# Confidential Information of ARM, Inc.
# Use subject to ARM license.
# Copyright (c) 2026 ARM, Inc.

# ACI Version r0p0

# Reifier 4.0.0

VERSION 5.7 ;

BUSBITCHARS "[]" ;

#name: High Density Single Port SRAM HVT RVT Compiler | TSMC CLN65LP Process 0.525um^2 Bit Cell 256 Rows Per Bank
#version: r0p0
#comment: 
#configuration:  -activity_factor 50 -back_biasing off -bits 64 -bmux on -bus_notation on -check_instname on -diodes on -drive 6 -ema on -frequency 250 -instname s8192x64 -left_bus_delim "[" -mux 16 -mvt "" -name_case upper -power_type otc -prefix "" -pwr_gnd_rename vddpe:VDDPE,vddce:VDDCE,vsse:VSSE -rcols 2 -redundancy off -retention on -right_bus_delim "]" -rows_p_bl 256 -rrows 0 -ser none -site_def off -top_layer m5-m9 -words 8192 -wp_size 1 -write_mask off -write_thru off -corners tt_1p20v_1p20v_25c
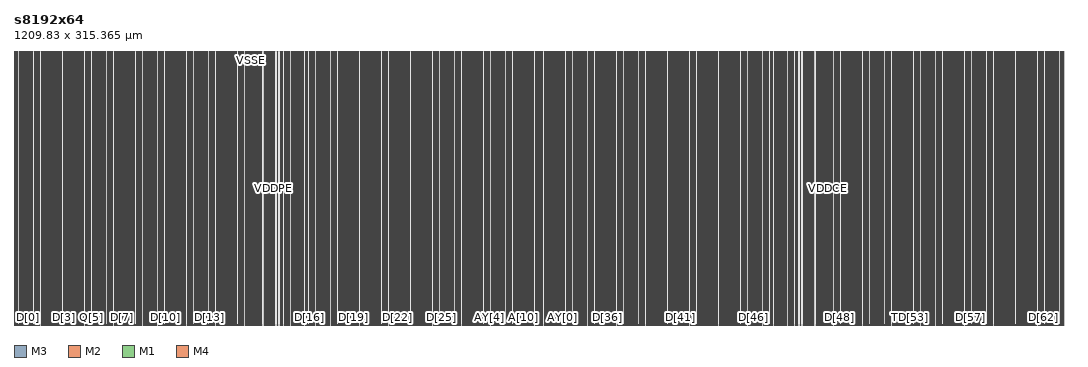
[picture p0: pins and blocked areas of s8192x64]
MACRO s8192x64
  FOREIGN s8192x64 0 0 ;
  SYMMETRY X Y R90 ;
  SIZE 1209.83 BY 315.365 ;
  CLASS BLOCK ;
  PIN TD[31]
    DIRECTION INPUT ;
    USE SIGNAL ;
    SHAPE ABUTMENT ;
    PORT
      LAYER M3 ;
      RECT 595.035 0.0 595.235 0.32 ;
      LAYER M2 ;
      RECT 595.035 0.0 595.235 0.32 ;
      LAYER M1 ;
      RECT 595.035 0.0 595.235 0.32 ;
      END
    ANTENNAGATEAREA 0.0072 ;
    ANTENNADIFFAREA 0.054 ;
    END TD[31]
  PIN AY[12]
    DIRECTION OUTPUT ;
    USE SIGNAL ;
    SHAPE ABUTMENT ;
    PORT
      LAYER M1 ;
      RECT 596.765 0.0 596.965 0.32 ;
      LAYER M2 ;
      RECT 596.765 0.0 596.965 0.32 ;
      LAYER M3 ;
      RECT 596.765 0.0 596.965 0.32 ;
      END
    ANTENNADIFFAREA 0.054 ;
    END AY[12]
  PIN A[11]
    DIRECTION INPUT ;
    USE SIGNAL ;
    SHAPE ABUTMENT ;
    PORT
      LAYER M3 ;
      RECT 593.235 0.0 593.435 0.32 ;
      LAYER M2 ;
      RECT 593.235 0.0 593.435 0.32 ;
      LAYER M1 ;
      RECT 593.235 0.0 593.435 0.32 ;
      END
    ANTENNAGATEAREA 0.0072 ;
    ANTENNADIFFAREA 0.054 ;
    END A[11]
  PIN A[12]
    DIRECTION INPUT ;
    USE SIGNAL ;
    SHAPE ABUTMENT ;
    PORT
      LAYER M1 ;
      RECT 597.57 0.0 597.77 0.32 ;
      LAYER M2 ;
      RECT 597.57 0.0 597.77 0.32 ;
      LAYER M3 ;
      RECT 597.57 0.0 597.77 0.32 ;
      END
    ANTENNAGATEAREA 0.0072 ;
    ANTENNADIFFAREA 0.054 ;
    END A[12]
  PIN D[31]
    DIRECTION INPUT ;
    USE SIGNAL ;
    SHAPE ABUTMENT ;
    PORT
      LAYER M4 ;
      RECT 592.795 0.0 592.995 0.32 ;
      LAYER M3 ;
      RECT 592.795 0.0 592.995 0.32 ;
      LAYER M2 ;
      RECT 592.795 0.0 592.995 0.32 ;
      LAYER M1 ;
      RECT 592.795 0.0 592.995 0.32 ;
      END
    ANTENNAGATEAREA 0.0072 ;
    ANTENNADIFFAREA 0.054 ;
    END D[31]
  PIN TA[12]
    DIRECTION INPUT ;
    USE SIGNAL ;
    SHAPE ABUTMENT ;
    PORT
      LAYER M1 ;
      RECT 597.95 0.0 598.15 0.32 ;
      LAYER M2 ;
      RECT 597.95 0.0 598.15 0.32 ;
      END
    ANTENNAGATEAREA 0.0072 ;
    ANTENNADIFFAREA 0.054 ;
    END TA[12]
  PIN TA[11]
    DIRECTION INPUT ;
    USE SIGNAL ;
    SHAPE ABUTMENT ;
    PORT
      LAYER M3 ;
      RECT 592.285 0.0 592.485 0.32 ;
      LAYER M2 ;
      RECT 592.285 0.0 592.485 0.32 ;
      LAYER M1 ;
      RECT 592.285 0.0 592.485 0.32 ;
      END
    ANTENNAGATEAREA 0.0072 ;
    ANTENNADIFFAREA 0.054 ;
    END TA[11]
  PIN SO[0]
    DIRECTION OUTPUT ;
    USE SIGNAL ;
    SHAPE ABUTMENT ;
    PORT
      LAYER M1 ;
      RECT 602.525 0.0 602.725 0.32 ;
      LAYER M2 ;
      RECT 602.525 0.0 602.725 0.32 ;
      LAYER M3 ;
      RECT 602.525 0.0 602.725 0.32 ;
      END
    ANTENNADIFFAREA 0.054 ;
    END SO[0]
  PIN Q[31]
    DIRECTION OUTPUT ;
    USE SIGNAL ;
    SHAPE ABUTMENT ;
    PORT
      LAYER M3 ;
      RECT 591.2 0.0 591.41 0.32 ;
      LAYER M2 ;
      RECT 591.2 0.0 591.41 0.32 ;
      LAYER M1 ;
      RECT 591.2 0.0 591.41 0.32 ;
      END
    ANTENNADIFFAREA 0.054 ;
    END Q[31]
  PIN SO[1]
    DIRECTION OUTPUT ;
    USE SIGNAL ;
    SHAPE ABUTMENT ;
    PORT
      LAYER M1 ;
      RECT 606.825 0.0 607.025 0.32 ;
      LAYER M2 ;
      RECT 606.825 0.0 607.025 0.32 ;
      LAYER M3 ;
      RECT 606.825 0.0 607.025 0.32 ;
      END
    ANTENNADIFFAREA 0.054 ;
    END SO[1]
  PIN AY[11]
    DIRECTION OUTPUT ;
    USE SIGNAL ;
    SHAPE ABUTMENT ;
    PORT
      LAYER M3 ;
      RECT 590.235 0.0 590.435 0.32 ;
      LAYER M2 ;
      RECT 590.235 0.0 590.435 0.32 ;
      LAYER M1 ;
      RECT 590.235 0.0 590.435 0.32 ;
      END
    ANTENNADIFFAREA 0.054 ;
    END AY[11]
  PIN TA[3]
    DIRECTION INPUT ;
    USE SIGNAL ;
    SHAPE ABUTMENT ;
    PORT
      LAYER M1 ;
      RECT 611.96 0.0 612.16 0.32 ;
      LAYER M2 ;
      RECT 611.96 0.0 612.16 0.32 ;
      END
    ANTENNAGATEAREA 0.0072 ;
    ANTENNADIFFAREA 0.054 ;
    END TA[3]
  PIN A[10]
    DIRECTION INPUT ;
    USE SIGNAL ;
    SHAPE ABUTMENT ;
    PORT
      LAYER M3 ;
      RECT 587.33 0.0 587.53 0.32 ;
      LAYER M2 ;
      RECT 587.33 0.0 587.53 0.32 ;
      LAYER M1 ;
      RECT 587.33 0.0 587.53 0.32 ;
      END
    ANTENNAGATEAREA 0.0072 ;
    ANTENNADIFFAREA 0.054 ;
    END A[10]
  PIN A[3]
    DIRECTION INPUT ;
    USE SIGNAL ;
    SHAPE ABUTMENT ;
    PORT
      LAYER M1 ;
      RECT 612.38 0.0 612.58 0.32 ;
      LAYER M2 ;
      RECT 612.38 0.0 612.58 0.32 ;
      LAYER M3 ;
      RECT 612.38 0.0 612.58 0.32 ;
      END
    ANTENNAGATEAREA 0.0072 ;
    ANTENNADIFFAREA 0.054 ;
    END A[3]
  PIN TA[10]
    DIRECTION INPUT ;
    USE SIGNAL ;
    SHAPE ABUTMENT ;
    PORT
      LAYER M3 ;
      RECT 586.97 0.0 587.17 0.32 ;
      LAYER M2 ;
      RECT 586.97 0.0 587.17 0.32 ;
      LAYER M1 ;
      RECT 586.97 0.0 587.17 0.32 ;
      END
    ANTENNAGATEAREA 0.0072 ;
    ANTENNADIFFAREA 0.054 ;
    END TA[10]
  PIN AY[3]
    DIRECTION OUTPUT ;
    USE SIGNAL ;
    SHAPE ABUTMENT ;
    PORT
      LAYER M1 ;
      RECT 613.075 0.0 613.275 0.32 ;
      LAYER M2 ;
      RECT 613.075 0.0 613.275 0.32 ;
      LAYER M3 ;
      RECT 613.075 0.0 613.275 0.32 ;
      END
    ANTENNADIFFAREA 0.054 ;
    END AY[3]
  PIN AY[10]
    DIRECTION OUTPUT ;
    USE SIGNAL ;
    SHAPE ABUTMENT ;
    PORT
      LAYER M3 ;
      RECT 585.545 0.0 585.745 0.32 ;
      LAYER M2 ;
      RECT 585.545 0.0 585.745 0.32 ;
      LAYER M1 ;
      RECT 585.545 0.0 585.745 0.32 ;
      END
    ANTENNADIFFAREA 0.054 ;
    END AY[10]
  PIN TD[32]
    DIRECTION INPUT ;
    USE SIGNAL ;
    SHAPE ABUTMENT ;
    PORT
      LAYER M1 ;
      RECT 614.53 0.0 614.73 0.32 ;
      LAYER M2 ;
      RECT 614.53 0.0 614.73 0.32 ;
      LAYER M3 ;
      RECT 614.53 0.0 614.73 0.32 ;
      END
    ANTENNAGATEAREA 0.0072 ;
    ANTENNADIFFAREA 0.054 ;
    END TD[32]
  PIN TA[9]
    DIRECTION INPUT ;
    USE SIGNAL ;
    SHAPE ABUTMENT ;
    PORT
      LAYER M3 ;
      RECT 580.9 0.0 581.1 0.32 ;
      LAYER M2 ;
      RECT 580.9 0.0 581.1 0.32 ;
      LAYER M1 ;
      RECT 580.9 0.0 581.1 0.32 ;
      END
    ANTENNAGATEAREA 0.0072 ;
    ANTENNADIFFAREA 0.054 ;
    END TA[9]
  PIN D[32]
    DIRECTION INPUT ;
    USE SIGNAL ;
    SHAPE ABUTMENT ;
    PORT
      LAYER M1 ;
      RECT 616.855 0.0 617.055 0.32 ;
      LAYER M2 ;
      RECT 616.855 0.0 617.055 0.32 ;
      LAYER M3 ;
      RECT 616.855 0.0 617.055 0.32 ;
      LAYER M4 ;
      RECT 616.855 0.0 617.055 0.32 ;
      END
    ANTENNAGATEAREA 0.0072 ;
    ANTENNADIFFAREA 0.054 ;
    END D[32]
  PIN A[9]
    DIRECTION INPUT ;
    USE SIGNAL ;
    SHAPE ABUTMENT ;
    PORT
      LAYER M3 ;
      RECT 580.515 0.0 580.715 0.32 ;
      LAYER M2 ;
      RECT 580.515 0.0 580.715 0.32 ;
      LAYER M1 ;
      RECT 580.515 0.0 580.715 0.32 ;
      END
    ANTENNAGATEAREA 0.0072 ;
    ANTENNADIFFAREA 0.054 ;
    END A[9]
  PIN Q[32]
    DIRECTION OUTPUT ;
    USE SIGNAL ;
    SHAPE ABUTMENT ;
    PORT
      LAYER M1 ;
      RECT 618.53 0.0 618.73 0.32 ;
      LAYER M2 ;
      RECT 618.53 0.0 618.73 0.32 ;
      LAYER M3 ;
      RECT 618.53 0.0 618.73 0.32 ;
      END
    ANTENNADIFFAREA 0.054 ;
    END Q[32]
  PIN AY[9]
    DIRECTION OUTPUT ;
    USE SIGNAL ;
    SHAPE ABUTMENT ;
    PORT
      LAYER M3 ;
      RECT 579.79 0.0 579.99 0.32 ;
      LAYER M2 ;
      RECT 579.79 0.0 579.99 0.32 ;
      LAYER M1 ;
      RECT 579.79 0.0 579.99 0.32 ;
      END
    ANTENNADIFFAREA 0.054 ;
    END AY[9]
  PIN AY[2]
    DIRECTION OUTPUT ;
    USE SIGNAL ;
    SHAPE ABUTMENT ;
    PORT
      LAYER M1 ;
      RECT 622.27 0.0 622.47 0.32 ;
      LAYER M2 ;
      RECT 622.27 0.0 622.47 0.32 ;
      LAYER M3 ;
      RECT 622.27 0.0 622.47 0.32 ;
      END
    ANTENNADIFFAREA 0.054 ;
    END AY[2]
  PIN TD[30]
    DIRECTION INPUT ;
    USE SIGNAL ;
    SHAPE ABUTMENT ;
    PORT
      LAYER M3 ;
      RECT 578.445 0.0 578.645 0.32 ;
      LAYER M1 ;
      RECT 578.445 0.0 578.645 0.32 ;
      LAYER M2 ;
      RECT 578.335 0.0 578.645 0.32 ;
      END
    ANTENNAGATEAREA 0.0072 ;
    ANTENNADIFFAREA 0.054 ;
    END TD[30]
  PIN A[2]
    DIRECTION INPUT ;
    USE SIGNAL ;
    SHAPE ABUTMENT ;
    PORT
      LAYER M1 ;
      RECT 623.505 0.0 623.705 0.32 ;
      LAYER M2 ;
      RECT 623.505 0.0 623.705 0.32 ;
      LAYER M3 ;
      RECT 623.505 0.0 623.705 0.32 ;
      END
    ANTENNAGATEAREA 0.0072 ;
    ANTENNADIFFAREA 0.054 ;
    END A[2]
  PIN D[30]
    DIRECTION INPUT ;
    USE SIGNAL ;
    SHAPE ABUTMENT ;
    PORT
      LAYER M4 ;
      RECT 575.925 0.0 576.125 0.32 ;
      LAYER M3 ;
      RECT 575.925 0.0 576.125 0.32 ;
      LAYER M2 ;
      RECT 575.925 0.0 576.125 0.32 ;
      LAYER M1 ;
      RECT 575.925 0.0 576.125 0.32 ;
      END
    ANTENNAGATEAREA 0.0072 ;
    ANTENNADIFFAREA 0.054 ;
    END D[30]
  PIN TA[2]
    DIRECTION INPUT ;
    USE SIGNAL ;
    SHAPE ABUTMENT ;
    PORT
      LAYER M1 ;
      RECT 623.975 0.0 624.175 0.32 ;
      LAYER M2 ;
      RECT 623.975 0.0 624.175 0.32 ;
      LAYER M3 ;
      RECT 623.975 0.0 624.175 0.32 ;
      END
    ANTENNAGATEAREA 0.0072 ;
    ANTENNADIFFAREA 0.054 ;
    END TA[2]
  PIN A[8]
    DIRECTION INPUT ;
    USE SIGNAL ;
    SHAPE ABUTMENT ;
    PORT
      LAYER M3 ;
      RECT 575.44 0.0 575.64 0.32 ;
      LAYER M2 ;
      RECT 575.44 0.0 575.64 0.32 ;
      LAYER M1 ;
      RECT 575.44 0.0 575.64 0.32 ;
      END
    ANTENNAGATEAREA 0.0072 ;
    ANTENNADIFFAREA 0.054 ;
    END A[8]
  PIN TA[1]
    DIRECTION INPUT ;
    USE SIGNAL ;
    SHAPE ABUTMENT ;
    PORT
      LAYER M1 ;
      RECT 624.49 0.0 624.69 0.32 ;
      LAYER M2 ;
      RECT 624.49 0.0 624.69 0.32 ;
      LAYER M3 ;
      RECT 624.49 0.0 624.69 0.32 ;
      END
    ANTENNAGATEAREA 0.0072 ;
    ANTENNADIFFAREA 0.054 ;
    END TA[1]
  PIN TA[8]
    DIRECTION INPUT ;
    USE SIGNAL ;
    SHAPE ABUTMENT ;
    PORT
      LAYER M3 ;
      RECT 574.62 0.0 574.82 0.32 ;
      LAYER M2 ;
      RECT 574.62 0.0 574.82 0.32 ;
      LAYER M1 ;
      RECT 574.62 0.0 574.82 0.32 ;
      END
    ANTENNAGATEAREA 0.0072 ;
    ANTENNADIFFAREA 0.054 ;
    END TA[8]
  PIN A[1]
    DIRECTION INPUT ;
    USE SIGNAL ;
    SHAPE ABUTMENT ;
    PORT
      LAYER M1 ;
      RECT 624.87 0.0 625.07 0.32 ;
      LAYER M2 ;
      RECT 624.87 0.0 625.07 0.32 ;
      LAYER M3 ;
      RECT 624.87 0.0 625.07 0.32 ;
      END
    ANTENNAGATEAREA 0.0072 ;
    ANTENNADIFFAREA 0.054 ;
    END A[1]
  PIN Q[30]
    DIRECTION OUTPUT ;
    USE SIGNAL ;
    SHAPE ABUTMENT ;
    PORT
      LAYER M3 ;
      RECT 574.3 0.0 574.5 0.32 ;
      LAYER M2 ;
      RECT 574.3 0.0 574.5 0.32 ;
      LAYER M1 ;
      RECT 574.3 0.0 574.5 0.32 ;
      END
    ANTENNADIFFAREA 0.054 ;
    END Q[30]
  PIN AY[1]
    DIRECTION OUTPUT ;
    USE SIGNAL ;
    SHAPE ABUTMENT ;
    PORT
      LAYER M1 ;
      RECT 625.855 0.0 626.055 0.32 ;
      LAYER M2 ;
      RECT 625.855 0.0 626.055 0.32 ;
      LAYER M3 ;
      RECT 625.855 0.0 626.055 0.32 ;
      END
    ANTENNADIFFAREA 0.054 ;
    END AY[1]
  PIN AY[8]
    DIRECTION OUTPUT ;
    USE SIGNAL ;
    SHAPE ABUTMENT ;
    PORT
      LAYER M3 ;
      RECT 573.34 0.0 573.54 0.32 ;
      LAYER M2 ;
      RECT 573.34 0.0 573.54 0.32 ;
      LAYER M1 ;
      RECT 573.34 0.0 573.54 0.32 ;
      END
    ANTENNADIFFAREA 0.054 ;
    END AY[8]
  PIN TA[0]
    DIRECTION INPUT ;
    USE SIGNAL ;
    SHAPE ABUTMENT ;
    PORT
      LAYER M1 ;
      RECT 630.445 0.0 630.645 0.32 ;
      LAYER M2 ;
      RECT 630.445 0.0 630.645 0.32 ;
      LAYER M3 ;
      RECT 630.445 0.0 630.645 0.32 ;
      END
    ANTENNAGATEAREA 0.0072 ;
    ANTENNADIFFAREA 0.054 ;
    END TA[0]
  PIN AY[7]
    DIRECTION OUTPUT ;
    USE SIGNAL ;
    SHAPE ABUTMENT ;
    PORT
      LAYER M3 ;
      RECT 566.16 0.0 566.36 0.32 ;
      LAYER M2 ;
      RECT 566.16 0.0 566.36 0.32 ;
      LAYER M1 ;
      RECT 566.16 0.0 566.36 0.32 ;
      END
    ANTENNADIFFAREA 0.054 ;
    END AY[7]
  PIN A[0]
    DIRECTION INPUT ;
    USE SIGNAL ;
    SHAPE ABUTMENT ;
    PORT
      LAYER M1 ;
      RECT 630.905 0.0 631.105 0.32 ;
      LAYER M2 ;
      RECT 630.905 0.0 631.105 0.32 ;
      LAYER M3 ;
      RECT 630.905 0.0 631.105 0.32 ;
      END
    ANTENNAGATEAREA 0.0072 ;
    ANTENNADIFFAREA 0.054 ;
    END A[0]
  PIN A[7]
    DIRECTION INPUT ;
    USE SIGNAL ;
    SHAPE ABUTMENT ;
    PORT
      LAYER M2 ;
      RECT 564.675 0.0 564.875 0.32 ;
      LAYER M1 ;
      RECT 564.675 0.0 564.875 0.32 ;
      END
    ANTENNAGATEAREA 0.0072 ;
    ANTENNADIFFAREA 0.054 ;
    END A[7]
  PIN TD[33]
    DIRECTION INPUT ;
    USE SIGNAL ;
    SHAPE ABUTMENT ;
    PORT
      LAYER M1 ;
      RECT 631.33 0.0 631.53 0.32 ;
      LAYER M2 ;
      RECT 631.33 0.0 631.53 0.32 ;
      LAYER M3 ;
      RECT 631.33 0.0 631.53 0.32 ;
      END
    ANTENNAGATEAREA 0.0072 ;
    ANTENNADIFFAREA 0.054 ;
    END TD[33]
  PIN TA[7]
    DIRECTION INPUT ;
    USE SIGNAL ;
    SHAPE ABUTMENT ;
    PORT
      LAYER M2 ;
      RECT 564.29 0.0 564.49 0.32 ;
      LAYER M1 ;
      RECT 564.29 0.0 564.49 0.32 ;
      END
    ANTENNAGATEAREA 0.0072 ;
    ANTENNADIFFAREA 0.054 ;
    END TA[7]
  PIN AY[0]
    DIRECTION OUTPUT ;
    USE SIGNAL ;
    SHAPE ABUTMENT ;
    PORT
      LAYER M1 ;
      RECT 632.34 0.0 632.54 0.32 ;
      LAYER M2 ;
      RECT 632.34 0.0 632.54 0.32 ;
      LAYER M3 ;
      RECT 632.34 0.0 632.54 0.32 ;
      END
    ANTENNADIFFAREA 0.054 ;
    END AY[0]
  PIN A[6]
    DIRECTION INPUT ;
    USE SIGNAL ;
    SHAPE ABUTMENT ;
    PORT
      LAYER M3 ;
      RECT 563.81 0.0 564.01 0.32 ;
      LAYER M2 ;
      RECT 563.81 0.0 564.01 0.32 ;
      LAYER M1 ;
      RECT 563.81 0.0 564.01 0.32 ;
      END
    ANTENNAGATEAREA 0.0072 ;
    ANTENNADIFFAREA 0.054 ;
    END A[6]
  PIN D[33]
    DIRECTION INPUT ;
    USE SIGNAL ;
    SHAPE ABUTMENT ;
    PORT
      LAYER M1 ;
      RECT 633.655 0.0 633.855 0.32 ;
      LAYER M2 ;
      RECT 633.655 0.0 633.855 0.32 ;
      LAYER M3 ;
      RECT 633.655 0.0 633.855 0.32 ;
      LAYER M4 ;
      RECT 633.655 0.0 633.855 0.32 ;
      END
    ANTENNAGATEAREA 0.0072 ;
    ANTENNADIFFAREA 0.054 ;
    END D[33]
  PIN TA[6]
    DIRECTION INPUT ;
    USE SIGNAL ;
    SHAPE ABUTMENT ;
    PORT
      LAYER M3 ;
      RECT 563.315 0.0 563.515 0.32 ;
      LAYER M2 ;
      RECT 563.315 0.0 563.515 0.32 ;
      LAYER M1 ;
      RECT 563.315 0.0 563.515 0.32 ;
      END
    ANTENNAGATEAREA 0.0072 ;
    ANTENNADIFFAREA 0.054 ;
    END TA[6]
  PIN Q[33]
    DIRECTION OUTPUT ;
    USE SIGNAL ;
    SHAPE ABUTMENT ;
    PORT
      LAYER M1 ;
      RECT 635.275 0.0 635.475 0.32 ;
      LAYER M2 ;
      RECT 635.275 0.0 635.475 0.32 ;
      LAYER M3 ;
      RECT 635.275 0.0 635.475 0.32 ;
      END
    ANTENNADIFFAREA 0.054 ;
    END Q[33]
  PIN AY[6]
    DIRECTION OUTPUT ;
    USE SIGNAL ;
    SHAPE ABUTMENT ;
    PORT
      LAYER M3 ;
      RECT 561.815 0.0 562.015 0.32 ;
      LAYER M2 ;
      RECT 561.815 0.0 562.015 0.32 ;
      LAYER M1 ;
      RECT 561.815 0.0 562.015 0.32 ;
      END
    ANTENNADIFFAREA 0.054 ;
    END AY[6]
  PIN TCEN
    DIRECTION INPUT ;
    USE SIGNAL ;
    SHAPE ABUTMENT ;
    PORT
      LAYER M1 ;
      RECT 636.225 0.0 636.425 0.32 ;
      LAYER M2 ;
      RECT 636.225 0.0 636.425 0.32 ;
      LAYER M3 ;
      RECT 636.225 0.0 636.425 0.32 ;
      END
    ANTENNAGATEAREA 0.0072 ;
    ANTENNADIFFAREA 0.054 ;
    END TCEN
  PIN TD[29]
    DIRECTION INPUT ;
    USE SIGNAL ;
    SHAPE ABUTMENT ;
    PORT
      LAYER M3 ;
      RECT 561.255 0.0 561.455 0.32 ;
      LAYER M2 ;
      RECT 561.255 0.0 561.455 0.32 ;
      LAYER M1 ;
      RECT 561.255 0.0 561.455 0.32 ;
      END
    ANTENNAGATEAREA 0.0072 ;
    ANTENNADIFFAREA 0.054 ;
    END TD[29]
  PIN CEN
    DIRECTION INPUT ;
    USE SIGNAL ;
    SHAPE ABUTMENT ;
    PORT
      LAYER M1 ;
      RECT 636.555 0.0 636.755 0.32 ;
      LAYER M2 ;
      RECT 636.555 0.0 636.755 0.32 ;
      END
    ANTENNAGATEAREA 0.0072 ;
    ANTENNADIFFAREA 0.054 ;
    END CEN
  PIN D[29]
    DIRECTION INPUT ;
    USE SIGNAL ;
    SHAPE ABUTMENT ;
    PORT
      LAYER M4 ;
      RECT 559.195 0.0 559.395 0.32 ;
      LAYER M3 ;
      RECT 559.195 0.0 559.395 0.32 ;
      LAYER M2 ;
      RECT 559.195 0.0 559.395 0.32 ;
      LAYER M1 ;
      RECT 559.195 0.0 559.395 0.32 ;
      END
    ANTENNAGATEAREA 0.0072 ;
    ANTENNADIFFAREA 0.054 ;
    END D[29]
  PIN CENY
    DIRECTION OUTPUT ;
    USE SIGNAL ;
    SHAPE ABUTMENT ;
    PORT
      LAYER M1 ;
      RECT 637.31 0.0 637.51 0.32 ;
      LAYER M2 ;
      RECT 637.31 0.0 637.51 0.32 ;
      LAYER M3 ;
      RECT 637.31 0.0 637.51 0.32 ;
      END
    ANTENNADIFFAREA 0.054 ;
    END CENY
  PIN A[5]
    DIRECTION INPUT ;
    USE SIGNAL ;
    SHAPE ABUTMENT ;
    PORT
      LAYER M3 ;
      RECT 558.88 0.0 559.08 0.32 ;
      LAYER M2 ;
      RECT 558.88 0.0 559.08 0.32 ;
      LAYER M1 ;
      RECT 558.88 0.0 559.08 0.32 ;
      END
    ANTENNAGATEAREA 0.0072 ;
    ANTENNADIFFAREA 0.054 ;
    END A[5]
  PIN SE
    DIRECTION INPUT ;
    USE SIGNAL ;
    SHAPE ABUTMENT ;
    PORT
      LAYER M1 ;
      RECT 641.055 0.0 641.255 0.32 ;
      LAYER M2 ;
      RECT 641.055 0.0 641.255 0.32 ;
      LAYER M3 ;
      RECT 641.055 0.0 641.255 0.32 ;
      END
    ANTENNAGATEAREA 0.0072 ;
    ANTENNADIFFAREA 0.054 ;
    END SE
  PIN TA[5]
    DIRECTION INPUT ;
    USE SIGNAL ;
    SHAPE ABUTMENT ;
    PORT
      LAYER M3 ;
      RECT 558.505 0.0 558.705 0.32 ;
      LAYER M2 ;
      RECT 558.505 0.0 558.705 0.32 ;
      LAYER M1 ;
      RECT 558.505 0.0 558.705 0.32 ;
      END
    ANTENNAGATEAREA 0.0072 ;
    ANTENNADIFFAREA 0.054 ;
    END TA[5]
  PIN TEN
    DIRECTION INPUT ;
    USE SIGNAL ;
    SHAPE ABUTMENT ;
    PORT
      LAYER M1 ;
      RECT 643.5 0.0 643.7 0.32 ;
      LAYER M2 ;
      RECT 643.5 0.0 643.7 0.32 ;
      END
    ANTENNAGATEAREA 0.0072 ;
    ANTENNADIFFAREA 0.054 ;
    END TEN
  PIN Q[29]
    DIRECTION OUTPUT ;
    USE SIGNAL ;
    SHAPE ABUTMENT ;
    PORT
      LAYER M3 ;
      RECT 557.725 0.0 557.925 0.32 ;
      LAYER M2 ;
      RECT 557.725 0.0 557.925 0.32 ;
      LAYER M1 ;
      RECT 557.725 0.0 557.925 0.32 ;
      END
    ANTENNADIFFAREA 0.054 ;
    END Q[29]
  PIN WENY
    DIRECTION OUTPUT ;
    USE SIGNAL ;
    SHAPE ABUTMENT ;
    PORT
      LAYER M1 ;
      RECT 646.675 0.0 646.875 0.32 ;
      LAYER M2 ;
      RECT 646.675 0.0 646.875 0.32 ;
      LAYER M3 ;
      RECT 646.675 0.0 646.875 0.32 ;
      END
    ANTENNADIFFAREA 0.054 ;
    END WENY
  PIN AY[5]
    DIRECTION OUTPUT ;
    USE SIGNAL ;
    SHAPE ABUTMENT ;
    PORT
      LAYER M3 ;
      RECT 556.44 0.0 556.64 0.32 ;
      LAYER M2 ;
      RECT 556.44 0.0 556.64 0.32 ;
      LAYER M1 ;
      RECT 556.44 0.0 556.64 0.32 ;
      END
    ANTENNADIFFAREA 0.054 ;
    END AY[5]
  PIN DFTRAMBYP
    DIRECTION INPUT ;
    USE SIGNAL ;
    SHAPE ABUTMENT ;
    PORT
      LAYER M1 ;
      RECT 647.18 0.0 647.38 0.32 ;
      LAYER M2 ;
      RECT 647.18 0.0 647.38 0.32 ;
      LAYER M3 ;
      RECT 647.18 0.0 647.38 0.32 ;
      END
    ANTENNAGATEAREA 0.0072 ;
    ANTENNADIFFAREA 0.054 ;
    END DFTRAMBYP
  PIN AY[4]
    DIRECTION OUTPUT ;
    USE SIGNAL ;
    SHAPE ABUTMENT ;
    PORT
      LAYER M3 ;
      RECT 547.975 0.0 548.175 0.32 ;
      LAYER M2 ;
      RECT 547.975 0.0 548.175 0.32 ;
      LAYER M1 ;
      RECT 547.975 0.0 548.175 0.32 ;
      END
    ANTENNADIFFAREA 0.054 ;
    END AY[4]
  PIN WEN
    DIRECTION INPUT ;
    USE SIGNAL ;
    SHAPE ABUTMENT ;
    PORT
      LAYER M1 ;
      RECT 647.63 0.0 647.83 0.32 ;
      LAYER M2 ;
      RECT 647.63 0.0 647.83 0.32 ;
      LAYER M3 ;
      RECT 647.63 0.0 647.83 0.32 ;
      END
    ANTENNAGATEAREA 0.0072 ;
    ANTENNADIFFAREA 0.054 ;
    END WEN
  PIN TA[4]
    DIRECTION INPUT ;
    USE SIGNAL ;
    SHAPE ABUTMENT ;
    PORT
      LAYER M3 ;
      RECT 547.07 0.0 547.27 0.32 ;
      LAYER M2 ;
      RECT 547.07 0.0 547.27 0.32 ;
      LAYER M1 ;
      RECT 547.07 0.0 547.27 0.32 ;
      END
    ANTENNAGATEAREA 0.0072 ;
    ANTENNADIFFAREA 0.054 ;
    END TA[4]
  PIN TWEN
    DIRECTION INPUT ;
    USE SIGNAL ;
    SHAPE ABUTMENT ;
    PORT
      LAYER M2 ;
      RECT 647.965 0.0 648.255 0.32 ;
      LAYER M1 ;
      RECT 648.055 0.0 648.255 0.32 ;
      LAYER M3 ;
      RECT 648.055 0.0 648.255 0.32 ;
      END
    ANTENNAGATEAREA 0.0072 ;
    ANTENNADIFFAREA 0.054 ;
    END TWEN
  PIN A[4]
    DIRECTION INPUT ;
    USE SIGNAL ;
    SHAPE ABUTMENT ;
    PORT
      LAYER M3 ;
      RECT 546.09 0.0 546.29 0.32 ;
      LAYER M2 ;
      RECT 546.09 0.0 546.29 0.32 ;
      LAYER M1 ;
      RECT 546.09 0.0 546.29 0.32 ;
      END
    ANTENNAGATEAREA 0.0072 ;
    ANTENNADIFFAREA 0.054 ;
    END A[4]
  PIN TD[34]
    DIRECTION INPUT ;
    USE SIGNAL ;
    SHAPE ABUTMENT ;
    PORT
      LAYER M1 ;
      RECT 648.395 0.0 648.595 0.32 ;
      LAYER M2 ;
      RECT 648.395 0.0 648.595 0.32 ;
      LAYER M3 ;
      RECT 648.395 0.0 648.595 0.32 ;
      END
    ANTENNAGATEAREA 0.0072 ;
    ANTENNADIFFAREA 0.054 ;
    END TD[34]
  PIN TD[28]
    DIRECTION INPUT ;
    USE SIGNAL ;
    SHAPE ABUTMENT ;
    PORT
      LAYER M3 ;
      RECT 544.635 0.0 544.835 0.32 ;
      LAYER M2 ;
      RECT 544.635 0.0 544.835 0.32 ;
      LAYER M1 ;
      RECT 544.635 0.0 544.835 0.32 ;
      END
    ANTENNAGATEAREA 0.0072 ;
    ANTENNADIFFAREA 0.054 ;
    END TD[28]
  PIN D[34]
    DIRECTION INPUT ;
    USE SIGNAL ;
    SHAPE ABUTMENT ;
    PORT
      LAYER M1 ;
      RECT 650.475 0.0 650.675 0.32 ;
      LAYER M2 ;
      RECT 650.475 0.0 650.675 0.32 ;
      LAYER M3 ;
      RECT 650.475 0.0 650.675 0.32 ;
      LAYER M4 ;
      RECT 650.475 0.0 650.675 0.32 ;
      END
    ANTENNAGATEAREA 0.0072 ;
    ANTENNADIFFAREA 0.054 ;
    END D[34]
  PIN EMA[1]
    DIRECTION INPUT ;
    USE SIGNAL ;
    SHAPE ABUTMENT ;
    PORT
      LAYER M3 ;
      RECT 543.535 0.0 543.735 0.32 ;
      LAYER M2 ;
      RECT 543.535 0.0 543.735 0.32 ;
      LAYER M1 ;
      RECT 543.535 0.0 543.735 0.32 ;
      END
    ANTENNAGATEAREA 0.0072 ;
    ANTENNADIFFAREA 0.054 ;
    END EMA[1]
  PIN Q[34]
    DIRECTION OUTPUT ;
    USE SIGNAL ;
    SHAPE ABUTMENT ;
    PORT
      LAYER M1 ;
      RECT 652.125 0.0 652.325 0.32 ;
      LAYER M2 ;
      RECT 652.125 0.0 652.325 0.32 ;
      LAYER M3 ;
      RECT 652.125 0.0 652.325 0.32 ;
      END
    ANTENNADIFFAREA 0.054 ;
    END Q[34]
  PIN D[28]
    DIRECTION INPUT ;
    USE SIGNAL ;
    SHAPE ABUTMENT ;
    PORT
      LAYER M4 ;
      RECT 542.395 0.0 542.595 0.32 ;
      LAYER M3 ;
      RECT 542.395 0.0 542.595 0.32 ;
      LAYER M2 ;
      RECT 542.395 0.0 542.595 0.32 ;
      LAYER M1 ;
      RECT 542.395 0.0 542.595 0.32 ;
      END
    ANTENNAGATEAREA 0.0072 ;
    ANTENNADIFFAREA 0.054 ;
    END D[28]
  PIN CLK
    DIRECTION INPUT ;
    USE SIGNAL ;
    SHAPE ABUTMENT ;
    PORT
      LAYER M1 ;
      RECT 653.31 0.0 653.51 0.32 ;
      LAYER M2 ;
      RECT 653.31 0.0 653.51 0.32 ;
      LAYER M3 ;
      RECT 653.31 0.0 653.51 0.32 ;
      END
    ANTENNAGATEAREA 0.0072 ;
    ANTENNADIFFAREA 0.054 ;
    END CLK
  PIN EMAW[1]
    DIRECTION INPUT ;
    USE SIGNAL ;
    SHAPE ABUTMENT ;
    PORT
      LAYER M3 ;
      RECT 542.045 0.0 542.245 0.32 ;
      LAYER M2 ;
      RECT 542.045 0.0 542.245 0.32 ;
      LAYER M1 ;
      RECT 542.045 0.0 542.245 0.32 ;
      END
    ANTENNAGATEAREA 0.0072 ;
    ANTENNADIFFAREA 0.054 ;
    END EMAW[1]
  PIN TD[35]
    DIRECTION INPUT ;
    USE SIGNAL ;
    SHAPE ABUTMENT ;
    PORT
      LAYER M1 ;
      RECT 664.895 0.0 665.095 0.32 ;
      LAYER M2 ;
      RECT 664.895 0.0 665.095 0.32 ;
      LAYER M3 ;
      RECT 664.895 0.0 665.095 0.32 ;
      END
    ANTENNAGATEAREA 0.0072 ;
    ANTENNADIFFAREA 0.054 ;
    END TD[35]
  PIN EMAW[0]
    DIRECTION INPUT ;
    USE SIGNAL ;
    SHAPE ABUTMENT ;
    PORT
      LAYER M3 ;
      RECT 541.665 0.0 541.865 0.32 ;
      LAYER M2 ;
      RECT 541.665 0.0 541.865 0.32 ;
      LAYER M1 ;
      RECT 541.665 0.0 541.865 0.32 ;
      END
    ANTENNAGATEAREA 0.0072 ;
    ANTENNADIFFAREA 0.054 ;
    END EMAW[0]
  PIN RET1N
    DIRECTION INPUT ;
    USE SIGNAL ;
    SHAPE ABUTMENT ;
    PORT
      LAYER M1 ;
      RECT 665.92 0.0 666.12 0.32 ;
      LAYER M2 ;
      RECT 665.92 0.0 666.12 0.32 ;
      LAYER M3 ;
      RECT 665.92 0.0 666.12 0.32 ;
      END
    ANTENNAGATEAREA 0.0072 ;
    ANTENNADIFFAREA 0.054 ;
    END RET1N
  PIN Q[28]
    DIRECTION OUTPUT ;
    USE SIGNAL ;
    SHAPE ABUTMENT ;
    PORT
      LAYER M3 ;
      RECT 540.725 0.0 540.925 0.32 ;
      LAYER M2 ;
      RECT 540.725 0.0 540.925 0.32 ;
      LAYER M1 ;
      RECT 540.725 0.0 540.925 0.32 ;
      END
    ANTENNADIFFAREA 0.054 ;
    END Q[28]
  PIN D[35]
    DIRECTION INPUT ;
    USE SIGNAL ;
    SHAPE ABUTMENT ;
    PORT
      LAYER M1 ;
      RECT 667.28 0.0 667.48 0.32 ;
      LAYER M2 ;
      RECT 667.28 0.0 667.48 0.32 ;
      LAYER M3 ;
      RECT 667.28 0.0 667.48 0.32 ;
      LAYER M4 ;
      RECT 667.28 0.0 667.48 0.32 ;
      END
    ANTENNAGATEAREA 0.0072 ;
    ANTENNADIFFAREA 0.054 ;
    END D[35]
  PIN EMA[2]
    DIRECTION INPUT ;
    USE SIGNAL ;
    SHAPE ABUTMENT ;
    PORT
      LAYER M3 ;
      RECT 539.55 0.0 539.75 0.32 ;
      LAYER M2 ;
      RECT 539.55 0.0 539.75 0.32 ;
      LAYER M1 ;
      RECT 539.55 0.0 539.75 0.32 ;
      END
    ANTENNAGATEAREA 0.0072 ;
    ANTENNADIFFAREA 0.054 ;
    END EMA[2]
  PIN Q[35]
    DIRECTION OUTPUT ;
    USE SIGNAL ;
    SHAPE ABUTMENT ;
    PORT
      LAYER M1 ;
      RECT 668.87 0.0 669.07 0.32 ;
      LAYER M2 ;
      RECT 668.87 0.0 669.07 0.32 ;
      LAYER M3 ;
      RECT 668.87 0.0 669.07 0.32 ;
      END
    ANTENNADIFFAREA 0.054 ;
    END Q[35]
  PIN EMA[0]
    DIRECTION INPUT ;
    USE SIGNAL ;
    SHAPE ABUTMENT ;
    PORT
      LAYER M3 ;
      RECT 538.795 0.0 538.995 0.32 ;
      LAYER M2 ;
      RECT 538.795 0.0 538.995 0.32 ;
      LAYER M1 ;
      RECT 538.795 0.0 538.995 0.32 ;
      END
    ANTENNAGATEAREA 0.0072 ;
    ANTENNADIFFAREA 0.054 ;
    END EMA[0]
  PIN TD[36]
    DIRECTION INPUT ;
    USE SIGNAL ;
    SHAPE ABUTMENT ;
    PORT
      LAYER M1 ;
      RECT 681.79 0.0 681.99 0.32 ;
      LAYER M2 ;
      RECT 681.79 0.0 681.99 0.32 ;
      LAYER M3 ;
      RECT 681.79 0.0 681.99 0.32 ;
      END
    ANTENNAGATEAREA 0.0072 ;
    ANTENNADIFFAREA 0.054 ;
    END TD[36]
  PIN TD[27]
    DIRECTION INPUT ;
    USE SIGNAL ;
    SHAPE ABUTMENT ;
    PORT
      LAYER M3 ;
      RECT 527.84 0.0 528.04 0.32 ;
      LAYER M2 ;
      RECT 527.84 0.0 528.04 0.32 ;
      LAYER M1 ;
      RECT 527.84 0.0 528.04 0.32 ;
      END
    ANTENNAGATEAREA 0.0072 ;
    ANTENNADIFFAREA 0.054 ;
    END TD[27]
  PIN D[36]
    DIRECTION INPUT ;
    USE SIGNAL ;
    SHAPE ABUTMENT ;
    PORT
      LAYER M1 ;
      RECT 684.09 0.0 684.29 0.32 ;
      LAYER M2 ;
      RECT 684.09 0.0 684.29 0.32 ;
      LAYER M3 ;
      RECT 684.09 0.0 684.29 0.32 ;
      LAYER M4 ;
      RECT 684.09 0.0 684.29 0.32 ;
      END
    ANTENNAGATEAREA 0.0072 ;
    ANTENNADIFFAREA 0.054 ;
    END D[36]
  PIN D[27]
    DIRECTION INPUT ;
    USE SIGNAL ;
    SHAPE ABUTMENT ;
    PORT
      LAYER M4 ;
      RECT 525.54 0.0 525.74 0.32 ;
      LAYER M3 ;
      RECT 525.54 0.0 525.74 0.32 ;
      LAYER M2 ;
      RECT 525.54 0.0 525.74 0.32 ;
      LAYER M1 ;
      RECT 525.54 0.0 525.74 0.32 ;
      END
    ANTENNAGATEAREA 0.0072 ;
    ANTENNADIFFAREA 0.054 ;
    END D[27]
  PIN Q[36]
    DIRECTION OUTPUT ;
    USE SIGNAL ;
    SHAPE ABUTMENT ;
    PORT
      LAYER M1 ;
      RECT 685.725 0.0 685.925 0.32 ;
      LAYER M2 ;
      RECT 685.725 0.0 685.925 0.32 ;
      LAYER M3 ;
      RECT 685.725 0.0 685.925 0.32 ;
      END
    ANTENNADIFFAREA 0.054 ;
    END Q[36]
  PIN Q[27]
    DIRECTION OUTPUT ;
    USE SIGNAL ;
    SHAPE ABUTMENT ;
    PORT
      LAYER M3 ;
      RECT 523.905 0.0 524.105 0.32 ;
      LAYER M2 ;
      RECT 523.905 0.0 524.105 0.32 ;
      LAYER M1 ;
      RECT 523.905 0.0 524.105 0.32 ;
      END
    ANTENNADIFFAREA 0.054 ;
    END Q[27]
  PIN TD[37]
    DIRECTION INPUT ;
    USE SIGNAL ;
    SHAPE ABUTMENT ;
    PORT
      LAYER M1 ;
      RECT 698.59 0.0 698.79 0.32 ;
      LAYER M2 ;
      RECT 698.59 0.0 698.79 0.32 ;
      LAYER M3 ;
      RECT 698.59 0.0 698.79 0.32 ;
      END
    ANTENNAGATEAREA 0.0072 ;
    ANTENNADIFFAREA 0.054 ;
    END TD[37]
  PIN TD[26]
    DIRECTION INPUT ;
    USE SIGNAL ;
    SHAPE ABUTMENT ;
    PORT
      LAYER M3 ;
      RECT 511.04 0.0 511.24 0.32 ;
      LAYER M2 ;
      RECT 511.04 0.0 511.24 0.32 ;
      LAYER M1 ;
      RECT 511.04 0.0 511.24 0.32 ;
      END
    ANTENNAGATEAREA 0.0072 ;
    ANTENNADIFFAREA 0.054 ;
    END TD[26]
  PIN D[37]
    DIRECTION INPUT ;
    USE SIGNAL ;
    SHAPE ABUTMENT ;
    PORT
      LAYER M1 ;
      RECT 700.89 0.0 701.09 0.32 ;
      LAYER M2 ;
      RECT 700.89 0.0 701.09 0.32 ;
      LAYER M3 ;
      RECT 700.89 0.0 701.09 0.32 ;
      LAYER M4 ;
      RECT 700.89 0.0 701.09 0.32 ;
      END
    ANTENNAGATEAREA 0.0072 ;
    ANTENNADIFFAREA 0.054 ;
    END D[37]
  PIN D[26]
    DIRECTION INPUT ;
    USE SIGNAL ;
    SHAPE ABUTMENT ;
    PORT
      LAYER M4 ;
      RECT 508.74 0.0 508.94 0.32 ;
      LAYER M3 ;
      RECT 508.74 0.0 508.94 0.32 ;
      LAYER M2 ;
      RECT 508.74 0.0 508.94 0.32 ;
      LAYER M1 ;
      RECT 508.74 0.0 508.94 0.32 ;
      END
    ANTENNAGATEAREA 0.0072 ;
    ANTENNADIFFAREA 0.054 ;
    END D[26]
  PIN Q[37]
    DIRECTION OUTPUT ;
    USE SIGNAL ;
    SHAPE ABUTMENT ;
    PORT
      LAYER M1 ;
      RECT 702.525 0.0 702.725 0.32 ;
      LAYER M2 ;
      RECT 702.525 0.0 702.725 0.32 ;
      LAYER M3 ;
      RECT 702.525 0.0 702.725 0.32 ;
      END
    ANTENNADIFFAREA 0.054 ;
    END Q[37]
  PIN Q[26]
    DIRECTION OUTPUT ;
    USE SIGNAL ;
    SHAPE ABUTMENT ;
    PORT
      LAYER M3 ;
      RECT 507.105 0.0 507.305 0.32 ;
      LAYER M2 ;
      RECT 507.105 0.0 507.305 0.32 ;
      LAYER M1 ;
      RECT 507.105 0.0 507.305 0.32 ;
      END
    ANTENNADIFFAREA 0.054 ;
    END Q[26]
  PIN TD[38]
    DIRECTION INPUT ;
    USE SIGNAL ;
    SHAPE ABUTMENT ;
    PORT
      LAYER M1 ;
      RECT 715.39 0.0 715.59 0.32 ;
      LAYER M2 ;
      RECT 715.39 0.0 715.59 0.32 ;
      LAYER M3 ;
      RECT 715.39 0.0 715.59 0.32 ;
      END
    ANTENNAGATEAREA 0.0072 ;
    ANTENNADIFFAREA 0.054 ;
    END TD[38]
  PIN TD[25]
    DIRECTION INPUT ;
    USE SIGNAL ;
    SHAPE ABUTMENT ;
    PORT
      LAYER M3 ;
      RECT 494.24 0.0 494.44 0.32 ;
      LAYER M2 ;
      RECT 494.24 0.0 494.44 0.32 ;
      LAYER M1 ;
      RECT 494.24 0.0 494.44 0.32 ;
      END
    ANTENNAGATEAREA 0.0072 ;
    ANTENNADIFFAREA 0.054 ;
    END TD[25]
  PIN D[38]
    DIRECTION INPUT ;
    USE SIGNAL ;
    SHAPE ABUTMENT ;
    PORT
      LAYER M1 ;
      RECT 717.69 0.0 717.89 0.32 ;
      LAYER M2 ;
      RECT 717.69 0.0 717.89 0.32 ;
      LAYER M3 ;
      RECT 717.69 0.0 717.89 0.32 ;
      LAYER M4 ;
      RECT 717.69 0.0 717.89 0.32 ;
      END
    ANTENNAGATEAREA 0.0072 ;
    ANTENNADIFFAREA 0.054 ;
    END D[38]
  PIN D[25]
    DIRECTION INPUT ;
    USE SIGNAL ;
    SHAPE ABUTMENT ;
    PORT
      LAYER M4 ;
      RECT 491.94 0.0 492.14 0.32 ;
      LAYER M3 ;
      RECT 491.94 0.0 492.14 0.32 ;
      LAYER M2 ;
      RECT 491.94 0.0 492.14 0.32 ;
      LAYER M1 ;
      RECT 491.94 0.0 492.14 0.32 ;
      END
    ANTENNAGATEAREA 0.0072 ;
    ANTENNADIFFAREA 0.054 ;
    END D[25]
  PIN Q[38]
    DIRECTION OUTPUT ;
    USE SIGNAL ;
    SHAPE ABUTMENT ;
    PORT
      LAYER M1 ;
      RECT 719.325 0.0 719.525 0.32 ;
      LAYER M2 ;
      RECT 719.325 0.0 719.525 0.32 ;
      LAYER M3 ;
      RECT 719.325 0.0 719.525 0.32 ;
      END
    ANTENNADIFFAREA 0.054 ;
    END Q[38]
  PIN Q[25]
    DIRECTION OUTPUT ;
    USE SIGNAL ;
    SHAPE ABUTMENT ;
    PORT
      LAYER M3 ;
      RECT 490.305 0.0 490.505 0.32 ;
      LAYER M2 ;
      RECT 490.305 0.0 490.505 0.32 ;
      LAYER M1 ;
      RECT 490.305 0.0 490.505 0.32 ;
      END
    ANTENNADIFFAREA 0.054 ;
    END Q[25]
  PIN TD[39]
    DIRECTION INPUT ;
    USE SIGNAL ;
    SHAPE ABUTMENT ;
    PORT
      LAYER M1 ;
      RECT 732.19 0.0 732.39 0.32 ;
      LAYER M2 ;
      RECT 732.19 0.0 732.39 0.32 ;
      LAYER M3 ;
      RECT 732.19 0.0 732.39 0.32 ;
      END
    ANTENNAGATEAREA 0.0072 ;
    ANTENNADIFFAREA 0.054 ;
    END TD[39]
  PIN TD[24]
    DIRECTION INPUT ;
    USE SIGNAL ;
    SHAPE ABUTMENT ;
    PORT
      LAYER M3 ;
      RECT 477.44 0.0 477.64 0.32 ;
      LAYER M2 ;
      RECT 477.44 0.0 477.64 0.32 ;
      LAYER M1 ;
      RECT 477.44 0.0 477.64 0.32 ;
      END
    ANTENNAGATEAREA 0.0072 ;
    ANTENNADIFFAREA 0.054 ;
    END TD[24]
  PIN D[39]
    DIRECTION INPUT ;
    USE SIGNAL ;
    SHAPE ABUTMENT ;
    PORT
      LAYER M1 ;
      RECT 734.49 0.0 734.69 0.32 ;
      LAYER M2 ;
      RECT 734.49 0.0 734.69 0.32 ;
      LAYER M3 ;
      RECT 734.49 0.0 734.69 0.32 ;
      LAYER M4 ;
      RECT 734.49 0.0 734.69 0.32 ;
      END
    ANTENNAGATEAREA 0.0072 ;
    ANTENNADIFFAREA 0.054 ;
    END D[39]
  PIN D[24]
    DIRECTION INPUT ;
    USE SIGNAL ;
    SHAPE ABUTMENT ;
    PORT
      LAYER M4 ;
      RECT 475.14 0.0 475.34 0.32 ;
      LAYER M3 ;
      RECT 475.14 0.0 475.34 0.32 ;
      LAYER M2 ;
      RECT 475.14 0.0 475.34 0.32 ;
      LAYER M1 ;
      RECT 475.14 0.0 475.34 0.32 ;
      END
    ANTENNAGATEAREA 0.0072 ;
    ANTENNADIFFAREA 0.054 ;
    END D[24]
  PIN Q[39]
    DIRECTION OUTPUT ;
    USE SIGNAL ;
    SHAPE ABUTMENT ;
    PORT
      LAYER M1 ;
      RECT 736.125 0.0 736.325 0.32 ;
      LAYER M2 ;
      RECT 736.125 0.0 736.325 0.32 ;
      LAYER M3 ;
      RECT 736.125 0.0 736.325 0.32 ;
      END
    ANTENNADIFFAREA 0.054 ;
    END Q[39]
  PIN Q[24]
    DIRECTION OUTPUT ;
    USE SIGNAL ;
    SHAPE ABUTMENT ;
    PORT
      LAYER M3 ;
      RECT 473.505 0.0 473.705 0.32 ;
      LAYER M2 ;
      RECT 473.505 0.0 473.705 0.32 ;
      LAYER M1 ;
      RECT 473.505 0.0 473.705 0.32 ;
      END
    ANTENNADIFFAREA 0.054 ;
    END Q[24]
  PIN TD[40]
    DIRECTION INPUT ;
    USE SIGNAL ;
    SHAPE ABUTMENT ;
    PORT
      LAYER M1 ;
      RECT 748.99 0.0 749.19 0.32 ;
      LAYER M2 ;
      RECT 748.99 0.0 749.19 0.32 ;
      LAYER M3 ;
      RECT 748.99 0.0 749.19 0.32 ;
      END
    ANTENNAGATEAREA 0.0072 ;
    ANTENNADIFFAREA 0.054 ;
    END TD[40]
  PIN TD[23]
    DIRECTION INPUT ;
    USE SIGNAL ;
    SHAPE ABUTMENT ;
    PORT
      LAYER M3 ;
      RECT 460.64 0.0 460.84 0.32 ;
      LAYER M2 ;
      RECT 460.64 0.0 460.84 0.32 ;
      LAYER M1 ;
      RECT 460.64 0.0 460.84 0.32 ;
      END
    ANTENNAGATEAREA 0.0072 ;
    ANTENNADIFFAREA 0.054 ;
    END TD[23]
  PIN D[40]
    DIRECTION INPUT ;
    USE SIGNAL ;
    SHAPE ABUTMENT ;
    PORT
      LAYER M1 ;
      RECT 751.29 0.0 751.49 0.32 ;
      LAYER M2 ;
      RECT 751.29 0.0 751.49 0.32 ;
      LAYER M3 ;
      RECT 751.29 0.0 751.49 0.32 ;
      LAYER M4 ;
      RECT 751.29 0.0 751.49 0.32 ;
      END
    ANTENNAGATEAREA 0.0072 ;
    ANTENNADIFFAREA 0.054 ;
    END D[40]
  PIN D[23]
    DIRECTION INPUT ;
    USE SIGNAL ;
    SHAPE ABUTMENT ;
    PORT
      LAYER M4 ;
      RECT 458.34 0.0 458.54 0.32 ;
      LAYER M3 ;
      RECT 458.34 0.0 458.54 0.32 ;
      LAYER M2 ;
      RECT 458.34 0.0 458.54 0.32 ;
      LAYER M1 ;
      RECT 458.34 0.0 458.54 0.32 ;
      END
    ANTENNAGATEAREA 0.0072 ;
    ANTENNADIFFAREA 0.054 ;
    END D[23]
  PIN Q[40]
    DIRECTION OUTPUT ;
    USE SIGNAL ;
    SHAPE ABUTMENT ;
    PORT
      LAYER M1 ;
      RECT 752.925 0.0 753.125 0.32 ;
      LAYER M2 ;
      RECT 752.925 0.0 753.125 0.32 ;
      LAYER M3 ;
      RECT 752.925 0.0 753.125 0.32 ;
      END
    ANTENNADIFFAREA 0.054 ;
    END Q[40]
  PIN Q[23]
    DIRECTION OUTPUT ;
    USE SIGNAL ;
    SHAPE ABUTMENT ;
    PORT
      LAYER M3 ;
      RECT 456.705 0.0 456.905 0.32 ;
      LAYER M2 ;
      RECT 456.705 0.0 456.905 0.32 ;
      LAYER M1 ;
      RECT 456.705 0.0 456.905 0.32 ;
      END
    ANTENNADIFFAREA 0.054 ;
    END Q[23]
  PIN TD[41]
    DIRECTION INPUT ;
    USE SIGNAL ;
    SHAPE ABUTMENT ;
    PORT
      LAYER M1 ;
      RECT 765.79 0.0 765.99 0.32 ;
      LAYER M2 ;
      RECT 765.79 0.0 765.99 0.32 ;
      LAYER M3 ;
      RECT 765.79 0.0 765.99 0.32 ;
      END
    ANTENNAGATEAREA 0.0072 ;
    ANTENNADIFFAREA 0.054 ;
    END TD[41]
  PIN TD[22]
    DIRECTION INPUT ;
    USE SIGNAL ;
    SHAPE ABUTMENT ;
    PORT
      LAYER M3 ;
      RECT 443.84 0.0 444.04 0.32 ;
      LAYER M2 ;
      RECT 443.84 0.0 444.04 0.32 ;
      LAYER M1 ;
      RECT 443.84 0.0 444.04 0.32 ;
      END
    ANTENNAGATEAREA 0.0072 ;
    ANTENNADIFFAREA 0.054 ;
    END TD[22]
  PIN D[41]
    DIRECTION INPUT ;
    USE SIGNAL ;
    SHAPE ABUTMENT ;
    PORT
      LAYER M1 ;
      RECT 768.09 0.0 768.29 0.32 ;
      LAYER M2 ;
      RECT 768.09 0.0 768.29 0.32 ;
      LAYER M3 ;
      RECT 768.09 0.0 768.29 0.32 ;
      LAYER M4 ;
      RECT 768.09 0.0 768.29 0.32 ;
      END
    ANTENNAGATEAREA 0.0072 ;
    ANTENNADIFFAREA 0.054 ;
    END D[41]
  PIN D[22]
    DIRECTION INPUT ;
    USE SIGNAL ;
    SHAPE ABUTMENT ;
    PORT
      LAYER M4 ;
      RECT 441.54 0.0 441.74 0.32 ;
      LAYER M3 ;
      RECT 441.54 0.0 441.74 0.32 ;
      LAYER M2 ;
      RECT 441.54 0.0 441.74 0.32 ;
      LAYER M1 ;
      RECT 441.54 0.0 441.74 0.32 ;
      END
    ANTENNAGATEAREA 0.0072 ;
    ANTENNADIFFAREA 0.054 ;
    END D[22]
  PIN Q[41]
    DIRECTION OUTPUT ;
    USE SIGNAL ;
    SHAPE ABUTMENT ;
    PORT
      LAYER M1 ;
      RECT 769.725 0.0 769.925 0.32 ;
      LAYER M2 ;
      RECT 769.725 0.0 769.925 0.32 ;
      LAYER M3 ;
      RECT 769.725 0.0 769.925 0.32 ;
      END
    ANTENNADIFFAREA 0.054 ;
    END Q[41]
  PIN Q[22]
    DIRECTION OUTPUT ;
    USE SIGNAL ;
    SHAPE ABUTMENT ;
    PORT
      LAYER M3 ;
      RECT 439.905 0.0 440.105 0.32 ;
      LAYER M2 ;
      RECT 439.905 0.0 440.105 0.32 ;
      LAYER M1 ;
      RECT 439.905 0.0 440.105 0.32 ;
      END
    ANTENNADIFFAREA 0.054 ;
    END Q[22]
  PIN TD[42]
    DIRECTION INPUT ;
    USE SIGNAL ;
    SHAPE ABUTMENT ;
    PORT
      LAYER M1 ;
      RECT 782.59 0.0 782.79 0.32 ;
      LAYER M2 ;
      RECT 782.59 0.0 782.79 0.32 ;
      LAYER M3 ;
      RECT 782.59 0.0 782.79 0.32 ;
      END
    ANTENNAGATEAREA 0.0072 ;
    ANTENNADIFFAREA 0.054 ;
    END TD[42]
  PIN TD[21]
    DIRECTION INPUT ;
    USE SIGNAL ;
    SHAPE ABUTMENT ;
    PORT
      LAYER M3 ;
      RECT 427.04 0.0 427.24 0.32 ;
      LAYER M2 ;
      RECT 427.04 0.0 427.24 0.32 ;
      LAYER M1 ;
      RECT 427.04 0.0 427.24 0.32 ;
      END
    ANTENNAGATEAREA 0.0072 ;
    ANTENNADIFFAREA 0.054 ;
    END TD[21]
  PIN D[42]
    DIRECTION INPUT ;
    USE SIGNAL ;
    SHAPE ABUTMENT ;
    PORT
      LAYER M1 ;
      RECT 784.89 0.0 785.09 0.32 ;
      LAYER M2 ;
      RECT 784.89 0.0 785.09 0.32 ;
      LAYER M3 ;
      RECT 784.89 0.0 785.09 0.32 ;
      LAYER M4 ;
      RECT 784.89 0.0 785.09 0.32 ;
      END
    ANTENNAGATEAREA 0.0072 ;
    ANTENNADIFFAREA 0.054 ;
    END D[42]
  PIN D[21]
    DIRECTION INPUT ;
    USE SIGNAL ;
    SHAPE ABUTMENT ;
    PORT
      LAYER M4 ;
      RECT 424.74 0.0 424.94 0.32 ;
      LAYER M3 ;
      RECT 424.74 0.0 424.94 0.32 ;
      LAYER M2 ;
      RECT 424.74 0.0 424.94 0.32 ;
      LAYER M1 ;
      RECT 424.74 0.0 424.94 0.32 ;
      END
    ANTENNAGATEAREA 0.0072 ;
    ANTENNADIFFAREA 0.054 ;
    END D[21]
  PIN Q[42]
    DIRECTION OUTPUT ;
    USE SIGNAL ;
    SHAPE ABUTMENT ;
    PORT
      LAYER M1 ;
      RECT 786.525 0.0 786.725 0.32 ;
      LAYER M2 ;
      RECT 786.525 0.0 786.725 0.32 ;
      LAYER M3 ;
      RECT 786.525 0.0 786.725 0.32 ;
      END
    ANTENNADIFFAREA 0.054 ;
    END Q[42]
  PIN Q[21]
    DIRECTION OUTPUT ;
    USE SIGNAL ;
    SHAPE ABUTMENT ;
    PORT
      LAYER M3 ;
      RECT 423.105 0.0 423.305 0.32 ;
      LAYER M2 ;
      RECT 423.105 0.0 423.305 0.32 ;
      LAYER M1 ;
      RECT 423.105 0.0 423.305 0.32 ;
      END
    ANTENNADIFFAREA 0.054 ;
    END Q[21]
  PIN TD[43]
    DIRECTION INPUT ;
    USE SIGNAL ;
    SHAPE ABUTMENT ;
    PORT
      LAYER M1 ;
      RECT 799.39 0.0 799.59 0.32 ;
      LAYER M2 ;
      RECT 799.39 0.0 799.59 0.32 ;
      LAYER M3 ;
      RECT 799.39 0.0 799.59 0.32 ;
      END
    ANTENNAGATEAREA 0.0072 ;
    ANTENNADIFFAREA 0.054 ;
    END TD[43]
  PIN TD[20]
    DIRECTION INPUT ;
    USE SIGNAL ;
    SHAPE ABUTMENT ;
    PORT
      LAYER M3 ;
      RECT 410.24 0.0 410.44 0.32 ;
      LAYER M2 ;
      RECT 410.24 0.0 410.44 0.32 ;
      LAYER M1 ;
      RECT 410.24 0.0 410.44 0.32 ;
      END
    ANTENNAGATEAREA 0.0072 ;
    ANTENNADIFFAREA 0.054 ;
    END TD[20]
  PIN D[43]
    DIRECTION INPUT ;
    USE SIGNAL ;
    SHAPE ABUTMENT ;
    PORT
      LAYER M1 ;
      RECT 801.69 0.0 801.89 0.32 ;
      LAYER M2 ;
      RECT 801.69 0.0 801.89 0.32 ;
      LAYER M3 ;
      RECT 801.69 0.0 801.89 0.32 ;
      LAYER M4 ;
      RECT 801.69 0.0 801.89 0.32 ;
      END
    ANTENNAGATEAREA 0.0072 ;
    ANTENNADIFFAREA 0.054 ;
    END D[43]
  PIN D[20]
    DIRECTION INPUT ;
    USE SIGNAL ;
    SHAPE ABUTMENT ;
    PORT
      LAYER M4 ;
      RECT 407.94 0.0 408.14 0.32 ;
      LAYER M3 ;
      RECT 407.94 0.0 408.14 0.32 ;
      LAYER M2 ;
      RECT 407.94 0.0 408.14 0.32 ;
      LAYER M1 ;
      RECT 407.94 0.0 408.14 0.32 ;
      END
    ANTENNAGATEAREA 0.0072 ;
    ANTENNADIFFAREA 0.054 ;
    END D[20]
  PIN Q[43]
    DIRECTION OUTPUT ;
    USE SIGNAL ;
    SHAPE ABUTMENT ;
    PORT
      LAYER M1 ;
      RECT 803.325 0.0 803.525 0.32 ;
      LAYER M2 ;
      RECT 803.325 0.0 803.525 0.32 ;
      LAYER M3 ;
      RECT 803.325 0.0 803.525 0.32 ;
      END
    ANTENNADIFFAREA 0.054 ;
    END Q[43]
  PIN Q[20]
    DIRECTION OUTPUT ;
    USE SIGNAL ;
    SHAPE ABUTMENT ;
    PORT
      LAYER M3 ;
      RECT 406.305 0.0 406.505 0.32 ;
      LAYER M2 ;
      RECT 406.305 0.0 406.505 0.32 ;
      LAYER M1 ;
      RECT 406.305 0.0 406.505 0.32 ;
      END
    ANTENNADIFFAREA 0.054 ;
    END Q[20]
  PIN TD[44]
    DIRECTION INPUT ;
    USE SIGNAL ;
    SHAPE ABUTMENT ;
    PORT
      LAYER M1 ;
      RECT 816.19 0.0 816.39 0.32 ;
      LAYER M2 ;
      RECT 816.19 0.0 816.39 0.32 ;
      LAYER M3 ;
      RECT 816.19 0.0 816.39 0.32 ;
      END
    ANTENNAGATEAREA 0.0072 ;
    ANTENNADIFFAREA 0.054 ;
    END TD[44]
  PIN TD[19]
    DIRECTION INPUT ;
    USE SIGNAL ;
    SHAPE ABUTMENT ;
    PORT
      LAYER M3 ;
      RECT 393.44 0.0 393.64 0.32 ;
      LAYER M2 ;
      RECT 393.44 0.0 393.64 0.32 ;
      LAYER M1 ;
      RECT 393.44 0.0 393.64 0.32 ;
      END
    ANTENNAGATEAREA 0.0072 ;
    ANTENNADIFFAREA 0.054 ;
    END TD[19]
  PIN D[44]
    DIRECTION INPUT ;
    USE SIGNAL ;
    SHAPE ABUTMENT ;
    PORT
      LAYER M1 ;
      RECT 818.49 0.0 818.69 0.32 ;
      LAYER M2 ;
      RECT 818.49 0.0 818.69 0.32 ;
      LAYER M3 ;
      RECT 818.49 0.0 818.69 0.32 ;
      LAYER M4 ;
      RECT 818.49 0.0 818.69 0.32 ;
      END
    ANTENNAGATEAREA 0.0072 ;
    ANTENNADIFFAREA 0.054 ;
    END D[44]
  PIN D[19]
    DIRECTION INPUT ;
    USE SIGNAL ;
    SHAPE ABUTMENT ;
    PORT
      LAYER M4 ;
      RECT 391.14 0.0 391.34 0.32 ;
      LAYER M3 ;
      RECT 391.14 0.0 391.34 0.32 ;
      LAYER M2 ;
      RECT 391.14 0.0 391.34 0.32 ;
      LAYER M1 ;
      RECT 391.14 0.0 391.34 0.32 ;
      END
    ANTENNAGATEAREA 0.0072 ;
    ANTENNADIFFAREA 0.054 ;
    END D[19]
  PIN Q[44]
    DIRECTION OUTPUT ;
    USE SIGNAL ;
    SHAPE ABUTMENT ;
    PORT
      LAYER M1 ;
      RECT 820.125 0.0 820.325 0.32 ;
      LAYER M2 ;
      RECT 820.125 0.0 820.325 0.32 ;
      LAYER M3 ;
      RECT 820.125 0.0 820.325 0.32 ;
      END
    ANTENNADIFFAREA 0.054 ;
    END Q[44]
  PIN Q[19]
    DIRECTION OUTPUT ;
    USE SIGNAL ;
    SHAPE ABUTMENT ;
    PORT
      LAYER M3 ;
      RECT 389.505 0.0 389.705 0.32 ;
      LAYER M2 ;
      RECT 389.505 0.0 389.705 0.32 ;
      LAYER M1 ;
      RECT 389.505 0.0 389.705 0.32 ;
      END
    ANTENNADIFFAREA 0.054 ;
    END Q[19]
  PIN TD[45]
    DIRECTION INPUT ;
    USE SIGNAL ;
    SHAPE ABUTMENT ;
    PORT
      LAYER M1 ;
      RECT 832.99 0.0 833.19 0.32 ;
      LAYER M2 ;
      RECT 832.99 0.0 833.19 0.32 ;
      LAYER M3 ;
      RECT 832.99 0.0 833.19 0.32 ;
      END
    ANTENNAGATEAREA 0.0072 ;
    ANTENNADIFFAREA 0.054 ;
    END TD[45]
  PIN TD[18]
    DIRECTION INPUT ;
    USE SIGNAL ;
    SHAPE ABUTMENT ;
    PORT
      LAYER M3 ;
      RECT 376.64 0.0 376.84 0.32 ;
      LAYER M2 ;
      RECT 376.64 0.0 376.84 0.32 ;
      LAYER M1 ;
      RECT 376.64 0.0 376.84 0.32 ;
      END
    ANTENNAGATEAREA 0.0072 ;
    ANTENNADIFFAREA 0.054 ;
    END TD[18]
  PIN D[45]
    DIRECTION INPUT ;
    USE SIGNAL ;
    SHAPE ABUTMENT ;
    PORT
      LAYER M1 ;
      RECT 835.29 0.0 835.49 0.32 ;
      LAYER M2 ;
      RECT 835.29 0.0 835.49 0.32 ;
      LAYER M3 ;
      RECT 835.29 0.0 835.49 0.32 ;
      LAYER M4 ;
      RECT 835.29 0.0 835.49 0.32 ;
      END
    ANTENNAGATEAREA 0.0072 ;
    ANTENNADIFFAREA 0.054 ;
    END D[45]
  PIN D[18]
    DIRECTION INPUT ;
    USE SIGNAL ;
    SHAPE ABUTMENT ;
    PORT
      LAYER M4 ;
      RECT 374.34 0.0 374.54 0.32 ;
      LAYER M3 ;
      RECT 374.34 0.0 374.54 0.32 ;
      LAYER M2 ;
      RECT 374.34 0.0 374.54 0.32 ;
      LAYER M1 ;
      RECT 374.34 0.0 374.54 0.32 ;
      END
    ANTENNAGATEAREA 0.0072 ;
    ANTENNADIFFAREA 0.054 ;
    END D[18]
  PIN Q[45]
    DIRECTION OUTPUT ;
    USE SIGNAL ;
    SHAPE ABUTMENT ;
    PORT
      LAYER M1 ;
      RECT 836.925 0.0 837.125 0.32 ;
      LAYER M2 ;
      RECT 836.925 0.0 837.125 0.32 ;
      LAYER M3 ;
      RECT 836.925 0.0 837.125 0.32 ;
      END
    ANTENNADIFFAREA 0.054 ;
    END Q[45]
  PIN Q[18]
    DIRECTION OUTPUT ;
    USE SIGNAL ;
    SHAPE ABUTMENT ;
    PORT
      LAYER M3 ;
      RECT 372.705 0.0 372.905 0.32 ;
      LAYER M2 ;
      RECT 372.705 0.0 372.905 0.32 ;
      LAYER M1 ;
      RECT 372.705 0.0 372.905 0.32 ;
      END
    ANTENNADIFFAREA 0.054 ;
    END Q[18]
  PIN TD[46]
    DIRECTION INPUT ;
    USE SIGNAL ;
    SHAPE ABUTMENT ;
    PORT
      LAYER M1 ;
      RECT 849.79 0.0 849.99 0.32 ;
      LAYER M2 ;
      RECT 849.79 0.0 849.99 0.32 ;
      LAYER M3 ;
      RECT 849.79 0.0 849.99 0.32 ;
      END
    ANTENNAGATEAREA 0.0072 ;
    ANTENNADIFFAREA 0.054 ;
    END TD[46]
  PIN TD[17]
    DIRECTION INPUT ;
    USE SIGNAL ;
    SHAPE ABUTMENT ;
    PORT
      LAYER M3 ;
      RECT 359.84 0.0 360.04 0.32 ;
      LAYER M2 ;
      RECT 359.84 0.0 360.04 0.32 ;
      LAYER M1 ;
      RECT 359.84 0.0 360.04 0.32 ;
      END
    ANTENNAGATEAREA 0.0072 ;
    ANTENNADIFFAREA 0.054 ;
    END TD[17]
  PIN D[46]
    DIRECTION INPUT ;
    USE SIGNAL ;
    SHAPE ABUTMENT ;
    PORT
      LAYER M1 ;
      RECT 852.09 0.0 852.29 0.32 ;
      LAYER M2 ;
      RECT 852.09 0.0 852.29 0.32 ;
      LAYER M3 ;
      RECT 852.09 0.0 852.29 0.32 ;
      LAYER M4 ;
      RECT 852.09 0.0 852.29 0.32 ;
      END
    ANTENNAGATEAREA 0.0072 ;
    ANTENNADIFFAREA 0.054 ;
    END D[46]
  PIN D[17]
    DIRECTION INPUT ;
    USE SIGNAL ;
    SHAPE ABUTMENT ;
    PORT
      LAYER M4 ;
      RECT 357.54 0.0 357.74 0.32 ;
      LAYER M3 ;
      RECT 357.54 0.0 357.74 0.32 ;
      LAYER M2 ;
      RECT 357.54 0.0 357.74 0.32 ;
      LAYER M1 ;
      RECT 357.54 0.0 357.74 0.32 ;
      END
    ANTENNAGATEAREA 0.0072 ;
    ANTENNADIFFAREA 0.054 ;
    END D[17]
  PIN Q[46]
    DIRECTION OUTPUT ;
    USE SIGNAL ;
    SHAPE ABUTMENT ;
    PORT
      LAYER M1 ;
      RECT 853.725 0.0 853.925 0.32 ;
      LAYER M2 ;
      RECT 853.725 0.0 853.925 0.32 ;
      LAYER M3 ;
      RECT 853.725 0.0 853.925 0.32 ;
      END
    ANTENNADIFFAREA 0.054 ;
    END Q[46]
  PIN Q[17]
    DIRECTION OUTPUT ;
    USE SIGNAL ;
    SHAPE ABUTMENT ;
    PORT
      LAYER M3 ;
      RECT 355.905 0.0 356.105 0.32 ;
      LAYER M2 ;
      RECT 355.905 0.0 356.105 0.32 ;
      LAYER M1 ;
      RECT 355.905 0.0 356.105 0.32 ;
      END
    ANTENNADIFFAREA 0.054 ;
    END Q[17]
  PIN TD[47]
    DIRECTION INPUT ;
    USE SIGNAL ;
    SHAPE ABUTMENT ;
    PORT
      LAYER M1 ;
      RECT 866.59 0.0 866.79 0.32 ;
      LAYER M2 ;
      RECT 866.59 0.0 866.79 0.32 ;
      LAYER M3 ;
      RECT 866.59 0.0 866.79 0.32 ;
      END
    ANTENNAGATEAREA 0.0072 ;
    ANTENNADIFFAREA 0.054 ;
    END TD[47]
  PIN TD[16]
    DIRECTION INPUT ;
    USE SIGNAL ;
    SHAPE ABUTMENT ;
    PORT
      LAYER M3 ;
      RECT 343.04 0.0 343.24 0.32 ;
      LAYER M2 ;
      RECT 343.04 0.0 343.24 0.32 ;
      LAYER M1 ;
      RECT 343.04 0.0 343.24 0.32 ;
      END
    ANTENNAGATEAREA 0.0072 ;
    ANTENNADIFFAREA 0.054 ;
    END TD[16]
  PIN D[47]
    DIRECTION INPUT ;
    USE SIGNAL ;
    SHAPE ABUTMENT ;
    PORT
      LAYER M1 ;
      RECT 868.89 0.0 869.09 0.32 ;
      LAYER M2 ;
      RECT 868.89 0.0 869.09 0.32 ;
      LAYER M3 ;
      RECT 868.89 0.0 869.09 0.32 ;
      LAYER M4 ;
      RECT 868.89 0.0 869.09 0.32 ;
      END
    ANTENNAGATEAREA 0.0072 ;
    ANTENNADIFFAREA 0.054 ;
    END D[47]
  PIN D[16]
    DIRECTION INPUT ;
    USE SIGNAL ;
    SHAPE ABUTMENT ;
    PORT
      LAYER M4 ;
      RECT 340.74 0.0 340.94 0.32 ;
      LAYER M3 ;
      RECT 340.74 0.0 340.94 0.32 ;
      LAYER M2 ;
      RECT 340.74 0.0 340.94 0.32 ;
      LAYER M1 ;
      RECT 340.74 0.0 340.94 0.32 ;
      END
    ANTENNAGATEAREA 0.0072 ;
    ANTENNADIFFAREA 0.054 ;
    END D[16]
  PIN Q[47]
    DIRECTION OUTPUT ;
    USE SIGNAL ;
    SHAPE ABUTMENT ;
    PORT
      LAYER M1 ;
      RECT 870.525 0.0 870.725 0.32 ;
      LAYER M2 ;
      RECT 870.525 0.0 870.725 0.32 ;
      LAYER M3 ;
      RECT 870.525 0.0 870.725 0.32 ;
      END
    ANTENNADIFFAREA 0.054 ;
    END Q[47]
  PIN Q[16]
    DIRECTION OUTPUT ;
    USE SIGNAL ;
    SHAPE ABUTMENT ;
    PORT
      LAYER M3 ;
      RECT 339.105 0.0 339.305 0.32 ;
      LAYER M2 ;
      RECT 339.105 0.0 339.305 0.32 ;
      LAYER M1 ;
      RECT 339.105 0.0 339.305 0.32 ;
      END
    ANTENNADIFFAREA 0.054 ;
    END Q[16]
  PIN TD[48]
    DIRECTION INPUT ;
    USE SIGNAL ;
    SHAPE ABUTMENT ;
    PORT
      LAYER M1 ;
      RECT 948.39 0.0 948.59 0.32 ;
      LAYER M2 ;
      RECT 948.39 0.0 948.59 0.32 ;
      LAYER M3 ;
      RECT 948.39 0.0 948.59 0.32 ;
      END
    ANTENNAGATEAREA 0.0072 ;
    ANTENNADIFFAREA 0.054 ;
    END TD[48]
  PIN TD[15]
    DIRECTION INPUT ;
    USE SIGNAL ;
    SHAPE ABUTMENT ;
    PORT
      LAYER M3 ;
      RECT 261.24 0.0 261.44 0.32 ;
      LAYER M2 ;
      RECT 261.24 0.0 261.44 0.32 ;
      LAYER M1 ;
      RECT 261.24 0.0 261.44 0.32 ;
      END
    ANTENNAGATEAREA 0.0072 ;
    ANTENNADIFFAREA 0.054 ;
    END TD[15]
  PIN D[48]
    DIRECTION INPUT ;
    USE SIGNAL ;
    SHAPE ABUTMENT ;
    PORT
      LAYER M1 ;
      RECT 950.69 0.0 950.89 0.32 ;
      LAYER M2 ;
      RECT 950.69 0.0 950.89 0.32 ;
      LAYER M3 ;
      RECT 950.69 0.0 950.89 0.32 ;
      LAYER M4 ;
      RECT 950.69 0.0 950.89 0.32 ;
      END
    ANTENNAGATEAREA 0.0072 ;
    ANTENNADIFFAREA 0.054 ;
    END D[48]
  PIN D[15]
    DIRECTION INPUT ;
    USE SIGNAL ;
    SHAPE ABUTMENT ;
    PORT
      LAYER M4 ;
      RECT 258.94 0.0 259.14 0.32 ;
      LAYER M3 ;
      RECT 258.94 0.0 259.14 0.32 ;
      LAYER M2 ;
      RECT 258.94 0.0 259.14 0.32 ;
      LAYER M1 ;
      RECT 258.94 0.0 259.14 0.32 ;
      END
    ANTENNAGATEAREA 0.0072 ;
    ANTENNADIFFAREA 0.054 ;
    END D[15]
  PIN Q[48]
    DIRECTION OUTPUT ;
    USE SIGNAL ;
    SHAPE ABUTMENT ;
    PORT
      LAYER M1 ;
      RECT 952.325 0.0 952.525 0.32 ;
      LAYER M2 ;
      RECT 952.325 0.0 952.525 0.32 ;
      LAYER M3 ;
      RECT 952.325 0.0 952.525 0.32 ;
      END
    ANTENNADIFFAREA 0.054 ;
    END Q[48]
  PIN Q[15]
    DIRECTION OUTPUT ;
    USE SIGNAL ;
    SHAPE ABUTMENT ;
    PORT
      LAYER M3 ;
      RECT 257.305 0.0 257.505 0.32 ;
      LAYER M2 ;
      RECT 257.305 0.0 257.505 0.32 ;
      LAYER M1 ;
      RECT 257.305 0.0 257.505 0.32 ;
      END
    ANTENNADIFFAREA 0.054 ;
    END Q[15]
  PIN TD[49]
    DIRECTION INPUT ;
    USE SIGNAL ;
    SHAPE ABUTMENT ;
    PORT
      LAYER M1 ;
      RECT 965.19 0.0 965.39 0.32 ;
      LAYER M2 ;
      RECT 965.19 0.0 965.39 0.32 ;
      LAYER M3 ;
      RECT 965.19 0.0 965.39 0.32 ;
      END
    ANTENNAGATEAREA 0.0072 ;
    ANTENNADIFFAREA 0.054 ;
    END TD[49]
  PIN TD[14]
    DIRECTION INPUT ;
    USE SIGNAL ;
    SHAPE ABUTMENT ;
    PORT
      LAYER M3 ;
      RECT 244.44 0.0 244.64 0.32 ;
      LAYER M2 ;
      RECT 244.44 0.0 244.64 0.32 ;
      LAYER M1 ;
      RECT 244.44 0.0 244.64 0.32 ;
      END
    ANTENNAGATEAREA 0.0072 ;
    ANTENNADIFFAREA 0.054 ;
    END TD[14]
  PIN D[49]
    DIRECTION INPUT ;
    USE SIGNAL ;
    SHAPE ABUTMENT ;
    PORT
      LAYER M1 ;
      RECT 967.49 0.0 967.69 0.32 ;
      LAYER M2 ;
      RECT 967.49 0.0 967.69 0.32 ;
      LAYER M3 ;
      RECT 967.49 0.0 967.69 0.32 ;
      LAYER M4 ;
      RECT 967.49 0.0 967.69 0.32 ;
      END
    ANTENNAGATEAREA 0.0072 ;
    ANTENNADIFFAREA 0.054 ;
    END D[49]
  PIN D[14]
    DIRECTION INPUT ;
    USE SIGNAL ;
    SHAPE ABUTMENT ;
    PORT
      LAYER M4 ;
      RECT 242.14 0.0 242.34 0.32 ;
      LAYER M3 ;
      RECT 242.14 0.0 242.34 0.32 ;
      LAYER M2 ;
      RECT 242.14 0.0 242.34 0.32 ;
      LAYER M1 ;
      RECT 242.14 0.0 242.34 0.32 ;
      END
    ANTENNAGATEAREA 0.0072 ;
    ANTENNADIFFAREA 0.054 ;
    END D[14]
  PIN Q[49]
    DIRECTION OUTPUT ;
    USE SIGNAL ;
    SHAPE ABUTMENT ;
    PORT
      LAYER M1 ;
      RECT 969.125 0.0 969.325 0.32 ;
      LAYER M2 ;
      RECT 969.125 0.0 969.325 0.32 ;
      LAYER M3 ;
      RECT 969.125 0.0 969.325 0.32 ;
      END
    ANTENNADIFFAREA 0.054 ;
    END Q[49]
  PIN Q[14]
    DIRECTION OUTPUT ;
    USE SIGNAL ;
    SHAPE ABUTMENT ;
    PORT
      LAYER M3 ;
      RECT 240.505 0.0 240.705 0.32 ;
      LAYER M2 ;
      RECT 240.505 0.0 240.705 0.32 ;
      LAYER M1 ;
      RECT 240.505 0.0 240.705 0.32 ;
      END
    ANTENNADIFFAREA 0.054 ;
    END Q[14]
  PIN TD[50]
    DIRECTION INPUT ;
    USE SIGNAL ;
    SHAPE ABUTMENT ;
    PORT
      LAYER M1 ;
      RECT 981.99 0.0 982.19 0.32 ;
      LAYER M2 ;
      RECT 981.99 0.0 982.19 0.32 ;
      LAYER M3 ;
      RECT 981.99 0.0 982.19 0.32 ;
      END
    ANTENNAGATEAREA 0.0072 ;
    ANTENNADIFFAREA 0.054 ;
    END TD[50]
  PIN TD[13]
    DIRECTION INPUT ;
    USE SIGNAL ;
    SHAPE ABUTMENT ;
    PORT
      LAYER M3 ;
      RECT 227.64 0.0 227.84 0.32 ;
      LAYER M2 ;
      RECT 227.64 0.0 227.84 0.32 ;
      LAYER M1 ;
      RECT 227.64 0.0 227.84 0.32 ;
      END
    ANTENNAGATEAREA 0.0072 ;
    ANTENNADIFFAREA 0.054 ;
    END TD[13]
  PIN D[50]
    DIRECTION INPUT ;
    USE SIGNAL ;
    SHAPE ABUTMENT ;
    PORT
      LAYER M1 ;
      RECT 984.29 0.0 984.49 0.32 ;
      LAYER M2 ;
      RECT 984.29 0.0 984.49 0.32 ;
      LAYER M3 ;
      RECT 984.29 0.0 984.49 0.32 ;
      LAYER M4 ;
      RECT 984.29 0.0 984.49 0.32 ;
      END
    ANTENNAGATEAREA 0.0072 ;
    ANTENNADIFFAREA 0.054 ;
    END D[50]
  PIN D[13]
    DIRECTION INPUT ;
    USE SIGNAL ;
    SHAPE ABUTMENT ;
    PORT
      LAYER M4 ;
      RECT 225.34 0.0 225.54 0.32 ;
      LAYER M3 ;
      RECT 225.34 0.0 225.54 0.32 ;
      LAYER M2 ;
      RECT 225.34 0.0 225.54 0.32 ;
      LAYER M1 ;
      RECT 225.34 0.0 225.54 0.32 ;
      END
    ANTENNAGATEAREA 0.0072 ;
    ANTENNADIFFAREA 0.054 ;
    END D[13]
  PIN Q[50]
    DIRECTION OUTPUT ;
    USE SIGNAL ;
    SHAPE ABUTMENT ;
    PORT
      LAYER M1 ;
      RECT 985.925 0.0 986.125 0.32 ;
      LAYER M2 ;
      RECT 985.925 0.0 986.125 0.32 ;
      LAYER M3 ;
      RECT 985.925 0.0 986.125 0.32 ;
      END
    ANTENNADIFFAREA 0.054 ;
    END Q[50]
  PIN Q[13]
    DIRECTION OUTPUT ;
    USE SIGNAL ;
    SHAPE ABUTMENT ;
    PORT
      LAYER M3 ;
      RECT 223.705 0.0 223.905 0.32 ;
      LAYER M2 ;
      RECT 223.705 0.0 223.905 0.32 ;
      LAYER M1 ;
      RECT 223.705 0.0 223.905 0.32 ;
      END
    ANTENNADIFFAREA 0.054 ;
    END Q[13]
  PIN TD[51]
    DIRECTION INPUT ;
    USE SIGNAL ;
    SHAPE ABUTMENT ;
    PORT
      LAYER M1 ;
      RECT 998.79 0.0 998.99 0.32 ;
      LAYER M2 ;
      RECT 998.79 0.0 998.99 0.32 ;
      LAYER M3 ;
      RECT 998.79 0.0 998.99 0.32 ;
      END
    ANTENNAGATEAREA 0.0072 ;
    ANTENNADIFFAREA 0.054 ;
    END TD[51]
  PIN TD[12]
    DIRECTION INPUT ;
    USE SIGNAL ;
    SHAPE ABUTMENT ;
    PORT
      LAYER M3 ;
      RECT 210.84 0.0 211.04 0.32 ;
      LAYER M2 ;
      RECT 210.84 0.0 211.04 0.32 ;
      LAYER M1 ;
      RECT 210.84 0.0 211.04 0.32 ;
      END
    ANTENNAGATEAREA 0.0072 ;
    ANTENNADIFFAREA 0.054 ;
    END TD[12]
  PIN D[51]
    DIRECTION INPUT ;
    USE SIGNAL ;
    SHAPE ABUTMENT ;
    PORT
      LAYER M1 ;
      RECT 1001.09 0.0 1001.29 0.32 ;
      LAYER M2 ;
      RECT 1001.09 0.0 1001.29 0.32 ;
      LAYER M3 ;
      RECT 1001.09 0.0 1001.29 0.32 ;
      LAYER M4 ;
      RECT 1001.09 0.0 1001.29 0.32 ;
      END
    ANTENNAGATEAREA 0.0072 ;
    ANTENNADIFFAREA 0.054 ;
    END D[51]
  PIN D[12]
    DIRECTION INPUT ;
    USE SIGNAL ;
    SHAPE ABUTMENT ;
    PORT
      LAYER M4 ;
      RECT 208.54 0.0 208.74 0.32 ;
      LAYER M3 ;
      RECT 208.54 0.0 208.74 0.32 ;
      LAYER M2 ;
      RECT 208.54 0.0 208.74 0.32 ;
      LAYER M1 ;
      RECT 208.54 0.0 208.74 0.32 ;
      END
    ANTENNAGATEAREA 0.0072 ;
    ANTENNADIFFAREA 0.054 ;
    END D[12]
  PIN Q[51]
    DIRECTION OUTPUT ;
    USE SIGNAL ;
    SHAPE ABUTMENT ;
    PORT
      LAYER M1 ;
      RECT 1002.725 0.0 1002.925 0.32 ;
      LAYER M2 ;
      RECT 1002.725 0.0 1002.925 0.32 ;
      LAYER M3 ;
      RECT 1002.725 0.0 1002.925 0.32 ;
      END
    ANTENNADIFFAREA 0.054 ;
    END Q[51]
  PIN Q[12]
    DIRECTION OUTPUT ;
    USE SIGNAL ;
    SHAPE ABUTMENT ;
    PORT
      LAYER M3 ;
      RECT 206.905 0.0 207.105 0.32 ;
      LAYER M2 ;
      RECT 206.905 0.0 207.105 0.32 ;
      LAYER M1 ;
      RECT 206.905 0.0 207.105 0.32 ;
      END
    ANTENNADIFFAREA 0.054 ;
    END Q[12]
  PIN TD[52]
    DIRECTION INPUT ;
    USE SIGNAL ;
    SHAPE ABUTMENT ;
    PORT
      LAYER M1 ;
      RECT 1015.59 0.0 1015.79 0.32 ;
      LAYER M2 ;
      RECT 1015.59 0.0 1015.79 0.32 ;
      LAYER M3 ;
      RECT 1015.59 0.0 1015.79 0.32 ;
      END
    ANTENNAGATEAREA 0.0072 ;
    ANTENNADIFFAREA 0.054 ;
    END TD[52]
  PIN TD[11]
    DIRECTION INPUT ;
    USE SIGNAL ;
    SHAPE ABUTMENT ;
    PORT
      LAYER M3 ;
      RECT 194.04 0.0 194.24 0.32 ;
      LAYER M2 ;
      RECT 194.04 0.0 194.24 0.32 ;
      LAYER M1 ;
      RECT 194.04 0.0 194.24 0.32 ;
      END
    ANTENNAGATEAREA 0.0072 ;
    ANTENNADIFFAREA 0.054 ;
    END TD[11]
  PIN D[52]
    DIRECTION INPUT ;
    USE SIGNAL ;
    SHAPE ABUTMENT ;
    PORT
      LAYER M1 ;
      RECT 1017.89 0.0 1018.09 0.32 ;
      LAYER M2 ;
      RECT 1017.89 0.0 1018.09 0.32 ;
      LAYER M3 ;
      RECT 1017.89 0.0 1018.09 0.32 ;
      LAYER M4 ;
      RECT 1017.89 0.0 1018.09 0.32 ;
      END
    ANTENNAGATEAREA 0.0072 ;
    ANTENNADIFFAREA 0.054 ;
    END D[52]
  PIN D[11]
    DIRECTION INPUT ;
    USE SIGNAL ;
    SHAPE ABUTMENT ;
    PORT
      LAYER M4 ;
      RECT 191.74 0.0 191.94 0.32 ;
      LAYER M3 ;
      RECT 191.74 0.0 191.94 0.32 ;
      LAYER M2 ;
      RECT 191.74 0.0 191.94 0.32 ;
      LAYER M1 ;
      RECT 191.74 0.0 191.94 0.32 ;
      END
    ANTENNAGATEAREA 0.0072 ;
    ANTENNADIFFAREA 0.054 ;
    END D[11]
  PIN Q[52]
    DIRECTION OUTPUT ;
    USE SIGNAL ;
    SHAPE ABUTMENT ;
    PORT
      LAYER M1 ;
      RECT 1019.525 0.0 1019.725 0.32 ;
      LAYER M2 ;
      RECT 1019.525 0.0 1019.725 0.32 ;
      LAYER M3 ;
      RECT 1019.525 0.0 1019.725 0.32 ;
      END
    ANTENNADIFFAREA 0.054 ;
    END Q[52]
  PIN Q[11]
    DIRECTION OUTPUT ;
    USE SIGNAL ;
    SHAPE ABUTMENT ;
    PORT
      LAYER M3 ;
      RECT 190.105 0.0 190.305 0.32 ;
      LAYER M2 ;
      RECT 190.105 0.0 190.305 0.32 ;
      LAYER M1 ;
      RECT 190.105 0.0 190.305 0.32 ;
      END
    ANTENNADIFFAREA 0.054 ;
    END Q[11]
  PIN TD[53]
    DIRECTION INPUT ;
    USE SIGNAL ;
    SHAPE ABUTMENT ;
    PORT
      LAYER M1 ;
      RECT 1032.39 0.0 1032.59 0.32 ;
      LAYER M2 ;
      RECT 1032.39 0.0 1032.59 0.32 ;
      LAYER M3 ;
      RECT 1032.39 0.0 1032.59 0.32 ;
      END
    ANTENNAGATEAREA 0.0072 ;
    ANTENNADIFFAREA 0.054 ;
    END TD[53]
  PIN TD[10]
    DIRECTION INPUT ;
    USE SIGNAL ;
    SHAPE ABUTMENT ;
    PORT
      LAYER M3 ;
      RECT 177.24 0.0 177.44 0.32 ;
      LAYER M2 ;
      RECT 177.24 0.0 177.44 0.32 ;
      LAYER M1 ;
      RECT 177.24 0.0 177.44 0.32 ;
      END
    ANTENNAGATEAREA 0.0072 ;
    ANTENNADIFFAREA 0.054 ;
    END TD[10]
  PIN D[53]
    DIRECTION INPUT ;
    USE SIGNAL ;
    SHAPE ABUTMENT ;
    PORT
      LAYER M1 ;
      RECT 1034.69 0.0 1034.89 0.32 ;
      LAYER M2 ;
      RECT 1034.69 0.0 1034.89 0.32 ;
      LAYER M3 ;
      RECT 1034.69 0.0 1034.89 0.32 ;
      LAYER M4 ;
      RECT 1034.69 0.0 1034.89 0.32 ;
      END
    ANTENNAGATEAREA 0.0072 ;
    ANTENNADIFFAREA 0.054 ;
    END D[53]
  PIN D[10]
    DIRECTION INPUT ;
    USE SIGNAL ;
    SHAPE ABUTMENT ;
    PORT
      LAYER M4 ;
      RECT 174.94 0.0 175.14 0.32 ;
      LAYER M3 ;
      RECT 174.94 0.0 175.14 0.32 ;
      LAYER M2 ;
      RECT 174.94 0.0 175.14 0.32 ;
      LAYER M1 ;
      RECT 174.94 0.0 175.14 0.32 ;
      END
    ANTENNAGATEAREA 0.0072 ;
    ANTENNADIFFAREA 0.054 ;
    END D[10]
  PIN Q[53]
    DIRECTION OUTPUT ;
    USE SIGNAL ;
    SHAPE ABUTMENT ;
    PORT
      LAYER M1 ;
      RECT 1036.325 0.0 1036.525 0.32 ;
      LAYER M2 ;
      RECT 1036.325 0.0 1036.525 0.32 ;
      LAYER M3 ;
      RECT 1036.325 0.0 1036.525 0.32 ;
      END
    ANTENNADIFFAREA 0.054 ;
    END Q[53]
  PIN Q[10]
    DIRECTION OUTPUT ;
    USE SIGNAL ;
    SHAPE ABUTMENT ;
    PORT
      LAYER M3 ;
      RECT 173.305 0.0 173.505 0.32 ;
      LAYER M2 ;
      RECT 173.305 0.0 173.505 0.32 ;
      LAYER M1 ;
      RECT 173.305 0.0 173.505 0.32 ;
      END
    ANTENNADIFFAREA 0.054 ;
    END Q[10]
  PIN TD[54]
    DIRECTION INPUT ;
    USE SIGNAL ;
    SHAPE ABUTMENT ;
    PORT
      LAYER M1 ;
      RECT 1049.19 0.0 1049.39 0.32 ;
      LAYER M2 ;
      RECT 1049.19 0.0 1049.39 0.32 ;
      LAYER M3 ;
      RECT 1049.19 0.0 1049.39 0.32 ;
      END
    ANTENNAGATEAREA 0.0072 ;
    ANTENNADIFFAREA 0.054 ;
    END TD[54]
  PIN TD[9]
    DIRECTION INPUT ;
    USE SIGNAL ;
    SHAPE ABUTMENT ;
    PORT
      LAYER M3 ;
      RECT 160.44 0.0 160.64 0.32 ;
      LAYER M2 ;
      RECT 160.44 0.0 160.64 0.32 ;
      LAYER M1 ;
      RECT 160.44 0.0 160.64 0.32 ;
      END
    ANTENNAGATEAREA 0.0072 ;
    ANTENNADIFFAREA 0.054 ;
    END TD[9]
  PIN D[54]
    DIRECTION INPUT ;
    USE SIGNAL ;
    SHAPE ABUTMENT ;
    PORT
      LAYER M1 ;
      RECT 1051.49 0.0 1051.69 0.32 ;
      LAYER M2 ;
      RECT 1051.49 0.0 1051.69 0.32 ;
      LAYER M3 ;
      RECT 1051.49 0.0 1051.69 0.32 ;
      LAYER M4 ;
      RECT 1051.49 0.0 1051.69 0.32 ;
      END
    ANTENNAGATEAREA 0.0072 ;
    ANTENNADIFFAREA 0.054 ;
    END D[54]
  PIN D[9]
    DIRECTION INPUT ;
    USE SIGNAL ;
    SHAPE ABUTMENT ;
    PORT
      LAYER M4 ;
      RECT 158.14 0.0 158.34 0.32 ;
      LAYER M3 ;
      RECT 158.14 0.0 158.34 0.32 ;
      LAYER M2 ;
      RECT 158.14 0.0 158.34 0.32 ;
      LAYER M1 ;
      RECT 158.14 0.0 158.34 0.32 ;
      END
    ANTENNAGATEAREA 0.0072 ;
    ANTENNADIFFAREA 0.054 ;
    END D[9]
  PIN Q[54]
    DIRECTION OUTPUT ;
    USE SIGNAL ;
    SHAPE ABUTMENT ;
    PORT
      LAYER M1 ;
      RECT 1053.125 0.0 1053.325 0.32 ;
      LAYER M2 ;
      RECT 1053.125 0.0 1053.325 0.32 ;
      LAYER M3 ;
      RECT 1053.125 0.0 1053.325 0.32 ;
      END
    ANTENNADIFFAREA 0.054 ;
    END Q[54]
  PIN Q[9]
    DIRECTION OUTPUT ;
    USE SIGNAL ;
    SHAPE ABUTMENT ;
    PORT
      LAYER M3 ;
      RECT 156.505 0.0 156.705 0.32 ;
      LAYER M2 ;
      RECT 156.505 0.0 156.705 0.32 ;
      LAYER M1 ;
      RECT 156.505 0.0 156.705 0.32 ;
      END
    ANTENNADIFFAREA 0.054 ;
    END Q[9]
  PIN TD[55]
    DIRECTION INPUT ;
    USE SIGNAL ;
    SHAPE ABUTMENT ;
    PORT
      LAYER M1 ;
      RECT 1065.99 0.0 1066.19 0.32 ;
      LAYER M2 ;
      RECT 1065.99 0.0 1066.19 0.32 ;
      LAYER M3 ;
      RECT 1065.99 0.0 1066.19 0.32 ;
      END
    ANTENNAGATEAREA 0.0072 ;
    ANTENNADIFFAREA 0.054 ;
    END TD[55]
  PIN TD[8]
    DIRECTION INPUT ;
    USE SIGNAL ;
    SHAPE ABUTMENT ;
    PORT
      LAYER M3 ;
      RECT 143.64 0.0 143.84 0.32 ;
      LAYER M2 ;
      RECT 143.64 0.0 143.84 0.32 ;
      LAYER M1 ;
      RECT 143.64 0.0 143.84 0.32 ;
      END
    ANTENNAGATEAREA 0.0072 ;
    ANTENNADIFFAREA 0.054 ;
    END TD[8]
  PIN D[55]
    DIRECTION INPUT ;
    USE SIGNAL ;
    SHAPE ABUTMENT ;
    PORT
      LAYER M1 ;
      RECT 1068.29 0.0 1068.49 0.32 ;
      LAYER M2 ;
      RECT 1068.29 0.0 1068.49 0.32 ;
      LAYER M3 ;
      RECT 1068.29 0.0 1068.49 0.32 ;
      LAYER M4 ;
      RECT 1068.29 0.0 1068.49 0.32 ;
      END
    ANTENNAGATEAREA 0.0072 ;
    ANTENNADIFFAREA 0.054 ;
    END D[55]
  PIN D[8]
    DIRECTION INPUT ;
    USE SIGNAL ;
    SHAPE ABUTMENT ;
    PORT
      LAYER M4 ;
      RECT 141.34 0.0 141.54 0.32 ;
      LAYER M3 ;
      RECT 141.34 0.0 141.54 0.32 ;
      LAYER M2 ;
      RECT 141.34 0.0 141.54 0.32 ;
      LAYER M1 ;
      RECT 141.34 0.0 141.54 0.32 ;
      END
    ANTENNAGATEAREA 0.0072 ;
    ANTENNADIFFAREA 0.054 ;
    END D[8]
  PIN Q[55]
    DIRECTION OUTPUT ;
    USE SIGNAL ;
    SHAPE ABUTMENT ;
    PORT
      LAYER M1 ;
      RECT 1069.925 0.0 1070.125 0.32 ;
      LAYER M2 ;
      RECT 1069.925 0.0 1070.125 0.32 ;
      LAYER M3 ;
      RECT 1069.925 0.0 1070.125 0.32 ;
      END
    ANTENNADIFFAREA 0.054 ;
    END Q[55]
  PIN Q[8]
    DIRECTION OUTPUT ;
    USE SIGNAL ;
    SHAPE ABUTMENT ;
    PORT
      LAYER M3 ;
      RECT 139.705 0.0 139.905 0.32 ;
      LAYER M2 ;
      RECT 139.705 0.0 139.905 0.32 ;
      LAYER M1 ;
      RECT 139.705 0.0 139.905 0.32 ;
      END
    ANTENNADIFFAREA 0.054 ;
    END Q[8]
  PIN TD[56]
    DIRECTION INPUT ;
    USE SIGNAL ;
    SHAPE ABUTMENT ;
    PORT
      LAYER M1 ;
      RECT 1082.79 0.0 1082.99 0.32 ;
      LAYER M2 ;
      RECT 1082.79 0.0 1082.99 0.32 ;
      LAYER M3 ;
      RECT 1082.79 0.0 1082.99 0.32 ;
      END
    ANTENNAGATEAREA 0.0072 ;
    ANTENNADIFFAREA 0.054 ;
    END TD[56]
  PIN TD[7]
    DIRECTION INPUT ;
    USE SIGNAL ;
    SHAPE ABUTMENT ;
    PORT
      LAYER M3 ;
      RECT 126.84 0.0 127.04 0.32 ;
      LAYER M2 ;
      RECT 126.84 0.0 127.04 0.32 ;
      LAYER M1 ;
      RECT 126.84 0.0 127.04 0.32 ;
      END
    ANTENNAGATEAREA 0.0072 ;
    ANTENNADIFFAREA 0.054 ;
    END TD[7]
  PIN D[56]
    DIRECTION INPUT ;
    USE SIGNAL ;
    SHAPE ABUTMENT ;
    PORT
      LAYER M1 ;
      RECT 1085.09 0.0 1085.29 0.32 ;
      LAYER M2 ;
      RECT 1085.09 0.0 1085.29 0.32 ;
      LAYER M3 ;
      RECT 1085.09 0.0 1085.29 0.32 ;
      LAYER M4 ;
      RECT 1085.09 0.0 1085.29 0.32 ;
      END
    ANTENNAGATEAREA 0.0072 ;
    ANTENNADIFFAREA 0.054 ;
    END D[56]
  PIN D[7]
    DIRECTION INPUT ;
    USE SIGNAL ;
    SHAPE ABUTMENT ;
    PORT
      LAYER M4 ;
      RECT 124.54 0.0 124.74 0.32 ;
      LAYER M3 ;
      RECT 124.54 0.0 124.74 0.32 ;
      LAYER M2 ;
      RECT 124.54 0.0 124.74 0.32 ;
      LAYER M1 ;
      RECT 124.54 0.0 124.74 0.32 ;
      END
    ANTENNAGATEAREA 0.0072 ;
    ANTENNADIFFAREA 0.054 ;
    END D[7]
  PIN Q[56]
    DIRECTION OUTPUT ;
    USE SIGNAL ;
    SHAPE ABUTMENT ;
    PORT
      LAYER M1 ;
      RECT 1086.725 0.0 1086.925 0.32 ;
      LAYER M2 ;
      RECT 1086.725 0.0 1086.925 0.32 ;
      LAYER M3 ;
      RECT 1086.725 0.0 1086.925 0.32 ;
      END
    ANTENNADIFFAREA 0.054 ;
    END Q[56]
  PIN Q[7]
    DIRECTION OUTPUT ;
    USE SIGNAL ;
    SHAPE ABUTMENT ;
    PORT
      LAYER M3 ;
      RECT 122.905 0.0 123.105 0.32 ;
      LAYER M2 ;
      RECT 122.905 0.0 123.105 0.32 ;
      LAYER M1 ;
      RECT 122.905 0.0 123.105 0.32 ;
      END
    ANTENNADIFFAREA 0.054 ;
    END Q[7]
  PIN TD[57]
    DIRECTION INPUT ;
    USE SIGNAL ;
    SHAPE ABUTMENT ;
    PORT
      LAYER M1 ;
      RECT 1099.59 0.0 1099.79 0.32 ;
      LAYER M2 ;
      RECT 1099.59 0.0 1099.79 0.32 ;
      LAYER M3 ;
      RECT 1099.59 0.0 1099.79 0.32 ;
      END
    ANTENNAGATEAREA 0.0072 ;
    ANTENNADIFFAREA 0.054 ;
    END TD[57]
  PIN TD[6]
    DIRECTION INPUT ;
    USE SIGNAL ;
    SHAPE ABUTMENT ;
    PORT
      LAYER M3 ;
      RECT 110.04 0.0 110.24 0.32 ;
      LAYER M2 ;
      RECT 110.04 0.0 110.24 0.32 ;
      LAYER M1 ;
      RECT 110.04 0.0 110.24 0.32 ;
      END
    ANTENNAGATEAREA 0.0072 ;
    ANTENNADIFFAREA 0.054 ;
    END TD[6]
  PIN D[57]
    DIRECTION INPUT ;
    USE SIGNAL ;
    SHAPE ABUTMENT ;
    PORT
      LAYER M1 ;
      RECT 1101.89 0.0 1102.09 0.32 ;
      LAYER M2 ;
      RECT 1101.89 0.0 1102.09 0.32 ;
      LAYER M3 ;
      RECT 1101.89 0.0 1102.09 0.32 ;
      LAYER M4 ;
      RECT 1101.89 0.0 1102.09 0.32 ;
      END
    ANTENNAGATEAREA 0.0072 ;
    ANTENNADIFFAREA 0.054 ;
    END D[57]
  PIN D[6]
    DIRECTION INPUT ;
    USE SIGNAL ;
    SHAPE ABUTMENT ;
    PORT
      LAYER M4 ;
      RECT 107.74 0.0 107.94 0.32 ;
      LAYER M3 ;
      RECT 107.74 0.0 107.94 0.32 ;
      LAYER M2 ;
      RECT 107.74 0.0 107.94 0.32 ;
      LAYER M1 ;
      RECT 107.74 0.0 107.94 0.32 ;
      END
    ANTENNAGATEAREA 0.0072 ;
    ANTENNADIFFAREA 0.054 ;
    END D[6]
  PIN Q[57]
    DIRECTION OUTPUT ;
    USE SIGNAL ;
    SHAPE ABUTMENT ;
    PORT
      LAYER M1 ;
      RECT 1103.525 0.0 1103.725 0.32 ;
      LAYER M2 ;
      RECT 1103.525 0.0 1103.725 0.32 ;
      LAYER M3 ;
      RECT 1103.525 0.0 1103.725 0.32 ;
      END
    ANTENNADIFFAREA 0.054 ;
    END Q[57]
  PIN Q[6]
    DIRECTION OUTPUT ;
    USE SIGNAL ;
    SHAPE ABUTMENT ;
    PORT
      LAYER M3 ;
      RECT 106.105 0.0 106.305 0.32 ;
      LAYER M2 ;
      RECT 106.105 0.0 106.305 0.32 ;
      LAYER M1 ;
      RECT 106.105 0.0 106.305 0.32 ;
      END
    ANTENNADIFFAREA 0.054 ;
    END Q[6]
  PIN TD[58]
    DIRECTION INPUT ;
    USE SIGNAL ;
    SHAPE ABUTMENT ;
    PORT
      LAYER M1 ;
      RECT 1116.39 0.0 1116.59 0.32 ;
      LAYER M2 ;
      RECT 1116.39 0.0 1116.59 0.32 ;
      LAYER M3 ;
      RECT 1116.39 0.0 1116.59 0.32 ;
      END
    ANTENNAGATEAREA 0.0072 ;
    ANTENNADIFFAREA 0.054 ;
    END TD[58]
  PIN TD[5]
    DIRECTION INPUT ;
    USE SIGNAL ;
    SHAPE ABUTMENT ;
    PORT
      LAYER M3 ;
      RECT 93.24 0.0 93.44 0.32 ;
      LAYER M2 ;
      RECT 93.24 0.0 93.44 0.32 ;
      LAYER M1 ;
      RECT 93.24 0.0 93.44 0.32 ;
      END
    ANTENNAGATEAREA 0.0072 ;
    ANTENNADIFFAREA 0.054 ;
    END TD[5]
  PIN D[58]
    DIRECTION INPUT ;
    USE SIGNAL ;
    SHAPE ABUTMENT ;
    PORT
      LAYER M1 ;
      RECT 1118.69 0.0 1118.89 0.32 ;
      LAYER M2 ;
      RECT 1118.69 0.0 1118.89 0.32 ;
      LAYER M3 ;
      RECT 1118.69 0.0 1118.89 0.32 ;
      LAYER M4 ;
      RECT 1118.69 0.0 1118.89 0.32 ;
      END
    ANTENNAGATEAREA 0.0072 ;
    ANTENNADIFFAREA 0.054 ;
    END D[58]
  PIN D[5]
    DIRECTION INPUT ;
    USE SIGNAL ;
    SHAPE ABUTMENT ;
    PORT
      LAYER M4 ;
      RECT 90.94 0.0 91.14 0.32 ;
      LAYER M3 ;
      RECT 90.94 0.0 91.14 0.32 ;
      LAYER M2 ;
      RECT 90.94 0.0 91.14 0.32 ;
      LAYER M1 ;
      RECT 90.94 0.0 91.14 0.32 ;
      END
    ANTENNAGATEAREA 0.0072 ;
    ANTENNADIFFAREA 0.054 ;
    END D[5]
  PIN Q[58]
    DIRECTION OUTPUT ;
    USE SIGNAL ;
    SHAPE ABUTMENT ;
    PORT
      LAYER M1 ;
      RECT 1120.325 0.0 1120.525 0.32 ;
      LAYER M2 ;
      RECT 1120.325 0.0 1120.525 0.32 ;
      LAYER M3 ;
      RECT 1120.325 0.0 1120.525 0.32 ;
      END
    ANTENNADIFFAREA 0.054 ;
    END Q[58]
  PIN Q[5]
    DIRECTION OUTPUT ;
    USE SIGNAL ;
    SHAPE ABUTMENT ;
    PORT
      LAYER M3 ;
      RECT 89.305 0.0 89.505 0.32 ;
      LAYER M2 ;
      RECT 89.305 0.0 89.505 0.32 ;
      LAYER M1 ;
      RECT 89.305 0.0 89.505 0.32 ;
      END
    ANTENNADIFFAREA 0.054 ;
    END Q[5]
  PIN TD[59]
    DIRECTION INPUT ;
    USE SIGNAL ;
    SHAPE ABUTMENT ;
    PORT
      LAYER M1 ;
      RECT 1133.19 0.0 1133.39 0.32 ;
      LAYER M2 ;
      RECT 1133.19 0.0 1133.39 0.32 ;
      LAYER M3 ;
      RECT 1133.19 0.0 1133.39 0.32 ;
      END
    ANTENNAGATEAREA 0.0072 ;
    ANTENNADIFFAREA 0.054 ;
    END TD[59]
  PIN TD[4]
    DIRECTION INPUT ;
    USE SIGNAL ;
    SHAPE ABUTMENT ;
    PORT
      LAYER M3 ;
      RECT 76.44 0.0 76.64 0.32 ;
      LAYER M2 ;
      RECT 76.44 0.0 76.64 0.32 ;
      LAYER M1 ;
      RECT 76.44 0.0 76.64 0.32 ;
      END
    ANTENNAGATEAREA 0.0072 ;
    ANTENNADIFFAREA 0.054 ;
    END TD[4]
  PIN D[59]
    DIRECTION INPUT ;
    USE SIGNAL ;
    SHAPE ABUTMENT ;
    PORT
      LAYER M1 ;
      RECT 1135.49 0.0 1135.69 0.32 ;
      LAYER M2 ;
      RECT 1135.49 0.0 1135.69 0.32 ;
      LAYER M3 ;
      RECT 1135.49 0.0 1135.69 0.32 ;
      LAYER M4 ;
      RECT 1135.49 0.0 1135.69 0.32 ;
      END
    ANTENNAGATEAREA 0.0072 ;
    ANTENNADIFFAREA 0.054 ;
    END D[59]
  PIN D[4]
    DIRECTION INPUT ;
    USE SIGNAL ;
    SHAPE ABUTMENT ;
    PORT
      LAYER M4 ;
      RECT 74.14 0.0 74.34 0.32 ;
      LAYER M3 ;
      RECT 74.14 0.0 74.34 0.32 ;
      LAYER M2 ;
      RECT 74.14 0.0 74.34 0.32 ;
      LAYER M1 ;
      RECT 74.14 0.0 74.34 0.32 ;
      END
    ANTENNAGATEAREA 0.0072 ;
    ANTENNADIFFAREA 0.054 ;
    END D[4]
  PIN Q[59]
    DIRECTION OUTPUT ;
    USE SIGNAL ;
    SHAPE ABUTMENT ;
    PORT
      LAYER M1 ;
      RECT 1137.125 0.0 1137.325 0.32 ;
      LAYER M2 ;
      RECT 1137.125 0.0 1137.325 0.32 ;
      LAYER M3 ;
      RECT 1137.125 0.0 1137.325 0.32 ;
      END
    ANTENNADIFFAREA 0.054 ;
    END Q[59]
  PIN Q[4]
    DIRECTION OUTPUT ;
    USE SIGNAL ;
    SHAPE ABUTMENT ;
    PORT
      LAYER M3 ;
      RECT 72.505 0.0 72.705 0.32 ;
      LAYER M2 ;
      RECT 72.505 0.0 72.705 0.32 ;
      LAYER M1 ;
      RECT 72.505 0.0 72.705 0.32 ;
      END
    ANTENNADIFFAREA 0.054 ;
    END Q[4]
  PIN TD[60]
    DIRECTION INPUT ;
    USE SIGNAL ;
    SHAPE ABUTMENT ;
    PORT
      LAYER M1 ;
      RECT 1149.99 0.0 1150.19 0.32 ;
      LAYER M2 ;
      RECT 1149.99 0.0 1150.19 0.32 ;
      LAYER M3 ;
      RECT 1149.99 0.0 1150.19 0.32 ;
      END
    ANTENNAGATEAREA 0.0072 ;
    ANTENNADIFFAREA 0.054 ;
    END TD[60]
  PIN TD[3]
    DIRECTION INPUT ;
    USE SIGNAL ;
    SHAPE ABUTMENT ;
    PORT
      LAYER M3 ;
      RECT 59.64 0.0 59.84 0.32 ;
      LAYER M2 ;
      RECT 59.64 0.0 59.84 0.32 ;
      LAYER M1 ;
      RECT 59.64 0.0 59.84 0.32 ;
      END
    ANTENNAGATEAREA 0.0072 ;
    ANTENNADIFFAREA 0.054 ;
    END TD[3]
  PIN D[60]
    DIRECTION INPUT ;
    USE SIGNAL ;
    SHAPE ABUTMENT ;
    PORT
      LAYER M1 ;
      RECT 1152.29 0.0 1152.49 0.32 ;
      LAYER M2 ;
      RECT 1152.29 0.0 1152.49 0.32 ;
      LAYER M3 ;
      RECT 1152.29 0.0 1152.49 0.32 ;
      LAYER M4 ;
      RECT 1152.29 0.0 1152.49 0.32 ;
      END
    ANTENNAGATEAREA 0.0072 ;
    ANTENNADIFFAREA 0.054 ;
    END D[60]
  PIN D[3]
    DIRECTION INPUT ;
    USE SIGNAL ;
    SHAPE ABUTMENT ;
    PORT
      LAYER M4 ;
      RECT 57.34 0.0 57.54 0.32 ;
      LAYER M3 ;
      RECT 57.34 0.0 57.54 0.32 ;
      LAYER M2 ;
      RECT 57.34 0.0 57.54 0.32 ;
      LAYER M1 ;
      RECT 57.34 0.0 57.54 0.32 ;
      END
    ANTENNAGATEAREA 0.0072 ;
    ANTENNADIFFAREA 0.054 ;
    END D[3]
  PIN Q[60]
    DIRECTION OUTPUT ;
    USE SIGNAL ;
    SHAPE ABUTMENT ;
    PORT
      LAYER M1 ;
      RECT 1153.925 0.0 1154.125 0.32 ;
      LAYER M2 ;
      RECT 1153.925 0.0 1154.125 0.32 ;
      LAYER M3 ;
      RECT 1153.925 0.0 1154.125 0.32 ;
      END
    ANTENNADIFFAREA 0.054 ;
    END Q[60]
  PIN Q[3]
    DIRECTION OUTPUT ;
    USE SIGNAL ;
    SHAPE ABUTMENT ;
    PORT
      LAYER M3 ;
      RECT 55.705 0.0 55.905 0.32 ;
      LAYER M2 ;
      RECT 55.705 0.0 55.905 0.32 ;
      LAYER M1 ;
      RECT 55.705 0.0 55.905 0.32 ;
      END
    ANTENNADIFFAREA 0.054 ;
    END Q[3]
  PIN TD[61]
    DIRECTION INPUT ;
    USE SIGNAL ;
    SHAPE ABUTMENT ;
    PORT
      LAYER M1 ;
      RECT 1166.79 0.0 1166.99 0.32 ;
      LAYER M2 ;
      RECT 1166.79 0.0 1166.99 0.32 ;
      LAYER M3 ;
      RECT 1166.79 0.0 1166.99 0.32 ;
      END
    ANTENNAGATEAREA 0.0072 ;
    ANTENNADIFFAREA 0.054 ;
    END TD[61]
  PIN TD[2]
    DIRECTION INPUT ;
    USE SIGNAL ;
    SHAPE ABUTMENT ;
    PORT
      LAYER M3 ;
      RECT 42.84 0.0 43.04 0.32 ;
      LAYER M2 ;
      RECT 42.84 0.0 43.04 0.32 ;
      LAYER M1 ;
      RECT 42.84 0.0 43.04 0.32 ;
      END
    ANTENNAGATEAREA 0.0072 ;
    ANTENNADIFFAREA 0.054 ;
    END TD[2]
  PIN D[61]
    DIRECTION INPUT ;
    USE SIGNAL ;
    SHAPE ABUTMENT ;
    PORT
      LAYER M1 ;
      RECT 1169.09 0.0 1169.29 0.32 ;
      LAYER M2 ;
      RECT 1169.09 0.0 1169.29 0.32 ;
      LAYER M3 ;
      RECT 1169.09 0.0 1169.29 0.32 ;
      LAYER M4 ;
      RECT 1169.09 0.0 1169.29 0.32 ;
      END
    ANTENNAGATEAREA 0.0072 ;
    ANTENNADIFFAREA 0.054 ;
    END D[61]
  PIN D[2]
    DIRECTION INPUT ;
    USE SIGNAL ;
    SHAPE ABUTMENT ;
    PORT
      LAYER M4 ;
      RECT 40.54 0.0 40.74 0.32 ;
      LAYER M3 ;
      RECT 40.54 0.0 40.74 0.32 ;
      LAYER M2 ;
      RECT 40.54 0.0 40.74 0.32 ;
      LAYER M1 ;
      RECT 40.54 0.0 40.74 0.32 ;
      END
    ANTENNAGATEAREA 0.0072 ;
    ANTENNADIFFAREA 0.054 ;
    END D[2]
  PIN Q[61]
    DIRECTION OUTPUT ;
    USE SIGNAL ;
    SHAPE ABUTMENT ;
    PORT
      LAYER M1 ;
      RECT 1170.725 0.0 1170.925 0.32 ;
      LAYER M2 ;
      RECT 1170.725 0.0 1170.925 0.32 ;
      LAYER M3 ;
      RECT 1170.725 0.0 1170.925 0.32 ;
      END
    ANTENNADIFFAREA 0.054 ;
    END Q[61]
  PIN Q[2]
    DIRECTION OUTPUT ;
    USE SIGNAL ;
    SHAPE ABUTMENT ;
    PORT
      LAYER M3 ;
      RECT 38.905 0.0 39.105 0.32 ;
      LAYER M2 ;
      RECT 38.905 0.0 39.105 0.32 ;
      LAYER M1 ;
      RECT 38.905 0.0 39.105 0.32 ;
      END
    ANTENNADIFFAREA 0.054 ;
    END Q[2]
  PIN TD[62]
    DIRECTION INPUT ;
    USE SIGNAL ;
    SHAPE ABUTMENT ;
    PORT
      LAYER M1 ;
      RECT 1183.59 0.0 1183.79 0.32 ;
      LAYER M2 ;
      RECT 1183.59 0.0 1183.79 0.32 ;
      LAYER M3 ;
      RECT 1183.59 0.0 1183.79 0.32 ;
      END
    ANTENNAGATEAREA 0.0072 ;
    ANTENNADIFFAREA 0.054 ;
    END TD[62]
  PIN TD[1]
    DIRECTION INPUT ;
    USE SIGNAL ;
    SHAPE ABUTMENT ;
    PORT
      LAYER M3 ;
      RECT 26.04 0.0 26.24 0.32 ;
      LAYER M2 ;
      RECT 26.04 0.0 26.24 0.32 ;
      LAYER M1 ;
      RECT 26.04 0.0 26.24 0.32 ;
      END
    ANTENNAGATEAREA 0.0072 ;
    ANTENNADIFFAREA 0.054 ;
    END TD[1]
  PIN D[62]
    DIRECTION INPUT ;
    USE SIGNAL ;
    SHAPE ABUTMENT ;
    PORT
      LAYER M1 ;
      RECT 1185.89 0.0 1186.09 0.32 ;
      LAYER M2 ;
      RECT 1185.89 0.0 1186.09 0.32 ;
      LAYER M3 ;
      RECT 1185.89 0.0 1186.09 0.32 ;
      LAYER M4 ;
      RECT 1185.89 0.0 1186.09 0.32 ;
      END
    ANTENNAGATEAREA 0.0072 ;
    ANTENNADIFFAREA 0.054 ;
    END D[62]
  PIN D[1]
    DIRECTION INPUT ;
    USE SIGNAL ;
    SHAPE ABUTMENT ;
    PORT
      LAYER M4 ;
      RECT 23.74 0.0 23.94 0.32 ;
      LAYER M3 ;
      RECT 23.74 0.0 23.94 0.32 ;
      LAYER M2 ;
      RECT 23.74 0.0 23.94 0.32 ;
      LAYER M1 ;
      RECT 23.74 0.0 23.94 0.32 ;
      END
    ANTENNAGATEAREA 0.0072 ;
    ANTENNADIFFAREA 0.054 ;
    END D[1]
  PIN Q[62]
    DIRECTION OUTPUT ;
    USE SIGNAL ;
    SHAPE ABUTMENT ;
    PORT
      LAYER M1 ;
      RECT 1187.525 0.0 1187.725 0.32 ;
      LAYER M2 ;
      RECT 1187.525 0.0 1187.725 0.32 ;
      LAYER M3 ;
      RECT 1187.525 0.0 1187.725 0.32 ;
      END
    ANTENNADIFFAREA 0.054 ;
    END Q[62]
  PIN Q[1]
    DIRECTION OUTPUT ;
    USE SIGNAL ;
    SHAPE ABUTMENT ;
    PORT
      LAYER M3 ;
      RECT 22.105 0.0 22.305 0.32 ;
      LAYER M2 ;
      RECT 22.105 0.0 22.305 0.32 ;
      LAYER M1 ;
      RECT 22.105 0.0 22.305 0.32 ;
      END
    ANTENNADIFFAREA 0.054 ;
    END Q[1]
  PIN TD[63]
    DIRECTION INPUT ;
    USE SIGNAL ;
    SHAPE ABUTMENT ;
    PORT
      LAYER M1 ;
      RECT 1200.39 0.0 1200.59 0.32 ;
      LAYER M2 ;
      RECT 1200.39 0.0 1200.59 0.32 ;
      LAYER M3 ;
      RECT 1200.39 0.0 1200.59 0.32 ;
      END
    ANTENNAGATEAREA 0.0072 ;
    ANTENNADIFFAREA 0.054 ;
    END TD[63]
  PIN TD[0]
    DIRECTION INPUT ;
    USE SIGNAL ;
    SHAPE ABUTMENT ;
    PORT
      LAYER M3 ;
      RECT 9.24 0.0 9.44 0.32 ;
      LAYER M2 ;
      RECT 9.24 0.0 9.44 0.32 ;
      LAYER M1 ;
      RECT 9.24 0.0 9.44 0.32 ;
      END
    ANTENNAGATEAREA 0.0072 ;
    ANTENNADIFFAREA 0.054 ;
    END TD[0]
  PIN D[63]
    DIRECTION INPUT ;
    USE SIGNAL ;
    SHAPE ABUTMENT ;
    PORT
      LAYER M1 ;
      RECT 1202.69 0.0 1202.89 0.32 ;
      LAYER M2 ;
      RECT 1202.69 0.0 1202.89 0.32 ;
      LAYER M3 ;
      RECT 1202.69 0.0 1202.89 0.32 ;
      LAYER M4 ;
      RECT 1202.69 0.0 1202.89 0.32 ;
      END
    ANTENNAGATEAREA 0.0072 ;
    ANTENNADIFFAREA 0.054 ;
    END D[63]
  PIN D[0]
    DIRECTION INPUT ;
    USE SIGNAL ;
    SHAPE ABUTMENT ;
    PORT
      LAYER M4 ;
      RECT 6.94 0.0 7.14 0.32 ;
      LAYER M3 ;
      RECT 6.94 0.0 7.14 0.32 ;
      LAYER M2 ;
      RECT 6.94 0.0 7.14 0.32 ;
      LAYER M1 ;
      RECT 6.94 0.0 7.14 0.32 ;
      END
    ANTENNAGATEAREA 0.0072 ;
    ANTENNADIFFAREA 0.054 ;
    END D[0]
  PIN Q[63]
    DIRECTION OUTPUT ;
    USE SIGNAL ;
    SHAPE ABUTMENT ;
    PORT
      LAYER M1 ;
      RECT 1204.325 0.0 1204.525 0.32 ;
      LAYER M2 ;
      RECT 1204.325 0.0 1204.525 0.32 ;
      LAYER M3 ;
      RECT 1204.325 0.0 1204.525 0.32 ;
      END
    ANTENNADIFFAREA 0.054 ;
    END Q[63]
  PIN Q[0]
    DIRECTION OUTPUT ;
    USE SIGNAL ;
    SHAPE ABUTMENT ;
    PORT
      LAYER M3 ;
      RECT 5.305 0.0 5.505 0.32 ;
      LAYER M2 ;
      RECT 5.305 0.0 5.505 0.32 ;
      LAYER M1 ;
      RECT 5.305 0.0 5.505 0.32 ;
      END
    ANTENNADIFFAREA 0.054 ;
    END Q[0]
  PIN SI[1]
    DIRECTION INPUT ;
    USE SIGNAL ;
    SHAPE ABUTMENT ;
    PORT
      LAYER M1 ;
      RECT 1208.85 0.0 1209.05 0.32 ;
      LAYER M2 ;
      RECT 1208.85 0.0 1209.05 0.32 ;
      LAYER M3 ;
      RECT 1208.85 0.0 1209.05 0.32 ;
      END
    ANTENNAGATEAREA 0.0072 ;
    ANTENNADIFFAREA 0.054 ;
    END SI[1]
  PIN SI[0]
    DIRECTION INPUT ;
    USE SIGNAL ;
    SHAPE ABUTMENT ;
    PORT
      LAYER M3 ;
      RECT 0.78 0.0 0.98 0.32 ;
      LAYER M2 ;
      RECT 0.78 0.0 0.98 0.32 ;
      LAYER M1 ;
      RECT 0.78 0.0 0.98 0.32 ;
      END
    ANTENNAGATEAREA 0.0072 ;
    ANTENNADIFFAREA 0.054 ;
    END SI[0]
  PIN VDDCE
    DIRECTION INOUT ;
    USE POWER ;
    PORT
      LAYER M4 ;
      RECT 0.695 0.0 0.845 315.365 ;
      END
    PORT
      LAYER M4 ;
      RECT 4.255 0.0 4.595 315.365 ;
      END
    PORT
      LAYER M4 ;
      RECT 6.365 0.0 6.705 315.365 ;
      END
    PORT
      LAYER M4 ;
      RECT 12.655 0.0 12.995 315.365 ;
      END
    PORT
      LAYER M4 ;
      RECT 14.765 0.0 15.105 315.365 ;
      END
    PORT
      LAYER M4 ;
      RECT 21.055 0.0 21.395 315.365 ;
      END
    PORT
      LAYER M4 ;
      RECT 23.165 0.0 23.505 315.365 ;
      END
    PORT
      LAYER M4 ;
      RECT 29.455 0.0 29.795 315.365 ;
      END
    PORT
      LAYER M4 ;
      RECT 31.565 0.0 31.905 315.365 ;
      END
    PORT
      LAYER M4 ;
      RECT 37.855 0.0 38.195 315.365 ;
      END
    PORT
      LAYER M4 ;
      RECT 39.965 0.0 40.305 315.365 ;
      END
    PORT
      LAYER M4 ;
      RECT 46.255 0.0 46.595 315.365 ;
      END
    PORT
      LAYER M4 ;
      RECT 48.365 0.0 48.705 315.365 ;
      END
    PORT
      LAYER M4 ;
      RECT 54.655 0.0 54.995 315.365 ;
      END
    PORT
      LAYER M4 ;
      RECT 56.765 0.0 57.105 315.365 ;
      END
    PORT
      LAYER M4 ;
      RECT 63.055 0.0 63.395 315.365 ;
      END
    PORT
      LAYER M4 ;
      RECT 65.165 0.0 65.505 315.365 ;
      END
    PORT
      LAYER M4 ;
      RECT 71.455 0.0 71.795 315.365 ;
      END
    PORT
      LAYER M4 ;
      RECT 73.565 0.0 73.905 315.365 ;
      END
    PORT
      LAYER M4 ;
      RECT 79.855 0.0 80.195 315.365 ;
      END
    PORT
      LAYER M4 ;
      RECT 81.965 0.0 82.305 315.365 ;
      END
    PORT
      LAYER M4 ;
      RECT 88.255 0.0 88.595 315.365 ;
      END
    PORT
      LAYER M4 ;
      RECT 90.365 0.0 90.705 315.365 ;
      END
    PORT
      LAYER M4 ;
      RECT 96.655 0.0 96.995 315.365 ;
      END
    PORT
      LAYER M4 ;
      RECT 98.765 0.0 99.105 315.365 ;
      END
    PORT
      LAYER M4 ;
      RECT 105.055 0.0 105.395 315.365 ;
      END
    PORT
      LAYER M4 ;
      RECT 107.165 0.0 107.505 315.365 ;
      END
    PORT
      LAYER M4 ;
      RECT 113.455 0.0 113.795 315.365 ;
      END
    PORT
      LAYER M4 ;
      RECT 115.565 0.0 115.905 315.365 ;
      END
    PORT
      LAYER M4 ;
      RECT 121.855 0.0 122.195 315.365 ;
      END
    PORT
      LAYER M4 ;
      RECT 123.965 0.0 124.305 315.365 ;
      END
    PORT
      LAYER M4 ;
      RECT 130.255 0.0 130.595 315.365 ;
      END
    PORT
      LAYER M4 ;
      RECT 132.365 0.0 132.705 315.365 ;
      END
    PORT
      LAYER M4 ;
      RECT 138.655 0.0 138.995 315.365 ;
      END
    PORT
      LAYER M4 ;
      RECT 140.765 0.0 141.105 315.365 ;
      END
    PORT
      LAYER M4 ;
      RECT 147.055 0.0 147.395 315.365 ;
      END
    PORT
      LAYER M4 ;
      RECT 149.165 0.0 149.505 315.365 ;
      END
    PORT
      LAYER M4 ;
      RECT 155.455 0.0 155.795 315.365 ;
      END
    PORT
      LAYER M4 ;
      RECT 157.565 0.0 157.905 315.365 ;
      END
    PORT
      LAYER M4 ;
      RECT 163.855 0.0 164.195 315.365 ;
      END
    PORT
      LAYER M4 ;
      RECT 165.965 0.0 166.305 315.365 ;
      END
    PORT
      LAYER M4 ;
      RECT 172.255 0.0 172.595 315.365 ;
      END
    PORT
      LAYER M4 ;
      RECT 174.365 0.0 174.705 315.365 ;
      END
    PORT
      LAYER M4 ;
      RECT 180.655 0.0 180.995 315.365 ;
      END
    PORT
      LAYER M4 ;
      RECT 182.765 0.0 183.105 315.365 ;
      END
    PORT
      LAYER M4 ;
      RECT 189.055 0.0 189.395 315.365 ;
      END
    PORT
      LAYER M4 ;
      RECT 191.165 0.0 191.505 315.365 ;
      END
    PORT
      LAYER M4 ;
      RECT 197.455 0.0 197.795 315.365 ;
      END
    PORT
      LAYER M4 ;
      RECT 199.565 0.0 199.905 315.365 ;
      END
    PORT
      LAYER M4 ;
      RECT 205.855 0.0 206.195 315.365 ;
      END
    PORT
      LAYER M4 ;
      RECT 207.965 0.0 208.305 315.365 ;
      END
    PORT
      LAYER M4 ;
      RECT 214.255 0.0 214.595 315.365 ;
      END
    PORT
      LAYER M4 ;
      RECT 216.365 0.0 216.705 315.365 ;
      END
    PORT
      LAYER M4 ;
      RECT 222.655 0.0 222.995 315.365 ;
      END
    PORT
      LAYER M4 ;
      RECT 224.765 0.0 225.105 315.365 ;
      END
    PORT
      LAYER M4 ;
      RECT 231.055 0.0 231.395 315.365 ;
      END
    PORT
      LAYER M4 ;
      RECT 233.165 0.0 233.505 315.365 ;
      END
    PORT
      LAYER M4 ;
      RECT 239.455 0.0 239.795 315.365 ;
      END
    PORT
      LAYER M4 ;
      RECT 241.565 0.0 241.905 315.365 ;
      END
    PORT
      LAYER M4 ;
      RECT 247.855 0.0 248.195 315.365 ;
      END
    PORT
      LAYER M4 ;
      RECT 249.965 0.0 250.305 315.365 ;
      END
    PORT
      LAYER M4 ;
      RECT 256.255 0.0 256.595 315.365 ;
      END
    PORT
      LAYER M4 ;
      RECT 258.365 0.0 258.705 315.365 ;
      END
    PORT
      LAYER M4 ;
      RECT 264.655 0.0 264.995 315.365 ;
      END
    PORT
      LAYER M4 ;
      RECT 266.765 0.0 267.105 315.365 ;
      END
    PORT
      LAYER M4 ;
      RECT 271.495 0.0 271.925 315.365 ;
      END
    PORT
      LAYER M4 ;
      RECT 276.165 0.0 276.495 315.365 ;
      END
    PORT
      LAYER M4 ;
      RECT 279.44 0.0 279.86 315.365 ;
      END
    PORT
      LAYER M4 ;
      RECT 282.09 0.0 282.51 315.365 ;
      END
    PORT
      LAYER M4 ;
      RECT 289.48 0.0 289.9 315.365 ;
      END
    PORT
      LAYER M4 ;
      RECT 294.69 0.0 295.11 315.365 ;
      END
    PORT
      LAYER M4 ;
      RECT 307.125 0.0 307.545 315.365 ;
      END
    PORT
      LAYER M4 ;
      RECT 320.55 0.0 320.97 315.365 ;
      END
    PORT
      LAYER M4 ;
      RECT 325.26 0.0 325.68 315.365 ;
      END
    PORT
      LAYER M4 ;
      RECT 328.64 0.0 328.97 315.365 ;
      END
    PORT
      LAYER M4 ;
      RECT 333.21 0.0 333.63 315.365 ;
      END
    PORT
      LAYER M4 ;
      RECT 338.055 0.0 338.395 315.365 ;
      END
    PORT
      LAYER M4 ;
      RECT 340.165 0.0 340.505 315.365 ;
      END
    PORT
      LAYER M4 ;
      RECT 346.455 0.0 346.795 315.365 ;
      END
    PORT
      LAYER M4 ;
      RECT 348.565 0.0 348.905 315.365 ;
      END
    PORT
      LAYER M4 ;
      RECT 354.855 0.0 355.195 315.365 ;
      END
    PORT
      LAYER M4 ;
      RECT 356.965 0.0 357.305 315.365 ;
      END
    PORT
      LAYER M4 ;
      RECT 363.255 0.0 363.595 315.365 ;
      END
    PORT
      LAYER M4 ;
      RECT 365.365 0.0 365.705 315.365 ;
      END
    PORT
      LAYER M4 ;
      RECT 371.655 0.0 371.995 315.365 ;
      END
    PORT
      LAYER M4 ;
      RECT 373.765 0.0 374.105 315.365 ;
      END
    PORT
      LAYER M4 ;
      RECT 380.055 0.0 380.395 315.365 ;
      END
    PORT
      LAYER M4 ;
      RECT 382.165 0.0 382.505 315.365 ;
      END
    PORT
      LAYER M4 ;
      RECT 388.455 0.0 388.795 315.365 ;
      END
    PORT
      LAYER M4 ;
      RECT 390.565 0.0 390.905 315.365 ;
      END
    PORT
      LAYER M4 ;
      RECT 396.855 0.0 397.195 315.365 ;
      END
    PORT
      LAYER M4 ;
      RECT 398.965 0.0 399.305 315.365 ;
      END
    PORT
      LAYER M4 ;
      RECT 405.255 0.0 405.595 315.365 ;
      END
    PORT
      LAYER M4 ;
      RECT 407.365 0.0 407.705 315.365 ;
      END
    PORT
      LAYER M4 ;
      RECT 413.655 0.0 413.995 315.365 ;
      END
    PORT
      LAYER M4 ;
      RECT 415.765 0.0 416.105 315.365 ;
      END
    PORT
      LAYER M4 ;
      RECT 422.055 0.0 422.395 315.365 ;
      END
    PORT
      LAYER M4 ;
      RECT 424.165 0.0 424.505 315.365 ;
      END
    PORT
      LAYER M4 ;
      RECT 430.455 0.0 430.795 315.365 ;
      END
    PORT
      LAYER M4 ;
      RECT 432.565 0.0 432.905 315.365 ;
      END
    PORT
      LAYER M4 ;
      RECT 438.855 0.0 439.195 315.365 ;
      END
    PORT
      LAYER M4 ;
      RECT 440.965 0.0 441.305 315.365 ;
      END
    PORT
      LAYER M4 ;
      RECT 447.255 0.0 447.595 315.365 ;
      END
    PORT
      LAYER M4 ;
      RECT 449.365 0.0 449.705 315.365 ;
      END
    PORT
      LAYER M4 ;
      RECT 455.655 0.0 455.995 315.365 ;
      END
    PORT
      LAYER M4 ;
      RECT 457.765 0.0 458.105 315.365 ;
      END
    PORT
      LAYER M4 ;
      RECT 464.055 0.0 464.395 315.365 ;
      END
    PORT
      LAYER M4 ;
      RECT 466.165 0.0 466.505 315.365 ;
      END
    PORT
      LAYER M4 ;
      RECT 472.455 0.0 472.795 315.365 ;
      END
    PORT
      LAYER M4 ;
      RECT 474.565 0.0 474.905 315.365 ;
      END
    PORT
      LAYER M4 ;
      RECT 480.855 0.0 481.195 315.365 ;
      END
    PORT
      LAYER M4 ;
      RECT 482.965 0.0 483.305 315.365 ;
      END
    PORT
      LAYER M4 ;
      RECT 489.255 0.0 489.595 315.365 ;
      END
    PORT
      LAYER M4 ;
      RECT 491.365 0.0 491.705 315.365 ;
      END
    PORT
      LAYER M4 ;
      RECT 497.655 0.0 497.995 315.365 ;
      END
    PORT
      LAYER M4 ;
      RECT 499.765 0.0 500.105 315.365 ;
      END
    PORT
      LAYER M4 ;
      RECT 506.055 0.0 506.395 315.365 ;
      END
    PORT
      LAYER M4 ;
      RECT 508.165 0.0 508.505 315.365 ;
      END
    PORT
      LAYER M4 ;
      RECT 514.455 0.0 514.795 315.365 ;
      END
    PORT
      LAYER M4 ;
      RECT 516.565 0.0 516.905 315.365 ;
      END
    PORT
      LAYER M4 ;
      RECT 522.855 0.0 523.195 315.365 ;
      END
    PORT
      LAYER M4 ;
      RECT 524.965 0.0 525.305 315.365 ;
      END
    PORT
      LAYER M4 ;
      RECT 531.255 0.0 531.595 315.365 ;
      END
    PORT
      LAYER M4 ;
      RECT 533.365 0.0 533.705 315.365 ;
      END
    PORT
      LAYER M4 ;
      RECT 539.655 0.0 539.995 315.365 ;
      END
    PORT
      LAYER M4 ;
      RECT 541.765 0.0 542.105 315.365 ;
      END
    PORT
      LAYER M4 ;
      RECT 548.055 0.0 548.395 315.365 ;
      END
    PORT
      LAYER M4 ;
      RECT 550.165 0.0 550.505 315.365 ;
      END
    PORT
      LAYER M4 ;
      RECT 556.455 0.0 556.795 315.365 ;
      END
    PORT
      LAYER M4 ;
      RECT 558.565 0.0 558.905 315.365 ;
      END
    PORT
      LAYER M4 ;
      RECT 564.855 0.0 565.195 315.365 ;
      END
    PORT
      LAYER M4 ;
      RECT 566.965 0.0 567.305 315.365 ;
      END
    PORT
      LAYER M4 ;
      RECT 573.255 0.0 573.595 315.365 ;
      END
    PORT
      LAYER M4 ;
      RECT 575.365 0.0 575.705 315.365 ;
      END
    PORT
      LAYER M4 ;
      RECT 581.655 0.0 581.995 315.365 ;
      END
    PORT
      LAYER M4 ;
      RECT 583.765 0.0 584.105 315.365 ;
      END
    PORT
      LAYER M4 ;
      RECT 590.055 0.0 590.395 315.365 ;
      END
    PORT
      LAYER M4 ;
      RECT 592.165 0.0 592.505 315.365 ;
      END
    PORT
      LAYER M4 ;
      RECT 598.455 0.0 598.795 315.365 ;
      END
    PORT
      LAYER M4 ;
      RECT 600.565 0.0 600.905 315.365 ;
      END
    PORT
      LAYER M4 ;
      RECT 604.595 0.0 604.745 315.365 ;
      END
    PORT
      LAYER M4 ;
      RECT 605.085 0.0 605.235 315.365 ;
      END
    PORT
      LAYER M4 ;
      RECT 608.925 0.0 609.265 315.365 ;
      END
    PORT
      LAYER M4 ;
      RECT 611.035 0.0 611.375 315.365 ;
      END
    PORT
      LAYER M4 ;
      RECT 617.325 0.0 617.665 315.365 ;
      END
    PORT
      LAYER M4 ;
      RECT 619.435 0.0 619.775 315.365 ;
      END
    PORT
      LAYER M4 ;
      RECT 625.725 0.0 626.065 315.365 ;
      END
    PORT
      LAYER M4 ;
      RECT 627.835 0.0 628.175 315.365 ;
      END
    PORT
      LAYER M4 ;
      RECT 634.125 0.0 634.465 315.365 ;
      END
    PORT
      LAYER M4 ;
      RECT 636.235 0.0 636.575 315.365 ;
      END
    PORT
      LAYER M4 ;
      RECT 642.525 0.0 642.865 315.365 ;
      END
    PORT
      LAYER M4 ;
      RECT 644.635 0.0 644.975 315.365 ;
      END
    PORT
      LAYER M4 ;
      RECT 650.925 0.0 651.265 315.365 ;
      END
    PORT
      LAYER M4 ;
      RECT 653.035 0.0 653.375 315.365 ;
      END
    PORT
      LAYER M4 ;
      RECT 659.325 0.0 659.665 315.365 ;
      END
    PORT
      LAYER M4 ;
      RECT 661.435 0.0 661.775 315.365 ;
      END
    PORT
      LAYER M4 ;
      RECT 667.725 0.0 668.065 315.365 ;
      END
    PORT
      LAYER M4 ;
      RECT 669.835 0.0 670.175 315.365 ;
      END
    PORT
      LAYER M4 ;
      RECT 676.125 0.0 676.465 315.365 ;
      END
    PORT
      LAYER M4 ;
      RECT 678.235 0.0 678.575 315.365 ;
      END
    PORT
      LAYER M4 ;
      RECT 684.525 0.0 684.865 315.365 ;
      END
    PORT
      LAYER M4 ;
      RECT 686.635 0.0 686.975 315.365 ;
      END
    PORT
      LAYER M4 ;
      RECT 692.925 0.0 693.265 315.365 ;
      END
    PORT
      LAYER M4 ;
      RECT 695.035 0.0 695.375 315.365 ;
      END
    PORT
      LAYER M4 ;
      RECT 701.325 0.0 701.665 315.365 ;
      END
    PORT
      LAYER M4 ;
      RECT 703.435 0.0 703.775 315.365 ;
      END
    PORT
      LAYER M4 ;
      RECT 709.725 0.0 710.065 315.365 ;
      END
    PORT
      LAYER M4 ;
      RECT 711.835 0.0 712.175 315.365 ;
      END
    PORT
      LAYER M4 ;
      RECT 718.125 0.0 718.465 315.365 ;
      END
    PORT
      LAYER M4 ;
      RECT 720.235 0.0 720.575 315.365 ;
      END
    PORT
      LAYER M4 ;
      RECT 726.525 0.0 726.865 315.365 ;
      END
    PORT
      LAYER M4 ;
      RECT 728.635 0.0 728.975 315.365 ;
      END
    PORT
      LAYER M4 ;
      RECT 734.925 0.0 735.265 315.365 ;
      END
    PORT
      LAYER M4 ;
      RECT 737.035 0.0 737.375 315.365 ;
      END
    PORT
      LAYER M4 ;
      RECT 743.325 0.0 743.665 315.365 ;
      END
    PORT
      LAYER M4 ;
      RECT 745.435 0.0 745.775 315.365 ;
      END
    PORT
      LAYER M4 ;
      RECT 751.725 0.0 752.065 315.365 ;
      END
    PORT
      LAYER M4 ;
      RECT 753.835 0.0 754.175 315.365 ;
      END
    PORT
      LAYER M4 ;
      RECT 760.125 0.0 760.465 315.365 ;
      END
    PORT
      LAYER M4 ;
      RECT 762.235 0.0 762.575 315.365 ;
      END
    PORT
      LAYER M4 ;
      RECT 768.525 0.0 768.865 315.365 ;
      END
    PORT
      LAYER M4 ;
      RECT 770.635 0.0 770.975 315.365 ;
      END
    PORT
      LAYER M4 ;
      RECT 776.925 0.0 777.265 315.365 ;
      END
    PORT
      LAYER M4 ;
      RECT 779.035 0.0 779.375 315.365 ;
      END
    PORT
      LAYER M4 ;
      RECT 785.325 0.0 785.665 315.365 ;
      END
    PORT
      LAYER M4 ;
      RECT 787.435 0.0 787.775 315.365 ;
      END
    PORT
      LAYER M4 ;
      RECT 793.725 0.0 794.065 315.365 ;
      END
    PORT
      LAYER M4 ;
      RECT 795.835 0.0 796.175 315.365 ;
      END
    PORT
      LAYER M4 ;
      RECT 802.125 0.0 802.465 315.365 ;
      END
    PORT
      LAYER M4 ;
      RECT 804.235 0.0 804.575 315.365 ;
      END
    PORT
      LAYER M4 ;
      RECT 810.525 0.0 810.865 315.365 ;
      END
    PORT
      LAYER M4 ;
      RECT 812.635 0.0 812.975 315.365 ;
      END
    PORT
      LAYER M4 ;
      RECT 818.925 0.0 819.265 315.365 ;
      END
    PORT
      LAYER M4 ;
      RECT 821.035 0.0 821.375 315.365 ;
      END
    PORT
      LAYER M4 ;
      RECT 827.325 0.0 827.665 315.365 ;
      END
    PORT
      LAYER M4 ;
      RECT 829.435 0.0 829.775 315.365 ;
      END
    PORT
      LAYER M4 ;
      RECT 835.725 0.0 836.065 315.365 ;
      END
    PORT
      LAYER M4 ;
      RECT 837.835 0.0 838.175 315.365 ;
      END
    PORT
      LAYER M4 ;
      RECT 844.125 0.0 844.465 315.365 ;
      END
    PORT
      LAYER M4 ;
      RECT 846.235 0.0 846.575 315.365 ;
      END
    PORT
      LAYER M4 ;
      RECT 852.525 0.0 852.865 315.365 ;
      END
    PORT
      LAYER M4 ;
      RECT 854.635 0.0 854.975 315.365 ;
      END
    PORT
      LAYER M4 ;
      RECT 860.925 0.0 861.265 315.365 ;
      END
    PORT
      LAYER M4 ;
      RECT 863.035 0.0 863.375 315.365 ;
      END
    PORT
      LAYER M4 ;
      RECT 869.325 0.0 869.665 315.365 ;
      END
    PORT
      LAYER M4 ;
      RECT 871.435 0.0 871.775 315.365 ;
      END
    PORT
      LAYER M4 ;
      RECT 876.2 0.0 876.62 315.365 ;
      END
    PORT
      LAYER M4 ;
      RECT 880.86 0.0 881.19 315.365 ;
      END
    PORT
      LAYER M4 ;
      RECT 884.15 0.0 884.57 315.365 ;
      END
    PORT
      LAYER M4 ;
      RECT 888.86 0.0 889.28 315.365 ;
      END
    PORT
      LAYER M4 ;
      RECT 902.285 0.0 902.705 315.365 ;
      END
    PORT
      LAYER M4 ;
      RECT 914.72 0.0 915.14 315.365 ;
      END
    PORT
      LAYER M4 ;
      RECT 919.93 0.0 920.35 315.365 ;
      END
    PORT
      LAYER M4 ;
      RECT 927.32 0.0 927.74 315.365 ;
      END
    PORT
      LAYER M4 ;
      RECT 929.97 0.0 930.39 315.365 ;
      END
    PORT
      LAYER M4 ;
      RECT 933.335 0.0 933.665 315.365 ;
      END
    PORT
      LAYER M4 ;
      RECT 937.905 0.0 938.335 315.365 ;
      END
    PORT
      LAYER M4 ;
      RECT 942.725 0.0 943.065 315.365 ;
      END
    PORT
      LAYER M4 ;
      RECT 944.835 0.0 945.175 315.365 ;
      END
    PORT
      LAYER M4 ;
      RECT 951.125 0.0 951.465 315.365 ;
      END
    PORT
      LAYER M4 ;
      RECT 953.235 0.0 953.575 315.365 ;
      END
    PORT
      LAYER M4 ;
      RECT 959.525 0.0 959.865 315.365 ;
      END
    PORT
      LAYER M4 ;
      RECT 961.635 0.0 961.975 315.365 ;
      END
    PORT
      LAYER M4 ;
      RECT 967.925 0.0 968.265 315.365 ;
      END
    PORT
      LAYER M4 ;
      RECT 970.035 0.0 970.375 315.365 ;
      END
    PORT
      LAYER M4 ;
      RECT 976.325 0.0 976.665 315.365 ;
      END
    PORT
      LAYER M4 ;
      RECT 978.435 0.0 978.775 315.365 ;
      END
    PORT
      LAYER M4 ;
      RECT 984.725 0.0 985.065 315.365 ;
      END
    PORT
      LAYER M4 ;
      RECT 986.835 0.0 987.175 315.365 ;
      END
    PORT
      LAYER M4 ;
      RECT 993.125 0.0 993.465 315.365 ;
      END
    PORT
      LAYER M4 ;
      RECT 995.235 0.0 995.575 315.365 ;
      END
    PORT
      LAYER M4 ;
      RECT 1001.525 0.0 1001.865 315.365 ;
      END
    PORT
      LAYER M4 ;
      RECT 1003.635 0.0 1003.975 315.365 ;
      END
    PORT
      LAYER M4 ;
      RECT 1009.925 0.0 1010.265 315.365 ;
      END
    PORT
      LAYER M4 ;
      RECT 1012.035 0.0 1012.375 315.365 ;
      END
    PORT
      LAYER M4 ;
      RECT 1018.325 0.0 1018.665 315.365 ;
      END
    PORT
      LAYER M4 ;
      RECT 1020.435 0.0 1020.775 315.365 ;
      END
    PORT
      LAYER M4 ;
      RECT 1026.725 0.0 1027.065 315.365 ;
      END
    PORT
      LAYER M4 ;
      RECT 1028.835 0.0 1029.175 315.365 ;
      END
    PORT
      LAYER M4 ;
      RECT 1035.125 0.0 1035.465 315.365 ;
      END
    PORT
      LAYER M4 ;
      RECT 1037.235 0.0 1037.575 315.365 ;
      END
    PORT
      LAYER M4 ;
      RECT 1043.525 0.0 1043.865 315.365 ;
      END
    PORT
      LAYER M4 ;
      RECT 1045.635 0.0 1045.975 315.365 ;
      END
    PORT
      LAYER M4 ;
      RECT 1051.925 0.0 1052.265 315.365 ;
      END
    PORT
      LAYER M4 ;
      RECT 1054.035 0.0 1054.375 315.365 ;
      END
    PORT
      LAYER M4 ;
      RECT 1060.325 0.0 1060.665 315.365 ;
      END
    PORT
      LAYER M4 ;
      RECT 1062.435 0.0 1062.775 315.365 ;
      END
    PORT
      LAYER M4 ;
      RECT 1068.725 0.0 1069.065 315.365 ;
      END
    PORT
      LAYER M4 ;
      RECT 1070.835 0.0 1071.175 315.365 ;
      END
    PORT
      LAYER M4 ;
      RECT 1077.125 0.0 1077.465 315.365 ;
      END
    PORT
      LAYER M4 ;
      RECT 1079.235 0.0 1079.575 315.365 ;
      END
    PORT
      LAYER M4 ;
      RECT 1085.525 0.0 1085.865 315.365 ;
      END
    PORT
      LAYER M4 ;
      RECT 1087.635 0.0 1087.975 315.365 ;
      END
    PORT
      LAYER M4 ;
      RECT 1093.925 0.0 1094.265 315.365 ;
      END
    PORT
      LAYER M4 ;
      RECT 1096.035 0.0 1096.375 315.365 ;
      END
    PORT
      LAYER M4 ;
      RECT 1102.325 0.0 1102.665 315.365 ;
      END
    PORT
      LAYER M4 ;
      RECT 1104.435 0.0 1104.775 315.365 ;
      END
    PORT
      LAYER M4 ;
      RECT 1110.725 0.0 1111.065 315.365 ;
      END
    PORT
      LAYER M4 ;
      RECT 1112.835 0.0 1113.175 315.365 ;
      END
    PORT
      LAYER M4 ;
      RECT 1119.125 0.0 1119.465 315.365 ;
      END
    PORT
      LAYER M4 ;
      RECT 1121.235 0.0 1121.575 315.365 ;
      END
    PORT
      LAYER M4 ;
      RECT 1127.525 0.0 1127.865 315.365 ;
      END
    PORT
      LAYER M4 ;
      RECT 1129.635 0.0 1129.975 315.365 ;
      END
    PORT
      LAYER M4 ;
      RECT 1135.925 0.0 1136.265 315.365 ;
      END
    PORT
      LAYER M4 ;
      RECT 1138.035 0.0 1138.375 315.365 ;
      END
    PORT
      LAYER M4 ;
      RECT 1144.325 0.0 1144.665 315.365 ;
      END
    PORT
      LAYER M4 ;
      RECT 1146.435 0.0 1146.775 315.365 ;
      END
    PORT
      LAYER M4 ;
      RECT 1152.725 0.0 1153.065 315.365 ;
      END
    PORT
      LAYER M4 ;
      RECT 1154.835 0.0 1155.175 315.365 ;
      END
    PORT
      LAYER M4 ;
      RECT 1161.125 0.0 1161.465 315.365 ;
      END
    PORT
      LAYER M4 ;
      RECT 1163.235 0.0 1163.575 315.365 ;
      END
    PORT
      LAYER M4 ;
      RECT 1169.525 0.0 1169.865 315.365 ;
      END
    PORT
      LAYER M4 ;
      RECT 1171.635 0.0 1171.975 315.365 ;
      END
    PORT
      LAYER M4 ;
      RECT 1177.925 0.0 1178.265 315.365 ;
      END
    PORT
      LAYER M4 ;
      RECT 1180.035 0.0 1180.375 315.365 ;
      END
    PORT
      LAYER M4 ;
      RECT 1186.325 0.0 1186.665 315.365 ;
      END
    PORT
      LAYER M4 ;
      RECT 1188.435 0.0 1188.775 315.365 ;
      END
    PORT
      LAYER M4 ;
      RECT 1194.725 0.0 1195.065 315.365 ;
      END
    PORT
      LAYER M4 ;
      RECT 1196.835 0.0 1197.175 315.365 ;
      END
    PORT
      LAYER M4 ;
      RECT 1203.125 0.0 1203.465 315.365 ;
      END
    PORT
      LAYER M4 ;
      RECT 1205.235 0.0 1205.575 315.365 ;
      END
    PORT
      LAYER M4 ;
      RECT 1208.985 0.0 1209.135 315.365 ;
      END
    END VDDCE
  PIN VDDPE
    DIRECTION INOUT ;
    USE POWER ;
    PORT
      LAYER M4 ;
      RECT 0.09 0.0 0.24 315.365 ;
      END
    PORT
      LAYER M4 ;
      RECT 2.45 0.0 2.79 315.365 ;
      END
    PORT
      LAYER M4 ;
      RECT 8.17 0.0 8.51 315.365 ;
      END
    PORT
      LAYER M4 ;
      RECT 10.85 0.0 11.19 315.365 ;
      END
    PORT
      LAYER M4 ;
      RECT 16.57 0.0 16.91 315.365 ;
      END
    PORT
      LAYER M4 ;
      RECT 19.25 0.0 19.59 315.365 ;
      END
    PORT
      LAYER M4 ;
      RECT 24.97 0.0 25.31 315.365 ;
      END
    PORT
      LAYER M4 ;
      RECT 27.65 0.0 27.99 315.365 ;
      END
    PORT
      LAYER M4 ;
      RECT 33.37 0.0 33.71 315.365 ;
      END
    PORT
      LAYER M4 ;
      RECT 36.05 0.0 36.39 315.365 ;
      END
    PORT
      LAYER M4 ;
      RECT 41.77 0.0 42.11 315.365 ;
      END
    PORT
      LAYER M4 ;
      RECT 44.45 0.0 44.79 315.365 ;
      END
    PORT
      LAYER M4 ;
      RECT 50.17 0.0 50.51 315.365 ;
      END
    PORT
      LAYER M4 ;
      RECT 52.85 0.0 53.19 315.365 ;
      END
    PORT
      LAYER M4 ;
      RECT 58.57 0.0 58.91 315.365 ;
      END
    PORT
      LAYER M4 ;
      RECT 61.25 0.0 61.59 315.365 ;
      END
    PORT
      LAYER M4 ;
      RECT 66.97 0.0 67.31 315.365 ;
      END
    PORT
      LAYER M4 ;
      RECT 69.65 0.0 69.99 315.365 ;
      END
    PORT
      LAYER M4 ;
      RECT 75.37 0.0 75.71 315.365 ;
      END
    PORT
      LAYER M4 ;
      RECT 78.05 0.0 78.39 315.365 ;
      END
    PORT
      LAYER M4 ;
      RECT 83.77 0.0 84.11 315.365 ;
      END
    PORT
      LAYER M4 ;
      RECT 86.45 0.0 86.79 315.365 ;
      END
    PORT
      LAYER M4 ;
      RECT 92.17 0.0 92.51 315.365 ;
      END
    PORT
      LAYER M4 ;
      RECT 94.85 0.0 95.19 315.365 ;
      END
    PORT
      LAYER M4 ;
      RECT 100.57 0.0 100.91 315.365 ;
      END
    PORT
      LAYER M4 ;
      RECT 103.25 0.0 103.59 315.365 ;
      END
    PORT
      LAYER M4 ;
      RECT 108.97 0.0 109.31 315.365 ;
      END
    PORT
      LAYER M4 ;
      RECT 111.65 0.0 111.99 315.365 ;
      END
    PORT
      LAYER M4 ;
      RECT 117.37 0.0 117.71 315.365 ;
      END
    PORT
      LAYER M4 ;
      RECT 120.05 0.0 120.39 315.365 ;
      END
    PORT
      LAYER M4 ;
      RECT 125.77 0.0 126.11 315.365 ;
      END
    PORT
      LAYER M4 ;
      RECT 128.45 0.0 128.79 315.365 ;
      END
    PORT
      LAYER M4 ;
      RECT 134.17 0.0 134.51 315.365 ;
      END
    PORT
      LAYER M4 ;
      RECT 136.85 0.0 137.19 315.365 ;
      END
    PORT
      LAYER M4 ;
      RECT 142.57 0.0 142.91 315.365 ;
      END
    PORT
      LAYER M4 ;
      RECT 145.25 0.0 145.59 315.365 ;
      END
    PORT
      LAYER M4 ;
      RECT 150.97 0.0 151.31 315.365 ;
      END
    PORT
      LAYER M4 ;
      RECT 153.65 0.0 153.99 315.365 ;
      END
    PORT
      LAYER M4 ;
      RECT 159.37 0.0 159.71 315.365 ;
      END
    PORT
      LAYER M4 ;
      RECT 162.05 0.0 162.39 315.365 ;
      END
    PORT
      LAYER M4 ;
      RECT 167.77 0.0 168.11 315.365 ;
      END
    PORT
      LAYER M4 ;
      RECT 170.45 0.0 170.79 315.365 ;
      END
    PORT
      LAYER M4 ;
      RECT 176.17 0.0 176.51 315.365 ;
      END
    PORT
      LAYER M4 ;
      RECT 178.85 0.0 179.19 315.365 ;
      END
    PORT
      LAYER M4 ;
      RECT 184.57 0.0 184.91 315.365 ;
      END
    PORT
      LAYER M4 ;
      RECT 187.25 0.0 187.59 315.365 ;
      END
    PORT
      LAYER M4 ;
      RECT 192.97 0.0 193.31 315.365 ;
      END
    PORT
      LAYER M4 ;
      RECT 195.65 0.0 195.99 315.365 ;
      END
    PORT
      LAYER M4 ;
      RECT 201.37 0.0 201.71 315.365 ;
      END
    PORT
      LAYER M4 ;
      RECT 204.05 0.0 204.39 315.365 ;
      END
    PORT
      LAYER M4 ;
      RECT 209.77 0.0 210.11 315.365 ;
      END
    PORT
      LAYER M4 ;
      RECT 212.45 0.0 212.79 315.365 ;
      END
    PORT
      LAYER M4 ;
      RECT 218.17 0.0 218.51 315.365 ;
      END
    PORT
      LAYER M4 ;
      RECT 220.85 0.0 221.19 315.365 ;
      END
    PORT
      LAYER M4 ;
      RECT 226.57 0.0 226.91 315.365 ;
      END
    PORT
      LAYER M4 ;
      RECT 229.25 0.0 229.59 315.365 ;
      END
    PORT
      LAYER M4 ;
      RECT 234.97 0.0 235.31 315.365 ;
      END
    PORT
      LAYER M4 ;
      RECT 237.65 0.0 237.99 315.365 ;
      END
    PORT
      LAYER M4 ;
      RECT 243.37 0.0 243.71 315.365 ;
      END
    PORT
      LAYER M4 ;
      RECT 246.05 0.0 246.39 315.365 ;
      END
    PORT
      LAYER M4 ;
      RECT 251.77 0.0 252.11 315.365 ;
      END
    PORT
      LAYER M4 ;
      RECT 254.45 0.0 254.79 315.365 ;
      END
    PORT
      LAYER M4 ;
      RECT 260.17 0.0 260.51 315.365 ;
      END
    PORT
      LAYER M4 ;
      RECT 262.85 0.0 263.19 315.365 ;
      END
    PORT
      LAYER M4 ;
      RECT 268.57 0.0 268.91 315.365 ;
      END
    PORT
      LAYER M4 ;
      RECT 274.15 0.0 274.57 315.365 ;
      END
    PORT
      LAYER M4 ;
      RECT 276.795 0.0 277.215 315.365 ;
      END
    PORT
      LAYER M4 ;
      RECT 284.36 0.0 284.69 315.365 ;
      END
    PORT
      LAYER M4 ;
      RECT 297.29 0.0 297.71 315.365 ;
      END
    PORT
      LAYER M4 ;
      RECT 298.665 0.0 299.095 315.365 ;
      END
    PORT
      LAYER M4 ;
      RECT 299.78 0.0 300.2 315.365 ;
      END
    PORT
      LAYER M4 ;
      RECT 312.6 0.0 313.02 315.365 ;
      END
    PORT
      LAYER M4 ;
      RECT 313.92 0.0 314.34 315.365 ;
      END
    PORT
      LAYER M4 ;
      RECT 315.245 0.0 315.665 315.365 ;
      END
    PORT
      LAYER M4 ;
      RECT 322.9 0.0 323.32 315.365 ;
      END
    PORT
      LAYER M4 ;
      RECT 323.945 0.0 324.365 315.365 ;
      END
    PORT
      LAYER M4 ;
      RECT 327.91 0.0 328.33 315.365 ;
      END
    PORT
      LAYER M4 ;
      RECT 330.565 0.0 330.985 315.365 ;
      END
    PORT
      LAYER M4 ;
      RECT 336.25 0.0 336.59 315.365 ;
      END
    PORT
      LAYER M4 ;
      RECT 341.97 0.0 342.31 315.365 ;
      END
    PORT
      LAYER M4 ;
      RECT 344.65 0.0 344.99 315.365 ;
      END
    PORT
      LAYER M4 ;
      RECT 350.37 0.0 350.71 315.365 ;
      END
    PORT
      LAYER M4 ;
      RECT 353.05 0.0 353.39 315.365 ;
      END
    PORT
      LAYER M4 ;
      RECT 358.77 0.0 359.11 315.365 ;
      END
    PORT
      LAYER M4 ;
      RECT 361.45 0.0 361.79 315.365 ;
      END
    PORT
      LAYER M4 ;
      RECT 367.17 0.0 367.51 315.365 ;
      END
    PORT
      LAYER M4 ;
      RECT 369.85 0.0 370.19 315.365 ;
      END
    PORT
      LAYER M4 ;
      RECT 375.57 0.0 375.91 315.365 ;
      END
    PORT
      LAYER M4 ;
      RECT 378.25 0.0 378.59 315.365 ;
      END
    PORT
      LAYER M4 ;
      RECT 383.97 0.0 384.31 315.365 ;
      END
    PORT
      LAYER M4 ;
      RECT 386.65 0.0 386.99 315.365 ;
      END
    PORT
      LAYER M4 ;
      RECT 392.37 0.0 392.71 315.365 ;
      END
    PORT
      LAYER M4 ;
      RECT 395.05 0.0 395.39 315.365 ;
      END
    PORT
      LAYER M4 ;
      RECT 400.77 0.0 401.11 315.365 ;
      END
    PORT
      LAYER M4 ;
      RECT 403.45 0.0 403.79 315.365 ;
      END
    PORT
      LAYER M4 ;
      RECT 409.17 0.0 409.51 315.365 ;
      END
    PORT
      LAYER M4 ;
      RECT 411.85 0.0 412.19 315.365 ;
      END
    PORT
      LAYER M4 ;
      RECT 417.57 0.0 417.91 315.365 ;
      END
    PORT
      LAYER M4 ;
      RECT 420.25 0.0 420.59 315.365 ;
      END
    PORT
      LAYER M4 ;
      RECT 425.97 0.0 426.31 315.365 ;
      END
    PORT
      LAYER M4 ;
      RECT 428.65 0.0 428.99 315.365 ;
      END
    PORT
      LAYER M4 ;
      RECT 434.37 0.0 434.71 315.365 ;
      END
    PORT
      LAYER M4 ;
      RECT 437.05 0.0 437.39 315.365 ;
      END
    PORT
      LAYER M4 ;
      RECT 442.77 0.0 443.11 315.365 ;
      END
    PORT
      LAYER M4 ;
      RECT 445.45 0.0 445.79 315.365 ;
      END
    PORT
      LAYER M4 ;
      RECT 451.17 0.0 451.51 315.365 ;
      END
    PORT
      LAYER M4 ;
      RECT 453.85 0.0 454.19 315.365 ;
      END
    PORT
      LAYER M4 ;
      RECT 459.57 0.0 459.91 315.365 ;
      END
    PORT
      LAYER M4 ;
      RECT 462.25 0.0 462.59 315.365 ;
      END
    PORT
      LAYER M4 ;
      RECT 467.97 0.0 468.31 315.365 ;
      END
    PORT
      LAYER M4 ;
      RECT 470.65 0.0 470.99 315.365 ;
      END
    PORT
      LAYER M4 ;
      RECT 476.37 0.0 476.71 315.365 ;
      END
    PORT
      LAYER M4 ;
      RECT 479.05 0.0 479.39 315.365 ;
      END
    PORT
      LAYER M4 ;
      RECT 484.77 0.0 485.11 315.365 ;
      END
    PORT
      LAYER M4 ;
      RECT 487.45 0.0 487.79 315.365 ;
      END
    PORT
      LAYER M4 ;
      RECT 493.17 0.0 493.51 315.365 ;
      END
    PORT
      LAYER M4 ;
      RECT 495.85 0.0 496.19 315.365 ;
      END
    PORT
      LAYER M4 ;
      RECT 501.57 0.0 501.91 315.365 ;
      END
    PORT
      LAYER M4 ;
      RECT 504.25 0.0 504.59 315.365 ;
      END
    PORT
      LAYER M4 ;
      RECT 509.97 0.0 510.31 315.365 ;
      END
    PORT
      LAYER M4 ;
      RECT 512.65 0.0 512.99 315.365 ;
      END
    PORT
      LAYER M4 ;
      RECT 518.37 0.0 518.71 315.365 ;
      END
    PORT
      LAYER M4 ;
      RECT 521.05 0.0 521.39 315.365 ;
      END
    PORT
      LAYER M4 ;
      RECT 526.77 0.0 527.11 315.365 ;
      END
    PORT
      LAYER M4 ;
      RECT 529.45 0.0 529.79 315.365 ;
      END
    PORT
      LAYER M4 ;
      RECT 535.17 0.0 535.51 315.365 ;
      END
    PORT
      LAYER M4 ;
      RECT 537.85 0.0 538.19 315.365 ;
      END
    PORT
      LAYER M4 ;
      RECT 543.57 0.0 543.91 315.365 ;
      END
    PORT
      LAYER M4 ;
      RECT 546.25 0.0 546.59 315.365 ;
      END
    PORT
      LAYER M4 ;
      RECT 551.97 0.0 552.31 315.365 ;
      END
    PORT
      LAYER M4 ;
      RECT 554.65 0.0 554.99 315.365 ;
      END
    PORT
      LAYER M4 ;
      RECT 560.37 0.0 560.71 315.365 ;
      END
    PORT
      LAYER M4 ;
      RECT 563.05 0.0 563.39 315.365 ;
      END
    PORT
      LAYER M4 ;
      RECT 568.77 0.0 569.11 315.365 ;
      END
    PORT
      LAYER M4 ;
      RECT 571.45 0.0 571.79 315.365 ;
      END
    PORT
      LAYER M4 ;
      RECT 577.17 0.0 577.51 315.365 ;
      END
    PORT
      LAYER M4 ;
      RECT 579.85 0.0 580.19 315.365 ;
      END
    PORT
      LAYER M4 ;
      RECT 585.57 0.0 585.91 315.365 ;
      END
    PORT
      LAYER M4 ;
      RECT 588.25 0.0 588.59 315.365 ;
      END
    PORT
      LAYER M4 ;
      RECT 593.97 0.0 594.31 315.365 ;
      END
    PORT
      LAYER M4 ;
      RECT 596.65 0.0 596.99 315.365 ;
      END
    PORT
      LAYER M4 ;
      RECT 602.37 0.0 602.71 315.365 ;
      END
    PORT
      LAYER M4 ;
      RECT 603.98 0.0 604.13 315.365 ;
      END
    PORT
      LAYER M4 ;
      RECT 605.7 0.0 605.85 315.365 ;
      END
    PORT
      LAYER M4 ;
      RECT 607.12 0.0 607.46 315.365 ;
      END
    PORT
      LAYER M4 ;
      RECT 612.84 0.0 613.18 315.365 ;
      END
    PORT
      LAYER M4 ;
      RECT 615.52 0.0 615.86 315.365 ;
      END
    PORT
      LAYER M4 ;
      RECT 621.24 0.0 621.58 315.365 ;
      END
    PORT
      LAYER M4 ;
      RECT 623.92 0.0 624.26 315.365 ;
      END
    PORT
      LAYER M4 ;
      RECT 629.64 0.0 629.98 315.365 ;
      END
    PORT
      LAYER M4 ;
      RECT 632.32 0.0 632.66 315.365 ;
      END
    PORT
      LAYER M4 ;
      RECT 638.04 0.0 638.38 315.365 ;
      END
    PORT
      LAYER M4 ;
      RECT 640.72 0.0 641.06 315.365 ;
      END
    PORT
      LAYER M4 ;
      RECT 646.44 0.0 646.78 315.365 ;
      END
    PORT
      LAYER M4 ;
      RECT 649.12 0.0 649.46 315.365 ;
      END
    PORT
      LAYER M4 ;
      RECT 654.84 0.0 655.18 315.365 ;
      END
    PORT
      LAYER M4 ;
      RECT 657.52 0.0 657.86 315.365 ;
      END
    PORT
      LAYER M4 ;
      RECT 663.24 0.0 663.58 315.365 ;
      END
    PORT
      LAYER M4 ;
      RECT 665.92 0.0 666.26 315.365 ;
      END
    PORT
      LAYER M4 ;
      RECT 671.64 0.0 671.98 315.365 ;
      END
    PORT
      LAYER M4 ;
      RECT 674.32 0.0 674.66 315.365 ;
      END
    PORT
      LAYER M4 ;
      RECT 680.04 0.0 680.38 315.365 ;
      END
    PORT
      LAYER M4 ;
      RECT 682.72 0.0 683.06 315.365 ;
      END
    PORT
      LAYER M4 ;
      RECT 688.44 0.0 688.78 315.365 ;
      END
    PORT
      LAYER M4 ;
      RECT 691.12 0.0 691.46 315.365 ;
      END
    PORT
      LAYER M4 ;
      RECT 696.84 0.0 697.18 315.365 ;
      END
    PORT
      LAYER M4 ;
      RECT 699.52 0.0 699.86 315.365 ;
      END
    PORT
      LAYER M4 ;
      RECT 705.24 0.0 705.58 315.365 ;
      END
    PORT
      LAYER M4 ;
      RECT 707.92 0.0 708.26 315.365 ;
      END
    PORT
      LAYER M4 ;
      RECT 713.64 0.0 713.98 315.365 ;
      END
    PORT
      LAYER M4 ;
      RECT 716.32 0.0 716.66 315.365 ;
      END
    PORT
      LAYER M4 ;
      RECT 722.04 0.0 722.38 315.365 ;
      END
    PORT
      LAYER M4 ;
      RECT 724.72 0.0 725.06 315.365 ;
      END
    PORT
      LAYER M4 ;
      RECT 730.44 0.0 730.78 315.365 ;
      END
    PORT
      LAYER M4 ;
      RECT 733.12 0.0 733.46 315.365 ;
      END
    PORT
      LAYER M4 ;
      RECT 738.84 0.0 739.18 315.365 ;
      END
    PORT
      LAYER M4 ;
      RECT 741.52 0.0 741.86 315.365 ;
      END
    PORT
      LAYER M4 ;
      RECT 747.24 0.0 747.58 315.365 ;
      END
    PORT
      LAYER M4 ;
      RECT 749.92 0.0 750.26 315.365 ;
      END
    PORT
      LAYER M4 ;
      RECT 755.64 0.0 755.98 315.365 ;
      END
    PORT
      LAYER M4 ;
      RECT 758.32 0.0 758.66 315.365 ;
      END
    PORT
      LAYER M4 ;
      RECT 764.04 0.0 764.38 315.365 ;
      END
    PORT
      LAYER M4 ;
      RECT 766.72 0.0 767.06 315.365 ;
      END
    PORT
      LAYER M4 ;
      RECT 772.44 0.0 772.78 315.365 ;
      END
    PORT
      LAYER M4 ;
      RECT 775.12 0.0 775.46 315.365 ;
      END
    PORT
      LAYER M4 ;
      RECT 780.84 0.0 781.18 315.365 ;
      END
    PORT
      LAYER M4 ;
      RECT 783.52 0.0 783.86 315.365 ;
      END
    PORT
      LAYER M4 ;
      RECT 789.24 0.0 789.58 315.365 ;
      END
    PORT
      LAYER M4 ;
      RECT 791.92 0.0 792.26 315.365 ;
      END
    PORT
      LAYER M4 ;
      RECT 797.64 0.0 797.98 315.365 ;
      END
    PORT
      LAYER M4 ;
      RECT 800.32 0.0 800.66 315.365 ;
      END
    PORT
      LAYER M4 ;
      RECT 806.04 0.0 806.38 315.365 ;
      END
    PORT
      LAYER M4 ;
      RECT 808.72 0.0 809.06 315.365 ;
      END
    PORT
      LAYER M4 ;
      RECT 814.44 0.0 814.78 315.365 ;
      END
    PORT
      LAYER M4 ;
      RECT 817.12 0.0 817.46 315.365 ;
      END
    PORT
      LAYER M4 ;
      RECT 822.84 0.0 823.18 315.365 ;
      END
    PORT
      LAYER M4 ;
      RECT 825.52 0.0 825.86 315.365 ;
      END
    PORT
      LAYER M4 ;
      RECT 831.24 0.0 831.58 315.365 ;
      END
    PORT
      LAYER M4 ;
      RECT 833.92 0.0 834.26 315.365 ;
      END
    PORT
      LAYER M4 ;
      RECT 839.64 0.0 839.98 315.365 ;
      END
    PORT
      LAYER M4 ;
      RECT 842.32 0.0 842.66 315.365 ;
      END
    PORT
      LAYER M4 ;
      RECT 848.04 0.0 848.38 315.365 ;
      END
    PORT
      LAYER M4 ;
      RECT 850.72 0.0 851.06 315.365 ;
      END
    PORT
      LAYER M4 ;
      RECT 856.44 0.0 856.78 315.365 ;
      END
    PORT
      LAYER M4 ;
      RECT 859.12 0.0 859.46 315.365 ;
      END
    PORT
      LAYER M4 ;
      RECT 864.84 0.0 865.18 315.365 ;
      END
    PORT
      LAYER M4 ;
      RECT 867.52 0.0 867.86 315.365 ;
      END
    PORT
      LAYER M4 ;
      RECT 873.24 0.0 873.58 315.365 ;
      END
    PORT
      LAYER M4 ;
      RECT 878.845 0.0 879.265 315.365 ;
      END
    PORT
      LAYER M4 ;
      RECT 881.5 0.0 881.92 315.365 ;
      END
    PORT
      LAYER M4 ;
      RECT 885.465 0.0 885.885 315.365 ;
      END
    PORT
      LAYER M4 ;
      RECT 886.51 0.0 886.93 315.365 ;
      END
    PORT
      LAYER M4 ;
      RECT 894.165 0.0 894.585 315.365 ;
      END
    PORT
      LAYER M4 ;
      RECT 895.49 0.0 895.91 315.365 ;
      END
    PORT
      LAYER M4 ;
      RECT 896.81 0.0 897.23 315.365 ;
      END
    PORT
      LAYER M4 ;
      RECT 909.63 0.0 910.05 315.365 ;
      END
    PORT
      LAYER M4 ;
      RECT 910.735 0.0 911.165 315.365 ;
      END
    PORT
      LAYER M4 ;
      RECT 912.12 0.0 912.54 315.365 ;
      END
    PORT
      LAYER M4 ;
      RECT 925.14 0.0 925.47 315.365 ;
      END
    PORT
      LAYER M4 ;
      RECT 932.615 0.0 933.035 315.365 ;
      END
    PORT
      LAYER M4 ;
      RECT 935.26 0.0 935.68 315.365 ;
      END
    PORT
      LAYER M4 ;
      RECT 940.92 0.0 941.26 315.365 ;
      END
    PORT
      LAYER M4 ;
      RECT 946.64 0.0 946.98 315.365 ;
      END
    PORT
      LAYER M4 ;
      RECT 949.32 0.0 949.66 315.365 ;
      END
    PORT
      LAYER M4 ;
      RECT 955.04 0.0 955.38 315.365 ;
      END
    PORT
      LAYER M4 ;
      RECT 957.72 0.0 958.06 315.365 ;
      END
    PORT
      LAYER M4 ;
      RECT 963.44 0.0 963.78 315.365 ;
      END
    PORT
      LAYER M4 ;
      RECT 966.12 0.0 966.46 315.365 ;
      END
    PORT
      LAYER M4 ;
      RECT 971.84 0.0 972.18 315.365 ;
      END
    PORT
      LAYER M4 ;
      RECT 974.52 0.0 974.86 315.365 ;
      END
    PORT
      LAYER M4 ;
      RECT 980.24 0.0 980.58 315.365 ;
      END
    PORT
      LAYER M4 ;
      RECT 982.92 0.0 983.26 315.365 ;
      END
    PORT
      LAYER M4 ;
      RECT 988.64 0.0 988.98 315.365 ;
      END
    PORT
      LAYER M4 ;
      RECT 991.32 0.0 991.66 315.365 ;
      END
    PORT
      LAYER M4 ;
      RECT 997.04 0.0 997.38 315.365 ;
      END
    PORT
      LAYER M4 ;
      RECT 999.72 0.0 1000.06 315.365 ;
      END
    PORT
      LAYER M4 ;
      RECT 1005.44 0.0 1005.78 315.365 ;
      END
    PORT
      LAYER M4 ;
      RECT 1008.12 0.0 1008.46 315.365 ;
      END
    PORT
      LAYER M4 ;
      RECT 1013.84 0.0 1014.18 315.365 ;
      END
    PORT
      LAYER M4 ;
      RECT 1016.52 0.0 1016.86 315.365 ;
      END
    PORT
      LAYER M4 ;
      RECT 1022.24 0.0 1022.58 315.365 ;
      END
    PORT
      LAYER M4 ;
      RECT 1024.92 0.0 1025.26 315.365 ;
      END
    PORT
      LAYER M4 ;
      RECT 1030.64 0.0 1030.98 315.365 ;
      END
    PORT
      LAYER M4 ;
      RECT 1033.32 0.0 1033.66 315.365 ;
      END
    PORT
      LAYER M4 ;
      RECT 1039.04 0.0 1039.38 315.365 ;
      END
    PORT
      LAYER M4 ;
      RECT 1041.72 0.0 1042.06 315.365 ;
      END
    PORT
      LAYER M4 ;
      RECT 1047.44 0.0 1047.78 315.365 ;
      END
    PORT
      LAYER M4 ;
      RECT 1050.12 0.0 1050.46 315.365 ;
      END
    PORT
      LAYER M4 ;
      RECT 1055.84 0.0 1056.18 315.365 ;
      END
    PORT
      LAYER M4 ;
      RECT 1058.52 0.0 1058.86 315.365 ;
      END
    PORT
      LAYER M4 ;
      RECT 1064.24 0.0 1064.58 315.365 ;
      END
    PORT
      LAYER M4 ;
      RECT 1066.92 0.0 1067.26 315.365 ;
      END
    PORT
      LAYER M4 ;
      RECT 1072.64 0.0 1072.98 315.365 ;
      END
    PORT
      LAYER M4 ;
      RECT 1075.32 0.0 1075.66 315.365 ;
      END
    PORT
      LAYER M4 ;
      RECT 1081.04 0.0 1081.38 315.365 ;
      END
    PORT
      LAYER M4 ;
      RECT 1083.72 0.0 1084.06 315.365 ;
      END
    PORT
      LAYER M4 ;
      RECT 1089.44 0.0 1089.78 315.365 ;
      END
    PORT
      LAYER M4 ;
      RECT 1092.12 0.0 1092.46 315.365 ;
      END
    PORT
      LAYER M4 ;
      RECT 1097.84 0.0 1098.18 315.365 ;
      END
    PORT
      LAYER M4 ;
      RECT 1100.52 0.0 1100.86 315.365 ;
      END
    PORT
      LAYER M4 ;
      RECT 1106.24 0.0 1106.58 315.365 ;
      END
    PORT
      LAYER M4 ;
      RECT 1108.92 0.0 1109.26 315.365 ;
      END
    PORT
      LAYER M4 ;
      RECT 1114.64 0.0 1114.98 315.365 ;
      END
    PORT
      LAYER M4 ;
      RECT 1117.32 0.0 1117.66 315.365 ;
      END
    PORT
      LAYER M4 ;
      RECT 1123.04 0.0 1123.38 315.365 ;
      END
    PORT
      LAYER M4 ;
      RECT 1125.72 0.0 1126.06 315.365 ;
      END
    PORT
      LAYER M4 ;
      RECT 1131.44 0.0 1131.78 315.365 ;
      END
    PORT
      LAYER M4 ;
      RECT 1134.12 0.0 1134.46 315.365 ;
      END
    PORT
      LAYER M4 ;
      RECT 1139.84 0.0 1140.18 315.365 ;
      END
    PORT
      LAYER M4 ;
      RECT 1142.52 0.0 1142.86 315.365 ;
      END
    PORT
      LAYER M4 ;
      RECT 1148.24 0.0 1148.58 315.365 ;
      END
    PORT
      LAYER M4 ;
      RECT 1150.92 0.0 1151.26 315.365 ;
      END
    PORT
      LAYER M4 ;
      RECT 1156.64 0.0 1156.98 315.365 ;
      END
    PORT
      LAYER M4 ;
      RECT 1159.32 0.0 1159.66 315.365 ;
      END
    PORT
      LAYER M4 ;
      RECT 1165.04 0.0 1165.38 315.365 ;
      END
    PORT
      LAYER M4 ;
      RECT 1167.72 0.0 1168.06 315.365 ;
      END
    PORT
      LAYER M4 ;
      RECT 1173.44 0.0 1173.78 315.365 ;
      END
    PORT
      LAYER M4 ;
      RECT 1176.12 0.0 1176.46 315.365 ;
      END
    PORT
      LAYER M4 ;
      RECT 1181.84 0.0 1182.18 315.365 ;
      END
    PORT
      LAYER M4 ;
      RECT 1184.52 0.0 1184.86 315.365 ;
      END
    PORT
      LAYER M4 ;
      RECT 1190.24 0.0 1190.58 315.365 ;
      END
    PORT
      LAYER M4 ;
      RECT 1192.92 0.0 1193.26 315.365 ;
      END
    PORT
      LAYER M4 ;
      RECT 1198.64 0.0 1198.98 315.365 ;
      END
    PORT
      LAYER M4 ;
      RECT 1201.32 0.0 1201.66 315.365 ;
      END
    PORT
      LAYER M4 ;
      RECT 1207.04 0.0 1207.38 315.365 ;
      END
    PORT
      LAYER M4 ;
      RECT 1209.59 0.0 1209.74 315.365 ;
      END
    END VDDPE
  PIN VSSE
    DIRECTION INOUT ;
    USE GROUND ;
    PORT
      LAYER M4 ;
      RECT 0.38 0.0 0.53 315.365 ;
      END
    PORT
      LAYER M4 ;
      RECT 1.0 0.0 1.15 315.365 ;
      END
    PORT
      LAYER M4 ;
      RECT 1.675 0.0 2.015 315.365 ;
      END
    PORT
      LAYER M4 ;
      RECT 3.2 0.0 3.54 315.365 ;
      END
    PORT
      LAYER M4 ;
      RECT 7.415 0.0 7.755 315.365 ;
      END
    PORT
      LAYER M4 ;
      RECT 8.92 0.0 9.26 315.365 ;
      END
    PORT
      LAYER M4 ;
      RECT 10.075 0.0 10.415 315.365 ;
      END
    PORT
      LAYER M4 ;
      RECT 11.6 0.0 11.94 315.365 ;
      END
    PORT
      LAYER M4 ;
      RECT 15.815 0.0 16.155 315.365 ;
      END
    PORT
      LAYER M4 ;
      RECT 17.32 0.0 17.66 315.365 ;
      END
    PORT
      LAYER M4 ;
      RECT 18.475 0.0 18.815 315.365 ;
      END
    PORT
      LAYER M4 ;
      RECT 20.0 0.0 20.34 315.365 ;
      END
    PORT
      LAYER M4 ;
      RECT 24.215 0.0 24.555 315.365 ;
      END
    PORT
      LAYER M4 ;
      RECT 25.72 0.0 26.06 315.365 ;
      END
    PORT
      LAYER M4 ;
      RECT 26.875 0.0 27.215 315.365 ;
      END
    PORT
      LAYER M4 ;
      RECT 28.4 0.0 28.74 315.365 ;
      END
    PORT
      LAYER M4 ;
      RECT 32.615 0.0 32.955 315.365 ;
      END
    PORT
      LAYER M4 ;
      RECT 34.12 0.0 34.46 315.365 ;
      END
    PORT
      LAYER M4 ;
      RECT 35.275 0.0 35.615 315.365 ;
      END
    PORT
      LAYER M4 ;
      RECT 36.8 0.0 37.14 315.365 ;
      END
    PORT
      LAYER M4 ;
      RECT 41.015 0.0 41.355 315.365 ;
      END
    PORT
      LAYER M4 ;
      RECT 42.52 0.0 42.86 315.365 ;
      END
    PORT
      LAYER M4 ;
      RECT 43.675 0.0 44.015 315.365 ;
      END
    PORT
      LAYER M4 ;
      RECT 45.2 0.0 45.54 315.365 ;
      END
    PORT
      LAYER M4 ;
      RECT 49.415 0.0 49.755 315.365 ;
      END
    PORT
      LAYER M4 ;
      RECT 50.92 0.0 51.26 315.365 ;
      END
    PORT
      LAYER M4 ;
      RECT 52.075 0.0 52.415 315.365 ;
      END
    PORT
      LAYER M4 ;
      RECT 53.6 0.0 53.94 315.365 ;
      END
    PORT
      LAYER M4 ;
      RECT 57.815 0.0 58.155 315.365 ;
      END
    PORT
      LAYER M4 ;
      RECT 59.32 0.0 59.66 315.365 ;
      END
    PORT
      LAYER M4 ;
      RECT 60.475 0.0 60.815 315.365 ;
      END
    PORT
      LAYER M4 ;
      RECT 62.0 0.0 62.34 315.365 ;
      END
    PORT
      LAYER M4 ;
      RECT 66.215 0.0 66.555 315.365 ;
      END
    PORT
      LAYER M4 ;
      RECT 67.72 0.0 68.06 315.365 ;
      END
    PORT
      LAYER M4 ;
      RECT 68.875 0.0 69.215 315.365 ;
      END
    PORT
      LAYER M4 ;
      RECT 70.4 0.0 70.74 315.365 ;
      END
    PORT
      LAYER M4 ;
      RECT 74.615 0.0 74.955 315.365 ;
      END
    PORT
      LAYER M4 ;
      RECT 76.12 0.0 76.46 315.365 ;
      END
    PORT
      LAYER M4 ;
      RECT 77.275 0.0 77.615 315.365 ;
      END
    PORT
      LAYER M4 ;
      RECT 78.8 0.0 79.14 315.365 ;
      END
    PORT
      LAYER M4 ;
      RECT 83.015 0.0 83.355 315.365 ;
      END
    PORT
      LAYER M4 ;
      RECT 84.52 0.0 84.86 315.365 ;
      END
    PORT
      LAYER M4 ;
      RECT 85.675 0.0 86.015 315.365 ;
      END
    PORT
      LAYER M4 ;
      RECT 87.2 0.0 87.54 315.365 ;
      END
    PORT
      LAYER M4 ;
      RECT 91.415 0.0 91.755 315.365 ;
      END
    PORT
      LAYER M4 ;
      RECT 92.92 0.0 93.26 315.365 ;
      END
    PORT
      LAYER M4 ;
      RECT 94.075 0.0 94.415 315.365 ;
      END
    PORT
      LAYER M4 ;
      RECT 95.6 0.0 95.94 315.365 ;
      END
    PORT
      LAYER M4 ;
      RECT 99.815 0.0 100.155 315.365 ;
      END
    PORT
      LAYER M4 ;
      RECT 101.32 0.0 101.66 315.365 ;
      END
    PORT
      LAYER M4 ;
      RECT 102.475 0.0 102.815 315.365 ;
      END
    PORT
      LAYER M4 ;
      RECT 104.0 0.0 104.34 315.365 ;
      END
    PORT
      LAYER M4 ;
      RECT 108.215 0.0 108.555 315.365 ;
      END
    PORT
      LAYER M4 ;
      RECT 109.72 0.0 110.06 315.365 ;
      END
    PORT
      LAYER M4 ;
      RECT 110.875 0.0 111.215 315.365 ;
      END
    PORT
      LAYER M4 ;
      RECT 112.4 0.0 112.74 315.365 ;
      END
    PORT
      LAYER M4 ;
      RECT 116.615 0.0 116.955 315.365 ;
      END
    PORT
      LAYER M4 ;
      RECT 118.12 0.0 118.46 315.365 ;
      END
    PORT
      LAYER M4 ;
      RECT 119.275 0.0 119.615 315.365 ;
      END
    PORT
      LAYER M4 ;
      RECT 120.8 0.0 121.14 315.365 ;
      END
    PORT
      LAYER M4 ;
      RECT 125.015 0.0 125.355 315.365 ;
      END
    PORT
      LAYER M4 ;
      RECT 126.52 0.0 126.86 315.365 ;
      END
    PORT
      LAYER M4 ;
      RECT 127.675 0.0 128.015 315.365 ;
      END
    PORT
      LAYER M4 ;
      RECT 129.2 0.0 129.54 315.365 ;
      END
    PORT
      LAYER M4 ;
      RECT 133.415 0.0 133.755 315.365 ;
      END
    PORT
      LAYER M4 ;
      RECT 134.92 0.0 135.26 315.365 ;
      END
    PORT
      LAYER M4 ;
      RECT 136.075 0.0 136.415 315.365 ;
      END
    PORT
      LAYER M4 ;
      RECT 137.6 0.0 137.94 315.365 ;
      END
    PORT
      LAYER M4 ;
      RECT 141.815 0.0 142.155 315.365 ;
      END
    PORT
      LAYER M4 ;
      RECT 143.32 0.0 143.66 315.365 ;
      END
    PORT
      LAYER M4 ;
      RECT 144.475 0.0 144.815 315.365 ;
      END
    PORT
      LAYER M4 ;
      RECT 146.0 0.0 146.34 315.365 ;
      END
    PORT
      LAYER M4 ;
      RECT 150.215 0.0 150.555 315.365 ;
      END
    PORT
      LAYER M4 ;
      RECT 151.72 0.0 152.06 315.365 ;
      END
    PORT
      LAYER M4 ;
      RECT 152.875 0.0 153.215 315.365 ;
      END
    PORT
      LAYER M4 ;
      RECT 154.4 0.0 154.74 315.365 ;
      END
    PORT
      LAYER M4 ;
      RECT 158.615 0.0 158.955 315.365 ;
      END
    PORT
      LAYER M4 ;
      RECT 160.12 0.0 160.46 315.365 ;
      END
    PORT
      LAYER M4 ;
      RECT 161.275 0.0 161.615 315.365 ;
      END
    PORT
      LAYER M4 ;
      RECT 162.8 0.0 163.14 315.365 ;
      END
    PORT
      LAYER M4 ;
      RECT 167.015 0.0 167.355 315.365 ;
      END
    PORT
      LAYER M4 ;
      RECT 168.52 0.0 168.86 315.365 ;
      END
    PORT
      LAYER M4 ;
      RECT 169.675 0.0 170.015 315.365 ;
      END
    PORT
      LAYER M4 ;
      RECT 171.2 0.0 171.54 315.365 ;
      END
    PORT
      LAYER M4 ;
      RECT 175.415 0.0 175.755 315.365 ;
      END
    PORT
      LAYER M4 ;
      RECT 176.92 0.0 177.26 315.365 ;
      END
    PORT
      LAYER M4 ;
      RECT 178.075 0.0 178.415 315.365 ;
      END
    PORT
      LAYER M4 ;
      RECT 179.6 0.0 179.94 315.365 ;
      END
    PORT
      LAYER M4 ;
      RECT 183.815 0.0 184.155 315.365 ;
      END
    PORT
      LAYER M4 ;
      RECT 185.32 0.0 185.66 315.365 ;
      END
    PORT
      LAYER M4 ;
      RECT 186.475 0.0 186.815 315.365 ;
      END
    PORT
      LAYER M4 ;
      RECT 188.0 0.0 188.34 315.365 ;
      END
    PORT
      LAYER M4 ;
      RECT 192.215 0.0 192.555 315.365 ;
      END
    PORT
      LAYER M4 ;
      RECT 193.72 0.0 194.06 315.365 ;
      END
    PORT
      LAYER M4 ;
      RECT 194.875 0.0 195.215 315.365 ;
      END
    PORT
      LAYER M4 ;
      RECT 196.4 0.0 196.74 315.365 ;
      END
    PORT
      LAYER M4 ;
      RECT 200.615 0.0 200.955 315.365 ;
      END
    PORT
      LAYER M4 ;
      RECT 202.12 0.0 202.46 315.365 ;
      END
    PORT
      LAYER M4 ;
      RECT 203.275 0.0 203.615 315.365 ;
      END
    PORT
      LAYER M4 ;
      RECT 204.8 0.0 205.14 315.365 ;
      END
    PORT
      LAYER M4 ;
      RECT 209.015 0.0 209.355 315.365 ;
      END
    PORT
      LAYER M4 ;
      RECT 210.52 0.0 210.86 315.365 ;
      END
    PORT
      LAYER M4 ;
      RECT 211.675 0.0 212.015 315.365 ;
      END
    PORT
      LAYER M4 ;
      RECT 213.2 0.0 213.54 315.365 ;
      END
    PORT
      LAYER M4 ;
      RECT 217.415 0.0 217.755 315.365 ;
      END
    PORT
      LAYER M4 ;
      RECT 218.92 0.0 219.26 315.365 ;
      END
    PORT
      LAYER M4 ;
      RECT 220.075 0.0 220.415 315.365 ;
      END
    PORT
      LAYER M4 ;
      RECT 221.6 0.0 221.94 315.365 ;
      END
    PORT
      LAYER M4 ;
      RECT 225.815 0.0 226.155 315.365 ;
      END
    PORT
      LAYER M4 ;
      RECT 227.32 0.0 227.66 315.365 ;
      END
    PORT
      LAYER M4 ;
      RECT 228.475 0.0 228.815 315.365 ;
      END
    PORT
      LAYER M4 ;
      RECT 230.0 0.0 230.34 315.365 ;
      END
    PORT
      LAYER M4 ;
      RECT 234.215 0.0 234.555 315.365 ;
      END
    PORT
      LAYER M4 ;
      RECT 235.72 0.0 236.06 315.365 ;
      END
    PORT
      LAYER M4 ;
      RECT 236.875 0.0 237.215 315.365 ;
      END
    PORT
      LAYER M4 ;
      RECT 238.4 0.0 238.74 315.365 ;
      END
    PORT
      LAYER M4 ;
      RECT 242.615 0.0 242.955 315.365 ;
      END
    PORT
      LAYER M4 ;
      RECT 244.12 0.0 244.46 315.365 ;
      END
    PORT
      LAYER M4 ;
      RECT 245.275 0.0 245.615 315.365 ;
      END
    PORT
      LAYER M4 ;
      RECT 246.8 0.0 247.14 315.365 ;
      END
    PORT
      LAYER M4 ;
      RECT 251.015 0.0 251.355 315.365 ;
      END
    PORT
      LAYER M4 ;
      RECT 252.52 0.0 252.86 315.365 ;
      END
    PORT
      LAYER M4 ;
      RECT 253.675 0.0 254.015 315.365 ;
      END
    PORT
      LAYER M4 ;
      RECT 255.2 0.0 255.54 315.365 ;
      END
    PORT
      LAYER M4 ;
      RECT 259.415 0.0 259.755 315.365 ;
      END
    PORT
      LAYER M4 ;
      RECT 260.92 0.0 261.26 315.365 ;
      END
    PORT
      LAYER M4 ;
      RECT 262.075 0.0 262.415 315.365 ;
      END
    PORT
      LAYER M4 ;
      RECT 263.6 0.0 263.94 315.365 ;
      END
    PORT
      LAYER M4 ;
      RECT 267.815 0.0 268.155 315.365 ;
      END
    PORT
      LAYER M4 ;
      RECT 269.32 0.0 269.66 315.365 ;
      END
    PORT
      LAYER M4 ;
      RECT 272.825 0.0 273.255 315.365 ;
      END
    PORT
      LAYER M4 ;
      RECT 275.47 0.0 275.89 315.365 ;
      END
    PORT
      LAYER M4 ;
      RECT 278.115 0.0 278.535 315.365 ;
      END
    PORT
      LAYER M4 ;
      RECT 280.83 0.0 281.16 315.365 ;
      END
    PORT
      LAYER M4 ;
      RECT 288.185 0.0 288.605 315.365 ;
      END
    PORT
      LAYER M4 ;
      RECT 290.785 0.0 291.205 315.365 ;
      END
    PORT
      LAYER M4 ;
      RECT 291.46 0.0 291.79 315.365 ;
      END
    PORT
      LAYER M4 ;
      RECT 293.385 0.0 293.805 315.365 ;
      END
    PORT
      LAYER M4 ;
      RECT 295.995 0.0 296.415 315.365 ;
      END
    PORT
      LAYER M4 ;
      RECT 297.985 0.0 298.405 315.365 ;
      END
    PORT
      LAYER M4 ;
      RECT 303.525 0.0 303.855 315.365 ;
      END
    PORT
      LAYER M4 ;
      RECT 308.63 0.0 309.05 315.365 ;
      END
    PORT
      LAYER M4 ;
      RECT 311.275 0.0 311.695 315.365 ;
      END
    PORT
      LAYER M4 ;
      RECT 316.57 0.0 316.99 315.365 ;
      END
    PORT
      LAYER M4 ;
      RECT 317.29 0.0 317.62 315.365 ;
      END
    PORT
      LAYER M4 ;
      RECT 319.215 0.0 319.635 315.365 ;
      END
    PORT
      LAYER M4 ;
      RECT 321.87 0.0 322.29 315.365 ;
      END
    PORT
      LAYER M4 ;
      RECT 326.585 0.0 327.005 315.365 ;
      END
    PORT
      LAYER M4 ;
      RECT 329.24 0.0 329.66 315.365 ;
      END
    PORT
      LAYER M4 ;
      RECT 331.885 0.0 332.305 315.365 ;
      END
    PORT
      LAYER M4 ;
      RECT 335.475 0.0 335.815 315.365 ;
      END
    PORT
      LAYER M4 ;
      RECT 337.0 0.0 337.34 315.365 ;
      END
    PORT
      LAYER M4 ;
      RECT 341.215 0.0 341.555 315.365 ;
      END
    PORT
      LAYER M4 ;
      RECT 342.72 0.0 343.06 315.365 ;
      END
    PORT
      LAYER M4 ;
      RECT 343.875 0.0 344.215 315.365 ;
      END
    PORT
      LAYER M4 ;
      RECT 345.4 0.0 345.74 315.365 ;
      END
    PORT
      LAYER M4 ;
      RECT 349.615 0.0 349.955 315.365 ;
      END
    PORT
      LAYER M4 ;
      RECT 351.12 0.0 351.46 315.365 ;
      END
    PORT
      LAYER M4 ;
      RECT 352.275 0.0 352.615 315.365 ;
      END
    PORT
      LAYER M4 ;
      RECT 353.8 0.0 354.14 315.365 ;
      END
    PORT
      LAYER M4 ;
      RECT 358.015 0.0 358.355 315.365 ;
      END
    PORT
      LAYER M4 ;
      RECT 359.52 0.0 359.86 315.365 ;
      END
    PORT
      LAYER M4 ;
      RECT 360.675 0.0 361.015 315.365 ;
      END
    PORT
      LAYER M4 ;
      RECT 362.2 0.0 362.54 315.365 ;
      END
    PORT
      LAYER M4 ;
      RECT 366.415 0.0 366.755 315.365 ;
      END
    PORT
      LAYER M4 ;
      RECT 367.92 0.0 368.26 315.365 ;
      END
    PORT
      LAYER M4 ;
      RECT 369.075 0.0 369.415 315.365 ;
      END
    PORT
      LAYER M4 ;
      RECT 370.6 0.0 370.94 315.365 ;
      END
    PORT
      LAYER M4 ;
      RECT 374.815 0.0 375.155 315.365 ;
      END
    PORT
      LAYER M4 ;
      RECT 376.32 0.0 376.66 315.365 ;
      END
    PORT
      LAYER M4 ;
      RECT 377.475 0.0 377.815 315.365 ;
      END
    PORT
      LAYER M4 ;
      RECT 379.0 0.0 379.34 315.365 ;
      END
    PORT
      LAYER M4 ;
      RECT 383.215 0.0 383.555 315.365 ;
      END
    PORT
      LAYER M4 ;
      RECT 384.72 0.0 385.06 315.365 ;
      END
    PORT
      LAYER M4 ;
      RECT 385.875 0.0 386.215 315.365 ;
      END
    PORT
      LAYER M4 ;
      RECT 387.4 0.0 387.74 315.365 ;
      END
    PORT
      LAYER M4 ;
      RECT 391.615 0.0 391.955 315.365 ;
      END
    PORT
      LAYER M4 ;
      RECT 393.12 0.0 393.46 315.365 ;
      END
    PORT
      LAYER M4 ;
      RECT 394.275 0.0 394.615 315.365 ;
      END
    PORT
      LAYER M4 ;
      RECT 395.8 0.0 396.14 315.365 ;
      END
    PORT
      LAYER M4 ;
      RECT 400.015 0.0 400.355 315.365 ;
      END
    PORT
      LAYER M4 ;
      RECT 401.52 0.0 401.86 315.365 ;
      END
    PORT
      LAYER M4 ;
      RECT 402.675 0.0 403.015 315.365 ;
      END
    PORT
      LAYER M4 ;
      RECT 404.2 0.0 404.54 315.365 ;
      END
    PORT
      LAYER M4 ;
      RECT 408.415 0.0 408.755 315.365 ;
      END
    PORT
      LAYER M4 ;
      RECT 409.92 0.0 410.26 315.365 ;
      END
    PORT
      LAYER M4 ;
      RECT 411.075 0.0 411.415 315.365 ;
      END
    PORT
      LAYER M4 ;
      RECT 412.6 0.0 412.94 315.365 ;
      END
    PORT
      LAYER M4 ;
      RECT 416.815 0.0 417.155 315.365 ;
      END
    PORT
      LAYER M4 ;
      RECT 418.32 0.0 418.66 315.365 ;
      END
    PORT
      LAYER M4 ;
      RECT 419.475 0.0 419.815 315.365 ;
      END
    PORT
      LAYER M4 ;
      RECT 421.0 0.0 421.34 315.365 ;
      END
    PORT
      LAYER M4 ;
      RECT 425.215 0.0 425.555 315.365 ;
      END
    PORT
      LAYER M4 ;
      RECT 426.72 0.0 427.06 315.365 ;
      END
    PORT
      LAYER M4 ;
      RECT 427.875 0.0 428.215 315.365 ;
      END
    PORT
      LAYER M4 ;
      RECT 429.4 0.0 429.74 315.365 ;
      END
    PORT
      LAYER M4 ;
      RECT 433.615 0.0 433.955 315.365 ;
      END
    PORT
      LAYER M4 ;
      RECT 435.12 0.0 435.46 315.365 ;
      END
    PORT
      LAYER M4 ;
      RECT 436.275 0.0 436.615 315.365 ;
      END
    PORT
      LAYER M4 ;
      RECT 437.8 0.0 438.14 315.365 ;
      END
    PORT
      LAYER M4 ;
      RECT 442.015 0.0 442.355 315.365 ;
      END
    PORT
      LAYER M4 ;
      RECT 443.52 0.0 443.86 315.365 ;
      END
    PORT
      LAYER M4 ;
      RECT 444.675 0.0 445.015 315.365 ;
      END
    PORT
      LAYER M4 ;
      RECT 446.2 0.0 446.54 315.365 ;
      END
    PORT
      LAYER M4 ;
      RECT 450.415 0.0 450.755 315.365 ;
      END
    PORT
      LAYER M4 ;
      RECT 451.92 0.0 452.26 315.365 ;
      END
    PORT
      LAYER M4 ;
      RECT 453.075 0.0 453.415 315.365 ;
      END
    PORT
      LAYER M4 ;
      RECT 454.6 0.0 454.94 315.365 ;
      END
    PORT
      LAYER M4 ;
      RECT 458.815 0.0 459.155 315.365 ;
      END
    PORT
      LAYER M4 ;
      RECT 460.32 0.0 460.66 315.365 ;
      END
    PORT
      LAYER M4 ;
      RECT 461.475 0.0 461.815 315.365 ;
      END
    PORT
      LAYER M4 ;
      RECT 463.0 0.0 463.34 315.365 ;
      END
    PORT
      LAYER M4 ;
      RECT 467.215 0.0 467.555 315.365 ;
      END
    PORT
      LAYER M4 ;
      RECT 468.72 0.0 469.06 315.365 ;
      END
    PORT
      LAYER M4 ;
      RECT 469.875 0.0 470.215 315.365 ;
      END
    PORT
      LAYER M4 ;
      RECT 471.4 0.0 471.74 315.365 ;
      END
    PORT
      LAYER M4 ;
      RECT 475.615 0.0 475.955 315.365 ;
      END
    PORT
      LAYER M4 ;
      RECT 477.12 0.0 477.46 315.365 ;
      END
    PORT
      LAYER M4 ;
      RECT 478.275 0.0 478.615 315.365 ;
      END
    PORT
      LAYER M4 ;
      RECT 479.8 0.0 480.14 315.365 ;
      END
    PORT
      LAYER M4 ;
      RECT 484.015 0.0 484.355 315.365 ;
      END
    PORT
      LAYER M4 ;
      RECT 485.52 0.0 485.86 315.365 ;
      END
    PORT
      LAYER M4 ;
      RECT 486.675 0.0 487.015 315.365 ;
      END
    PORT
      LAYER M4 ;
      RECT 488.2 0.0 488.54 315.365 ;
      END
    PORT
      LAYER M4 ;
      RECT 492.415 0.0 492.755 315.365 ;
      END
    PORT
      LAYER M4 ;
      RECT 493.92 0.0 494.26 315.365 ;
      END
    PORT
      LAYER M4 ;
      RECT 495.075 0.0 495.415 315.365 ;
      END
    PORT
      LAYER M4 ;
      RECT 496.6 0.0 496.94 315.365 ;
      END
    PORT
      LAYER M4 ;
      RECT 500.815 0.0 501.155 315.365 ;
      END
    PORT
      LAYER M4 ;
      RECT 502.32 0.0 502.66 315.365 ;
      END
    PORT
      LAYER M4 ;
      RECT 503.475 0.0 503.815 315.365 ;
      END
    PORT
      LAYER M4 ;
      RECT 505.0 0.0 505.34 315.365 ;
      END
    PORT
      LAYER M4 ;
      RECT 509.215 0.0 509.555 315.365 ;
      END
    PORT
      LAYER M4 ;
      RECT 510.72 0.0 511.06 315.365 ;
      END
    PORT
      LAYER M4 ;
      RECT 511.875 0.0 512.215 315.365 ;
      END
    PORT
      LAYER M4 ;
      RECT 513.4 0.0 513.74 315.365 ;
      END
    PORT
      LAYER M4 ;
      RECT 517.615 0.0 517.955 315.365 ;
      END
    PORT
      LAYER M4 ;
      RECT 519.12 0.0 519.46 315.365 ;
      END
    PORT
      LAYER M4 ;
      RECT 520.275 0.0 520.615 315.365 ;
      END
    PORT
      LAYER M4 ;
      RECT 521.8 0.0 522.14 315.365 ;
      END
    PORT
      LAYER M4 ;
      RECT 526.015 0.0 526.355 315.365 ;
      END
    PORT
      LAYER M4 ;
      RECT 527.52 0.0 527.86 315.365 ;
      END
    PORT
      LAYER M4 ;
      RECT 528.675 0.0 529.015 315.365 ;
      END
    PORT
      LAYER M4 ;
      RECT 530.2 0.0 530.54 315.365 ;
      END
    PORT
      LAYER M4 ;
      RECT 534.415 0.0 534.755 315.365 ;
      END
    PORT
      LAYER M4 ;
      RECT 535.92 0.0 536.26 315.365 ;
      END
    PORT
      LAYER M4 ;
      RECT 537.075 0.0 537.415 315.365 ;
      END
    PORT
      LAYER M4 ;
      RECT 538.6 0.0 538.94 315.365 ;
      END
    PORT
      LAYER M4 ;
      RECT 542.815 0.0 543.155 315.365 ;
      END
    PORT
      LAYER M4 ;
      RECT 544.32 0.0 544.66 315.365 ;
      END
    PORT
      LAYER M4 ;
      RECT 545.475 0.0 545.815 315.365 ;
      END
    PORT
      LAYER M4 ;
      RECT 547.0 0.0 547.34 315.365 ;
      END
    PORT
      LAYER M4 ;
      RECT 551.215 0.0 551.555 315.365 ;
      END
    PORT
      LAYER M4 ;
      RECT 552.72 0.0 553.06 315.365 ;
      END
    PORT
      LAYER M4 ;
      RECT 553.875 0.0 554.215 315.365 ;
      END
    PORT
      LAYER M4 ;
      RECT 555.4 0.0 555.74 315.365 ;
      END
    PORT
      LAYER M4 ;
      RECT 559.615 0.0 559.955 315.365 ;
      END
    PORT
      LAYER M4 ;
      RECT 561.12 0.0 561.46 315.365 ;
      END
    PORT
      LAYER M4 ;
      RECT 562.275 0.0 562.615 315.365 ;
      END
    PORT
      LAYER M4 ;
      RECT 563.8 0.0 564.14 315.365 ;
      END
    PORT
      LAYER M4 ;
      RECT 568.015 0.0 568.355 315.365 ;
      END
    PORT
      LAYER M4 ;
      RECT 569.52 0.0 569.86 315.365 ;
      END
    PORT
      LAYER M4 ;
      RECT 570.675 0.0 571.015 315.365 ;
      END
    PORT
      LAYER M4 ;
      RECT 572.2 0.0 572.54 315.365 ;
      END
    PORT
      LAYER M4 ;
      RECT 576.415 0.0 576.755 315.365 ;
      END
    PORT
      LAYER M4 ;
      RECT 577.92 0.0 578.26 315.365 ;
      END
    PORT
      LAYER M4 ;
      RECT 579.075 0.0 579.415 315.365 ;
      END
    PORT
      LAYER M4 ;
      RECT 580.6 0.0 580.94 315.365 ;
      END
    PORT
      LAYER M4 ;
      RECT 584.815 0.0 585.155 315.365 ;
      END
    PORT
      LAYER M4 ;
      RECT 586.32 0.0 586.66 315.365 ;
      END
    PORT
      LAYER M4 ;
      RECT 587.475 0.0 587.815 315.365 ;
      END
    PORT
      LAYER M4 ;
      RECT 589.0 0.0 589.34 315.365 ;
      END
    PORT
      LAYER M4 ;
      RECT 593.215 0.0 593.555 315.365 ;
      END
    PORT
      LAYER M4 ;
      RECT 594.72 0.0 595.06 315.365 ;
      END
    PORT
      LAYER M4 ;
      RECT 595.875 0.0 596.215 315.365 ;
      END
    PORT
      LAYER M4 ;
      RECT 597.4 0.0 597.74 315.365 ;
      END
    PORT
      LAYER M4 ;
      RECT 601.615 0.0 601.955 315.365 ;
      END
    PORT
      LAYER M4 ;
      RECT 603.12 0.0 603.46 315.365 ;
      END
    PORT
      LAYER M4 ;
      RECT 604.28 0.0 604.43 315.365 ;
      END
    PORT
      LAYER M4 ;
      RECT 605.4 0.0 605.55 315.365 ;
      END
    PORT
      LAYER M4 ;
      RECT 606.37 0.0 606.71 315.365 ;
      END
    PORT
      LAYER M4 ;
      RECT 607.875 0.0 608.215 315.365 ;
      END
    PORT
      LAYER M4 ;
      RECT 612.09 0.0 612.43 315.365 ;
      END
    PORT
      LAYER M4 ;
      RECT 613.615 0.0 613.955 315.365 ;
      END
    PORT
      LAYER M4 ;
      RECT 614.77 0.0 615.11 315.365 ;
      END
    PORT
      LAYER M4 ;
      RECT 616.275 0.0 616.615 315.365 ;
      END
    PORT
      LAYER M4 ;
      RECT 620.49 0.0 620.83 315.365 ;
      END
    PORT
      LAYER M4 ;
      RECT 622.015 0.0 622.355 315.365 ;
      END
    PORT
      LAYER M4 ;
      RECT 623.17 0.0 623.51 315.365 ;
      END
    PORT
      LAYER M4 ;
      RECT 624.675 0.0 625.015 315.365 ;
      END
    PORT
      LAYER M4 ;
      RECT 628.89 0.0 629.23 315.365 ;
      END
    PORT
      LAYER M4 ;
      RECT 630.415 0.0 630.755 315.365 ;
      END
    PORT
      LAYER M4 ;
      RECT 631.57 0.0 631.91 315.365 ;
      END
    PORT
      LAYER M4 ;
      RECT 633.075 0.0 633.415 315.365 ;
      END
    PORT
      LAYER M4 ;
      RECT 637.29 0.0 637.63 315.365 ;
      END
    PORT
      LAYER M4 ;
      RECT 638.815 0.0 639.155 315.365 ;
      END
    PORT
      LAYER M4 ;
      RECT 639.97 0.0 640.31 315.365 ;
      END
    PORT
      LAYER M4 ;
      RECT 641.475 0.0 641.815 315.365 ;
      END
    PORT
      LAYER M4 ;
      RECT 645.69 0.0 646.03 315.365 ;
      END
    PORT
      LAYER M4 ;
      RECT 647.215 0.0 647.555 315.365 ;
      END
    PORT
      LAYER M4 ;
      RECT 648.37 0.0 648.71 315.365 ;
      END
    PORT
      LAYER M4 ;
      RECT 649.875 0.0 650.215 315.365 ;
      END
    PORT
      LAYER M4 ;
      RECT 654.09 0.0 654.43 315.365 ;
      END
    PORT
      LAYER M4 ;
      RECT 655.615 0.0 655.955 315.365 ;
      END
    PORT
      LAYER M4 ;
      RECT 656.77 0.0 657.11 315.365 ;
      END
    PORT
      LAYER M4 ;
      RECT 658.275 0.0 658.615 315.365 ;
      END
    PORT
      LAYER M4 ;
      RECT 662.49 0.0 662.83 315.365 ;
      END
    PORT
      LAYER M4 ;
      RECT 664.015 0.0 664.355 315.365 ;
      END
    PORT
      LAYER M4 ;
      RECT 665.17 0.0 665.51 315.365 ;
      END
    PORT
      LAYER M4 ;
      RECT 666.675 0.0 667.015 315.365 ;
      END
    PORT
      LAYER M4 ;
      RECT 670.89 0.0 671.23 315.365 ;
      END
    PORT
      LAYER M4 ;
      RECT 672.415 0.0 672.755 315.365 ;
      END
    PORT
      LAYER M4 ;
      RECT 673.57 0.0 673.91 315.365 ;
      END
    PORT
      LAYER M4 ;
      RECT 675.075 0.0 675.415 315.365 ;
      END
    PORT
      LAYER M4 ;
      RECT 679.29 0.0 679.63 315.365 ;
      END
    PORT
      LAYER M4 ;
      RECT 680.815 0.0 681.155 315.365 ;
      END
    PORT
      LAYER M4 ;
      RECT 681.97 0.0 682.31 315.365 ;
      END
    PORT
      LAYER M4 ;
      RECT 683.475 0.0 683.815 315.365 ;
      END
    PORT
      LAYER M4 ;
      RECT 687.69 0.0 688.03 315.365 ;
      END
    PORT
      LAYER M4 ;
      RECT 689.215 0.0 689.555 315.365 ;
      END
    PORT
      LAYER M4 ;
      RECT 690.37 0.0 690.71 315.365 ;
      END
    PORT
      LAYER M4 ;
      RECT 691.875 0.0 692.215 315.365 ;
      END
    PORT
      LAYER M4 ;
      RECT 696.09 0.0 696.43 315.365 ;
      END
    PORT
      LAYER M4 ;
      RECT 697.615 0.0 697.955 315.365 ;
      END
    PORT
      LAYER M4 ;
      RECT 698.77 0.0 699.11 315.365 ;
      END
    PORT
      LAYER M4 ;
      RECT 700.275 0.0 700.615 315.365 ;
      END
    PORT
      LAYER M4 ;
      RECT 704.49 0.0 704.83 315.365 ;
      END
    PORT
      LAYER M4 ;
      RECT 706.015 0.0 706.355 315.365 ;
      END
    PORT
      LAYER M4 ;
      RECT 707.17 0.0 707.51 315.365 ;
      END
    PORT
      LAYER M4 ;
      RECT 708.675 0.0 709.015 315.365 ;
      END
    PORT
      LAYER M4 ;
      RECT 712.89 0.0 713.23 315.365 ;
      END
    PORT
      LAYER M4 ;
      RECT 714.415 0.0 714.755 315.365 ;
      END
    PORT
      LAYER M4 ;
      RECT 715.57 0.0 715.91 315.365 ;
      END
    PORT
      LAYER M4 ;
      RECT 717.075 0.0 717.415 315.365 ;
      END
    PORT
      LAYER M4 ;
      RECT 721.29 0.0 721.63 315.365 ;
      END
    PORT
      LAYER M4 ;
      RECT 722.815 0.0 723.155 315.365 ;
      END
    PORT
      LAYER M4 ;
      RECT 723.97 0.0 724.31 315.365 ;
      END
    PORT
      LAYER M4 ;
      RECT 725.475 0.0 725.815 315.365 ;
      END
    PORT
      LAYER M4 ;
      RECT 729.69 0.0 730.03 315.365 ;
      END
    PORT
      LAYER M4 ;
      RECT 731.215 0.0 731.555 315.365 ;
      END
    PORT
      LAYER M4 ;
      RECT 732.37 0.0 732.71 315.365 ;
      END
    PORT
      LAYER M4 ;
      RECT 733.875 0.0 734.215 315.365 ;
      END
    PORT
      LAYER M4 ;
      RECT 738.09 0.0 738.43 315.365 ;
      END
    PORT
      LAYER M4 ;
      RECT 739.615 0.0 739.955 315.365 ;
      END
    PORT
      LAYER M4 ;
      RECT 740.77 0.0 741.11 315.365 ;
      END
    PORT
      LAYER M4 ;
      RECT 742.275 0.0 742.615 315.365 ;
      END
    PORT
      LAYER M4 ;
      RECT 746.49 0.0 746.83 315.365 ;
      END
    PORT
      LAYER M4 ;
      RECT 748.015 0.0 748.355 315.365 ;
      END
    PORT
      LAYER M4 ;
      RECT 749.17 0.0 749.51 315.365 ;
      END
    PORT
      LAYER M4 ;
      RECT 750.675 0.0 751.015 315.365 ;
      END
    PORT
      LAYER M4 ;
      RECT 754.89 0.0 755.23 315.365 ;
      END
    PORT
      LAYER M4 ;
      RECT 756.415 0.0 756.755 315.365 ;
      END
    PORT
      LAYER M4 ;
      RECT 757.57 0.0 757.91 315.365 ;
      END
    PORT
      LAYER M4 ;
      RECT 759.075 0.0 759.415 315.365 ;
      END
    PORT
      LAYER M4 ;
      RECT 763.29 0.0 763.63 315.365 ;
      END
    PORT
      LAYER M4 ;
      RECT 764.815 0.0 765.155 315.365 ;
      END
    PORT
      LAYER M4 ;
      RECT 765.97 0.0 766.31 315.365 ;
      END
    PORT
      LAYER M4 ;
      RECT 767.475 0.0 767.815 315.365 ;
      END
    PORT
      LAYER M4 ;
      RECT 771.69 0.0 772.03 315.365 ;
      END
    PORT
      LAYER M4 ;
      RECT 773.215 0.0 773.555 315.365 ;
      END
    PORT
      LAYER M4 ;
      RECT 774.37 0.0 774.71 315.365 ;
      END
    PORT
      LAYER M4 ;
      RECT 775.875 0.0 776.215 315.365 ;
      END
    PORT
      LAYER M4 ;
      RECT 780.09 0.0 780.43 315.365 ;
      END
    PORT
      LAYER M4 ;
      RECT 781.615 0.0 781.955 315.365 ;
      END
    PORT
      LAYER M4 ;
      RECT 782.77 0.0 783.11 315.365 ;
      END
    PORT
      LAYER M4 ;
      RECT 784.275 0.0 784.615 315.365 ;
      END
    PORT
      LAYER M4 ;
      RECT 788.49 0.0 788.83 315.365 ;
      END
    PORT
      LAYER M4 ;
      RECT 790.015 0.0 790.355 315.365 ;
      END
    PORT
      LAYER M4 ;
      RECT 791.17 0.0 791.51 315.365 ;
      END
    PORT
      LAYER M4 ;
      RECT 792.675 0.0 793.015 315.365 ;
      END
    PORT
      LAYER M4 ;
      RECT 796.89 0.0 797.23 315.365 ;
      END
    PORT
      LAYER M4 ;
      RECT 798.415 0.0 798.755 315.365 ;
      END
    PORT
      LAYER M4 ;
      RECT 799.57 0.0 799.91 315.365 ;
      END
    PORT
      LAYER M4 ;
      RECT 801.075 0.0 801.415 315.365 ;
      END
    PORT
      LAYER M4 ;
      RECT 805.29 0.0 805.63 315.365 ;
      END
    PORT
      LAYER M4 ;
      RECT 806.815 0.0 807.155 315.365 ;
      END
    PORT
      LAYER M4 ;
      RECT 807.97 0.0 808.31 315.365 ;
      END
    PORT
      LAYER M4 ;
      RECT 809.475 0.0 809.815 315.365 ;
      END
    PORT
      LAYER M4 ;
      RECT 813.69 0.0 814.03 315.365 ;
      END
    PORT
      LAYER M4 ;
      RECT 815.215 0.0 815.555 315.365 ;
      END
    PORT
      LAYER M4 ;
      RECT 816.37 0.0 816.71 315.365 ;
      END
    PORT
      LAYER M4 ;
      RECT 817.875 0.0 818.215 315.365 ;
      END
    PORT
      LAYER M4 ;
      RECT 822.09 0.0 822.43 315.365 ;
      END
    PORT
      LAYER M4 ;
      RECT 823.615 0.0 823.955 315.365 ;
      END
    PORT
      LAYER M4 ;
      RECT 824.77 0.0 825.11 315.365 ;
      END
    PORT
      LAYER M4 ;
      RECT 826.275 0.0 826.615 315.365 ;
      END
    PORT
      LAYER M4 ;
      RECT 830.49 0.0 830.83 315.365 ;
      END
    PORT
      LAYER M4 ;
      RECT 832.015 0.0 832.355 315.365 ;
      END
    PORT
      LAYER M4 ;
      RECT 833.17 0.0 833.51 315.365 ;
      END
    PORT
      LAYER M4 ;
      RECT 834.675 0.0 835.015 315.365 ;
      END
    PORT
      LAYER M4 ;
      RECT 838.89 0.0 839.23 315.365 ;
      END
    PORT
      LAYER M4 ;
      RECT 840.415 0.0 840.755 315.365 ;
      END
    PORT
      LAYER M4 ;
      RECT 841.57 0.0 841.91 315.365 ;
      END
    PORT
      LAYER M4 ;
      RECT 843.075 0.0 843.415 315.365 ;
      END
    PORT
      LAYER M4 ;
      RECT 847.29 0.0 847.63 315.365 ;
      END
    PORT
      LAYER M4 ;
      RECT 848.815 0.0 849.155 315.365 ;
      END
    PORT
      LAYER M4 ;
      RECT 849.97 0.0 850.31 315.365 ;
      END
    PORT
      LAYER M4 ;
      RECT 851.475 0.0 851.815 315.365 ;
      END
    PORT
      LAYER M4 ;
      RECT 855.69 0.0 856.03 315.365 ;
      END
    PORT
      LAYER M4 ;
      RECT 857.215 0.0 857.555 315.365 ;
      END
    PORT
      LAYER M4 ;
      RECT 858.37 0.0 858.71 315.365 ;
      END
    PORT
      LAYER M4 ;
      RECT 859.875 0.0 860.215 315.365 ;
      END
    PORT
      LAYER M4 ;
      RECT 864.09 0.0 864.43 315.365 ;
      END
    PORT
      LAYER M4 ;
      RECT 865.615 0.0 865.955 315.365 ;
      END
    PORT
      LAYER M4 ;
      RECT 866.77 0.0 867.11 315.365 ;
      END
    PORT
      LAYER M4 ;
      RECT 868.275 0.0 868.615 315.365 ;
      END
    PORT
      LAYER M4 ;
      RECT 872.49 0.0 872.83 315.365 ;
      END
    PORT
      LAYER M4 ;
      RECT 874.015 0.0 874.355 315.365 ;
      END
    PORT
      LAYER M4 ;
      RECT 877.525 0.0 877.945 315.365 ;
      END
    PORT
      LAYER M4 ;
      RECT 880.17 0.0 880.59 315.365 ;
      END
    PORT
      LAYER M4 ;
      RECT 882.825 0.0 883.245 315.365 ;
      END
    PORT
      LAYER M4 ;
      RECT 887.54 0.0 887.96 315.365 ;
      END
    PORT
      LAYER M4 ;
      RECT 890.195 0.0 890.615 315.365 ;
      END
    PORT
      LAYER M4 ;
      RECT 892.21 0.0 892.54 315.365 ;
      END
    PORT
      LAYER M4 ;
      RECT 892.84 0.0 893.26 315.365 ;
      END
    PORT
      LAYER M4 ;
      RECT 898.135 0.0 898.555 315.365 ;
      END
    PORT
      LAYER M4 ;
      RECT 900.78 0.0 901.2 315.365 ;
      END
    PORT
      LAYER M4 ;
      RECT 905.975 0.0 906.305 315.365 ;
      END
    PORT
      LAYER M4 ;
      RECT 911.425 0.0 911.845 315.365 ;
      END
    PORT
      LAYER M4 ;
      RECT 913.415 0.0 913.835 315.365 ;
      END
    PORT
      LAYER M4 ;
      RECT 916.025 0.0 916.445 315.365 ;
      END
    PORT
      LAYER M4 ;
      RECT 918.04 0.0 918.37 315.365 ;
      END
    PORT
      LAYER M4 ;
      RECT 918.625 0.0 919.045 315.365 ;
      END
    PORT
      LAYER M4 ;
      RECT 921.225 0.0 921.645 315.365 ;
      END
    PORT
      LAYER M4 ;
      RECT 928.67 0.0 929.0 315.365 ;
      END
    PORT
      LAYER M4 ;
      RECT 931.295 0.0 931.715 315.365 ;
      END
    PORT
      LAYER M4 ;
      RECT 933.94 0.0 934.36 315.365 ;
      END
    PORT
      LAYER M4 ;
      RECT 936.575 0.0 937.005 315.365 ;
      END
    PORT
      LAYER M4 ;
      RECT 940.17 0.0 940.51 315.365 ;
      END
    PORT
      LAYER M4 ;
      RECT 941.675 0.0 942.015 315.365 ;
      END
    PORT
      LAYER M4 ;
      RECT 945.89 0.0 946.23 315.365 ;
      END
    PORT
      LAYER M4 ;
      RECT 947.415 0.0 947.755 315.365 ;
      END
    PORT
      LAYER M4 ;
      RECT 948.57 0.0 948.91 315.365 ;
      END
    PORT
      LAYER M4 ;
      RECT 950.075 0.0 950.415 315.365 ;
      END
    PORT
      LAYER M4 ;
      RECT 954.29 0.0 954.63 315.365 ;
      END
    PORT
      LAYER M4 ;
      RECT 955.815 0.0 956.155 315.365 ;
      END
    PORT
      LAYER M4 ;
      RECT 956.97 0.0 957.31 315.365 ;
      END
    PORT
      LAYER M4 ;
      RECT 958.475 0.0 958.815 315.365 ;
      END
    PORT
      LAYER M4 ;
      RECT 962.69 0.0 963.03 315.365 ;
      END
    PORT
      LAYER M4 ;
      RECT 964.215 0.0 964.555 315.365 ;
      END
    PORT
      LAYER M4 ;
      RECT 965.37 0.0 965.71 315.365 ;
      END
    PORT
      LAYER M4 ;
      RECT 966.875 0.0 967.215 315.365 ;
      END
    PORT
      LAYER M4 ;
      RECT 971.09 0.0 971.43 315.365 ;
      END
    PORT
      LAYER M4 ;
      RECT 972.615 0.0 972.955 315.365 ;
      END
    PORT
      LAYER M4 ;
      RECT 973.77 0.0 974.11 315.365 ;
      END
    PORT
      LAYER M4 ;
      RECT 975.275 0.0 975.615 315.365 ;
      END
    PORT
      LAYER M4 ;
      RECT 979.49 0.0 979.83 315.365 ;
      END
    PORT
      LAYER M4 ;
      RECT 981.015 0.0 981.355 315.365 ;
      END
    PORT
      LAYER M4 ;
      RECT 982.17 0.0 982.51 315.365 ;
      END
    PORT
      LAYER M4 ;
      RECT 983.675 0.0 984.015 315.365 ;
      END
    PORT
      LAYER M4 ;
      RECT 987.89 0.0 988.23 315.365 ;
      END
    PORT
      LAYER M4 ;
      RECT 989.415 0.0 989.755 315.365 ;
      END
    PORT
      LAYER M4 ;
      RECT 990.57 0.0 990.91 315.365 ;
      END
    PORT
      LAYER M4 ;
      RECT 992.075 0.0 992.415 315.365 ;
      END
    PORT
      LAYER M4 ;
      RECT 996.29 0.0 996.63 315.365 ;
      END
    PORT
      LAYER M4 ;
      RECT 997.815 0.0 998.155 315.365 ;
      END
    PORT
      LAYER M4 ;
      RECT 998.97 0.0 999.31 315.365 ;
      END
    PORT
      LAYER M4 ;
      RECT 1000.475 0.0 1000.815 315.365 ;
      END
    PORT
      LAYER M4 ;
      RECT 1004.69 0.0 1005.03 315.365 ;
      END
    PORT
      LAYER M4 ;
      RECT 1006.215 0.0 1006.555 315.365 ;
      END
    PORT
      LAYER M4 ;
      RECT 1007.37 0.0 1007.71 315.365 ;
      END
    PORT
      LAYER M4 ;
      RECT 1008.875 0.0 1009.215 315.365 ;
      END
    PORT
      LAYER M4 ;
      RECT 1013.09 0.0 1013.43 315.365 ;
      END
    PORT
      LAYER M4 ;
      RECT 1014.615 0.0 1014.955 315.365 ;
      END
    PORT
      LAYER M4 ;
      RECT 1015.77 0.0 1016.11 315.365 ;
      END
    PORT
      LAYER M4 ;
      RECT 1017.275 0.0 1017.615 315.365 ;
      END
    PORT
      LAYER M4 ;
      RECT 1021.49 0.0 1021.83 315.365 ;
      END
    PORT
      LAYER M4 ;
      RECT 1023.015 0.0 1023.355 315.365 ;
      END
    PORT
      LAYER M4 ;
      RECT 1024.17 0.0 1024.51 315.365 ;
      END
    PORT
      LAYER M4 ;
      RECT 1025.675 0.0 1026.015 315.365 ;
      END
    PORT
      LAYER M4 ;
      RECT 1029.89 0.0 1030.23 315.365 ;
      END
    PORT
      LAYER M4 ;
      RECT 1031.415 0.0 1031.755 315.365 ;
      END
    PORT
      LAYER M4 ;
      RECT 1032.57 0.0 1032.91 315.365 ;
      END
    PORT
      LAYER M4 ;
      RECT 1034.075 0.0 1034.415 315.365 ;
      END
    PORT
      LAYER M4 ;
      RECT 1038.29 0.0 1038.63 315.365 ;
      END
    PORT
      LAYER M4 ;
      RECT 1039.815 0.0 1040.155 315.365 ;
      END
    PORT
      LAYER M4 ;
      RECT 1040.97 0.0 1041.31 315.365 ;
      END
    PORT
      LAYER M4 ;
      RECT 1042.475 0.0 1042.815 315.365 ;
      END
    PORT
      LAYER M4 ;
      RECT 1046.69 0.0 1047.03 315.365 ;
      END
    PORT
      LAYER M4 ;
      RECT 1048.215 0.0 1048.555 315.365 ;
      END
    PORT
      LAYER M4 ;
      RECT 1049.37 0.0 1049.71 315.365 ;
      END
    PORT
      LAYER M4 ;
      RECT 1050.875 0.0 1051.215 315.365 ;
      END
    PORT
      LAYER M4 ;
      RECT 1055.09 0.0 1055.43 315.365 ;
      END
    PORT
      LAYER M4 ;
      RECT 1056.615 0.0 1056.955 315.365 ;
      END
    PORT
      LAYER M4 ;
      RECT 1057.77 0.0 1058.11 315.365 ;
      END
    PORT
      LAYER M4 ;
      RECT 1059.275 0.0 1059.615 315.365 ;
      END
    PORT
      LAYER M4 ;
      RECT 1063.49 0.0 1063.83 315.365 ;
      END
    PORT
      LAYER M4 ;
      RECT 1065.015 0.0 1065.355 315.365 ;
      END
    PORT
      LAYER M4 ;
      RECT 1066.17 0.0 1066.51 315.365 ;
      END
    PORT
      LAYER M4 ;
      RECT 1067.675 0.0 1068.015 315.365 ;
      END
    PORT
      LAYER M4 ;
      RECT 1071.89 0.0 1072.23 315.365 ;
      END
    PORT
      LAYER M4 ;
      RECT 1073.415 0.0 1073.755 315.365 ;
      END
    PORT
      LAYER M4 ;
      RECT 1074.57 0.0 1074.91 315.365 ;
      END
    PORT
      LAYER M4 ;
      RECT 1076.075 0.0 1076.415 315.365 ;
      END
    PORT
      LAYER M4 ;
      RECT 1080.29 0.0 1080.63 315.365 ;
      END
    PORT
      LAYER M4 ;
      RECT 1081.815 0.0 1082.155 315.365 ;
      END
    PORT
      LAYER M4 ;
      RECT 1082.97 0.0 1083.31 315.365 ;
      END
    PORT
      LAYER M4 ;
      RECT 1084.475 0.0 1084.815 315.365 ;
      END
    PORT
      LAYER M4 ;
      RECT 1088.69 0.0 1089.03 315.365 ;
      END
    PORT
      LAYER M4 ;
      RECT 1090.215 0.0 1090.555 315.365 ;
      END
    PORT
      LAYER M4 ;
      RECT 1091.37 0.0 1091.71 315.365 ;
      END
    PORT
      LAYER M4 ;
      RECT 1092.875 0.0 1093.215 315.365 ;
      END
    PORT
      LAYER M4 ;
      RECT 1097.09 0.0 1097.43 315.365 ;
      END
    PORT
      LAYER M4 ;
      RECT 1098.615 0.0 1098.955 315.365 ;
      END
    PORT
      LAYER M4 ;
      RECT 1099.77 0.0 1100.11 315.365 ;
      END
    PORT
      LAYER M4 ;
      RECT 1101.275 0.0 1101.615 315.365 ;
      END
    PORT
      LAYER M4 ;
      RECT 1105.49 0.0 1105.83 315.365 ;
      END
    PORT
      LAYER M4 ;
      RECT 1107.015 0.0 1107.355 315.365 ;
      END
    PORT
      LAYER M4 ;
      RECT 1108.17 0.0 1108.51 315.365 ;
      END
    PORT
      LAYER M4 ;
      RECT 1109.675 0.0 1110.015 315.365 ;
      END
    PORT
      LAYER M4 ;
      RECT 1113.89 0.0 1114.23 315.365 ;
      END
    PORT
      LAYER M4 ;
      RECT 1115.415 0.0 1115.755 315.365 ;
      END
    PORT
      LAYER M4 ;
      RECT 1116.57 0.0 1116.91 315.365 ;
      END
    PORT
      LAYER M4 ;
      RECT 1118.075 0.0 1118.415 315.365 ;
      END
    PORT
      LAYER M4 ;
      RECT 1122.29 0.0 1122.63 315.365 ;
      END
    PORT
      LAYER M4 ;
      RECT 1123.815 0.0 1124.155 315.365 ;
      END
    PORT
      LAYER M4 ;
      RECT 1124.97 0.0 1125.31 315.365 ;
      END
    PORT
      LAYER M4 ;
      RECT 1126.475 0.0 1126.815 315.365 ;
      END
    PORT
      LAYER M4 ;
      RECT 1130.69 0.0 1131.03 315.365 ;
      END
    PORT
      LAYER M4 ;
      RECT 1132.215 0.0 1132.555 315.365 ;
      END
    PORT
      LAYER M4 ;
      RECT 1133.37 0.0 1133.71 315.365 ;
      END
    PORT
      LAYER M4 ;
      RECT 1134.875 0.0 1135.215 315.365 ;
      END
    PORT
      LAYER M4 ;
      RECT 1139.09 0.0 1139.43 315.365 ;
      END
    PORT
      LAYER M4 ;
      RECT 1140.615 0.0 1140.955 315.365 ;
      END
    PORT
      LAYER M4 ;
      RECT 1141.77 0.0 1142.11 315.365 ;
      END
    PORT
      LAYER M4 ;
      RECT 1143.275 0.0 1143.615 315.365 ;
      END
    PORT
      LAYER M4 ;
      RECT 1147.49 0.0 1147.83 315.365 ;
      END
    PORT
      LAYER M4 ;
      RECT 1149.015 0.0 1149.355 315.365 ;
      END
    PORT
      LAYER M4 ;
      RECT 1150.17 0.0 1150.51 315.365 ;
      END
    PORT
      LAYER M4 ;
      RECT 1151.675 0.0 1152.015 315.365 ;
      END
    PORT
      LAYER M4 ;
      RECT 1155.89 0.0 1156.23 315.365 ;
      END
    PORT
      LAYER M4 ;
      RECT 1157.415 0.0 1157.755 315.365 ;
      END
    PORT
      LAYER M4 ;
      RECT 1158.57 0.0 1158.91 315.365 ;
      END
    PORT
      LAYER M4 ;
      RECT 1160.075 0.0 1160.415 315.365 ;
      END
    PORT
      LAYER M4 ;
      RECT 1164.29 0.0 1164.63 315.365 ;
      END
    PORT
      LAYER M4 ;
      RECT 1165.815 0.0 1166.155 315.365 ;
      END
    PORT
      LAYER M4 ;
      RECT 1166.97 0.0 1167.31 315.365 ;
      END
    PORT
      LAYER M4 ;
      RECT 1168.475 0.0 1168.815 315.365 ;
      END
    PORT
      LAYER M4 ;
      RECT 1172.69 0.0 1173.03 315.365 ;
      END
    PORT
      LAYER M4 ;
      RECT 1174.215 0.0 1174.555 315.365 ;
      END
    PORT
      LAYER M4 ;
      RECT 1175.37 0.0 1175.71 315.365 ;
      END
    PORT
      LAYER M4 ;
      RECT 1176.875 0.0 1177.215 315.365 ;
      END
    PORT
      LAYER M4 ;
      RECT 1181.09 0.0 1181.43 315.365 ;
      END
    PORT
      LAYER M4 ;
      RECT 1182.615 0.0 1182.955 315.365 ;
      END
    PORT
      LAYER M4 ;
      RECT 1183.77 0.0 1184.11 315.365 ;
      END
    PORT
      LAYER M4 ;
      RECT 1185.275 0.0 1185.615 315.365 ;
      END
    PORT
      LAYER M4 ;
      RECT 1189.49 0.0 1189.83 315.365 ;
      END
    PORT
      LAYER M4 ;
      RECT 1191.015 0.0 1191.355 315.365 ;
      END
    PORT
      LAYER M4 ;
      RECT 1192.17 0.0 1192.51 315.365 ;
      END
    PORT
      LAYER M4 ;
      RECT 1193.675 0.0 1194.015 315.365 ;
      END
    PORT
      LAYER M4 ;
      RECT 1197.89 0.0 1198.23 315.365 ;
      END
    PORT
      LAYER M4 ;
      RECT 1199.415 0.0 1199.755 315.365 ;
      END
    PORT
      LAYER M4 ;
      RECT 1200.57 0.0 1200.91 315.365 ;
      END
    PORT
      LAYER M4 ;
      RECT 1202.075 0.0 1202.415 315.365 ;
      END
    PORT
      LAYER M4 ;
      RECT 1206.29 0.0 1206.63 315.365 ;
      END
    PORT
      LAYER M4 ;
      RECT 1207.815 0.0 1208.155 315.365 ;
      END
    PORT
      LAYER M4 ;
      RECT 1208.68 0.0 1208.83 315.365 ;
      END
    PORT
      LAYER M4 ;
      RECT 1209.3 0.0 1209.45 315.365 ;
      END
    END VSSE
  OBS
    #otc obstructions
    LAYER M1 DESIGNRULEWIDTH 0.1 ;
    RECT 1209.16 0.0 1209.83 0.42 ;
    RECT 1204.635 0.0 1208.74 0.42 ;
    RECT 1203.0 0.0 1204.215 0.42 ;
    RECT 1200.7 0.0 1202.58 0.42 ;
    RECT 1187.835 0.0 1200.28 0.42 ;
    RECT 1186.2 0.0 1187.415 0.42 ;
    RECT 1183.9 0.0 1185.78 0.42 ;
    RECT 1171.035 0.0 1183.48 0.42 ;
    RECT 1169.4 0.0 1170.615 0.42 ;
    RECT 1167.1 0.0 1168.98 0.42 ;
    RECT 1154.235 0.0 1166.68 0.42 ;
    RECT 1152.6 0.0 1153.815 0.42 ;
    RECT 1150.3 0.0 1152.18 0.42 ;
    RECT 1137.435 0.0 1149.88 0.42 ;
    RECT 1135.8 0.0 1137.015 0.42 ;
    RECT 1133.5 0.0 1135.38 0.42 ;
    RECT 1120.635 0.0 1133.08 0.42 ;
    RECT 1119.0 0.0 1120.215 0.42 ;
    RECT 1116.7 0.0 1118.58 0.42 ;
    RECT 1103.835 0.0 1116.28 0.42 ;
    RECT 1102.2 0.0 1103.415 0.42 ;
    RECT 1099.9 0.0 1101.78 0.42 ;
    RECT 1087.035 0.0 1099.48 0.42 ;
    RECT 1085.4 0.0 1086.615 0.42 ;
    RECT 1083.1 0.0 1084.98 0.42 ;
    RECT 1070.235 0.0 1082.68 0.42 ;
    RECT 1068.6 0.0 1069.815 0.42 ;
    RECT 1066.3 0.0 1068.18 0.42 ;
    RECT 1053.435 0.0 1065.88 0.42 ;
    RECT 1051.8 0.0 1053.015 0.42 ;
    RECT 1049.5 0.0 1051.38 0.42 ;
    RECT 1036.635 0.0 1049.08 0.42 ;
    RECT 1035.0 0.0 1036.215 0.42 ;
    RECT 1032.7 0.0 1034.58 0.42 ;
    RECT 1019.835 0.0 1032.28 0.42 ;
    RECT 1018.2 0.0 1019.415 0.42 ;
    RECT 1015.9 0.0 1017.78 0.42 ;
    RECT 1003.035 0.0 1015.48 0.42 ;
    RECT 1001.4 0.0 1002.615 0.42 ;
    RECT 999.1 0.0 1000.98 0.42 ;
    RECT 986.235 0.0 998.68 0.42 ;
    RECT 984.6 0.0 985.815 0.42 ;
    RECT 982.3 0.0 984.18 0.42 ;
    RECT 969.435 0.0 981.88 0.42 ;
    RECT 967.8 0.0 969.015 0.42 ;
    RECT 965.5 0.0 967.38 0.42 ;
    RECT 952.635 0.0 965.08 0.42 ;
    RECT 951.0 0.0 952.215 0.42 ;
    RECT 948.7 0.0 950.58 0.42 ;
    RECT 870.835 0.0 948.28 0.42 ;
    RECT 869.2 0.0 870.415 0.42 ;
    RECT 866.9 0.0 868.78 0.42 ;
    RECT 854.035 0.0 866.48 0.42 ;
    RECT 852.4 0.0 853.615 0.42 ;
    RECT 850.1 0.0 851.98 0.42 ;
    RECT 837.235 0.0 849.68 0.42 ;
    RECT 835.6 0.0 836.815 0.42 ;
    RECT 833.3 0.0 835.18 0.42 ;
    RECT 820.435 0.0 832.88 0.42 ;
    RECT 818.8 0.0 820.015 0.42 ;
    RECT 816.5 0.0 818.38 0.42 ;
    RECT 803.635 0.0 816.08 0.42 ;
    RECT 802.0 0.0 803.215 0.42 ;
    RECT 799.7 0.0 801.58 0.42 ;
    RECT 786.835 0.0 799.28 0.42 ;
    RECT 785.2 0.0 786.415 0.42 ;
    RECT 782.9 0.0 784.78 0.42 ;
    RECT 770.035 0.0 782.48 0.42 ;
    RECT 768.4 0.0 769.615 0.42 ;
    RECT 766.1 0.0 767.98 0.42 ;
    RECT 753.235 0.0 765.68 0.42 ;
    RECT 751.6 0.0 752.815 0.42 ;
    RECT 749.3 0.0 751.18 0.42 ;
    RECT 736.435 0.0 748.88 0.42 ;
    RECT 734.8 0.0 736.015 0.42 ;
    RECT 732.5 0.0 734.38 0.42 ;
    RECT 719.635 0.0 732.08 0.42 ;
    RECT 718.0 0.0 719.215 0.42 ;
    RECT 715.7 0.0 717.58 0.42 ;
    RECT 702.835 0.0 715.28 0.42 ;
    RECT 701.2 0.0 702.415 0.42 ;
    RECT 698.9 0.0 700.78 0.42 ;
    RECT 686.035 0.0 698.48 0.42 ;
    RECT 684.4 0.0 685.615 0.42 ;
    RECT 682.1 0.0 683.98 0.42 ;
    RECT 669.18 0.0 681.68 0.42 ;
    RECT 667.59 0.0 668.76 0.42 ;
    RECT 666.23 0.0 667.17 0.42 ;
    RECT 665.205 0.0 665.81 0.42 ;
    RECT 653.62 0.0 664.785 0.42 ;
    RECT 652.435 0.0 653.2 0.42 ;
    RECT 650.785 0.0 652.015 0.42 ;
    RECT 648.705 0.0 650.365 0.42 ;
    RECT 643.81 0.0 646.565 0.42 ;
    RECT 641.365 0.0 643.39 0.42 ;
    RECT 637.62 0.0 640.945 0.42 ;
    RECT 636.865 0.0 637.2 0.42 ;
    RECT 635.585 0.0 636.115 0.42 ;
    RECT 633.965 0.0 635.165 0.42 ;
    RECT 632.65 0.0 633.545 0.42 ;
    RECT 631.64 0.0 632.23 0.42 ;
    RECT 626.165 0.0 630.335 0.42 ;
    RECT 625.18 0.0 625.745 0.42 ;
    RECT 622.58 0.0 623.395 0.42 ;
    RECT 618.84 0.0 622.16 0.42 ;
    RECT 617.165 0.0 618.42 0.42 ;
    RECT 614.84 0.0 616.745 0.42 ;
    RECT 613.385 0.0 614.42 0.42 ;
    RECT 612.69 0.0 612.965 0.42 ;
    RECT 607.135 0.0 611.85 0.42 ;
    RECT 602.835 0.0 606.715 0.42 ;
    RECT 598.26 0.0 602.415 0.42 ;
    RECT 597.075 0.0 597.46 0.42 ;
    RECT 595.345 0.0 596.655 0.42 ;
    RECT 593.545 0.0 594.925 0.42 ;
    RECT 591.52 0.0 592.175 0.42 ;
    RECT 590.545 0.0 591.09 0.42 ;
    RECT 587.64 0.0 590.125 0.42 ;
    RECT 585.855 0.0 586.86 0.42 ;
    RECT 581.21 0.0 585.435 0.42 ;
    RECT 580.1 0.0 580.405 0.42 ;
    RECT 578.755 0.0 579.68 0.42 ;
    RECT 576.235 0.0 578.335 0.42 ;
    RECT 574.93 0.0 575.33 0.42 ;
    RECT 573.65 0.0 574.19 0.42 ;
    RECT 566.47 0.0 573.23 0.42 ;
    RECT 564.985 0.0 566.05 0.42 ;
    RECT 562.125 0.0 563.205 0.42 ;
    RECT 561.565 0.0 561.705 0.42 ;
    RECT 559.505 0.0 561.145 0.42 ;
    RECT 558.035 0.0 558.395 0.42 ;
    RECT 556.75 0.0 557.615 0.42 ;
    RECT 548.285 0.0 556.33 0.42 ;
    RECT 547.38 0.0 547.865 0.42 ;
    RECT 546.4 0.0 546.96 0.42 ;
    RECT 544.945 0.0 545.98 0.42 ;
    RECT 543.845 0.0 544.525 0.42 ;
    RECT 542.705 0.0 543.425 0.42 ;
    RECT 541.035 0.0 541.555 0.42 ;
    RECT 539.86 0.0 540.615 0.42 ;
    RECT 539.105 0.0 539.44 0.42 ;
    RECT 528.15 0.0 538.685 0.42 ;
    RECT 525.85 0.0 527.73 0.42 ;
    RECT 524.215 0.0 525.43 0.42 ;
    RECT 511.35 0.0 523.795 0.42 ;
    RECT 509.05 0.0 510.93 0.42 ;
    RECT 507.415 0.0 508.63 0.42 ;
    RECT 494.55 0.0 506.995 0.42 ;
    RECT 492.25 0.0 494.13 0.42 ;
    RECT 490.615 0.0 491.83 0.42 ;
    RECT 477.75 0.0 490.195 0.42 ;
    RECT 475.45 0.0 477.33 0.42 ;
    RECT 473.815 0.0 475.03 0.42 ;
    RECT 460.95 0.0 473.395 0.42 ;
    RECT 458.65 0.0 460.53 0.42 ;
    RECT 457.015 0.0 458.23 0.42 ;
    RECT 444.15 0.0 456.595 0.42 ;
    RECT 441.85 0.0 443.73 0.42 ;
    RECT 440.215 0.0 441.43 0.42 ;
    RECT 427.35 0.0 439.795 0.42 ;
    RECT 425.05 0.0 426.93 0.42 ;
    RECT 423.415 0.0 424.63 0.42 ;
    RECT 410.55 0.0 422.995 0.42 ;
    RECT 408.25 0.0 410.13 0.42 ;
    RECT 406.615 0.0 407.83 0.42 ;
    RECT 393.75 0.0 406.195 0.42 ;
    RECT 391.45 0.0 393.33 0.42 ;
    RECT 389.815 0.0 391.03 0.42 ;
    RECT 376.95 0.0 389.395 0.42 ;
    RECT 374.65 0.0 376.53 0.42 ;
    RECT 373.015 0.0 374.23 0.42 ;
    RECT 360.15 0.0 372.595 0.42 ;
    RECT 357.85 0.0 359.73 0.42 ;
    RECT 356.215 0.0 357.43 0.42 ;
    RECT 343.35 0.0 355.795 0.42 ;
    RECT 341.05 0.0 342.93 0.42 ;
    RECT 339.415 0.0 340.63 0.42 ;
    RECT 261.55 0.0 338.995 0.42 ;
    RECT 259.25 0.0 261.13 0.42 ;
    RECT 257.615 0.0 258.83 0.42 ;
    RECT 244.75 0.0 257.195 0.42 ;
    RECT 242.45 0.0 244.33 0.42 ;
    RECT 240.815 0.0 242.03 0.42 ;
    RECT 227.95 0.0 240.395 0.42 ;
    RECT 225.65 0.0 227.53 0.42 ;
    RECT 224.015 0.0 225.23 0.42 ;
    RECT 211.15 0.0 223.595 0.42 ;
    RECT 208.85 0.0 210.73 0.42 ;
    RECT 207.215 0.0 208.43 0.42 ;
    RECT 194.35 0.0 206.795 0.42 ;
    RECT 192.05 0.0 193.93 0.42 ;
    RECT 190.415 0.0 191.63 0.42 ;
    RECT 177.55 0.0 189.995 0.42 ;
    RECT 175.25 0.0 177.13 0.42 ;
    RECT 173.615 0.0 174.83 0.42 ;
    RECT 160.75 0.0 173.195 0.42 ;
    RECT 158.45 0.0 160.33 0.42 ;
    RECT 156.815 0.0 158.03 0.42 ;
    RECT 143.95 0.0 156.395 0.42 ;
    RECT 141.65 0.0 143.53 0.42 ;
    RECT 140.015 0.0 141.23 0.42 ;
    RECT 127.15 0.0 139.595 0.42 ;
    RECT 124.85 0.0 126.73 0.42 ;
    RECT 123.215 0.0 124.43 0.42 ;
    RECT 110.35 0.0 122.795 0.42 ;
    RECT 108.05 0.0 109.93 0.42 ;
    RECT 106.415 0.0 107.63 0.42 ;
    RECT 93.55 0.0 105.995 0.42 ;
    RECT 91.25 0.0 93.13 0.42 ;
    RECT 89.615 0.0 90.83 0.42 ;
    RECT 76.75 0.0 89.195 0.42 ;
    RECT 74.45 0.0 76.33 0.42 ;
    RECT 72.815 0.0 74.03 0.42 ;
    RECT 59.95 0.0 72.395 0.42 ;
    RECT 57.65 0.0 59.53 0.42 ;
    RECT 56.015 0.0 57.23 0.42 ;
    RECT 43.15 0.0 55.595 0.42 ;
    RECT 40.85 0.0 42.73 0.42 ;
    RECT 39.215 0.0 40.43 0.42 ;
    RECT 26.35 0.0 38.795 0.42 ;
    RECT 24.05 0.0 25.93 0.42 ;
    RECT 22.415 0.0 23.63 0.42 ;
    RECT 9.55 0.0 21.995 0.42 ;
    RECT 7.25 0.0 9.13 0.42 ;
    RECT 5.615 0.0 6.83 0.42 ;
    RECT 1.09 0.0 5.195 0.42 ;
    RECT 0.0 0.0 0.67 0.42 ;
    RECT 0.0 0.42 1209.83 315.365 ;
    LAYER VIA1 ;
    RECT 0.0 0.0 1209.83 315.365 ;
    LAYER M2 DESIGNRULEWIDTH 0.1 ;
    RECT 1209.16 0.0 1209.83 0.42 ;
    RECT 1204.635 0.0 1208.74 0.42 ;
    RECT 1203.0 0.0 1204.215 0.42 ;
    RECT 1200.7 0.0 1202.58 0.42 ;
    RECT 1187.835 0.0 1200.28 0.42 ;
    RECT 1186.2 0.0 1187.415 0.42 ;
    RECT 1183.9 0.0 1185.78 0.42 ;
    RECT 1171.035 0.0 1183.48 0.42 ;
    RECT 1169.4 0.0 1170.615 0.42 ;
    RECT 1167.1 0.0 1168.98 0.42 ;
    RECT 1154.235 0.0 1166.68 0.42 ;
    RECT 1152.6 0.0 1153.815 0.42 ;
    RECT 1150.3 0.0 1152.18 0.42 ;
    RECT 1137.435 0.0 1149.88 0.42 ;
    RECT 1135.8 0.0 1137.015 0.42 ;
    RECT 1133.5 0.0 1135.38 0.42 ;
    RECT 1120.635 0.0 1133.08 0.42 ;
    RECT 1119.0 0.0 1120.215 0.42 ;
    RECT 1116.7 0.0 1118.58 0.42 ;
    RECT 1103.835 0.0 1116.28 0.42 ;
    RECT 1102.2 0.0 1103.415 0.42 ;
    RECT 1099.9 0.0 1101.78 0.42 ;
    RECT 1087.035 0.0 1099.48 0.42 ;
    RECT 1085.4 0.0 1086.615 0.42 ;
    RECT 1083.1 0.0 1084.98 0.42 ;
    RECT 1070.235 0.0 1082.68 0.42 ;
    RECT 1068.6 0.0 1069.815 0.42 ;
    RECT 1066.3 0.0 1068.18 0.42 ;
    RECT 1053.435 0.0 1065.88 0.42 ;
    RECT 1051.8 0.0 1053.015 0.42 ;
    RECT 1049.5 0.0 1051.38 0.42 ;
    RECT 1036.635 0.0 1049.08 0.42 ;
    RECT 1035.0 0.0 1036.215 0.42 ;
    RECT 1032.7 0.0 1034.58 0.42 ;
    RECT 1019.835 0.0 1032.28 0.42 ;
    RECT 1018.2 0.0 1019.415 0.42 ;
    RECT 1015.9 0.0 1017.78 0.42 ;
    RECT 1003.035 0.0 1015.48 0.42 ;
    RECT 1001.4 0.0 1002.615 0.42 ;
    RECT 999.1 0.0 1000.98 0.42 ;
    RECT 986.235 0.0 998.68 0.42 ;
    RECT 984.6 0.0 985.815 0.42 ;
    RECT 982.3 0.0 984.18 0.42 ;
    RECT 969.435 0.0 981.88 0.42 ;
    RECT 967.8 0.0 969.015 0.42 ;
    RECT 965.5 0.0 967.38 0.42 ;
    RECT 952.635 0.0 965.08 0.42 ;
    RECT 951.0 0.0 952.215 0.42 ;
    RECT 948.7 0.0 950.58 0.42 ;
    RECT 870.835 0.0 948.28 0.42 ;
    RECT 869.2 0.0 870.415 0.42 ;
    RECT 866.9 0.0 868.78 0.42 ;
    RECT 854.035 0.0 866.48 0.42 ;
    RECT 852.4 0.0 853.615 0.42 ;
    RECT 850.1 0.0 851.98 0.42 ;
    RECT 837.235 0.0 849.68 0.42 ;
    RECT 835.6 0.0 836.815 0.42 ;
    RECT 833.3 0.0 835.18 0.42 ;
    RECT 820.435 0.0 832.88 0.42 ;
    RECT 818.8 0.0 820.015 0.42 ;
    RECT 816.5 0.0 818.38 0.42 ;
    RECT 803.635 0.0 816.08 0.42 ;
    RECT 802.0 0.0 803.215 0.42 ;
    RECT 799.7 0.0 801.58 0.42 ;
    RECT 786.835 0.0 799.28 0.42 ;
    RECT 785.2 0.0 786.415 0.42 ;
    RECT 782.9 0.0 784.78 0.42 ;
    RECT 770.035 0.0 782.48 0.42 ;
    RECT 768.4 0.0 769.615 0.42 ;
    RECT 766.1 0.0 767.98 0.42 ;
    RECT 753.235 0.0 765.68 0.42 ;
    RECT 751.6 0.0 752.815 0.42 ;
    RECT 749.3 0.0 751.18 0.42 ;
    RECT 736.435 0.0 748.88 0.42 ;
    RECT 734.8 0.0 736.015 0.42 ;
    RECT 732.5 0.0 734.38 0.42 ;
    RECT 719.635 0.0 732.08 0.42 ;
    RECT 718.0 0.0 719.215 0.42 ;
    RECT 715.7 0.0 717.58 0.42 ;
    RECT 702.835 0.0 715.28 0.42 ;
    RECT 701.2 0.0 702.415 0.42 ;
    RECT 698.9 0.0 700.78 0.42 ;
    RECT 686.035 0.0 698.48 0.42 ;
    RECT 684.4 0.0 685.615 0.42 ;
    RECT 682.1 0.0 683.98 0.42 ;
    RECT 669.18 0.0 681.68 0.42 ;
    RECT 667.59 0.0 668.76 0.42 ;
    RECT 666.23 0.0 667.17 0.42 ;
    RECT 665.205 0.0 665.81 0.42 ;
    RECT 653.62 0.0 664.785 0.42 ;
    RECT 652.435 0.0 653.2 0.42 ;
    RECT 650.785 0.0 652.015 0.42 ;
    RECT 648.705 0.0 650.365 0.42 ;
    RECT 643.81 0.0 646.565 0.42 ;
    RECT 641.365 0.0 643.39 0.42 ;
    RECT 637.62 0.0 640.945 0.42 ;
    RECT 636.865 0.0 637.2 0.42 ;
    RECT 635.585 0.0 636.115 0.42 ;
    RECT 633.965 0.0 635.165 0.42 ;
    RECT 632.65 0.0 633.545 0.42 ;
    RECT 631.64 0.0 632.23 0.42 ;
    RECT 626.165 0.0 630.335 0.42 ;
    RECT 625.18 0.0 625.745 0.42 ;
    RECT 622.58 0.0 623.395 0.42 ;
    RECT 618.84 0.0 622.16 0.42 ;
    RECT 617.165 0.0 618.42 0.42 ;
    RECT 614.84 0.0 616.745 0.42 ;
    RECT 613.385 0.0 614.42 0.42 ;
    RECT 612.69 0.0 612.965 0.42 ;
    RECT 607.135 0.0 611.85 0.42 ;
    RECT 602.835 0.0 606.715 0.42 ;
    RECT 598.26 0.0 602.415 0.42 ;
    RECT 597.075 0.0 597.46 0.42 ;
    RECT 595.345 0.0 596.655 0.42 ;
    RECT 593.545 0.0 594.925 0.42 ;
    RECT 591.52 0.0 592.175 0.42 ;
    RECT 590.545 0.0 591.09 0.42 ;
    RECT 587.64 0.0 590.125 0.42 ;
    RECT 585.855 0.0 586.86 0.42 ;
    RECT 581.21 0.0 585.435 0.42 ;
    RECT 580.1 0.0 580.405 0.42 ;
    RECT 578.755 0.0 579.68 0.42 ;
    RECT 576.235 0.0 578.225 0.42 ;
    RECT 574.93 0.0 575.33 0.42 ;
    RECT 573.65 0.0 574.19 0.42 ;
    RECT 566.47 0.0 573.23 0.42 ;
    RECT 564.985 0.0 566.05 0.42 ;
    RECT 562.125 0.0 563.205 0.42 ;
    RECT 561.565 0.0 561.705 0.42 ;
    RECT 559.505 0.0 561.145 0.42 ;
    RECT 558.035 0.0 558.395 0.42 ;
    RECT 556.75 0.0 557.615 0.42 ;
    RECT 548.285 0.0 556.33 0.42 ;
    RECT 547.38 0.0 547.865 0.42 ;
    RECT 546.4 0.0 546.96 0.42 ;
    RECT 544.945 0.0 545.98 0.42 ;
    RECT 543.845 0.0 544.525 0.42 ;
    RECT 542.705 0.0 543.425 0.42 ;
    RECT 541.035 0.0 541.555 0.42 ;
    RECT 539.86 0.0 540.615 0.42 ;
    RECT 539.105 0.0 539.44 0.42 ;
    RECT 528.15 0.0 538.685 0.42 ;
    RECT 525.85 0.0 527.73 0.42 ;
    RECT 524.215 0.0 525.43 0.42 ;
    RECT 511.35 0.0 523.795 0.42 ;
    RECT 509.05 0.0 510.93 0.42 ;
    RECT 507.415 0.0 508.63 0.42 ;
    RECT 494.55 0.0 506.995 0.42 ;
    RECT 492.25 0.0 494.13 0.42 ;
    RECT 490.615 0.0 491.83 0.42 ;
    RECT 477.75 0.0 490.195 0.42 ;
    RECT 475.45 0.0 477.33 0.42 ;
    RECT 473.815 0.0 475.03 0.42 ;
    RECT 460.95 0.0 473.395 0.42 ;
    RECT 458.65 0.0 460.53 0.42 ;
    RECT 457.015 0.0 458.23 0.42 ;
    RECT 444.15 0.0 456.595 0.42 ;
    RECT 441.85 0.0 443.73 0.42 ;
    RECT 440.215 0.0 441.43 0.42 ;
    RECT 427.35 0.0 439.795 0.42 ;
    RECT 425.05 0.0 426.93 0.42 ;
    RECT 423.415 0.0 424.63 0.42 ;
    RECT 410.55 0.0 422.995 0.42 ;
    RECT 408.25 0.0 410.13 0.42 ;
    RECT 406.615 0.0 407.83 0.42 ;
    RECT 393.75 0.0 406.195 0.42 ;
    RECT 391.45 0.0 393.33 0.42 ;
    RECT 389.815 0.0 391.03 0.42 ;
    RECT 376.95 0.0 389.395 0.42 ;
    RECT 374.65 0.0 376.53 0.42 ;
    RECT 373.015 0.0 374.23 0.42 ;
    RECT 360.15 0.0 372.595 0.42 ;
    RECT 357.85 0.0 359.73 0.42 ;
    RECT 356.215 0.0 357.43 0.42 ;
    RECT 343.35 0.0 355.795 0.42 ;
    RECT 341.05 0.0 342.93 0.42 ;
    RECT 339.415 0.0 340.63 0.42 ;
    RECT 261.55 0.0 338.995 0.42 ;
    RECT 259.25 0.0 261.13 0.42 ;
    RECT 257.615 0.0 258.83 0.42 ;
    RECT 244.75 0.0 257.195 0.42 ;
    RECT 242.45 0.0 244.33 0.42 ;
    RECT 240.815 0.0 242.03 0.42 ;
    RECT 227.95 0.0 240.395 0.42 ;
    RECT 225.65 0.0 227.53 0.42 ;
    RECT 224.015 0.0 225.23 0.42 ;
    RECT 211.15 0.0 223.595 0.42 ;
    RECT 208.85 0.0 210.73 0.42 ;
    RECT 207.215 0.0 208.43 0.42 ;
    RECT 194.35 0.0 206.795 0.42 ;
    RECT 192.05 0.0 193.93 0.42 ;
    RECT 190.415 0.0 191.63 0.42 ;
    RECT 177.55 0.0 189.995 0.42 ;
    RECT 175.25 0.0 177.13 0.42 ;
    RECT 173.615 0.0 174.83 0.42 ;
    RECT 160.75 0.0 173.195 0.42 ;
    RECT 158.45 0.0 160.33 0.42 ;
    RECT 156.815 0.0 158.03 0.42 ;
    RECT 143.95 0.0 156.395 0.42 ;
    RECT 141.65 0.0 143.53 0.42 ;
    RECT 140.015 0.0 141.23 0.42 ;
    RECT 127.15 0.0 139.595 0.42 ;
    RECT 124.85 0.0 126.73 0.42 ;
    RECT 123.215 0.0 124.43 0.42 ;
    RECT 110.35 0.0 122.795 0.42 ;
    RECT 108.05 0.0 109.93 0.42 ;
    RECT 106.415 0.0 107.63 0.42 ;
    RECT 93.55 0.0 105.995 0.42 ;
    RECT 91.25 0.0 93.13 0.42 ;
    RECT 89.615 0.0 90.83 0.42 ;
    RECT 76.75 0.0 89.195 0.42 ;
    RECT 74.45 0.0 76.33 0.42 ;
    RECT 72.815 0.0 74.03 0.42 ;
    RECT 59.95 0.0 72.395 0.42 ;
    RECT 57.65 0.0 59.53 0.42 ;
    RECT 56.015 0.0 57.23 0.42 ;
    RECT 43.15 0.0 55.595 0.42 ;
    RECT 40.85 0.0 42.73 0.42 ;
    RECT 39.215 0.0 40.43 0.42 ;
    RECT 26.35 0.0 38.795 0.42 ;
    RECT 24.05 0.0 25.93 0.42 ;
    RECT 22.415 0.0 23.63 0.42 ;
    RECT 9.55 0.0 21.995 0.42 ;
    RECT 7.25 0.0 9.13 0.42 ;
    RECT 5.615 0.0 6.83 0.42 ;
    RECT 1.09 0.0 5.195 0.42 ;
    RECT 0.0 0.0 0.67 0.42 ;
    RECT 0.0 0.42 1209.83 315.365 ;
    LAYER VIA2 ;
    RECT 0.0 0.0 1209.83 315.365 ;
    LAYER M3 DESIGNRULEWIDTH 0.1 ;
    RECT 1209.16 0.0 1209.83 0.42 ;
    RECT 1204.635 0.0 1208.74 0.42 ;
    RECT 1203.0 0.0 1204.215 0.42 ;
    RECT 1200.7 0.0 1202.58 0.42 ;
    RECT 1187.835 0.0 1200.28 0.42 ;
    RECT 1186.2 0.0 1187.415 0.42 ;
    RECT 1183.9 0.0 1185.78 0.42 ;
    RECT 1171.035 0.0 1183.48 0.42 ;
    RECT 1169.4 0.0 1170.615 0.42 ;
    RECT 1167.1 0.0 1168.98 0.42 ;
    RECT 1154.235 0.0 1166.68 0.42 ;
    RECT 1152.6 0.0 1153.815 0.42 ;
    RECT 1150.3 0.0 1152.18 0.42 ;
    RECT 1137.435 0.0 1149.88 0.42 ;
    RECT 1135.8 0.0 1137.015 0.42 ;
    RECT 1133.5 0.0 1135.38 0.42 ;
    RECT 1120.635 0.0 1133.08 0.42 ;
    RECT 1119.0 0.0 1120.215 0.42 ;
    RECT 1116.7 0.0 1118.58 0.42 ;
    RECT 1103.835 0.0 1116.28 0.42 ;
    RECT 1102.2 0.0 1103.415 0.42 ;
    RECT 1099.9 0.0 1101.78 0.42 ;
    RECT 1087.035 0.0 1099.48 0.42 ;
    RECT 1085.4 0.0 1086.615 0.42 ;
    RECT 1083.1 0.0 1084.98 0.42 ;
    RECT 1070.235 0.0 1082.68 0.42 ;
    RECT 1068.6 0.0 1069.815 0.42 ;
    RECT 1066.3 0.0 1068.18 0.42 ;
    RECT 1053.435 0.0 1065.88 0.42 ;
    RECT 1051.8 0.0 1053.015 0.42 ;
    RECT 1049.5 0.0 1051.38 0.42 ;
    RECT 1036.635 0.0 1049.08 0.42 ;
    RECT 1035.0 0.0 1036.215 0.42 ;
    RECT 1032.7 0.0 1034.58 0.42 ;
    RECT 1019.835 0.0 1032.28 0.42 ;
    RECT 1018.2 0.0 1019.415 0.42 ;
    RECT 1015.9 0.0 1017.78 0.42 ;
    RECT 1003.035 0.0 1015.48 0.42 ;
    RECT 1001.4 0.0 1002.615 0.42 ;
    RECT 999.1 0.0 1000.98 0.42 ;
    RECT 986.235 0.0 998.68 0.42 ;
    RECT 984.6 0.0 985.815 0.42 ;
    RECT 982.3 0.0 984.18 0.42 ;
    RECT 969.435 0.0 981.88 0.42 ;
    RECT 967.8 0.0 969.015 0.42 ;
    RECT 965.5 0.0 967.38 0.42 ;
    RECT 952.635 0.0 965.08 0.42 ;
    RECT 951.0 0.0 952.215 0.42 ;
    RECT 948.7 0.0 950.58 0.42 ;
    RECT 870.835 0.0 948.28 0.42 ;
    RECT 869.2 0.0 870.415 0.42 ;
    RECT 866.9 0.0 868.78 0.42 ;
    RECT 854.035 0.0 866.48 0.42 ;
    RECT 852.4 0.0 853.615 0.42 ;
    RECT 850.1 0.0 851.98 0.42 ;
    RECT 837.235 0.0 849.68 0.42 ;
    RECT 835.6 0.0 836.815 0.42 ;
    RECT 833.3 0.0 835.18 0.42 ;
    RECT 820.435 0.0 832.88 0.42 ;
    RECT 818.8 0.0 820.015 0.42 ;
    RECT 816.5 0.0 818.38 0.42 ;
    RECT 803.635 0.0 816.08 0.42 ;
    RECT 802.0 0.0 803.215 0.42 ;
    RECT 799.7 0.0 801.58 0.42 ;
    RECT 786.835 0.0 799.28 0.42 ;
    RECT 785.2 0.0 786.415 0.42 ;
    RECT 782.9 0.0 784.78 0.42 ;
    RECT 770.035 0.0 782.48 0.42 ;
    RECT 768.4 0.0 769.615 0.42 ;
    RECT 766.1 0.0 767.98 0.42 ;
    RECT 753.235 0.0 765.68 0.42 ;
    RECT 751.6 0.0 752.815 0.42 ;
    RECT 749.3 0.0 751.18 0.42 ;
    RECT 736.435 0.0 748.88 0.42 ;
    RECT 734.8 0.0 736.015 0.42 ;
    RECT 732.5 0.0 734.38 0.42 ;
    RECT 719.635 0.0 732.08 0.42 ;
    RECT 718.0 0.0 719.215 0.42 ;
    RECT 715.7 0.0 717.58 0.42 ;
    RECT 702.835 0.0 715.28 0.42 ;
    RECT 701.2 0.0 702.415 0.42 ;
    RECT 698.9 0.0 700.78 0.42 ;
    RECT 686.035 0.0 698.48 0.42 ;
    RECT 684.4 0.0 685.615 0.42 ;
    RECT 682.1 0.0 683.98 0.42 ;
    RECT 669.18 0.0 681.68 0.42 ;
    RECT 667.59 0.0 668.76 0.42 ;
    RECT 666.23 0.0 667.17 0.42 ;
    RECT 665.205 0.0 665.81 0.42 ;
    RECT 653.62 0.0 664.785 0.42 ;
    RECT 652.435 0.0 653.2 0.42 ;
    RECT 650.785 0.0 652.015 0.42 ;
    RECT 648.705 0.0 650.365 0.42 ;
    RECT 641.365 0.0 646.565 0.42 ;
    RECT 637.62 0.0 640.945 0.42 ;
    RECT 636.535 0.0 637.2 0.42 ;
    RECT 635.585 0.0 636.115 0.42 ;
    RECT 633.965 0.0 635.165 0.42 ;
    RECT 632.65 0.0 633.545 0.42 ;
    RECT 631.64 0.0 632.23 0.42 ;
    RECT 626.165 0.0 630.335 0.42 ;
    RECT 625.18 0.0 625.745 0.42 ;
    RECT 622.58 0.0 623.395 0.42 ;
    RECT 618.84 0.0 622.16 0.42 ;
    RECT 617.165 0.0 618.42 0.42 ;
    RECT 614.84 0.0 616.745 0.42 ;
    RECT 613.385 0.0 614.42 0.42 ;
    RECT 612.69 0.0 612.965 0.42 ;
    RECT 607.135 0.0 612.27 0.42 ;
    RECT 602.835 0.0 606.715 0.42 ;
    RECT 597.88 0.0 602.415 0.42 ;
    RECT 597.075 0.0 597.46 0.42 ;
    RECT 595.345 0.0 596.655 0.42 ;
    RECT 593.545 0.0 594.925 0.42 ;
    RECT 591.52 0.0 592.175 0.42 ;
    RECT 590.545 0.0 591.09 0.42 ;
    RECT 587.64 0.0 590.125 0.42 ;
    RECT 585.855 0.0 586.86 0.42 ;
    RECT 581.21 0.0 585.435 0.42 ;
    RECT 580.1 0.0 580.405 0.42 ;
    RECT 578.755 0.0 579.68 0.42 ;
    RECT 576.235 0.0 578.335 0.42 ;
    RECT 574.93 0.0 575.33 0.42 ;
    RECT 573.65 0.0 574.19 0.42 ;
    RECT 566.47 0.0 573.23 0.42 ;
    RECT 564.12 0.0 566.05 0.42 ;
    RECT 562.125 0.0 563.205 0.42 ;
    RECT 561.565 0.0 561.705 0.42 ;
    RECT 559.505 0.0 561.145 0.42 ;
    RECT 558.035 0.0 558.395 0.42 ;
    RECT 556.75 0.0 557.615 0.42 ;
    RECT 548.285 0.0 556.33 0.42 ;
    RECT 547.38 0.0 547.865 0.42 ;
    RECT 546.4 0.0 546.96 0.42 ;
    RECT 544.945 0.0 545.98 0.42 ;
    RECT 543.845 0.0 544.525 0.42 ;
    RECT 542.705 0.0 543.425 0.42 ;
    RECT 541.035 0.0 541.555 0.42 ;
    RECT 539.86 0.0 540.615 0.42 ;
    RECT 539.105 0.0 539.44 0.42 ;
    RECT 528.15 0.0 538.685 0.42 ;
    RECT 525.85 0.0 527.73 0.42 ;
    RECT 524.215 0.0 525.43 0.42 ;
    RECT 511.35 0.0 523.795 0.42 ;
    RECT 509.05 0.0 510.93 0.42 ;
    RECT 507.415 0.0 508.63 0.42 ;
    RECT 494.55 0.0 506.995 0.42 ;
    RECT 492.25 0.0 494.13 0.42 ;
    RECT 490.615 0.0 491.83 0.42 ;
    RECT 477.75 0.0 490.195 0.42 ;
    RECT 475.45 0.0 477.33 0.42 ;
    RECT 473.815 0.0 475.03 0.42 ;
    RECT 460.95 0.0 473.395 0.42 ;
    RECT 458.65 0.0 460.53 0.42 ;
    RECT 457.015 0.0 458.23 0.42 ;
    RECT 444.15 0.0 456.595 0.42 ;
    RECT 441.85 0.0 443.73 0.42 ;
    RECT 440.215 0.0 441.43 0.42 ;
    RECT 427.35 0.0 439.795 0.42 ;
    RECT 425.05 0.0 426.93 0.42 ;
    RECT 423.415 0.0 424.63 0.42 ;
    RECT 410.55 0.0 422.995 0.42 ;
    RECT 408.25 0.0 410.13 0.42 ;
    RECT 406.615 0.0 407.83 0.42 ;
    RECT 393.75 0.0 406.195 0.42 ;
    RECT 391.45 0.0 393.33 0.42 ;
    RECT 389.815 0.0 391.03 0.42 ;
    RECT 376.95 0.0 389.395 0.42 ;
    RECT 374.65 0.0 376.53 0.42 ;
    RECT 373.015 0.0 374.23 0.42 ;
    RECT 360.15 0.0 372.595 0.42 ;
    RECT 357.85 0.0 359.73 0.42 ;
    RECT 356.215 0.0 357.43 0.42 ;
    RECT 343.35 0.0 355.795 0.42 ;
    RECT 341.05 0.0 342.93 0.42 ;
    RECT 339.415 0.0 340.63 0.42 ;
    RECT 261.55 0.0 338.995 0.42 ;
    RECT 259.25 0.0 261.13 0.42 ;
    RECT 257.615 0.0 258.83 0.42 ;
    RECT 244.75 0.0 257.195 0.42 ;
    RECT 242.45 0.0 244.33 0.42 ;
    RECT 240.815 0.0 242.03 0.42 ;
    RECT 227.95 0.0 240.395 0.42 ;
    RECT 225.65 0.0 227.53 0.42 ;
    RECT 224.015 0.0 225.23 0.42 ;
    RECT 211.15 0.0 223.595 0.42 ;
    RECT 208.85 0.0 210.73 0.42 ;
    RECT 207.215 0.0 208.43 0.42 ;
    RECT 194.35 0.0 206.795 0.42 ;
    RECT 192.05 0.0 193.93 0.42 ;
    RECT 190.415 0.0 191.63 0.42 ;
    RECT 177.55 0.0 189.995 0.42 ;
    RECT 175.25 0.0 177.13 0.42 ;
    RECT 173.615 0.0 174.83 0.42 ;
    RECT 160.75 0.0 173.195 0.42 ;
    RECT 158.45 0.0 160.33 0.42 ;
    RECT 156.815 0.0 158.03 0.42 ;
    RECT 143.95 0.0 156.395 0.42 ;
    RECT 141.65 0.0 143.53 0.42 ;
    RECT 140.015 0.0 141.23 0.42 ;
    RECT 127.15 0.0 139.595 0.42 ;
    RECT 124.85 0.0 126.73 0.42 ;
    RECT 123.215 0.0 124.43 0.42 ;
    RECT 110.35 0.0 122.795 0.42 ;
    RECT 108.05 0.0 109.93 0.42 ;
    RECT 106.415 0.0 107.63 0.42 ;
    RECT 93.55 0.0 105.995 0.42 ;
    RECT 91.25 0.0 93.13 0.42 ;
    RECT 89.615 0.0 90.83 0.42 ;
    RECT 76.75 0.0 89.195 0.42 ;
    RECT 74.45 0.0 76.33 0.42 ;
    RECT 72.815 0.0 74.03 0.42 ;
    RECT 59.95 0.0 72.395 0.42 ;
    RECT 57.65 0.0 59.53 0.42 ;
    RECT 56.015 0.0 57.23 0.42 ;
    RECT 43.15 0.0 55.595 0.42 ;
    RECT 40.85 0.0 42.73 0.42 ;
    RECT 39.215 0.0 40.43 0.42 ;
    RECT 26.35 0.0 38.795 0.42 ;
    RECT 24.05 0.0 25.93 0.42 ;
    RECT 22.415 0.0 23.63 0.42 ;
    RECT 9.55 0.0 21.995 0.42 ;
    RECT 7.25 0.0 9.13 0.42 ;
    RECT 5.615 0.0 6.83 0.42 ;
    RECT 1.09 0.0 5.195 0.42 ;
    RECT 0.0 0.0 0.67 0.42 ;
    RECT 0.0 0.42 1209.83 315.365 ;
    LAYER VIA3 ;
    RECT 0.0 0.0 1209.83 315.365 ;
    LAYER M4 DESIGNRULEWIDTH 0.1 ;
    RECT 1208.275 0.0 1208.58 0.42 ;
    RECT 1207.5 0.0 1207.695 0.42 ;
    RECT 1206.75 0.0 1206.92 0.42 ;
    RECT 1205.695 0.0 1206.17 0.42 ;
    RECT 1203.585 0.0 1205.115 0.42 ;
    RECT 1201.78 0.0 1201.955 0.42 ;
    RECT 1201.03 0.0 1201.2 0.42 ;
    RECT 1199.875 0.0 1200.45 0.42 ;
    RECT 1199.1 0.0 1199.295 0.42 ;
    RECT 1198.35 0.0 1198.52 0.42 ;
    RECT 1197.295 0.0 1197.77 0.42 ;
    RECT 1195.185 0.0 1196.715 0.42 ;
    RECT 1194.135 0.0 1194.605 0.42 ;
    RECT 1193.38 0.0 1193.555 0.42 ;
    RECT 1192.63 0.0 1192.8 0.42 ;
    RECT 1191.475 0.0 1192.05 0.42 ;
    RECT 1190.7 0.0 1190.895 0.42 ;
    RECT 1189.95 0.0 1190.12 0.42 ;
    RECT 1188.895 0.0 1189.37 0.42 ;
    RECT 1186.785 0.0 1188.315 0.42 ;
    RECT 1184.98 0.0 1185.155 0.42 ;
    RECT 1184.23 0.0 1184.4 0.42 ;
    RECT 1183.075 0.0 1183.65 0.42 ;
    RECT 1182.3 0.0 1182.495 0.42 ;
    RECT 1181.55 0.0 1181.72 0.42 ;
    RECT 1180.495 0.0 1180.97 0.42 ;
    RECT 1178.385 0.0 1179.915 0.42 ;
    RECT 1177.335 0.0 1177.805 0.42 ;
    RECT 1176.58 0.0 1176.755 0.42 ;
    RECT 1175.83 0.0 1176.0 0.42 ;
    RECT 1174.675 0.0 1175.25 0.42 ;
    RECT 1173.9 0.0 1174.095 0.42 ;
    RECT 1173.15 0.0 1173.32 0.42 ;
    RECT 1172.095 0.0 1172.57 0.42 ;
    RECT 1169.985 0.0 1171.515 0.42 ;
    RECT 1168.18 0.0 1168.355 0.42 ;
    RECT 1167.43 0.0 1167.6 0.42 ;
    RECT 1166.275 0.0 1166.85 0.42 ;
    RECT 1165.5 0.0 1165.695 0.42 ;
    RECT 1164.75 0.0 1164.92 0.42 ;
    RECT 1163.695 0.0 1164.17 0.42 ;
    RECT 1161.585 0.0 1163.115 0.42 ;
    RECT 1160.535 0.0 1161.005 0.42 ;
    RECT 1159.78 0.0 1159.955 0.42 ;
    RECT 1159.03 0.0 1159.2 0.42 ;
    RECT 1157.875 0.0 1158.45 0.42 ;
    RECT 1157.1 0.0 1157.295 0.42 ;
    RECT 1156.35 0.0 1156.52 0.42 ;
    RECT 1155.295 0.0 1155.77 0.42 ;
    RECT 1153.185 0.0 1154.715 0.42 ;
    RECT 1151.38 0.0 1151.555 0.42 ;
    RECT 1150.63 0.0 1150.8 0.42 ;
    RECT 1149.475 0.0 1150.05 0.42 ;
    RECT 1148.7 0.0 1148.895 0.42 ;
    RECT 1147.95 0.0 1148.12 0.42 ;
    RECT 1146.895 0.0 1147.37 0.42 ;
    RECT 1144.785 0.0 1146.315 0.42 ;
    RECT 1143.735 0.0 1144.205 0.42 ;
    RECT 1142.98 0.0 1143.155 0.42 ;
    RECT 1142.23 0.0 1142.4 0.42 ;
    RECT 1141.075 0.0 1141.65 0.42 ;
    RECT 1140.3 0.0 1140.495 0.42 ;
    RECT 1139.55 0.0 1139.72 0.42 ;
    RECT 1138.495 0.0 1138.97 0.42 ;
    RECT 1136.385 0.0 1137.915 0.42 ;
    RECT 1134.58 0.0 1134.755 0.42 ;
    RECT 1133.83 0.0 1134.0 0.42 ;
    RECT 1132.675 0.0 1133.25 0.42 ;
    RECT 1131.9 0.0 1132.095 0.42 ;
    RECT 1131.15 0.0 1131.32 0.42 ;
    RECT 1130.095 0.0 1130.57 0.42 ;
    RECT 1127.985 0.0 1129.515 0.42 ;
    RECT 1126.935 0.0 1127.405 0.42 ;
    RECT 1126.18 0.0 1126.355 0.42 ;
    RECT 1125.43 0.0 1125.6 0.42 ;
    RECT 1124.275 0.0 1124.85 0.42 ;
    RECT 1123.5 0.0 1123.695 0.42 ;
    RECT 1122.75 0.0 1122.92 0.42 ;
    RECT 1121.695 0.0 1122.17 0.42 ;
    RECT 1119.585 0.0 1121.115 0.42 ;
    RECT 1117.78 0.0 1117.955 0.42 ;
    RECT 1117.03 0.0 1117.2 0.42 ;
    RECT 1115.875 0.0 1116.45 0.42 ;
    RECT 1115.1 0.0 1115.295 0.42 ;
    RECT 1114.35 0.0 1114.52 0.42 ;
    RECT 1113.295 0.0 1113.77 0.42 ;
    RECT 1111.185 0.0 1112.715 0.42 ;
    RECT 1110.135 0.0 1110.605 0.42 ;
    RECT 1109.38 0.0 1109.555 0.42 ;
    RECT 1108.63 0.0 1108.8 0.42 ;
    RECT 1107.475 0.0 1108.05 0.42 ;
    RECT 1106.7 0.0 1106.895 0.42 ;
    RECT 1105.95 0.0 1106.12 0.42 ;
    RECT 1104.895 0.0 1105.37 0.42 ;
    RECT 1102.785 0.0 1104.315 0.42 ;
    RECT 1100.98 0.0 1101.155 0.42 ;
    RECT 1100.23 0.0 1100.4 0.42 ;
    RECT 1099.075 0.0 1099.65 0.42 ;
    RECT 1098.3 0.0 1098.495 0.42 ;
    RECT 1097.55 0.0 1097.72 0.42 ;
    RECT 1096.495 0.0 1096.97 0.42 ;
    RECT 1094.385 0.0 1095.915 0.42 ;
    RECT 1093.335 0.0 1093.805 0.42 ;
    RECT 1092.58 0.0 1092.755 0.42 ;
    RECT 1091.83 0.0 1092.0 0.42 ;
    RECT 1090.675 0.0 1091.25 0.42 ;
    RECT 1089.9 0.0 1090.095 0.42 ;
    RECT 1089.15 0.0 1089.32 0.42 ;
    RECT 1088.095 0.0 1088.57 0.42 ;
    RECT 1085.985 0.0 1087.515 0.42 ;
    RECT 1084.18 0.0 1084.355 0.42 ;
    RECT 1083.43 0.0 1083.6 0.42 ;
    RECT 1082.275 0.0 1082.85 0.42 ;
    RECT 1081.5 0.0 1081.695 0.42 ;
    RECT 1080.75 0.0 1080.92 0.42 ;
    RECT 1079.695 0.0 1080.17 0.42 ;
    RECT 1077.585 0.0 1079.115 0.42 ;
    RECT 1076.535 0.0 1077.005 0.42 ;
    RECT 1075.78 0.0 1075.955 0.42 ;
    RECT 1075.03 0.0 1075.2 0.42 ;
    RECT 1073.875 0.0 1074.45 0.42 ;
    RECT 1073.1 0.0 1073.295 0.42 ;
    RECT 1072.35 0.0 1072.52 0.42 ;
    RECT 1071.295 0.0 1071.77 0.42 ;
    RECT 1069.185 0.0 1070.715 0.42 ;
    RECT 1067.38 0.0 1067.555 0.42 ;
    RECT 1066.63 0.0 1066.8 0.42 ;
    RECT 1065.475 0.0 1066.05 0.42 ;
    RECT 1064.7 0.0 1064.895 0.42 ;
    RECT 1063.95 0.0 1064.12 0.42 ;
    RECT 1062.895 0.0 1063.37 0.42 ;
    RECT 1060.785 0.0 1062.315 0.42 ;
    RECT 1059.735 0.0 1060.205 0.42 ;
    RECT 1058.98 0.0 1059.155 0.42 ;
    RECT 1058.23 0.0 1058.4 0.42 ;
    RECT 1057.075 0.0 1057.65 0.42 ;
    RECT 1056.3 0.0 1056.495 0.42 ;
    RECT 1055.55 0.0 1055.72 0.42 ;
    RECT 1054.495 0.0 1054.97 0.42 ;
    RECT 1052.385 0.0 1053.915 0.42 ;
    RECT 1050.58 0.0 1050.755 0.42 ;
    RECT 1049.83 0.0 1050.0 0.42 ;
    RECT 1048.675 0.0 1049.25 0.42 ;
    RECT 1047.9 0.0 1048.095 0.42 ;
    RECT 1047.15 0.0 1047.32 0.42 ;
    RECT 1046.095 0.0 1046.57 0.42 ;
    RECT 1043.985 0.0 1045.515 0.42 ;
    RECT 1042.935 0.0 1043.405 0.42 ;
    RECT 1042.18 0.0 1042.355 0.42 ;
    RECT 1041.43 0.0 1041.6 0.42 ;
    RECT 1040.275 0.0 1040.85 0.42 ;
    RECT 1039.5 0.0 1039.695 0.42 ;
    RECT 1038.75 0.0 1038.92 0.42 ;
    RECT 1037.695 0.0 1038.17 0.42 ;
    RECT 1035.585 0.0 1037.115 0.42 ;
    RECT 1033.78 0.0 1033.955 0.42 ;
    RECT 1033.03 0.0 1033.2 0.42 ;
    RECT 1031.875 0.0 1032.45 0.42 ;
    RECT 1031.1 0.0 1031.295 0.42 ;
    RECT 1030.35 0.0 1030.52 0.42 ;
    RECT 1029.295 0.0 1029.77 0.42 ;
    RECT 1027.185 0.0 1028.715 0.42 ;
    RECT 1026.135 0.0 1026.605 0.42 ;
    RECT 1025.38 0.0 1025.555 0.42 ;
    RECT 1024.63 0.0 1024.8 0.42 ;
    RECT 1023.475 0.0 1024.05 0.42 ;
    RECT 1022.7 0.0 1022.895 0.42 ;
    RECT 1021.95 0.0 1022.12 0.42 ;
    RECT 1020.895 0.0 1021.37 0.42 ;
    RECT 1018.785 0.0 1020.315 0.42 ;
    RECT 1016.98 0.0 1017.155 0.42 ;
    RECT 1016.23 0.0 1016.4 0.42 ;
    RECT 1015.075 0.0 1015.65 0.42 ;
    RECT 1014.3 0.0 1014.495 0.42 ;
    RECT 1013.55 0.0 1013.72 0.42 ;
    RECT 1012.495 0.0 1012.97 0.42 ;
    RECT 1010.385 0.0 1011.915 0.42 ;
    RECT 1009.335 0.0 1009.805 0.42 ;
    RECT 1008.58 0.0 1008.755 0.42 ;
    RECT 1007.83 0.0 1008.0 0.42 ;
    RECT 1006.675 0.0 1007.25 0.42 ;
    RECT 1005.9 0.0 1006.095 0.42 ;
    RECT 1005.15 0.0 1005.32 0.42 ;
    RECT 1004.095 0.0 1004.57 0.42 ;
    RECT 1001.985 0.0 1003.515 0.42 ;
    RECT 1000.18 0.0 1000.355 0.42 ;
    RECT 999.43 0.0 999.6 0.42 ;
    RECT 998.275 0.0 998.85 0.42 ;
    RECT 997.5 0.0 997.695 0.42 ;
    RECT 996.75 0.0 996.92 0.42 ;
    RECT 995.695 0.0 996.17 0.42 ;
    RECT 993.585 0.0 995.115 0.42 ;
    RECT 992.535 0.0 993.005 0.42 ;
    RECT 991.78 0.0 991.955 0.42 ;
    RECT 991.03 0.0 991.2 0.42 ;
    RECT 989.875 0.0 990.45 0.42 ;
    RECT 989.1 0.0 989.295 0.42 ;
    RECT 988.35 0.0 988.52 0.42 ;
    RECT 987.295 0.0 987.77 0.42 ;
    RECT 985.185 0.0 986.715 0.42 ;
    RECT 983.38 0.0 983.555 0.42 ;
    RECT 982.63 0.0 982.8 0.42 ;
    RECT 981.475 0.0 982.05 0.42 ;
    RECT 980.7 0.0 980.895 0.42 ;
    RECT 979.95 0.0 980.12 0.42 ;
    RECT 978.895 0.0 979.37 0.42 ;
    RECT 976.785 0.0 978.315 0.42 ;
    RECT 975.735 0.0 976.205 0.42 ;
    RECT 974.98 0.0 975.155 0.42 ;
    RECT 974.23 0.0 974.4 0.42 ;
    RECT 973.075 0.0 973.65 0.42 ;
    RECT 972.3 0.0 972.495 0.42 ;
    RECT 971.55 0.0 971.72 0.42 ;
    RECT 970.495 0.0 970.97 0.42 ;
    RECT 968.385 0.0 969.915 0.42 ;
    RECT 966.58 0.0 966.755 0.42 ;
    RECT 965.83 0.0 966.0 0.42 ;
    RECT 964.675 0.0 965.25 0.42 ;
    RECT 963.9 0.0 964.095 0.42 ;
    RECT 963.15 0.0 963.32 0.42 ;
    RECT 962.095 0.0 962.57 0.42 ;
    RECT 959.985 0.0 961.515 0.42 ;
    RECT 958.935 0.0 959.405 0.42 ;
    RECT 958.18 0.0 958.355 0.42 ;
    RECT 957.43 0.0 957.6 0.42 ;
    RECT 956.275 0.0 956.85 0.42 ;
    RECT 955.5 0.0 955.695 0.42 ;
    RECT 954.75 0.0 954.92 0.42 ;
    RECT 953.695 0.0 954.17 0.42 ;
    RECT 951.585 0.0 953.115 0.42 ;
    RECT 949.78 0.0 949.955 0.42 ;
    RECT 949.03 0.0 949.2 0.42 ;
    RECT 947.875 0.0 948.45 0.42 ;
    RECT 947.1 0.0 947.295 0.42 ;
    RECT 946.35 0.0 946.52 0.42 ;
    RECT 945.295 0.0 945.77 0.42 ;
    RECT 943.185 0.0 944.715 0.42 ;
    RECT 942.135 0.0 942.605 0.42 ;
    RECT 941.38 0.0 941.555 0.42 ;
    RECT 940.63 0.0 940.8 0.42 ;
    RECT 938.495 0.0 940.05 0.42 ;
    RECT 937.165 0.0 937.745 0.42 ;
    RECT 935.84 0.0 936.415 0.42 ;
    RECT 934.52 0.0 935.1 0.42 ;
    RECT 931.875 0.0 932.455 0.42 ;
    RECT 930.55 0.0 931.135 0.42 ;
    RECT 929.12 0.0 929.81 0.42 ;
    RECT 927.9 0.0 928.55 0.42 ;
    RECT 925.59 0.0 927.16 0.42 ;
    RECT 921.805 0.0 925.02 0.42 ;
    RECT 920.51 0.0 921.065 0.42 ;
    RECT 919.205 0.0 919.77 0.42 ;
    RECT 916.605 0.0 917.92 0.42 ;
    RECT 915.3 0.0 915.865 0.42 ;
    RECT 913.995 0.0 914.56 0.42 ;
    RECT 912.7 0.0 913.255 0.42 ;
    RECT 910.21 0.0 910.575 0.42 ;
    RECT 906.425 0.0 909.47 0.42 ;
    RECT 902.865 0.0 905.855 0.42 ;
    RECT 901.36 0.0 902.125 0.42 ;
    RECT 898.715 0.0 900.62 0.42 ;
    RECT 897.39 0.0 897.975 0.42 ;
    RECT 896.07 0.0 896.65 0.42 ;
    RECT 894.745 0.0 895.33 0.42 ;
    RECT 893.42 0.0 894.005 0.42 ;
    RECT 890.775 0.0 892.09 0.42 ;
    RECT 889.44 0.0 890.035 0.42 ;
    RECT 888.12 0.0 888.7 0.42 ;
    RECT 887.09 0.0 887.38 0.42 ;
    RECT 886.045 0.0 886.35 0.42 ;
    RECT 884.73 0.0 885.305 0.42 ;
    RECT 883.405 0.0 883.99 0.42 ;
    RECT 882.08 0.0 882.665 0.42 ;
    RECT 879.425 0.0 880.01 0.42 ;
    RECT 878.105 0.0 878.685 0.42 ;
    RECT 876.78 0.0 877.365 0.42 ;
    RECT 874.475 0.0 876.04 0.42 ;
    RECT 873.7 0.0 873.895 0.42 ;
    RECT 872.95 0.0 873.12 0.42 ;
    RECT 871.895 0.0 872.37 0.42 ;
    RECT 869.785 0.0 871.315 0.42 ;
    RECT 867.98 0.0 868.155 0.42 ;
    RECT 867.23 0.0 867.4 0.42 ;
    RECT 866.075 0.0 866.65 0.42 ;
    RECT 865.3 0.0 865.495 0.42 ;
    RECT 864.55 0.0 864.72 0.42 ;
    RECT 863.495 0.0 863.97 0.42 ;
    RECT 861.385 0.0 862.915 0.42 ;
    RECT 860.335 0.0 860.805 0.42 ;
    RECT 859.58 0.0 859.755 0.42 ;
    RECT 858.83 0.0 859.0 0.42 ;
    RECT 857.675 0.0 858.25 0.42 ;
    RECT 856.9 0.0 857.095 0.42 ;
    RECT 856.15 0.0 856.32 0.42 ;
    RECT 855.095 0.0 855.57 0.42 ;
    RECT 852.985 0.0 854.515 0.42 ;
    RECT 851.18 0.0 851.355 0.42 ;
    RECT 850.43 0.0 850.6 0.42 ;
    RECT 849.275 0.0 849.85 0.42 ;
    RECT 848.5 0.0 848.695 0.42 ;
    RECT 847.75 0.0 847.92 0.42 ;
    RECT 846.695 0.0 847.17 0.42 ;
    RECT 844.585 0.0 846.115 0.42 ;
    RECT 843.535 0.0 844.005 0.42 ;
    RECT 842.78 0.0 842.955 0.42 ;
    RECT 842.03 0.0 842.2 0.42 ;
    RECT 840.875 0.0 841.45 0.42 ;
    RECT 840.1 0.0 840.295 0.42 ;
    RECT 839.35 0.0 839.52 0.42 ;
    RECT 838.295 0.0 838.77 0.42 ;
    RECT 836.185 0.0 837.715 0.42 ;
    RECT 834.38 0.0 834.555 0.42 ;
    RECT 833.63 0.0 833.8 0.42 ;
    RECT 832.475 0.0 833.05 0.42 ;
    RECT 831.7 0.0 831.895 0.42 ;
    RECT 830.95 0.0 831.12 0.42 ;
    RECT 829.895 0.0 830.37 0.42 ;
    RECT 827.785 0.0 829.315 0.42 ;
    RECT 826.735 0.0 827.205 0.42 ;
    RECT 825.98 0.0 826.155 0.42 ;
    RECT 825.23 0.0 825.4 0.42 ;
    RECT 824.075 0.0 824.65 0.42 ;
    RECT 823.3 0.0 823.495 0.42 ;
    RECT 822.55 0.0 822.72 0.42 ;
    RECT 821.495 0.0 821.97 0.42 ;
    RECT 819.385 0.0 820.915 0.42 ;
    RECT 817.58 0.0 817.755 0.42 ;
    RECT 816.83 0.0 817.0 0.42 ;
    RECT 815.675 0.0 816.25 0.42 ;
    RECT 814.9 0.0 815.095 0.42 ;
    RECT 814.15 0.0 814.32 0.42 ;
    RECT 813.095 0.0 813.57 0.42 ;
    RECT 810.985 0.0 812.515 0.42 ;
    RECT 809.935 0.0 810.405 0.42 ;
    RECT 809.18 0.0 809.355 0.42 ;
    RECT 808.43 0.0 808.6 0.42 ;
    RECT 807.275 0.0 807.85 0.42 ;
    RECT 806.5 0.0 806.695 0.42 ;
    RECT 805.75 0.0 805.92 0.42 ;
    RECT 804.695 0.0 805.17 0.42 ;
    RECT 802.585 0.0 804.115 0.42 ;
    RECT 800.78 0.0 800.955 0.42 ;
    RECT 800.03 0.0 800.2 0.42 ;
    RECT 798.875 0.0 799.45 0.42 ;
    RECT 798.1 0.0 798.295 0.42 ;
    RECT 797.35 0.0 797.52 0.42 ;
    RECT 796.295 0.0 796.77 0.42 ;
    RECT 794.185 0.0 795.715 0.42 ;
    RECT 793.135 0.0 793.605 0.42 ;
    RECT 792.38 0.0 792.555 0.42 ;
    RECT 791.63 0.0 791.8 0.42 ;
    RECT 790.475 0.0 791.05 0.42 ;
    RECT 789.7 0.0 789.895 0.42 ;
    RECT 788.95 0.0 789.12 0.42 ;
    RECT 787.895 0.0 788.37 0.42 ;
    RECT 785.785 0.0 787.315 0.42 ;
    RECT 783.98 0.0 784.155 0.42 ;
    RECT 783.23 0.0 783.4 0.42 ;
    RECT 782.075 0.0 782.65 0.42 ;
    RECT 781.3 0.0 781.495 0.42 ;
    RECT 780.55 0.0 780.72 0.42 ;
    RECT 779.495 0.0 779.97 0.42 ;
    RECT 777.385 0.0 778.915 0.42 ;
    RECT 776.335 0.0 776.805 0.42 ;
    RECT 775.58 0.0 775.755 0.42 ;
    RECT 774.83 0.0 775.0 0.42 ;
    RECT 773.675 0.0 774.25 0.42 ;
    RECT 772.9 0.0 773.095 0.42 ;
    RECT 772.15 0.0 772.32 0.42 ;
    RECT 771.095 0.0 771.57 0.42 ;
    RECT 768.985 0.0 770.515 0.42 ;
    RECT 767.18 0.0 767.355 0.42 ;
    RECT 766.43 0.0 766.6 0.42 ;
    RECT 765.275 0.0 765.85 0.42 ;
    RECT 764.5 0.0 764.695 0.42 ;
    RECT 763.75 0.0 763.92 0.42 ;
    RECT 762.695 0.0 763.17 0.42 ;
    RECT 760.585 0.0 762.115 0.42 ;
    RECT 759.535 0.0 760.005 0.42 ;
    RECT 758.78 0.0 758.955 0.42 ;
    RECT 758.03 0.0 758.2 0.42 ;
    RECT 756.875 0.0 757.45 0.42 ;
    RECT 756.1 0.0 756.295 0.42 ;
    RECT 755.35 0.0 755.52 0.42 ;
    RECT 754.295 0.0 754.77 0.42 ;
    RECT 752.185 0.0 753.715 0.42 ;
    RECT 750.38 0.0 750.555 0.42 ;
    RECT 749.63 0.0 749.8 0.42 ;
    RECT 748.475 0.0 749.05 0.42 ;
    RECT 747.7 0.0 747.895 0.42 ;
    RECT 746.95 0.0 747.12 0.42 ;
    RECT 745.895 0.0 746.37 0.42 ;
    RECT 743.785 0.0 745.315 0.42 ;
    RECT 742.735 0.0 743.205 0.42 ;
    RECT 741.98 0.0 742.155 0.42 ;
    RECT 741.23 0.0 741.4 0.42 ;
    RECT 740.075 0.0 740.65 0.42 ;
    RECT 739.3 0.0 739.495 0.42 ;
    RECT 738.55 0.0 738.72 0.42 ;
    RECT 737.495 0.0 737.97 0.42 ;
    RECT 735.385 0.0 736.915 0.42 ;
    RECT 733.58 0.0 733.755 0.42 ;
    RECT 732.83 0.0 733.0 0.42 ;
    RECT 731.675 0.0 732.25 0.42 ;
    RECT 730.9 0.0 731.095 0.42 ;
    RECT 730.15 0.0 730.32 0.42 ;
    RECT 729.095 0.0 729.57 0.42 ;
    RECT 726.985 0.0 728.515 0.42 ;
    RECT 725.935 0.0 726.405 0.42 ;
    RECT 725.18 0.0 725.355 0.42 ;
    RECT 724.43 0.0 724.6 0.42 ;
    RECT 723.275 0.0 723.85 0.42 ;
    RECT 722.5 0.0 722.695 0.42 ;
    RECT 721.75 0.0 721.92 0.42 ;
    RECT 720.695 0.0 721.17 0.42 ;
    RECT 718.585 0.0 720.115 0.42 ;
    RECT 716.78 0.0 716.955 0.42 ;
    RECT 716.03 0.0 716.2 0.42 ;
    RECT 714.875 0.0 715.45 0.42 ;
    RECT 714.1 0.0 714.295 0.42 ;
    RECT 713.35 0.0 713.52 0.42 ;
    RECT 712.295 0.0 712.77 0.42 ;
    RECT 710.185 0.0 711.715 0.42 ;
    RECT 709.135 0.0 709.605 0.42 ;
    RECT 708.38 0.0 708.555 0.42 ;
    RECT 707.63 0.0 707.8 0.42 ;
    RECT 706.475 0.0 707.05 0.42 ;
    RECT 705.7 0.0 705.895 0.42 ;
    RECT 704.95 0.0 705.12 0.42 ;
    RECT 703.895 0.0 704.37 0.42 ;
    RECT 701.785 0.0 703.315 0.42 ;
    RECT 699.98 0.0 700.155 0.42 ;
    RECT 699.23 0.0 699.4 0.42 ;
    RECT 698.075 0.0 698.65 0.42 ;
    RECT 697.3 0.0 697.495 0.42 ;
    RECT 696.55 0.0 696.72 0.42 ;
    RECT 695.495 0.0 695.97 0.42 ;
    RECT 693.385 0.0 694.915 0.42 ;
    RECT 692.335 0.0 692.805 0.42 ;
    RECT 691.58 0.0 691.755 0.42 ;
    RECT 690.83 0.0 691.0 0.42 ;
    RECT 689.675 0.0 690.25 0.42 ;
    RECT 688.9 0.0 689.095 0.42 ;
    RECT 688.15 0.0 688.32 0.42 ;
    RECT 687.095 0.0 687.57 0.42 ;
    RECT 684.985 0.0 686.515 0.42 ;
    RECT 683.18 0.0 683.355 0.42 ;
    RECT 682.43 0.0 682.6 0.42 ;
    RECT 681.275 0.0 681.85 0.42 ;
    RECT 680.5 0.0 680.695 0.42 ;
    RECT 679.75 0.0 679.92 0.42 ;
    RECT 678.695 0.0 679.17 0.42 ;
    RECT 676.585 0.0 678.115 0.42 ;
    RECT 675.535 0.0 676.005 0.42 ;
    RECT 674.78 0.0 674.955 0.42 ;
    RECT 674.03 0.0 674.2 0.42 ;
    RECT 672.875 0.0 673.45 0.42 ;
    RECT 672.1 0.0 672.295 0.42 ;
    RECT 671.35 0.0 671.52 0.42 ;
    RECT 670.295 0.0 670.77 0.42 ;
    RECT 668.185 0.0 669.715 0.42 ;
    RECT 666.38 0.0 666.555 0.42 ;
    RECT 665.63 0.0 665.8 0.42 ;
    RECT 664.475 0.0 665.05 0.42 ;
    RECT 663.7 0.0 663.895 0.42 ;
    RECT 662.95 0.0 663.12 0.42 ;
    RECT 661.895 0.0 662.37 0.42 ;
    RECT 659.785 0.0 661.315 0.42 ;
    RECT 658.735 0.0 659.205 0.42 ;
    RECT 657.98 0.0 658.155 0.42 ;
    RECT 657.23 0.0 657.4 0.42 ;
    RECT 656.075 0.0 656.65 0.42 ;
    RECT 655.3 0.0 655.495 0.42 ;
    RECT 654.55 0.0 654.72 0.42 ;
    RECT 653.495 0.0 653.97 0.42 ;
    RECT 651.385 0.0 652.915 0.42 ;
    RECT 649.58 0.0 649.755 0.42 ;
    RECT 648.83 0.0 649.0 0.42 ;
    RECT 647.675 0.0 648.25 0.42 ;
    RECT 646.9 0.0 647.095 0.42 ;
    RECT 646.15 0.0 646.32 0.42 ;
    RECT 645.095 0.0 645.57 0.42 ;
    RECT 642.985 0.0 644.515 0.42 ;
    RECT 641.935 0.0 642.405 0.42 ;
    RECT 641.18 0.0 641.355 0.42 ;
    RECT 640.43 0.0 640.6 0.42 ;
    RECT 639.275 0.0 639.85 0.42 ;
    RECT 638.5 0.0 638.695 0.42 ;
    RECT 637.75 0.0 637.92 0.42 ;
    RECT 636.695 0.0 637.17 0.42 ;
    RECT 634.585 0.0 636.115 0.42 ;
    RECT 632.78 0.0 632.955 0.42 ;
    RECT 632.03 0.0 632.2 0.42 ;
    RECT 630.875 0.0 631.45 0.42 ;
    RECT 630.1 0.0 630.295 0.42 ;
    RECT 629.35 0.0 629.52 0.42 ;
    RECT 628.295 0.0 628.77 0.42 ;
    RECT 626.185 0.0 627.715 0.42 ;
    RECT 625.135 0.0 625.605 0.42 ;
    RECT 624.38 0.0 624.555 0.42 ;
    RECT 623.63 0.0 623.8 0.42 ;
    RECT 622.475 0.0 623.05 0.42 ;
    RECT 621.7 0.0 621.895 0.42 ;
    RECT 620.95 0.0 621.12 0.42 ;
    RECT 619.895 0.0 620.37 0.42 ;
    RECT 617.785 0.0 619.315 0.42 ;
    RECT 615.98 0.0 616.155 0.42 ;
    RECT 615.23 0.0 615.4 0.42 ;
    RECT 614.075 0.0 614.65 0.42 ;
    RECT 613.3 0.0 613.495 0.42 ;
    RECT 612.55 0.0 612.72 0.42 ;
    RECT 611.495 0.0 611.97 0.42 ;
    RECT 609.385 0.0 610.915 0.42 ;
    RECT 608.335 0.0 608.805 0.42 ;
    RECT 607.58 0.0 607.755 0.42 ;
    RECT 606.83 0.0 607.0 0.42 ;
    RECT 605.95 0.0 606.25 0.42 ;
    RECT 604.845 0.0 604.985 0.42 ;
    RECT 603.58 0.0 603.88 0.42 ;
    RECT 602.83 0.0 603.0 0.42 ;
    RECT 602.075 0.0 602.25 0.42 ;
    RECT 601.025 0.0 601.495 0.42 ;
    RECT 598.915 0.0 600.445 0.42 ;
    RECT 597.86 0.0 598.335 0.42 ;
    RECT 597.11 0.0 597.28 0.42 ;
    RECT 596.335 0.0 596.53 0.42 ;
    RECT 595.18 0.0 595.755 0.42 ;
    RECT 594.43 0.0 594.6 0.42 ;
    RECT 593.675 0.0 593.85 0.42 ;
    RECT 590.515 0.0 592.045 0.42 ;
    RECT 589.46 0.0 589.935 0.42 ;
    RECT 588.71 0.0 588.88 0.42 ;
    RECT 587.935 0.0 588.13 0.42 ;
    RECT 586.78 0.0 587.355 0.42 ;
    RECT 586.03 0.0 586.2 0.42 ;
    RECT 585.275 0.0 585.45 0.42 ;
    RECT 584.225 0.0 584.695 0.42 ;
    RECT 582.115 0.0 583.645 0.42 ;
    RECT 581.06 0.0 581.535 0.42 ;
    RECT 580.31 0.0 580.48 0.42 ;
    RECT 579.535 0.0 579.73 0.42 ;
    RECT 578.38 0.0 578.955 0.42 ;
    RECT 577.63 0.0 577.8 0.42 ;
    RECT 576.875 0.0 577.05 0.42 ;
    RECT 573.715 0.0 575.245 0.42 ;
    RECT 572.66 0.0 573.135 0.42 ;
    RECT 571.91 0.0 572.08 0.42 ;
    RECT 571.135 0.0 571.33 0.42 ;
    RECT 569.98 0.0 570.555 0.42 ;
    RECT 569.23 0.0 569.4 0.42 ;
    RECT 568.475 0.0 568.65 0.42 ;
    RECT 567.425 0.0 567.895 0.42 ;
    RECT 565.315 0.0 566.845 0.42 ;
    RECT 564.26 0.0 564.735 0.42 ;
    RECT 563.51 0.0 563.68 0.42 ;
    RECT 562.735 0.0 562.93 0.42 ;
    RECT 561.58 0.0 562.155 0.42 ;
    RECT 560.83 0.0 561.0 0.42 ;
    RECT 560.075 0.0 560.25 0.42 ;
    RECT 556.915 0.0 558.445 0.42 ;
    RECT 555.86 0.0 556.335 0.42 ;
    RECT 555.11 0.0 555.28 0.42 ;
    RECT 554.335 0.0 554.53 0.42 ;
    RECT 553.18 0.0 553.755 0.42 ;
    RECT 552.43 0.0 552.6 0.42 ;
    RECT 551.675 0.0 551.85 0.42 ;
    RECT 550.625 0.0 551.095 0.42 ;
    RECT 548.515 0.0 550.045 0.42 ;
    RECT 547.46 0.0 547.935 0.42 ;
    RECT 546.71 0.0 546.88 0.42 ;
    RECT 545.935 0.0 546.13 0.42 ;
    RECT 544.78 0.0 545.355 0.42 ;
    RECT 544.03 0.0 544.2 0.42 ;
    RECT 543.275 0.0 543.45 0.42 ;
    RECT 540.115 0.0 541.645 0.42 ;
    RECT 539.06 0.0 539.535 0.42 ;
    RECT 538.31 0.0 538.48 0.42 ;
    RECT 537.535 0.0 537.73 0.42 ;
    RECT 536.38 0.0 536.955 0.42 ;
    RECT 535.63 0.0 535.8 0.42 ;
    RECT 534.875 0.0 535.05 0.42 ;
    RECT 533.825 0.0 534.295 0.42 ;
    RECT 531.715 0.0 533.245 0.42 ;
    RECT 530.66 0.0 531.135 0.42 ;
    RECT 529.91 0.0 530.08 0.42 ;
    RECT 529.135 0.0 529.33 0.42 ;
    RECT 527.98 0.0 528.555 0.42 ;
    RECT 527.23 0.0 527.4 0.42 ;
    RECT 526.475 0.0 526.65 0.42 ;
    RECT 523.315 0.0 524.845 0.42 ;
    RECT 522.26 0.0 522.735 0.42 ;
    RECT 521.51 0.0 521.68 0.42 ;
    RECT 520.735 0.0 520.93 0.42 ;
    RECT 519.58 0.0 520.155 0.42 ;
    RECT 518.83 0.0 519.0 0.42 ;
    RECT 518.075 0.0 518.25 0.42 ;
    RECT 517.025 0.0 517.495 0.42 ;
    RECT 514.915 0.0 516.445 0.42 ;
    RECT 513.86 0.0 514.335 0.42 ;
    RECT 513.11 0.0 513.28 0.42 ;
    RECT 512.335 0.0 512.53 0.42 ;
    RECT 511.18 0.0 511.755 0.42 ;
    RECT 510.43 0.0 510.6 0.42 ;
    RECT 509.675 0.0 509.85 0.42 ;
    RECT 506.515 0.0 508.045 0.42 ;
    RECT 505.46 0.0 505.935 0.42 ;
    RECT 504.71 0.0 504.88 0.42 ;
    RECT 503.935 0.0 504.13 0.42 ;
    RECT 502.78 0.0 503.355 0.42 ;
    RECT 502.03 0.0 502.2 0.42 ;
    RECT 501.275 0.0 501.45 0.42 ;
    RECT 500.225 0.0 500.695 0.42 ;
    RECT 498.115 0.0 499.645 0.42 ;
    RECT 497.06 0.0 497.535 0.42 ;
    RECT 496.31 0.0 496.48 0.42 ;
    RECT 495.535 0.0 495.73 0.42 ;
    RECT 494.38 0.0 494.955 0.42 ;
    RECT 493.63 0.0 493.8 0.42 ;
    RECT 492.875 0.0 493.05 0.42 ;
    RECT 489.715 0.0 491.245 0.42 ;
    RECT 488.66 0.0 489.135 0.42 ;
    RECT 487.91 0.0 488.08 0.42 ;
    RECT 487.135 0.0 487.33 0.42 ;
    RECT 485.98 0.0 486.555 0.42 ;
    RECT 485.23 0.0 485.4 0.42 ;
    RECT 484.475 0.0 484.65 0.42 ;
    RECT 483.425 0.0 483.895 0.42 ;
    RECT 481.315 0.0 482.845 0.42 ;
    RECT 480.26 0.0 480.735 0.42 ;
    RECT 479.51 0.0 479.68 0.42 ;
    RECT 478.735 0.0 478.93 0.42 ;
    RECT 477.58 0.0 478.155 0.42 ;
    RECT 476.83 0.0 477.0 0.42 ;
    RECT 476.075 0.0 476.25 0.42 ;
    RECT 472.915 0.0 474.445 0.42 ;
    RECT 471.86 0.0 472.335 0.42 ;
    RECT 471.11 0.0 471.28 0.42 ;
    RECT 470.335 0.0 470.53 0.42 ;
    RECT 469.18 0.0 469.755 0.42 ;
    RECT 468.43 0.0 468.6 0.42 ;
    RECT 467.675 0.0 467.85 0.42 ;
    RECT 466.625 0.0 467.095 0.42 ;
    RECT 464.515 0.0 466.045 0.42 ;
    RECT 463.46 0.0 463.935 0.42 ;
    RECT 462.71 0.0 462.88 0.42 ;
    RECT 461.935 0.0 462.13 0.42 ;
    RECT 460.78 0.0 461.355 0.42 ;
    RECT 460.03 0.0 460.2 0.42 ;
    RECT 459.275 0.0 459.45 0.42 ;
    RECT 456.115 0.0 457.645 0.42 ;
    RECT 455.06 0.0 455.535 0.42 ;
    RECT 454.31 0.0 454.48 0.42 ;
    RECT 453.535 0.0 453.73 0.42 ;
    RECT 452.38 0.0 452.955 0.42 ;
    RECT 451.63 0.0 451.8 0.42 ;
    RECT 450.875 0.0 451.05 0.42 ;
    RECT 449.825 0.0 450.295 0.42 ;
    RECT 447.715 0.0 449.245 0.42 ;
    RECT 446.66 0.0 447.135 0.42 ;
    RECT 445.91 0.0 446.08 0.42 ;
    RECT 445.135 0.0 445.33 0.42 ;
    RECT 443.98 0.0 444.555 0.42 ;
    RECT 443.23 0.0 443.4 0.42 ;
    RECT 442.475 0.0 442.65 0.42 ;
    RECT 439.315 0.0 440.845 0.42 ;
    RECT 438.26 0.0 438.735 0.42 ;
    RECT 437.51 0.0 437.68 0.42 ;
    RECT 436.735 0.0 436.93 0.42 ;
    RECT 435.58 0.0 436.155 0.42 ;
    RECT 434.83 0.0 435.0 0.42 ;
    RECT 434.075 0.0 434.25 0.42 ;
    RECT 433.025 0.0 433.495 0.42 ;
    RECT 430.915 0.0 432.445 0.42 ;
    RECT 429.86 0.0 430.335 0.42 ;
    RECT 429.11 0.0 429.28 0.42 ;
    RECT 428.335 0.0 428.53 0.42 ;
    RECT 427.18 0.0 427.755 0.42 ;
    RECT 426.43 0.0 426.6 0.42 ;
    RECT 425.675 0.0 425.85 0.42 ;
    RECT 422.515 0.0 424.045 0.42 ;
    RECT 421.46 0.0 421.935 0.42 ;
    RECT 420.71 0.0 420.88 0.42 ;
    RECT 419.935 0.0 420.13 0.42 ;
    RECT 418.78 0.0 419.355 0.42 ;
    RECT 418.03 0.0 418.2 0.42 ;
    RECT 417.275 0.0 417.45 0.42 ;
    RECT 416.225 0.0 416.695 0.42 ;
    RECT 414.115 0.0 415.645 0.42 ;
    RECT 413.06 0.0 413.535 0.42 ;
    RECT 412.31 0.0 412.48 0.42 ;
    RECT 411.535 0.0 411.73 0.42 ;
    RECT 410.38 0.0 410.955 0.42 ;
    RECT 409.63 0.0 409.8 0.42 ;
    RECT 408.875 0.0 409.05 0.42 ;
    RECT 405.715 0.0 407.245 0.42 ;
    RECT 404.66 0.0 405.135 0.42 ;
    RECT 403.91 0.0 404.08 0.42 ;
    RECT 403.135 0.0 403.33 0.42 ;
    RECT 401.98 0.0 402.555 0.42 ;
    RECT 401.23 0.0 401.4 0.42 ;
    RECT 400.475 0.0 400.65 0.42 ;
    RECT 399.425 0.0 399.895 0.42 ;
    RECT 397.315 0.0 398.845 0.42 ;
    RECT 396.26 0.0 396.735 0.42 ;
    RECT 395.51 0.0 395.68 0.42 ;
    RECT 394.735 0.0 394.93 0.42 ;
    RECT 393.58 0.0 394.155 0.42 ;
    RECT 392.83 0.0 393.0 0.42 ;
    RECT 392.075 0.0 392.25 0.42 ;
    RECT 388.915 0.0 390.445 0.42 ;
    RECT 387.86 0.0 388.335 0.42 ;
    RECT 387.11 0.0 387.28 0.42 ;
    RECT 386.335 0.0 386.53 0.42 ;
    RECT 385.18 0.0 385.755 0.42 ;
    RECT 384.43 0.0 384.6 0.42 ;
    RECT 383.675 0.0 383.85 0.42 ;
    RECT 382.625 0.0 383.095 0.42 ;
    RECT 380.515 0.0 382.045 0.42 ;
    RECT 379.46 0.0 379.935 0.42 ;
    RECT 378.71 0.0 378.88 0.42 ;
    RECT 377.935 0.0 378.13 0.42 ;
    RECT 376.78 0.0 377.355 0.42 ;
    RECT 376.03 0.0 376.2 0.42 ;
    RECT 375.275 0.0 375.45 0.42 ;
    RECT 372.115 0.0 373.645 0.42 ;
    RECT 371.06 0.0 371.535 0.42 ;
    RECT 370.31 0.0 370.48 0.42 ;
    RECT 369.535 0.0 369.73 0.42 ;
    RECT 368.38 0.0 368.955 0.42 ;
    RECT 367.63 0.0 367.8 0.42 ;
    RECT 366.875 0.0 367.05 0.42 ;
    RECT 365.825 0.0 366.295 0.42 ;
    RECT 363.715 0.0 365.245 0.42 ;
    RECT 362.66 0.0 363.135 0.42 ;
    RECT 361.91 0.0 362.08 0.42 ;
    RECT 361.135 0.0 361.33 0.42 ;
    RECT 359.98 0.0 360.555 0.42 ;
    RECT 359.23 0.0 359.4 0.42 ;
    RECT 358.475 0.0 358.65 0.42 ;
    RECT 355.315 0.0 356.845 0.42 ;
    RECT 354.26 0.0 354.735 0.42 ;
    RECT 353.51 0.0 353.68 0.42 ;
    RECT 352.735 0.0 352.93 0.42 ;
    RECT 351.58 0.0 352.155 0.42 ;
    RECT 350.83 0.0 351.0 0.42 ;
    RECT 350.075 0.0 350.25 0.42 ;
    RECT 349.025 0.0 349.495 0.42 ;
    RECT 346.915 0.0 348.445 0.42 ;
    RECT 345.86 0.0 346.335 0.42 ;
    RECT 345.11 0.0 345.28 0.42 ;
    RECT 344.335 0.0 344.53 0.42 ;
    RECT 343.18 0.0 343.755 0.42 ;
    RECT 342.43 0.0 342.6 0.42 ;
    RECT 341.675 0.0 341.85 0.42 ;
    RECT 338.515 0.0 340.045 0.42 ;
    RECT 337.46 0.0 337.935 0.42 ;
    RECT 336.71 0.0 336.88 0.42 ;
    RECT 335.935 0.0 336.13 0.42 ;
    RECT 333.79 0.0 335.355 0.42 ;
    RECT 332.465 0.0 333.05 0.42 ;
    RECT 331.145 0.0 331.725 0.42 ;
    RECT 329.82 0.0 330.405 0.42 ;
    RECT 327.165 0.0 327.75 0.42 ;
    RECT 325.84 0.0 326.425 0.42 ;
    RECT 324.525 0.0 325.1 0.42 ;
    RECT 323.48 0.0 323.785 0.42 ;
    RECT 322.45 0.0 322.74 0.42 ;
    RECT 321.13 0.0 321.71 0.42 ;
    RECT 319.795 0.0 320.39 0.42 ;
    RECT 317.74 0.0 319.055 0.42 ;
    RECT 315.825 0.0 316.41 0.42 ;
    RECT 314.5 0.0 315.085 0.42 ;
    RECT 313.18 0.0 313.76 0.42 ;
    RECT 311.855 0.0 312.44 0.42 ;
    RECT 309.21 0.0 311.115 0.42 ;
    RECT 307.705 0.0 308.47 0.42 ;
    RECT 303.975 0.0 306.965 0.42 ;
    RECT 300.36 0.0 303.405 0.42 ;
    RECT 299.255 0.0 299.62 0.42 ;
    RECT 296.575 0.0 297.13 0.42 ;
    RECT 295.27 0.0 295.835 0.42 ;
    RECT 293.965 0.0 294.53 0.42 ;
    RECT 291.91 0.0 293.225 0.42 ;
    RECT 290.06 0.0 290.625 0.42 ;
    RECT 288.765 0.0 289.32 0.42 ;
    RECT 284.81 0.0 288.025 0.42 ;
    RECT 282.67 0.0 284.24 0.42 ;
    RECT 281.28 0.0 281.93 0.42 ;
    RECT 280.02 0.0 280.71 0.42 ;
    RECT 278.695 0.0 279.28 0.42 ;
    RECT 277.375 0.0 277.955 0.42 ;
    RECT 274.73 0.0 275.31 0.42 ;
    RECT 273.415 0.0 273.99 0.42 ;
    RECT 272.085 0.0 272.665 0.42 ;
    RECT 269.78 0.0 271.335 0.42 ;
    RECT 269.03 0.0 269.2 0.42 ;
    RECT 268.275 0.0 268.45 0.42 ;
    RECT 267.225 0.0 267.695 0.42 ;
    RECT 265.115 0.0 266.645 0.42 ;
    RECT 264.06 0.0 264.535 0.42 ;
    RECT 263.31 0.0 263.48 0.42 ;
    RECT 262.535 0.0 262.73 0.42 ;
    RECT 261.38 0.0 261.955 0.42 ;
    RECT 260.63 0.0 260.8 0.42 ;
    RECT 259.875 0.0 260.05 0.42 ;
    RECT 256.715 0.0 258.245 0.42 ;
    RECT 255.66 0.0 256.135 0.42 ;
    RECT 254.91 0.0 255.08 0.42 ;
    RECT 254.135 0.0 254.33 0.42 ;
    RECT 252.98 0.0 253.555 0.42 ;
    RECT 252.23 0.0 252.4 0.42 ;
    RECT 251.475 0.0 251.65 0.42 ;
    RECT 250.425 0.0 250.895 0.42 ;
    RECT 248.315 0.0 249.845 0.42 ;
    RECT 247.26 0.0 247.735 0.42 ;
    RECT 246.51 0.0 246.68 0.42 ;
    RECT 245.735 0.0 245.93 0.42 ;
    RECT 244.58 0.0 245.155 0.42 ;
    RECT 243.83 0.0 244.0 0.42 ;
    RECT 243.075 0.0 243.25 0.42 ;
    RECT 239.915 0.0 241.445 0.42 ;
    RECT 238.86 0.0 239.335 0.42 ;
    RECT 238.11 0.0 238.28 0.42 ;
    RECT 237.335 0.0 237.53 0.42 ;
    RECT 236.18 0.0 236.755 0.42 ;
    RECT 235.43 0.0 235.6 0.42 ;
    RECT 234.675 0.0 234.85 0.42 ;
    RECT 233.625 0.0 234.095 0.42 ;
    RECT 231.515 0.0 233.045 0.42 ;
    RECT 230.46 0.0 230.935 0.42 ;
    RECT 229.71 0.0 229.88 0.42 ;
    RECT 228.935 0.0 229.13 0.42 ;
    RECT 227.78 0.0 228.355 0.42 ;
    RECT 227.03 0.0 227.2 0.42 ;
    RECT 226.275 0.0 226.45 0.42 ;
    RECT 223.115 0.0 224.645 0.42 ;
    RECT 222.06 0.0 222.535 0.42 ;
    RECT 221.31 0.0 221.48 0.42 ;
    RECT 220.535 0.0 220.73 0.42 ;
    RECT 219.38 0.0 219.955 0.42 ;
    RECT 218.63 0.0 218.8 0.42 ;
    RECT 217.875 0.0 218.05 0.42 ;
    RECT 216.825 0.0 217.295 0.42 ;
    RECT 214.715 0.0 216.245 0.42 ;
    RECT 213.66 0.0 214.135 0.42 ;
    RECT 212.91 0.0 213.08 0.42 ;
    RECT 212.135 0.0 212.33 0.42 ;
    RECT 210.98 0.0 211.555 0.42 ;
    RECT 210.23 0.0 210.4 0.42 ;
    RECT 209.475 0.0 209.65 0.42 ;
    RECT 206.315 0.0 207.845 0.42 ;
    RECT 205.26 0.0 205.735 0.42 ;
    RECT 204.51 0.0 204.68 0.42 ;
    RECT 203.735 0.0 203.93 0.42 ;
    RECT 202.58 0.0 203.155 0.42 ;
    RECT 201.83 0.0 202.0 0.42 ;
    RECT 201.075 0.0 201.25 0.42 ;
    RECT 200.025 0.0 200.495 0.42 ;
    RECT 197.915 0.0 199.445 0.42 ;
    RECT 196.86 0.0 197.335 0.42 ;
    RECT 196.11 0.0 196.28 0.42 ;
    RECT 195.335 0.0 195.53 0.42 ;
    RECT 194.18 0.0 194.755 0.42 ;
    RECT 193.43 0.0 193.6 0.42 ;
    RECT 192.675 0.0 192.85 0.42 ;
    RECT 189.515 0.0 191.045 0.42 ;
    RECT 188.46 0.0 188.935 0.42 ;
    RECT 187.71 0.0 187.88 0.42 ;
    RECT 186.935 0.0 187.13 0.42 ;
    RECT 185.78 0.0 186.355 0.42 ;
    RECT 185.03 0.0 185.2 0.42 ;
    RECT 184.275 0.0 184.45 0.42 ;
    RECT 183.225 0.0 183.695 0.42 ;
    RECT 181.115 0.0 182.645 0.42 ;
    RECT 180.06 0.0 180.535 0.42 ;
    RECT 179.31 0.0 179.48 0.42 ;
    RECT 178.535 0.0 178.73 0.42 ;
    RECT 177.38 0.0 177.955 0.42 ;
    RECT 176.63 0.0 176.8 0.42 ;
    RECT 175.875 0.0 176.05 0.42 ;
    RECT 172.715 0.0 174.245 0.42 ;
    RECT 171.66 0.0 172.135 0.42 ;
    RECT 170.91 0.0 171.08 0.42 ;
    RECT 170.135 0.0 170.33 0.42 ;
    RECT 168.98 0.0 169.555 0.42 ;
    RECT 168.23 0.0 168.4 0.42 ;
    RECT 167.475 0.0 167.65 0.42 ;
    RECT 166.425 0.0 166.895 0.42 ;
    RECT 164.315 0.0 165.845 0.42 ;
    RECT 163.26 0.0 163.735 0.42 ;
    RECT 162.51 0.0 162.68 0.42 ;
    RECT 161.735 0.0 161.93 0.42 ;
    RECT 160.58 0.0 161.155 0.42 ;
    RECT 159.83 0.0 160.0 0.42 ;
    RECT 159.075 0.0 159.25 0.42 ;
    RECT 155.915 0.0 157.445 0.42 ;
    RECT 154.86 0.0 155.335 0.42 ;
    RECT 154.11 0.0 154.28 0.42 ;
    RECT 153.335 0.0 153.53 0.42 ;
    RECT 152.18 0.0 152.755 0.42 ;
    RECT 151.43 0.0 151.6 0.42 ;
    RECT 150.675 0.0 150.85 0.42 ;
    RECT 149.625 0.0 150.095 0.42 ;
    RECT 147.515 0.0 149.045 0.42 ;
    RECT 146.46 0.0 146.935 0.42 ;
    RECT 145.71 0.0 145.88 0.42 ;
    RECT 144.935 0.0 145.13 0.42 ;
    RECT 143.78 0.0 144.355 0.42 ;
    RECT 143.03 0.0 143.2 0.42 ;
    RECT 142.275 0.0 142.45 0.42 ;
    RECT 139.115 0.0 140.645 0.42 ;
    RECT 138.06 0.0 138.535 0.42 ;
    RECT 137.31 0.0 137.48 0.42 ;
    RECT 136.535 0.0 136.73 0.42 ;
    RECT 135.38 0.0 135.955 0.42 ;
    RECT 134.63 0.0 134.8 0.42 ;
    RECT 133.875 0.0 134.05 0.42 ;
    RECT 132.825 0.0 133.295 0.42 ;
    RECT 130.715 0.0 132.245 0.42 ;
    RECT 129.66 0.0 130.135 0.42 ;
    RECT 128.91 0.0 129.08 0.42 ;
    RECT 128.135 0.0 128.33 0.42 ;
    RECT 126.98 0.0 127.555 0.42 ;
    RECT 126.23 0.0 126.4 0.42 ;
    RECT 125.475 0.0 125.65 0.42 ;
    RECT 122.315 0.0 123.845 0.42 ;
    RECT 121.26 0.0 121.735 0.42 ;
    RECT 120.51 0.0 120.68 0.42 ;
    RECT 119.735 0.0 119.93 0.42 ;
    RECT 118.58 0.0 119.155 0.42 ;
    RECT 117.83 0.0 118.0 0.42 ;
    RECT 117.075 0.0 117.25 0.42 ;
    RECT 116.025 0.0 116.495 0.42 ;
    RECT 113.915 0.0 115.445 0.42 ;
    RECT 112.86 0.0 113.335 0.42 ;
    RECT 112.11 0.0 112.28 0.42 ;
    RECT 111.335 0.0 111.53 0.42 ;
    RECT 110.18 0.0 110.755 0.42 ;
    RECT 109.43 0.0 109.6 0.42 ;
    RECT 108.675 0.0 108.85 0.42 ;
    RECT 105.515 0.0 107.045 0.42 ;
    RECT 104.46 0.0 104.935 0.42 ;
    RECT 103.71 0.0 103.88 0.42 ;
    RECT 102.935 0.0 103.13 0.42 ;
    RECT 101.78 0.0 102.355 0.42 ;
    RECT 101.03 0.0 101.2 0.42 ;
    RECT 100.275 0.0 100.45 0.42 ;
    RECT 99.225 0.0 99.695 0.42 ;
    RECT 97.115 0.0 98.645 0.42 ;
    RECT 96.06 0.0 96.535 0.42 ;
    RECT 95.31 0.0 95.48 0.42 ;
    RECT 94.535 0.0 94.73 0.42 ;
    RECT 93.38 0.0 93.955 0.42 ;
    RECT 92.63 0.0 92.8 0.42 ;
    RECT 91.875 0.0 92.05 0.42 ;
    RECT 88.715 0.0 90.245 0.42 ;
    RECT 87.66 0.0 88.135 0.42 ;
    RECT 86.91 0.0 87.08 0.42 ;
    RECT 86.135 0.0 86.33 0.42 ;
    RECT 84.98 0.0 85.555 0.42 ;
    RECT 84.23 0.0 84.4 0.42 ;
    RECT 83.475 0.0 83.65 0.42 ;
    RECT 82.425 0.0 82.895 0.42 ;
    RECT 80.315 0.0 81.845 0.42 ;
    RECT 79.26 0.0 79.735 0.42 ;
    RECT 78.51 0.0 78.68 0.42 ;
    RECT 77.735 0.0 77.93 0.42 ;
    RECT 76.58 0.0 77.155 0.42 ;
    RECT 75.83 0.0 76.0 0.42 ;
    RECT 75.075 0.0 75.25 0.42 ;
    RECT 71.915 0.0 73.445 0.42 ;
    RECT 70.86 0.0 71.335 0.42 ;
    RECT 70.11 0.0 70.28 0.42 ;
    RECT 69.335 0.0 69.53 0.42 ;
    RECT 68.18 0.0 68.755 0.42 ;
    RECT 67.43 0.0 67.6 0.42 ;
    RECT 66.675 0.0 66.85 0.42 ;
    RECT 65.625 0.0 66.095 0.42 ;
    RECT 63.515 0.0 65.045 0.42 ;
    RECT 62.46 0.0 62.935 0.42 ;
    RECT 61.71 0.0 61.88 0.42 ;
    RECT 60.935 0.0 61.13 0.42 ;
    RECT 59.78 0.0 60.355 0.42 ;
    RECT 59.03 0.0 59.2 0.42 ;
    RECT 58.275 0.0 58.45 0.42 ;
    RECT 55.115 0.0 56.645 0.42 ;
    RECT 54.06 0.0 54.535 0.42 ;
    RECT 53.31 0.0 53.48 0.42 ;
    RECT 52.535 0.0 52.73 0.42 ;
    RECT 51.38 0.0 51.955 0.42 ;
    RECT 50.63 0.0 50.8 0.42 ;
    RECT 49.875 0.0 50.05 0.42 ;
    RECT 48.825 0.0 49.295 0.42 ;
    RECT 46.715 0.0 48.245 0.42 ;
    RECT 45.66 0.0 46.135 0.42 ;
    RECT 44.91 0.0 45.08 0.42 ;
    RECT 44.135 0.0 44.33 0.42 ;
    RECT 42.98 0.0 43.555 0.42 ;
    RECT 42.23 0.0 42.4 0.42 ;
    RECT 41.475 0.0 41.65 0.42 ;
    RECT 38.315 0.0 39.845 0.42 ;
    RECT 37.26 0.0 37.735 0.42 ;
    RECT 36.51 0.0 36.68 0.42 ;
    RECT 35.735 0.0 35.93 0.42 ;
    RECT 34.58 0.0 35.155 0.42 ;
    RECT 33.83 0.0 34.0 0.42 ;
    RECT 33.075 0.0 33.25 0.42 ;
    RECT 32.025 0.0 32.495 0.42 ;
    RECT 29.915 0.0 31.445 0.42 ;
    RECT 28.86 0.0 29.335 0.42 ;
    RECT 28.11 0.0 28.28 0.42 ;
    RECT 27.335 0.0 27.53 0.42 ;
    RECT 26.18 0.0 26.755 0.42 ;
    RECT 25.43 0.0 25.6 0.42 ;
    RECT 24.675 0.0 24.85 0.42 ;
    RECT 21.515 0.0 23.045 0.42 ;
    RECT 20.46 0.0 20.935 0.42 ;
    RECT 19.71 0.0 19.88 0.42 ;
    RECT 18.935 0.0 19.13 0.42 ;
    RECT 17.78 0.0 18.355 0.42 ;
    RECT 17.03 0.0 17.2 0.42 ;
    RECT 16.275 0.0 16.45 0.42 ;
    RECT 15.225 0.0 15.695 0.42 ;
    RECT 13.115 0.0 14.645 0.42 ;
    RECT 12.06 0.0 12.535 0.42 ;
    RECT 11.31 0.0 11.48 0.42 ;
    RECT 10.535 0.0 10.73 0.42 ;
    RECT 9.38 0.0 9.955 0.42 ;
    RECT 8.63 0.0 8.8 0.42 ;
    RECT 7.875 0.0 8.05 0.42 ;
    RECT 4.715 0.0 6.245 0.42 ;
    RECT 3.66 0.0 4.135 0.42 ;
    RECT 2.91 0.0 3.08 0.42 ;
    RECT 2.135 0.0 2.33 0.42 ;
    RECT 1.25 0.0 1.555 0.42 ;
    RECT 1208.275 0.42 1208.58 315.365 ;
    RECT 1207.5 0.42 1207.695 315.365 ;
    RECT 1206.75 0.42 1206.92 315.365 ;
    RECT 1205.695 0.42 1206.17 315.365 ;
    RECT 1203.585 0.42 1205.115 315.365 ;
    RECT 1202.535 0.42 1203.005 315.365 ;
    RECT 1201.78 0.42 1201.955 315.365 ;
    RECT 1201.03 0.42 1201.2 315.365 ;
    RECT 1199.875 0.42 1200.45 315.365 ;
    RECT 1199.1 0.42 1199.295 315.365 ;
    RECT 1198.35 0.42 1198.52 315.365 ;
    RECT 1197.295 0.42 1197.77 315.365 ;
    RECT 1195.185 0.42 1196.715 315.365 ;
    RECT 1194.135 0.42 1194.605 315.365 ;
    RECT 1193.38 0.42 1193.555 315.365 ;
    RECT 1192.63 0.42 1192.8 315.365 ;
    RECT 1191.475 0.42 1192.05 315.365 ;
    RECT 1190.7 0.42 1190.895 315.365 ;
    RECT 1189.95 0.42 1190.12 315.365 ;
    RECT 1188.895 0.42 1189.37 315.365 ;
    RECT 1186.785 0.42 1188.315 315.365 ;
    RECT 1185.735 0.42 1186.205 315.365 ;
    RECT 1184.98 0.42 1185.155 315.365 ;
    RECT 1184.23 0.42 1184.4 315.365 ;
    RECT 1183.075 0.42 1183.65 315.365 ;
    RECT 1182.3 0.42 1182.495 315.365 ;
    RECT 1181.55 0.42 1181.72 315.365 ;
    RECT 1180.495 0.42 1180.97 315.365 ;
    RECT 1178.385 0.42 1179.915 315.365 ;
    RECT 1177.335 0.42 1177.805 315.365 ;
    RECT 1176.58 0.42 1176.755 315.365 ;
    RECT 1175.83 0.42 1176.0 315.365 ;
    RECT 1174.675 0.42 1175.25 315.365 ;
    RECT 1173.9 0.42 1174.095 315.365 ;
    RECT 1173.15 0.42 1173.32 315.365 ;
    RECT 1172.095 0.42 1172.57 315.365 ;
    RECT 1169.985 0.42 1171.515 315.365 ;
    RECT 1168.935 0.42 1169.405 315.365 ;
    RECT 1168.18 0.42 1168.355 315.365 ;
    RECT 1167.43 0.42 1167.6 315.365 ;
    RECT 1166.275 0.42 1166.85 315.365 ;
    RECT 1165.5 0.42 1165.695 315.365 ;
    RECT 1164.75 0.42 1164.92 315.365 ;
    RECT 1163.695 0.42 1164.17 315.365 ;
    RECT 1161.585 0.42 1163.115 315.365 ;
    RECT 1160.535 0.42 1161.005 315.365 ;
    RECT 1159.78 0.42 1159.955 315.365 ;
    RECT 1159.03 0.42 1159.2 315.365 ;
    RECT 1157.875 0.42 1158.45 315.365 ;
    RECT 1157.1 0.42 1157.295 315.365 ;
    RECT 1156.35 0.42 1156.52 315.365 ;
    RECT 1155.295 0.42 1155.77 315.365 ;
    RECT 1153.185 0.42 1154.715 315.365 ;
    RECT 1152.135 0.42 1152.605 315.365 ;
    RECT 1151.38 0.42 1151.555 315.365 ;
    RECT 1150.63 0.42 1150.8 315.365 ;
    RECT 1149.475 0.42 1150.05 315.365 ;
    RECT 1148.7 0.42 1148.895 315.365 ;
    RECT 1147.95 0.42 1148.12 315.365 ;
    RECT 1146.895 0.42 1147.37 315.365 ;
    RECT 1144.785 0.42 1146.315 315.365 ;
    RECT 1143.735 0.42 1144.205 315.365 ;
    RECT 1142.98 0.42 1143.155 315.365 ;
    RECT 1142.23 0.42 1142.4 315.365 ;
    RECT 1141.075 0.42 1141.65 315.365 ;
    RECT 1140.3 0.42 1140.495 315.365 ;
    RECT 1139.55 0.42 1139.72 315.365 ;
    RECT 1138.495 0.42 1138.97 315.365 ;
    RECT 1136.385 0.42 1137.915 315.365 ;
    RECT 1135.335 0.42 1135.805 315.365 ;
    RECT 1134.58 0.42 1134.755 315.365 ;
    RECT 1133.83 0.42 1134.0 315.365 ;
    RECT 1132.675 0.42 1133.25 315.365 ;
    RECT 1131.9 0.42 1132.095 315.365 ;
    RECT 1131.15 0.42 1131.32 315.365 ;
    RECT 1130.095 0.42 1130.57 315.365 ;
    RECT 1127.985 0.42 1129.515 315.365 ;
    RECT 1126.935 0.42 1127.405 315.365 ;
    RECT 1126.18 0.42 1126.355 315.365 ;
    RECT 1125.43 0.42 1125.6 315.365 ;
    RECT 1124.275 0.42 1124.85 315.365 ;
    RECT 1123.5 0.42 1123.695 315.365 ;
    RECT 1122.75 0.42 1122.92 315.365 ;
    RECT 1121.695 0.42 1122.17 315.365 ;
    RECT 1119.585 0.42 1121.115 315.365 ;
    RECT 1118.535 0.42 1119.005 315.365 ;
    RECT 1117.78 0.42 1117.955 315.365 ;
    RECT 1117.03 0.42 1117.2 315.365 ;
    RECT 1115.875 0.42 1116.45 315.365 ;
    RECT 1115.1 0.42 1115.295 315.365 ;
    RECT 1114.35 0.42 1114.52 315.365 ;
    RECT 1113.295 0.42 1113.77 315.365 ;
    RECT 1111.185 0.42 1112.715 315.365 ;
    RECT 1110.135 0.42 1110.605 315.365 ;
    RECT 1109.38 0.42 1109.555 315.365 ;
    RECT 1108.63 0.42 1108.8 315.365 ;
    RECT 1107.475 0.42 1108.05 315.365 ;
    RECT 1106.7 0.42 1106.895 315.365 ;
    RECT 1105.95 0.42 1106.12 315.365 ;
    RECT 1104.895 0.42 1105.37 315.365 ;
    RECT 1102.785 0.42 1104.315 315.365 ;
    RECT 1101.735 0.42 1102.205 315.365 ;
    RECT 1100.98 0.42 1101.155 315.365 ;
    RECT 1100.23 0.42 1100.4 315.365 ;
    RECT 1099.075 0.42 1099.65 315.365 ;
    RECT 1098.3 0.42 1098.495 315.365 ;
    RECT 1097.55 0.42 1097.72 315.365 ;
    RECT 1096.495 0.42 1096.97 315.365 ;
    RECT 1094.385 0.42 1095.915 315.365 ;
    RECT 1093.335 0.42 1093.805 315.365 ;
    RECT 1092.58 0.42 1092.755 315.365 ;
    RECT 1091.83 0.42 1092.0 315.365 ;
    RECT 1090.675 0.42 1091.25 315.365 ;
    RECT 1089.9 0.42 1090.095 315.365 ;
    RECT 1089.15 0.42 1089.32 315.365 ;
    RECT 1088.095 0.42 1088.57 315.365 ;
    RECT 1085.985 0.42 1087.515 315.365 ;
    RECT 1084.935 0.42 1085.405 315.365 ;
    RECT 1084.18 0.42 1084.355 315.365 ;
    RECT 1083.43 0.42 1083.6 315.365 ;
    RECT 1082.275 0.42 1082.85 315.365 ;
    RECT 1081.5 0.42 1081.695 315.365 ;
    RECT 1080.75 0.42 1080.92 315.365 ;
    RECT 1079.695 0.42 1080.17 315.365 ;
    RECT 1077.585 0.42 1079.115 315.365 ;
    RECT 1076.535 0.42 1077.005 315.365 ;
    RECT 1075.78 0.42 1075.955 315.365 ;
    RECT 1075.03 0.42 1075.2 315.365 ;
    RECT 1073.875 0.42 1074.45 315.365 ;
    RECT 1073.1 0.42 1073.295 315.365 ;
    RECT 1072.35 0.42 1072.52 315.365 ;
    RECT 1071.295 0.42 1071.77 315.365 ;
    RECT 1069.185 0.42 1070.715 315.365 ;
    RECT 1068.135 0.42 1068.605 315.365 ;
    RECT 1067.38 0.42 1067.555 315.365 ;
    RECT 1066.63 0.42 1066.8 315.365 ;
    RECT 1065.475 0.42 1066.05 315.365 ;
    RECT 1064.7 0.42 1064.895 315.365 ;
    RECT 1063.95 0.42 1064.12 315.365 ;
    RECT 1062.895 0.42 1063.37 315.365 ;
    RECT 1060.785 0.42 1062.315 315.365 ;
    RECT 1059.735 0.42 1060.205 315.365 ;
    RECT 1058.98 0.42 1059.155 315.365 ;
    RECT 1058.23 0.42 1058.4 315.365 ;
    RECT 1057.075 0.42 1057.65 315.365 ;
    RECT 1056.3 0.42 1056.495 315.365 ;
    RECT 1055.55 0.42 1055.72 315.365 ;
    RECT 1054.495 0.42 1054.97 315.365 ;
    RECT 1052.385 0.42 1053.915 315.365 ;
    RECT 1051.335 0.42 1051.805 315.365 ;
    RECT 1050.58 0.42 1050.755 315.365 ;
    RECT 1049.83 0.42 1050.0 315.365 ;
    RECT 1048.675 0.42 1049.25 315.365 ;
    RECT 1047.9 0.42 1048.095 315.365 ;
    RECT 1047.15 0.42 1047.32 315.365 ;
    RECT 1046.095 0.42 1046.57 315.365 ;
    RECT 1043.985 0.42 1045.515 315.365 ;
    RECT 1042.935 0.42 1043.405 315.365 ;
    RECT 1042.18 0.42 1042.355 315.365 ;
    RECT 1041.43 0.42 1041.6 315.365 ;
    RECT 1040.275 0.42 1040.85 315.365 ;
    RECT 1039.5 0.42 1039.695 315.365 ;
    RECT 1038.75 0.42 1038.92 315.365 ;
    RECT 1037.695 0.42 1038.17 315.365 ;
    RECT 1035.585 0.42 1037.115 315.365 ;
    RECT 1034.535 0.42 1035.005 315.365 ;
    RECT 1033.78 0.42 1033.955 315.365 ;
    RECT 1033.03 0.42 1033.2 315.365 ;
    RECT 1031.875 0.42 1032.45 315.365 ;
    RECT 1031.1 0.42 1031.295 315.365 ;
    RECT 1030.35 0.42 1030.52 315.365 ;
    RECT 1029.295 0.42 1029.77 315.365 ;
    RECT 1027.185 0.42 1028.715 315.365 ;
    RECT 1026.135 0.42 1026.605 315.365 ;
    RECT 1025.38 0.42 1025.555 315.365 ;
    RECT 1024.63 0.42 1024.8 315.365 ;
    RECT 1023.475 0.42 1024.05 315.365 ;
    RECT 1022.7 0.42 1022.895 315.365 ;
    RECT 1021.95 0.42 1022.12 315.365 ;
    RECT 1020.895 0.42 1021.37 315.365 ;
    RECT 1018.785 0.42 1020.315 315.365 ;
    RECT 1017.735 0.42 1018.205 315.365 ;
    RECT 1016.98 0.42 1017.155 315.365 ;
    RECT 1016.23 0.42 1016.4 315.365 ;
    RECT 1015.075 0.42 1015.65 315.365 ;
    RECT 1014.3 0.42 1014.495 315.365 ;
    RECT 1013.55 0.42 1013.72 315.365 ;
    RECT 1012.495 0.42 1012.97 315.365 ;
    RECT 1010.385 0.42 1011.915 315.365 ;
    RECT 1009.335 0.42 1009.805 315.365 ;
    RECT 1008.58 0.42 1008.755 315.365 ;
    RECT 1007.83 0.42 1008.0 315.365 ;
    RECT 1006.675 0.42 1007.25 315.365 ;
    RECT 1005.9 0.42 1006.095 315.365 ;
    RECT 1005.15 0.42 1005.32 315.365 ;
    RECT 1004.095 0.42 1004.57 315.365 ;
    RECT 1001.985 0.42 1003.515 315.365 ;
    RECT 1000.935 0.42 1001.405 315.365 ;
    RECT 1000.18 0.42 1000.355 315.365 ;
    RECT 999.43 0.42 999.6 315.365 ;
    RECT 998.275 0.42 998.85 315.365 ;
    RECT 997.5 0.42 997.695 315.365 ;
    RECT 996.75 0.42 996.92 315.365 ;
    RECT 995.695 0.42 996.17 315.365 ;
    RECT 993.585 0.42 995.115 315.365 ;
    RECT 992.535 0.42 993.005 315.365 ;
    RECT 991.78 0.42 991.955 315.365 ;
    RECT 991.03 0.42 991.2 315.365 ;
    RECT 989.875 0.42 990.45 315.365 ;
    RECT 989.1 0.42 989.295 315.365 ;
    RECT 988.35 0.42 988.52 315.365 ;
    RECT 987.295 0.42 987.77 315.365 ;
    RECT 985.185 0.42 986.715 315.365 ;
    RECT 984.135 0.42 984.605 315.365 ;
    RECT 983.38 0.42 983.555 315.365 ;
    RECT 982.63 0.42 982.8 315.365 ;
    RECT 981.475 0.42 982.05 315.365 ;
    RECT 980.7 0.42 980.895 315.365 ;
    RECT 979.95 0.42 980.12 315.365 ;
    RECT 978.895 0.42 979.37 315.365 ;
    RECT 976.785 0.42 978.315 315.365 ;
    RECT 975.735 0.42 976.205 315.365 ;
    RECT 974.98 0.42 975.155 315.365 ;
    RECT 974.23 0.42 974.4 315.365 ;
    RECT 973.075 0.42 973.65 315.365 ;
    RECT 972.3 0.42 972.495 315.365 ;
    RECT 971.55 0.42 971.72 315.365 ;
    RECT 970.495 0.42 970.97 315.365 ;
    RECT 968.385 0.42 969.915 315.365 ;
    RECT 967.335 0.42 967.805 315.365 ;
    RECT 966.58 0.42 966.755 315.365 ;
    RECT 965.83 0.42 966.0 315.365 ;
    RECT 964.675 0.42 965.25 315.365 ;
    RECT 963.9 0.42 964.095 315.365 ;
    RECT 963.15 0.42 963.32 315.365 ;
    RECT 962.095 0.42 962.57 315.365 ;
    RECT 959.985 0.42 961.515 315.365 ;
    RECT 958.935 0.42 959.405 315.365 ;
    RECT 958.18 0.42 958.355 315.365 ;
    RECT 957.43 0.42 957.6 315.365 ;
    RECT 956.275 0.42 956.85 315.365 ;
    RECT 955.5 0.42 955.695 315.365 ;
    RECT 954.75 0.42 954.92 315.365 ;
    RECT 953.695 0.42 954.17 315.365 ;
    RECT 951.585 0.42 953.115 315.365 ;
    RECT 950.535 0.42 951.005 315.365 ;
    RECT 949.78 0.42 949.955 315.365 ;
    RECT 949.03 0.42 949.2 315.365 ;
    RECT 947.875 0.42 948.45 315.365 ;
    RECT 947.1 0.42 947.295 315.365 ;
    RECT 946.35 0.42 946.52 315.365 ;
    RECT 945.295 0.42 945.77 315.365 ;
    RECT 943.185 0.42 944.715 315.365 ;
    RECT 942.135 0.42 942.605 315.365 ;
    RECT 941.38 0.42 941.555 315.365 ;
    RECT 940.63 0.42 940.8 315.365 ;
    RECT 938.495 0.42 940.05 315.365 ;
    RECT 937.165 0.42 937.745 315.365 ;
    RECT 935.84 0.42 936.415 315.365 ;
    RECT 934.52 0.42 935.1 315.365 ;
    RECT 931.875 0.42 932.455 315.365 ;
    RECT 930.55 0.42 931.135 315.365 ;
    RECT 929.12 0.42 929.81 315.365 ;
    RECT 927.9 0.42 928.55 315.365 ;
    RECT 925.59 0.42 927.16 315.365 ;
    RECT 921.805 0.42 925.02 315.365 ;
    RECT 920.51 0.42 921.065 315.365 ;
    RECT 919.205 0.42 919.77 315.365 ;
    RECT 916.605 0.42 917.92 315.365 ;
    RECT 915.3 0.42 915.865 315.365 ;
    RECT 913.995 0.42 914.56 315.365 ;
    RECT 912.7 0.42 913.255 315.365 ;
    RECT 910.21 0.42 910.575 315.365 ;
    RECT 906.425 0.42 909.47 315.365 ;
    RECT 902.865 0.42 905.855 315.365 ;
    RECT 901.36 0.42 902.125 315.365 ;
    RECT 898.715 0.42 900.62 315.365 ;
    RECT 897.39 0.42 897.975 315.365 ;
    RECT 896.07 0.42 896.65 315.365 ;
    RECT 894.745 0.42 895.33 315.365 ;
    RECT 893.42 0.42 894.005 315.365 ;
    RECT 890.775 0.42 892.09 315.365 ;
    RECT 889.44 0.42 890.035 315.365 ;
    RECT 888.12 0.42 888.7 315.365 ;
    RECT 887.09 0.42 887.38 315.365 ;
    RECT 886.045 0.42 886.35 315.365 ;
    RECT 884.73 0.42 885.305 315.365 ;
    RECT 883.405 0.42 883.99 315.365 ;
    RECT 882.08 0.42 882.665 315.365 ;
    RECT 879.425 0.42 880.01 315.365 ;
    RECT 878.105 0.42 878.685 315.365 ;
    RECT 876.78 0.42 877.365 315.365 ;
    RECT 874.475 0.42 876.04 315.365 ;
    RECT 873.7 0.42 873.895 315.365 ;
    RECT 872.95 0.42 873.12 315.365 ;
    RECT 871.895 0.42 872.37 315.365 ;
    RECT 869.785 0.42 871.315 315.365 ;
    RECT 868.735 0.42 869.205 315.365 ;
    RECT 867.98 0.42 868.155 315.365 ;
    RECT 867.23 0.42 867.4 315.365 ;
    RECT 866.075 0.42 866.65 315.365 ;
    RECT 865.3 0.42 865.495 315.365 ;
    RECT 864.55 0.42 864.72 315.365 ;
    RECT 863.495 0.42 863.97 315.365 ;
    RECT 861.385 0.42 862.915 315.365 ;
    RECT 860.335 0.42 860.805 315.365 ;
    RECT 859.58 0.42 859.755 315.365 ;
    RECT 858.83 0.42 859.0 315.365 ;
    RECT 857.675 0.42 858.25 315.365 ;
    RECT 856.9 0.42 857.095 315.365 ;
    RECT 856.15 0.42 856.32 315.365 ;
    RECT 855.095 0.42 855.57 315.365 ;
    RECT 852.985 0.42 854.515 315.365 ;
    RECT 851.935 0.42 852.405 315.365 ;
    RECT 851.18 0.42 851.355 315.365 ;
    RECT 850.43 0.42 850.6 315.365 ;
    RECT 849.275 0.42 849.85 315.365 ;
    RECT 848.5 0.42 848.695 315.365 ;
    RECT 847.75 0.42 847.92 315.365 ;
    RECT 846.695 0.42 847.17 315.365 ;
    RECT 844.585 0.42 846.115 315.365 ;
    RECT 843.535 0.42 844.005 315.365 ;
    RECT 842.78 0.42 842.955 315.365 ;
    RECT 842.03 0.42 842.2 315.365 ;
    RECT 840.875 0.42 841.45 315.365 ;
    RECT 840.1 0.42 840.295 315.365 ;
    RECT 839.35 0.42 839.52 315.365 ;
    RECT 838.295 0.42 838.77 315.365 ;
    RECT 836.185 0.42 837.715 315.365 ;
    RECT 835.135 0.42 835.605 315.365 ;
    RECT 834.38 0.42 834.555 315.365 ;
    RECT 833.63 0.42 833.8 315.365 ;
    RECT 832.475 0.42 833.05 315.365 ;
    RECT 831.7 0.42 831.895 315.365 ;
    RECT 830.95 0.42 831.12 315.365 ;
    RECT 829.895 0.42 830.37 315.365 ;
    RECT 827.785 0.42 829.315 315.365 ;
    RECT 826.735 0.42 827.205 315.365 ;
    RECT 825.98 0.42 826.155 315.365 ;
    RECT 825.23 0.42 825.4 315.365 ;
    RECT 824.075 0.42 824.65 315.365 ;
    RECT 823.3 0.42 823.495 315.365 ;
    RECT 822.55 0.42 822.72 315.365 ;
    RECT 821.495 0.42 821.97 315.365 ;
    RECT 819.385 0.42 820.915 315.365 ;
    RECT 818.335 0.42 818.805 315.365 ;
    RECT 817.58 0.42 817.755 315.365 ;
    RECT 816.83 0.42 817.0 315.365 ;
    RECT 815.675 0.42 816.25 315.365 ;
    RECT 814.9 0.42 815.095 315.365 ;
    RECT 814.15 0.42 814.32 315.365 ;
    RECT 813.095 0.42 813.57 315.365 ;
    RECT 810.985 0.42 812.515 315.365 ;
    RECT 809.935 0.42 810.405 315.365 ;
    RECT 809.18 0.42 809.355 315.365 ;
    RECT 808.43 0.42 808.6 315.365 ;
    RECT 807.275 0.42 807.85 315.365 ;
    RECT 806.5 0.42 806.695 315.365 ;
    RECT 805.75 0.42 805.92 315.365 ;
    RECT 804.695 0.42 805.17 315.365 ;
    RECT 802.585 0.42 804.115 315.365 ;
    RECT 801.535 0.42 802.005 315.365 ;
    RECT 800.78 0.42 800.955 315.365 ;
    RECT 800.03 0.42 800.2 315.365 ;
    RECT 798.875 0.42 799.45 315.365 ;
    RECT 798.1 0.42 798.295 315.365 ;
    RECT 797.35 0.42 797.52 315.365 ;
    RECT 796.295 0.42 796.77 315.365 ;
    RECT 794.185 0.42 795.715 315.365 ;
    RECT 793.135 0.42 793.605 315.365 ;
    RECT 792.38 0.42 792.555 315.365 ;
    RECT 791.63 0.42 791.8 315.365 ;
    RECT 790.475 0.42 791.05 315.365 ;
    RECT 789.7 0.42 789.895 315.365 ;
    RECT 788.95 0.42 789.12 315.365 ;
    RECT 787.895 0.42 788.37 315.365 ;
    RECT 785.785 0.42 787.315 315.365 ;
    RECT 784.735 0.42 785.205 315.365 ;
    RECT 783.98 0.42 784.155 315.365 ;
    RECT 783.23 0.42 783.4 315.365 ;
    RECT 782.075 0.42 782.65 315.365 ;
    RECT 781.3 0.42 781.495 315.365 ;
    RECT 780.55 0.42 780.72 315.365 ;
    RECT 779.495 0.42 779.97 315.365 ;
    RECT 777.385 0.42 778.915 315.365 ;
    RECT 776.335 0.42 776.805 315.365 ;
    RECT 775.58 0.42 775.755 315.365 ;
    RECT 774.83 0.42 775.0 315.365 ;
    RECT 773.675 0.42 774.25 315.365 ;
    RECT 772.9 0.42 773.095 315.365 ;
    RECT 772.15 0.42 772.32 315.365 ;
    RECT 771.095 0.42 771.57 315.365 ;
    RECT 768.985 0.42 770.515 315.365 ;
    RECT 767.935 0.42 768.405 315.365 ;
    RECT 767.18 0.42 767.355 315.365 ;
    RECT 766.43 0.42 766.6 315.365 ;
    RECT 765.275 0.42 765.85 315.365 ;
    RECT 764.5 0.42 764.695 315.365 ;
    RECT 763.75 0.42 763.92 315.365 ;
    RECT 762.695 0.42 763.17 315.365 ;
    RECT 760.585 0.42 762.115 315.365 ;
    RECT 759.535 0.42 760.005 315.365 ;
    RECT 758.78 0.42 758.955 315.365 ;
    RECT 758.03 0.42 758.2 315.365 ;
    RECT 756.875 0.42 757.45 315.365 ;
    RECT 756.1 0.42 756.295 315.365 ;
    RECT 755.35 0.42 755.52 315.365 ;
    RECT 754.295 0.42 754.77 315.365 ;
    RECT 752.185 0.42 753.715 315.365 ;
    RECT 751.135 0.42 751.605 315.365 ;
    RECT 750.38 0.42 750.555 315.365 ;
    RECT 749.63 0.42 749.8 315.365 ;
    RECT 748.475 0.42 749.05 315.365 ;
    RECT 747.7 0.42 747.895 315.365 ;
    RECT 746.95 0.42 747.12 315.365 ;
    RECT 745.895 0.42 746.37 315.365 ;
    RECT 743.785 0.42 745.315 315.365 ;
    RECT 742.735 0.42 743.205 315.365 ;
    RECT 741.98 0.42 742.155 315.365 ;
    RECT 741.23 0.42 741.4 315.365 ;
    RECT 740.075 0.42 740.65 315.365 ;
    RECT 739.3 0.42 739.495 315.365 ;
    RECT 738.55 0.42 738.72 315.365 ;
    RECT 737.495 0.42 737.97 315.365 ;
    RECT 735.385 0.42 736.915 315.365 ;
    RECT 734.335 0.42 734.805 315.365 ;
    RECT 733.58 0.42 733.755 315.365 ;
    RECT 732.83 0.42 733.0 315.365 ;
    RECT 731.675 0.42 732.25 315.365 ;
    RECT 730.9 0.42 731.095 315.365 ;
    RECT 730.15 0.42 730.32 315.365 ;
    RECT 729.095 0.42 729.57 315.365 ;
    RECT 726.985 0.42 728.515 315.365 ;
    RECT 725.935 0.42 726.405 315.365 ;
    RECT 725.18 0.42 725.355 315.365 ;
    RECT 724.43 0.42 724.6 315.365 ;
    RECT 723.275 0.42 723.85 315.365 ;
    RECT 722.5 0.42 722.695 315.365 ;
    RECT 721.75 0.42 721.92 315.365 ;
    RECT 720.695 0.42 721.17 315.365 ;
    RECT 718.585 0.42 720.115 315.365 ;
    RECT 717.535 0.42 718.005 315.365 ;
    RECT 716.78 0.42 716.955 315.365 ;
    RECT 716.03 0.42 716.2 315.365 ;
    RECT 714.875 0.42 715.45 315.365 ;
    RECT 714.1 0.42 714.295 315.365 ;
    RECT 713.35 0.42 713.52 315.365 ;
    RECT 712.295 0.42 712.77 315.365 ;
    RECT 710.185 0.42 711.715 315.365 ;
    RECT 709.135 0.42 709.605 315.365 ;
    RECT 708.38 0.42 708.555 315.365 ;
    RECT 707.63 0.42 707.8 315.365 ;
    RECT 706.475 0.42 707.05 315.365 ;
    RECT 705.7 0.42 705.895 315.365 ;
    RECT 704.95 0.42 705.12 315.365 ;
    RECT 703.895 0.42 704.37 315.365 ;
    RECT 701.785 0.42 703.315 315.365 ;
    RECT 700.735 0.42 701.205 315.365 ;
    RECT 699.98 0.42 700.155 315.365 ;
    RECT 699.23 0.42 699.4 315.365 ;
    RECT 698.075 0.42 698.65 315.365 ;
    RECT 697.3 0.42 697.495 315.365 ;
    RECT 696.55 0.42 696.72 315.365 ;
    RECT 695.495 0.42 695.97 315.365 ;
    RECT 693.385 0.42 694.915 315.365 ;
    RECT 692.335 0.42 692.805 315.365 ;
    RECT 691.58 0.42 691.755 315.365 ;
    RECT 690.83 0.42 691.0 315.365 ;
    RECT 689.675 0.42 690.25 315.365 ;
    RECT 688.9 0.42 689.095 315.365 ;
    RECT 688.15 0.42 688.32 315.365 ;
    RECT 687.095 0.42 687.57 315.365 ;
    RECT 684.985 0.42 686.515 315.365 ;
    RECT 683.935 0.42 684.405 315.365 ;
    RECT 683.18 0.42 683.355 315.365 ;
    RECT 682.43 0.42 682.6 315.365 ;
    RECT 681.275 0.42 681.85 315.365 ;
    RECT 680.5 0.42 680.695 315.365 ;
    RECT 679.75 0.42 679.92 315.365 ;
    RECT 678.695 0.42 679.17 315.365 ;
    RECT 676.585 0.42 678.115 315.365 ;
    RECT 675.535 0.42 676.005 315.365 ;
    RECT 674.78 0.42 674.955 315.365 ;
    RECT 674.03 0.42 674.2 315.365 ;
    RECT 672.875 0.42 673.45 315.365 ;
    RECT 672.1 0.42 672.295 315.365 ;
    RECT 671.35 0.42 671.52 315.365 ;
    RECT 670.295 0.42 670.77 315.365 ;
    RECT 668.185 0.42 669.715 315.365 ;
    RECT 667.135 0.42 667.605 315.365 ;
    RECT 666.38 0.42 666.555 315.365 ;
    RECT 665.63 0.42 665.8 315.365 ;
    RECT 664.475 0.42 665.05 315.365 ;
    RECT 663.7 0.42 663.895 315.365 ;
    RECT 662.95 0.42 663.12 315.365 ;
    RECT 661.895 0.42 662.37 315.365 ;
    RECT 659.785 0.42 661.315 315.365 ;
    RECT 658.735 0.42 659.205 315.365 ;
    RECT 657.98 0.42 658.155 315.365 ;
    RECT 657.23 0.42 657.4 315.365 ;
    RECT 656.075 0.42 656.65 315.365 ;
    RECT 655.3 0.42 655.495 315.365 ;
    RECT 654.55 0.42 654.72 315.365 ;
    RECT 653.495 0.42 653.97 315.365 ;
    RECT 651.385 0.42 652.915 315.365 ;
    RECT 650.335 0.42 650.805 315.365 ;
    RECT 649.58 0.42 649.755 315.365 ;
    RECT 648.83 0.42 649.0 315.365 ;
    RECT 647.675 0.42 648.25 315.365 ;
    RECT 646.9 0.42 647.095 315.365 ;
    RECT 646.15 0.42 646.32 315.365 ;
    RECT 645.095 0.42 645.57 315.365 ;
    RECT 642.985 0.42 644.515 315.365 ;
    RECT 641.935 0.42 642.405 315.365 ;
    RECT 641.18 0.42 641.355 315.365 ;
    RECT 640.43 0.42 640.6 315.365 ;
    RECT 639.275 0.42 639.85 315.365 ;
    RECT 638.5 0.42 638.695 315.365 ;
    RECT 637.75 0.42 637.92 315.365 ;
    RECT 636.695 0.42 637.17 315.365 ;
    RECT 634.585 0.42 636.115 315.365 ;
    RECT 633.535 0.42 634.005 315.365 ;
    RECT 632.78 0.42 632.955 315.365 ;
    RECT 632.03 0.42 632.2 315.365 ;
    RECT 630.875 0.42 631.45 315.365 ;
    RECT 630.1 0.42 630.295 315.365 ;
    RECT 629.35 0.42 629.52 315.365 ;
    RECT 628.295 0.42 628.77 315.365 ;
    RECT 626.185 0.42 627.715 315.365 ;
    RECT 625.135 0.42 625.605 315.365 ;
    RECT 624.38 0.42 624.555 315.365 ;
    RECT 623.63 0.42 623.8 315.365 ;
    RECT 622.475 0.42 623.05 315.365 ;
    RECT 621.7 0.42 621.895 315.365 ;
    RECT 620.95 0.42 621.12 315.365 ;
    RECT 619.895 0.42 620.37 315.365 ;
    RECT 617.785 0.42 619.315 315.365 ;
    RECT 616.735 0.42 617.205 315.365 ;
    RECT 615.98 0.42 616.155 315.365 ;
    RECT 615.23 0.42 615.4 315.365 ;
    RECT 614.075 0.42 614.65 315.365 ;
    RECT 613.3 0.42 613.495 315.365 ;
    RECT 612.55 0.42 612.72 315.365 ;
    RECT 611.495 0.42 611.97 315.365 ;
    RECT 609.385 0.42 610.915 315.365 ;
    RECT 608.335 0.42 608.805 315.365 ;
    RECT 607.58 0.42 607.755 315.365 ;
    RECT 606.83 0.42 607.0 315.365 ;
    RECT 605.95 0.42 606.25 315.365 ;
    RECT 604.845 0.42 604.985 315.365 ;
    RECT 603.58 0.42 603.88 315.365 ;
    RECT 602.83 0.42 603.0 315.365 ;
    RECT 602.075 0.42 602.25 315.365 ;
    RECT 601.025 0.42 601.495 315.365 ;
    RECT 598.915 0.42 600.445 315.365 ;
    RECT 597.86 0.42 598.335 315.365 ;
    RECT 597.11 0.42 597.28 315.365 ;
    RECT 596.335 0.42 596.53 315.365 ;
    RECT 595.18 0.42 595.755 315.365 ;
    RECT 594.43 0.42 594.6 315.365 ;
    RECT 593.675 0.42 593.85 315.365 ;
    RECT 592.625 0.42 593.095 315.365 ;
    RECT 590.515 0.42 592.045 315.365 ;
    RECT 589.46 0.42 589.935 315.365 ;
    RECT 588.71 0.42 588.88 315.365 ;
    RECT 587.935 0.42 588.13 315.365 ;
    RECT 586.78 0.42 587.355 315.365 ;
    RECT 586.03 0.42 586.2 315.365 ;
    RECT 585.275 0.42 585.45 315.365 ;
    RECT 584.225 0.42 584.695 315.365 ;
    RECT 582.115 0.42 583.645 315.365 ;
    RECT 581.06 0.42 581.535 315.365 ;
    RECT 580.31 0.42 580.48 315.365 ;
    RECT 579.535 0.42 579.73 315.365 ;
    RECT 578.38 0.42 578.955 315.365 ;
    RECT 577.63 0.42 577.8 315.365 ;
    RECT 576.875 0.42 577.05 315.365 ;
    RECT 575.825 0.42 576.295 315.365 ;
    RECT 573.715 0.42 575.245 315.365 ;
    RECT 572.66 0.42 573.135 315.365 ;
    RECT 571.91 0.42 572.08 315.365 ;
    RECT 571.135 0.42 571.33 315.365 ;
    RECT 569.98 0.42 570.555 315.365 ;
    RECT 569.23 0.42 569.4 315.365 ;
    RECT 568.475 0.42 568.65 315.365 ;
    RECT 567.425 0.42 567.895 315.365 ;
    RECT 565.315 0.42 566.845 315.365 ;
    RECT 564.26 0.42 564.735 315.365 ;
    RECT 563.51 0.42 563.68 315.365 ;
    RECT 562.735 0.42 562.93 315.365 ;
    RECT 561.58 0.42 562.155 315.365 ;
    RECT 560.83 0.42 561.0 315.365 ;
    RECT 560.075 0.42 560.25 315.365 ;
    RECT 559.025 0.42 559.495 315.365 ;
    RECT 556.915 0.42 558.445 315.365 ;
    RECT 555.86 0.42 556.335 315.365 ;
    RECT 555.11 0.42 555.28 315.365 ;
    RECT 554.335 0.42 554.53 315.365 ;
    RECT 553.18 0.42 553.755 315.365 ;
    RECT 552.43 0.42 552.6 315.365 ;
    RECT 551.675 0.42 551.85 315.365 ;
    RECT 550.625 0.42 551.095 315.365 ;
    RECT 548.515 0.42 550.045 315.365 ;
    RECT 547.46 0.42 547.935 315.365 ;
    RECT 546.71 0.42 546.88 315.365 ;
    RECT 545.935 0.42 546.13 315.365 ;
    RECT 544.78 0.42 545.355 315.365 ;
    RECT 544.03 0.42 544.2 315.365 ;
    RECT 543.275 0.42 543.45 315.365 ;
    RECT 542.225 0.42 542.695 315.365 ;
    RECT 540.115 0.42 541.645 315.365 ;
    RECT 539.06 0.42 539.535 315.365 ;
    RECT 538.31 0.42 538.48 315.365 ;
    RECT 537.535 0.42 537.73 315.365 ;
    RECT 536.38 0.42 536.955 315.365 ;
    RECT 535.63 0.42 535.8 315.365 ;
    RECT 534.875 0.42 535.05 315.365 ;
    RECT 533.825 0.42 534.295 315.365 ;
    RECT 531.715 0.42 533.245 315.365 ;
    RECT 530.66 0.42 531.135 315.365 ;
    RECT 529.91 0.42 530.08 315.365 ;
    RECT 529.135 0.42 529.33 315.365 ;
    RECT 527.98 0.42 528.555 315.365 ;
    RECT 527.23 0.42 527.4 315.365 ;
    RECT 526.475 0.42 526.65 315.365 ;
    RECT 525.425 0.42 525.895 315.365 ;
    RECT 523.315 0.42 524.845 315.365 ;
    RECT 522.26 0.42 522.735 315.365 ;
    RECT 521.51 0.42 521.68 315.365 ;
    RECT 520.735 0.42 520.93 315.365 ;
    RECT 519.58 0.42 520.155 315.365 ;
    RECT 518.83 0.42 519.0 315.365 ;
    RECT 518.075 0.42 518.25 315.365 ;
    RECT 517.025 0.42 517.495 315.365 ;
    RECT 514.915 0.42 516.445 315.365 ;
    RECT 513.86 0.42 514.335 315.365 ;
    RECT 513.11 0.42 513.28 315.365 ;
    RECT 512.335 0.42 512.53 315.365 ;
    RECT 511.18 0.42 511.755 315.365 ;
    RECT 510.43 0.42 510.6 315.365 ;
    RECT 509.675 0.42 509.85 315.365 ;
    RECT 508.625 0.42 509.095 315.365 ;
    RECT 506.515 0.42 508.045 315.365 ;
    RECT 505.46 0.42 505.935 315.365 ;
    RECT 504.71 0.42 504.88 315.365 ;
    RECT 503.935 0.42 504.13 315.365 ;
    RECT 502.78 0.42 503.355 315.365 ;
    RECT 502.03 0.42 502.2 315.365 ;
    RECT 501.275 0.42 501.45 315.365 ;
    RECT 500.225 0.42 500.695 315.365 ;
    RECT 498.115 0.42 499.645 315.365 ;
    RECT 497.06 0.42 497.535 315.365 ;
    RECT 496.31 0.42 496.48 315.365 ;
    RECT 495.535 0.42 495.73 315.365 ;
    RECT 494.38 0.42 494.955 315.365 ;
    RECT 493.63 0.42 493.8 315.365 ;
    RECT 492.875 0.42 493.05 315.365 ;
    RECT 491.825 0.42 492.295 315.365 ;
    RECT 489.715 0.42 491.245 315.365 ;
    RECT 488.66 0.42 489.135 315.365 ;
    RECT 487.91 0.42 488.08 315.365 ;
    RECT 487.135 0.42 487.33 315.365 ;
    RECT 485.98 0.42 486.555 315.365 ;
    RECT 485.23 0.42 485.4 315.365 ;
    RECT 484.475 0.42 484.65 315.365 ;
    RECT 483.425 0.42 483.895 315.365 ;
    RECT 481.315 0.42 482.845 315.365 ;
    RECT 480.26 0.42 480.735 315.365 ;
    RECT 479.51 0.42 479.68 315.365 ;
    RECT 478.735 0.42 478.93 315.365 ;
    RECT 477.58 0.42 478.155 315.365 ;
    RECT 476.83 0.42 477.0 315.365 ;
    RECT 476.075 0.42 476.25 315.365 ;
    RECT 475.025 0.42 475.495 315.365 ;
    RECT 472.915 0.42 474.445 315.365 ;
    RECT 471.86 0.42 472.335 315.365 ;
    RECT 471.11 0.42 471.28 315.365 ;
    RECT 470.335 0.42 470.53 315.365 ;
    RECT 469.18 0.42 469.755 315.365 ;
    RECT 468.43 0.42 468.6 315.365 ;
    RECT 467.675 0.42 467.85 315.365 ;
    RECT 466.625 0.42 467.095 315.365 ;
    RECT 464.515 0.42 466.045 315.365 ;
    RECT 463.46 0.42 463.935 315.365 ;
    RECT 462.71 0.42 462.88 315.365 ;
    RECT 461.935 0.42 462.13 315.365 ;
    RECT 460.78 0.42 461.355 315.365 ;
    RECT 460.03 0.42 460.2 315.365 ;
    RECT 459.275 0.42 459.45 315.365 ;
    RECT 458.225 0.42 458.695 315.365 ;
    RECT 456.115 0.42 457.645 315.365 ;
    RECT 455.06 0.42 455.535 315.365 ;
    RECT 454.31 0.42 454.48 315.365 ;
    RECT 453.535 0.42 453.73 315.365 ;
    RECT 452.38 0.42 452.955 315.365 ;
    RECT 451.63 0.42 451.8 315.365 ;
    RECT 450.875 0.42 451.05 315.365 ;
    RECT 449.825 0.42 450.295 315.365 ;
    RECT 447.715 0.42 449.245 315.365 ;
    RECT 446.66 0.42 447.135 315.365 ;
    RECT 445.91 0.42 446.08 315.365 ;
    RECT 445.135 0.42 445.33 315.365 ;
    RECT 443.98 0.42 444.555 315.365 ;
    RECT 443.23 0.42 443.4 315.365 ;
    RECT 442.475 0.42 442.65 315.365 ;
    RECT 441.425 0.42 441.895 315.365 ;
    RECT 439.315 0.42 440.845 315.365 ;
    RECT 438.26 0.42 438.735 315.365 ;
    RECT 437.51 0.42 437.68 315.365 ;
    RECT 436.735 0.42 436.93 315.365 ;
    RECT 435.58 0.42 436.155 315.365 ;
    RECT 434.83 0.42 435.0 315.365 ;
    RECT 434.075 0.42 434.25 315.365 ;
    RECT 433.025 0.42 433.495 315.365 ;
    RECT 430.915 0.42 432.445 315.365 ;
    RECT 429.86 0.42 430.335 315.365 ;
    RECT 429.11 0.42 429.28 315.365 ;
    RECT 428.335 0.42 428.53 315.365 ;
    RECT 427.18 0.42 427.755 315.365 ;
    RECT 426.43 0.42 426.6 315.365 ;
    RECT 425.675 0.42 425.85 315.365 ;
    RECT 424.625 0.42 425.095 315.365 ;
    RECT 422.515 0.42 424.045 315.365 ;
    RECT 421.46 0.42 421.935 315.365 ;
    RECT 420.71 0.42 420.88 315.365 ;
    RECT 419.935 0.42 420.13 315.365 ;
    RECT 418.78 0.42 419.355 315.365 ;
    RECT 418.03 0.42 418.2 315.365 ;
    RECT 417.275 0.42 417.45 315.365 ;
    RECT 416.225 0.42 416.695 315.365 ;
    RECT 414.115 0.42 415.645 315.365 ;
    RECT 413.06 0.42 413.535 315.365 ;
    RECT 412.31 0.42 412.48 315.365 ;
    RECT 411.535 0.42 411.73 315.365 ;
    RECT 410.38 0.42 410.955 315.365 ;
    RECT 409.63 0.42 409.8 315.365 ;
    RECT 408.875 0.42 409.05 315.365 ;
    RECT 407.825 0.42 408.295 315.365 ;
    RECT 405.715 0.42 407.245 315.365 ;
    RECT 404.66 0.42 405.135 315.365 ;
    RECT 403.91 0.42 404.08 315.365 ;
    RECT 403.135 0.42 403.33 315.365 ;
    RECT 401.98 0.42 402.555 315.365 ;
    RECT 401.23 0.42 401.4 315.365 ;
    RECT 400.475 0.42 400.65 315.365 ;
    RECT 399.425 0.42 399.895 315.365 ;
    RECT 397.315 0.42 398.845 315.365 ;
    RECT 396.26 0.42 396.735 315.365 ;
    RECT 395.51 0.42 395.68 315.365 ;
    RECT 394.735 0.42 394.93 315.365 ;
    RECT 393.58 0.42 394.155 315.365 ;
    RECT 392.83 0.42 393.0 315.365 ;
    RECT 392.075 0.42 392.25 315.365 ;
    RECT 391.025 0.42 391.495 315.365 ;
    RECT 388.915 0.42 390.445 315.365 ;
    RECT 387.86 0.42 388.335 315.365 ;
    RECT 387.11 0.42 387.28 315.365 ;
    RECT 386.335 0.42 386.53 315.365 ;
    RECT 385.18 0.42 385.755 315.365 ;
    RECT 384.43 0.42 384.6 315.365 ;
    RECT 383.675 0.42 383.85 315.365 ;
    RECT 382.625 0.42 383.095 315.365 ;
    RECT 380.515 0.42 382.045 315.365 ;
    RECT 379.46 0.42 379.935 315.365 ;
    RECT 378.71 0.42 378.88 315.365 ;
    RECT 377.935 0.42 378.13 315.365 ;
    RECT 376.78 0.42 377.355 315.365 ;
    RECT 376.03 0.42 376.2 315.365 ;
    RECT 375.275 0.42 375.45 315.365 ;
    RECT 374.225 0.42 374.695 315.365 ;
    RECT 372.115 0.42 373.645 315.365 ;
    RECT 371.06 0.42 371.535 315.365 ;
    RECT 370.31 0.42 370.48 315.365 ;
    RECT 369.535 0.42 369.73 315.365 ;
    RECT 368.38 0.42 368.955 315.365 ;
    RECT 367.63 0.42 367.8 315.365 ;
    RECT 366.875 0.42 367.05 315.365 ;
    RECT 365.825 0.42 366.295 315.365 ;
    RECT 363.715 0.42 365.245 315.365 ;
    RECT 362.66 0.42 363.135 315.365 ;
    RECT 361.91 0.42 362.08 315.365 ;
    RECT 361.135 0.42 361.33 315.365 ;
    RECT 359.98 0.42 360.555 315.365 ;
    RECT 359.23 0.42 359.4 315.365 ;
    RECT 358.475 0.42 358.65 315.365 ;
    RECT 357.425 0.42 357.895 315.365 ;
    RECT 355.315 0.42 356.845 315.365 ;
    RECT 354.26 0.42 354.735 315.365 ;
    RECT 353.51 0.42 353.68 315.365 ;
    RECT 352.735 0.42 352.93 315.365 ;
    RECT 351.58 0.42 352.155 315.365 ;
    RECT 350.83 0.42 351.0 315.365 ;
    RECT 350.075 0.42 350.25 315.365 ;
    RECT 349.025 0.42 349.495 315.365 ;
    RECT 346.915 0.42 348.445 315.365 ;
    RECT 345.86 0.42 346.335 315.365 ;
    RECT 345.11 0.42 345.28 315.365 ;
    RECT 344.335 0.42 344.53 315.365 ;
    RECT 343.18 0.42 343.755 315.365 ;
    RECT 342.43 0.42 342.6 315.365 ;
    RECT 341.675 0.42 341.85 315.365 ;
    RECT 340.625 0.42 341.095 315.365 ;
    RECT 338.515 0.42 340.045 315.365 ;
    RECT 337.46 0.42 337.935 315.365 ;
    RECT 336.71 0.42 336.88 315.365 ;
    RECT 335.935 0.42 336.13 315.365 ;
    RECT 333.79 0.42 335.355 315.365 ;
    RECT 332.465 0.42 333.05 315.365 ;
    RECT 331.145 0.42 331.725 315.365 ;
    RECT 329.82 0.42 330.405 315.365 ;
    RECT 327.165 0.42 327.75 315.365 ;
    RECT 325.84 0.42 326.425 315.365 ;
    RECT 324.525 0.42 325.1 315.365 ;
    RECT 323.48 0.42 323.785 315.365 ;
    RECT 322.45 0.42 322.74 315.365 ;
    RECT 321.13 0.42 321.71 315.365 ;
    RECT 319.795 0.42 320.39 315.365 ;
    RECT 317.74 0.42 319.055 315.365 ;
    RECT 315.825 0.42 316.41 315.365 ;
    RECT 314.5 0.42 315.085 315.365 ;
    RECT 313.18 0.42 313.76 315.365 ;
    RECT 311.855 0.42 312.44 315.365 ;
    RECT 309.21 0.42 311.115 315.365 ;
    RECT 307.705 0.42 308.47 315.365 ;
    RECT 303.975 0.42 306.965 315.365 ;
    RECT 300.36 0.42 303.405 315.365 ;
    RECT 299.255 0.42 299.62 315.365 ;
    RECT 296.575 0.42 297.13 315.365 ;
    RECT 295.27 0.42 295.835 315.365 ;
    RECT 293.965 0.42 294.53 315.365 ;
    RECT 291.91 0.42 293.225 315.365 ;
    RECT 290.06 0.42 290.625 315.365 ;
    RECT 288.765 0.42 289.32 315.365 ;
    RECT 284.81 0.42 288.025 315.365 ;
    RECT 282.67 0.42 284.24 315.365 ;
    RECT 281.28 0.42 281.93 315.365 ;
    RECT 280.02 0.42 280.71 315.365 ;
    RECT 278.695 0.42 279.28 315.365 ;
    RECT 277.375 0.42 277.955 315.365 ;
    RECT 274.73 0.42 275.31 315.365 ;
    RECT 273.415 0.42 273.99 315.365 ;
    RECT 272.085 0.42 272.665 315.365 ;
    RECT 269.78 0.42 271.335 315.365 ;
    RECT 269.03 0.42 269.2 315.365 ;
    RECT 268.275 0.42 268.45 315.365 ;
    RECT 267.225 0.42 267.695 315.365 ;
    RECT 265.115 0.42 266.645 315.365 ;
    RECT 264.06 0.42 264.535 315.365 ;
    RECT 263.31 0.42 263.48 315.365 ;
    RECT 262.535 0.42 262.73 315.365 ;
    RECT 261.38 0.42 261.955 315.365 ;
    RECT 260.63 0.42 260.8 315.365 ;
    RECT 259.875 0.42 260.05 315.365 ;
    RECT 258.825 0.42 259.295 315.365 ;
    RECT 256.715 0.42 258.245 315.365 ;
    RECT 255.66 0.42 256.135 315.365 ;
    RECT 254.91 0.42 255.08 315.365 ;
    RECT 254.135 0.42 254.33 315.365 ;
    RECT 252.98 0.42 253.555 315.365 ;
    RECT 252.23 0.42 252.4 315.365 ;
    RECT 251.475 0.42 251.65 315.365 ;
    RECT 250.425 0.42 250.895 315.365 ;
    RECT 248.315 0.42 249.845 315.365 ;
    RECT 247.26 0.42 247.735 315.365 ;
    RECT 246.51 0.42 246.68 315.365 ;
    RECT 245.735 0.42 245.93 315.365 ;
    RECT 244.58 0.42 245.155 315.365 ;
    RECT 243.83 0.42 244.0 315.365 ;
    RECT 243.075 0.42 243.25 315.365 ;
    RECT 242.025 0.42 242.495 315.365 ;
    RECT 239.915 0.42 241.445 315.365 ;
    RECT 238.86 0.42 239.335 315.365 ;
    RECT 238.11 0.42 238.28 315.365 ;
    RECT 237.335 0.42 237.53 315.365 ;
    RECT 236.18 0.42 236.755 315.365 ;
    RECT 235.43 0.42 235.6 315.365 ;
    RECT 234.675 0.42 234.85 315.365 ;
    RECT 233.625 0.42 234.095 315.365 ;
    RECT 231.515 0.42 233.045 315.365 ;
    RECT 230.46 0.42 230.935 315.365 ;
    RECT 229.71 0.42 229.88 315.365 ;
    RECT 228.935 0.42 229.13 315.365 ;
    RECT 227.78 0.42 228.355 315.365 ;
    RECT 227.03 0.42 227.2 315.365 ;
    RECT 226.275 0.42 226.45 315.365 ;
    RECT 225.225 0.42 225.695 315.365 ;
    RECT 223.115 0.42 224.645 315.365 ;
    RECT 222.06 0.42 222.535 315.365 ;
    RECT 221.31 0.42 221.48 315.365 ;
    RECT 220.535 0.42 220.73 315.365 ;
    RECT 219.38 0.42 219.955 315.365 ;
    RECT 218.63 0.42 218.8 315.365 ;
    RECT 217.875 0.42 218.05 315.365 ;
    RECT 216.825 0.42 217.295 315.365 ;
    RECT 214.715 0.42 216.245 315.365 ;
    RECT 213.66 0.42 214.135 315.365 ;
    RECT 212.91 0.42 213.08 315.365 ;
    RECT 212.135 0.42 212.33 315.365 ;
    RECT 210.98 0.42 211.555 315.365 ;
    RECT 210.23 0.42 210.4 315.365 ;
    RECT 209.475 0.42 209.65 315.365 ;
    RECT 208.425 0.42 208.895 315.365 ;
    RECT 206.315 0.42 207.845 315.365 ;
    RECT 205.26 0.42 205.735 315.365 ;
    RECT 204.51 0.42 204.68 315.365 ;
    RECT 203.735 0.42 203.93 315.365 ;
    RECT 202.58 0.42 203.155 315.365 ;
    RECT 201.83 0.42 202.0 315.365 ;
    RECT 201.075 0.42 201.25 315.365 ;
    RECT 200.025 0.42 200.495 315.365 ;
    RECT 197.915 0.42 199.445 315.365 ;
    RECT 196.86 0.42 197.335 315.365 ;
    RECT 196.11 0.42 196.28 315.365 ;
    RECT 195.335 0.42 195.53 315.365 ;
    RECT 194.18 0.42 194.755 315.365 ;
    RECT 193.43 0.42 193.6 315.365 ;
    RECT 192.675 0.42 192.85 315.365 ;
    RECT 191.625 0.42 192.095 315.365 ;
    RECT 189.515 0.42 191.045 315.365 ;
    RECT 188.46 0.42 188.935 315.365 ;
    RECT 187.71 0.42 187.88 315.365 ;
    RECT 186.935 0.42 187.13 315.365 ;
    RECT 185.78 0.42 186.355 315.365 ;
    RECT 185.03 0.42 185.2 315.365 ;
    RECT 184.275 0.42 184.45 315.365 ;
    RECT 183.225 0.42 183.695 315.365 ;
    RECT 181.115 0.42 182.645 315.365 ;
    RECT 180.06 0.42 180.535 315.365 ;
    RECT 179.31 0.42 179.48 315.365 ;
    RECT 178.535 0.42 178.73 315.365 ;
    RECT 177.38 0.42 177.955 315.365 ;
    RECT 176.63 0.42 176.8 315.365 ;
    RECT 175.875 0.42 176.05 315.365 ;
    RECT 174.825 0.42 175.295 315.365 ;
    RECT 172.715 0.42 174.245 315.365 ;
    RECT 171.66 0.42 172.135 315.365 ;
    RECT 170.91 0.42 171.08 315.365 ;
    RECT 170.135 0.42 170.33 315.365 ;
    RECT 168.98 0.42 169.555 315.365 ;
    RECT 168.23 0.42 168.4 315.365 ;
    RECT 167.475 0.42 167.65 315.365 ;
    RECT 166.425 0.42 166.895 315.365 ;
    RECT 164.315 0.42 165.845 315.365 ;
    RECT 163.26 0.42 163.735 315.365 ;
    RECT 162.51 0.42 162.68 315.365 ;
    RECT 161.735 0.42 161.93 315.365 ;
    RECT 160.58 0.42 161.155 315.365 ;
    RECT 159.83 0.42 160.0 315.365 ;
    RECT 159.075 0.42 159.25 315.365 ;
    RECT 158.025 0.42 158.495 315.365 ;
    RECT 155.915 0.42 157.445 315.365 ;
    RECT 154.86 0.42 155.335 315.365 ;
    RECT 154.11 0.42 154.28 315.365 ;
    RECT 153.335 0.42 153.53 315.365 ;
    RECT 152.18 0.42 152.755 315.365 ;
    RECT 151.43 0.42 151.6 315.365 ;
    RECT 150.675 0.42 150.85 315.365 ;
    RECT 149.625 0.42 150.095 315.365 ;
    RECT 147.515 0.42 149.045 315.365 ;
    RECT 146.46 0.42 146.935 315.365 ;
    RECT 145.71 0.42 145.88 315.365 ;
    RECT 144.935 0.42 145.13 315.365 ;
    RECT 143.78 0.42 144.355 315.365 ;
    RECT 143.03 0.42 143.2 315.365 ;
    RECT 142.275 0.42 142.45 315.365 ;
    RECT 141.225 0.42 141.695 315.365 ;
    RECT 139.115 0.42 140.645 315.365 ;
    RECT 138.06 0.42 138.535 315.365 ;
    RECT 137.31 0.42 137.48 315.365 ;
    RECT 136.535 0.42 136.73 315.365 ;
    RECT 135.38 0.42 135.955 315.365 ;
    RECT 134.63 0.42 134.8 315.365 ;
    RECT 133.875 0.42 134.05 315.365 ;
    RECT 132.825 0.42 133.295 315.365 ;
    RECT 130.715 0.42 132.245 315.365 ;
    RECT 129.66 0.42 130.135 315.365 ;
    RECT 128.91 0.42 129.08 315.365 ;
    RECT 128.135 0.42 128.33 315.365 ;
    RECT 126.98 0.42 127.555 315.365 ;
    RECT 126.23 0.42 126.4 315.365 ;
    RECT 125.475 0.42 125.65 315.365 ;
    RECT 124.425 0.42 124.895 315.365 ;
    RECT 122.315 0.42 123.845 315.365 ;
    RECT 121.26 0.42 121.735 315.365 ;
    RECT 120.51 0.42 120.68 315.365 ;
    RECT 119.735 0.42 119.93 315.365 ;
    RECT 118.58 0.42 119.155 315.365 ;
    RECT 117.83 0.42 118.0 315.365 ;
    RECT 117.075 0.42 117.25 315.365 ;
    RECT 116.025 0.42 116.495 315.365 ;
    RECT 113.915 0.42 115.445 315.365 ;
    RECT 112.86 0.42 113.335 315.365 ;
    RECT 112.11 0.42 112.28 315.365 ;
    RECT 111.335 0.42 111.53 315.365 ;
    RECT 110.18 0.42 110.755 315.365 ;
    RECT 109.43 0.42 109.6 315.365 ;
    RECT 108.675 0.42 108.85 315.365 ;
    RECT 107.625 0.42 108.095 315.365 ;
    RECT 105.515 0.42 107.045 315.365 ;
    RECT 104.46 0.42 104.935 315.365 ;
    RECT 103.71 0.42 103.88 315.365 ;
    RECT 102.935 0.42 103.13 315.365 ;
    RECT 101.78 0.42 102.355 315.365 ;
    RECT 101.03 0.42 101.2 315.365 ;
    RECT 100.275 0.42 100.45 315.365 ;
    RECT 99.225 0.42 99.695 315.365 ;
    RECT 97.115 0.42 98.645 315.365 ;
    RECT 96.06 0.42 96.535 315.365 ;
    RECT 95.31 0.42 95.48 315.365 ;
    RECT 94.535 0.42 94.73 315.365 ;
    RECT 93.38 0.42 93.955 315.365 ;
    RECT 92.63 0.42 92.8 315.365 ;
    RECT 91.875 0.42 92.05 315.365 ;
    RECT 90.825 0.42 91.295 315.365 ;
    RECT 88.715 0.42 90.245 315.365 ;
    RECT 87.66 0.42 88.135 315.365 ;
    RECT 86.91 0.42 87.08 315.365 ;
    RECT 86.135 0.42 86.33 315.365 ;
    RECT 84.98 0.42 85.555 315.365 ;
    RECT 84.23 0.42 84.4 315.365 ;
    RECT 83.475 0.42 83.65 315.365 ;
    RECT 82.425 0.42 82.895 315.365 ;
    RECT 80.315 0.42 81.845 315.365 ;
    RECT 79.26 0.42 79.735 315.365 ;
    RECT 78.51 0.42 78.68 315.365 ;
    RECT 77.735 0.42 77.93 315.365 ;
    RECT 76.58 0.42 77.155 315.365 ;
    RECT 75.83 0.42 76.0 315.365 ;
    RECT 75.075 0.42 75.25 315.365 ;
    RECT 74.025 0.42 74.495 315.365 ;
    RECT 71.915 0.42 73.445 315.365 ;
    RECT 70.86 0.42 71.335 315.365 ;
    RECT 70.11 0.42 70.28 315.365 ;
    RECT 69.335 0.42 69.53 315.365 ;
    RECT 68.18 0.42 68.755 315.365 ;
    RECT 67.43 0.42 67.6 315.365 ;
    RECT 66.675 0.42 66.85 315.365 ;
    RECT 65.625 0.42 66.095 315.365 ;
    RECT 63.515 0.42 65.045 315.365 ;
    RECT 62.46 0.42 62.935 315.365 ;
    RECT 61.71 0.42 61.88 315.365 ;
    RECT 60.935 0.42 61.13 315.365 ;
    RECT 59.78 0.42 60.355 315.365 ;
    RECT 59.03 0.42 59.2 315.365 ;
    RECT 58.275 0.42 58.45 315.365 ;
    RECT 57.225 0.42 57.695 315.365 ;
    RECT 55.115 0.42 56.645 315.365 ;
    RECT 54.06 0.42 54.535 315.365 ;
    RECT 53.31 0.42 53.48 315.365 ;
    RECT 52.535 0.42 52.73 315.365 ;
    RECT 51.38 0.42 51.955 315.365 ;
    RECT 50.63 0.42 50.8 315.365 ;
    RECT 49.875 0.42 50.05 315.365 ;
    RECT 48.825 0.42 49.295 315.365 ;
    RECT 46.715 0.42 48.245 315.365 ;
    RECT 45.66 0.42 46.135 315.365 ;
    RECT 44.91 0.42 45.08 315.365 ;
    RECT 44.135 0.42 44.33 315.365 ;
    RECT 42.98 0.42 43.555 315.365 ;
    RECT 42.23 0.42 42.4 315.365 ;
    RECT 41.475 0.42 41.65 315.365 ;
    RECT 40.425 0.42 40.895 315.365 ;
    RECT 38.315 0.42 39.845 315.365 ;
    RECT 37.26 0.42 37.735 315.365 ;
    RECT 36.51 0.42 36.68 315.365 ;
    RECT 35.735 0.42 35.93 315.365 ;
    RECT 34.58 0.42 35.155 315.365 ;
    RECT 33.83 0.42 34.0 315.365 ;
    RECT 33.075 0.42 33.25 315.365 ;
    RECT 32.025 0.42 32.495 315.365 ;
    RECT 29.915 0.42 31.445 315.365 ;
    RECT 28.86 0.42 29.335 315.365 ;
    RECT 28.11 0.42 28.28 315.365 ;
    RECT 27.335 0.42 27.53 315.365 ;
    RECT 26.18 0.42 26.755 315.365 ;
    RECT 25.43 0.42 25.6 315.365 ;
    RECT 24.675 0.42 24.85 315.365 ;
    RECT 23.625 0.42 24.095 315.365 ;
    RECT 21.515 0.42 23.045 315.365 ;
    RECT 20.46 0.42 20.935 315.365 ;
    RECT 19.71 0.42 19.88 315.365 ;
    RECT 18.935 0.42 19.13 315.365 ;
    RECT 17.78 0.42 18.355 315.365 ;
    RECT 17.03 0.42 17.2 315.365 ;
    RECT 16.275 0.42 16.45 315.365 ;
    RECT 15.225 0.42 15.695 315.365 ;
    RECT 13.115 0.42 14.645 315.365 ;
    RECT 12.06 0.42 12.535 315.365 ;
    RECT 11.31 0.42 11.48 315.365 ;
    RECT 10.535 0.42 10.73 315.365 ;
    RECT 9.38 0.42 9.955 315.365 ;
    RECT 8.63 0.42 8.8 315.365 ;
    RECT 7.875 0.42 8.05 315.365 ;
    RECT 6.825 0.42 7.295 315.365 ;
    RECT 4.715 0.42 6.245 315.365 ;
    RECT 3.66 0.42 4.135 315.365 ;
    RECT 2.91 0.42 3.08 315.365 ;
    RECT 2.135 0.42 2.33 315.365 ;
    RECT 1.25 0.42 1.555 315.365 ;
    END
  END s8192x64

END LIBRARY

